VERSION 5.8 ;
BUSBITCHARS "[]" ;
DIVIDERCHAR "/" ;
UNITS
    DATABASE MICRONS 1000 ;
END UNITS

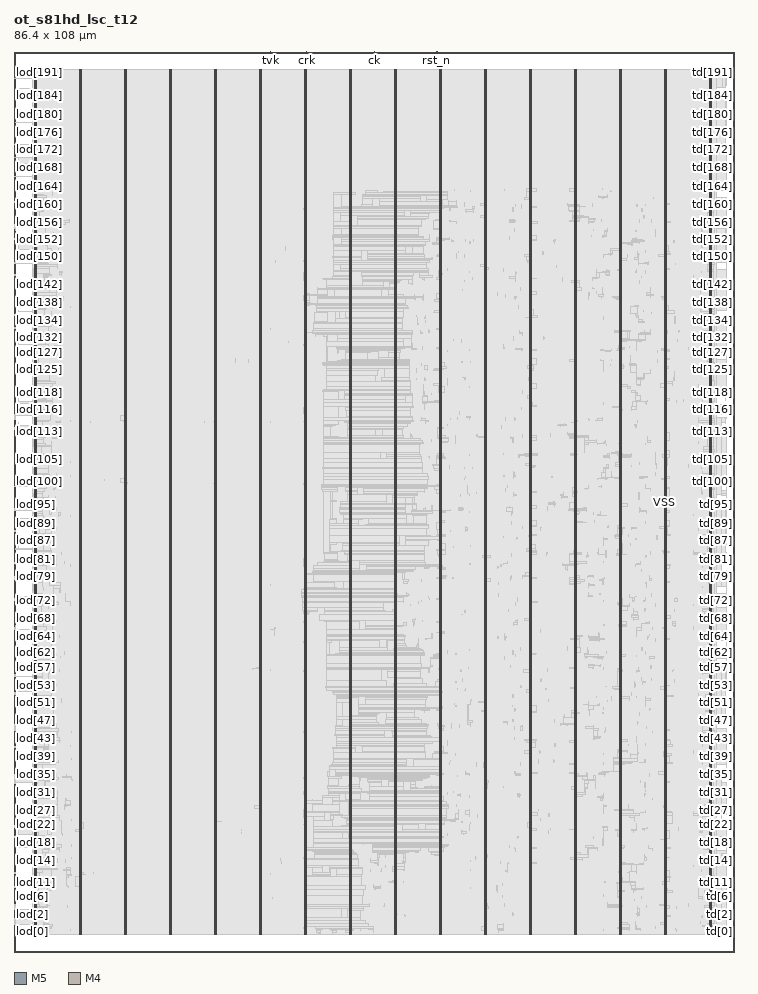
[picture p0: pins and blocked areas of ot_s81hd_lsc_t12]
MACRO ot_s81hd_lsc_t12
  FOREIGN ot_s81hd_lsc_t12 0 0 ;
  CLASS BLOCK ;
  SIZE 86.4 BY 108 ;
  PIN ck
    DIRECTION INPUT ;
    USE SIGNAL ;
    PORT
      LAYER M5 ;
        RECT  43.2 107.916 43.224 108 ;
    END
  END ck
  PIN crk
    DIRECTION INPUT ;
    USE SIGNAL ;
    PORT
      LAYER M5 ;
        RECT  35.088 107.916 35.112 108 ;
    END
  END crk
  PIN lod[0]
    DIRECTION OUTPUT ;
    USE SIGNAL ;
    PORT
      LAYER M4 ;
        RECT  0 2.4 0.084 2.424 ;
    END
  END lod[0]
  PIN lod[100]
    DIRECTION OUTPUT ;
    USE SIGNAL ;
    PORT
      LAYER M4 ;
        RECT  0 56.4 0.084 56.424 ;
    END
  END lod[100]
  PIN lod[101]
    DIRECTION OUTPUT ;
    USE SIGNAL ;
    PORT
      LAYER M4 ;
        RECT  0 56.976 0.084 57 ;
    END
  END lod[101]
  PIN lod[102]
    DIRECTION OUTPUT ;
    USE SIGNAL ;
    PORT
      LAYER M4 ;
        RECT  0 57.504 0.084 57.528 ;
    END
  END lod[102]
  PIN lod[103]
    DIRECTION OUTPUT ;
    USE SIGNAL ;
    PORT
      LAYER M4 ;
        RECT  0 58.032 0.084 58.056 ;
    END
  END lod[103]
  PIN lod[104]
    DIRECTION OUTPUT ;
    USE SIGNAL ;
    PORT
      LAYER M4 ;
        RECT  0 58.56 0.084 58.584 ;
    END
  END lod[104]
  PIN lod[105]
    DIRECTION OUTPUT ;
    USE SIGNAL ;
    PORT
      LAYER M4 ;
        RECT  0 59.136 0.084 59.16 ;
    END
  END lod[105]
  PIN lod[106]
    DIRECTION OUTPUT ;
    USE SIGNAL ;
    PORT
      LAYER M4 ;
        RECT  0 59.664 0.084 59.688 ;
    END
  END lod[106]
  PIN lod[107]
    DIRECTION OUTPUT ;
    USE SIGNAL ;
    PORT
      LAYER M4 ;
        RECT  0 60.192 0.084 60.216 ;
    END
  END lod[107]
  PIN lod[108]
    DIRECTION OUTPUT ;
    USE SIGNAL ;
    PORT
      LAYER M4 ;
        RECT  0 60.72 0.084 60.744 ;
    END
  END lod[108]
  PIN lod[109]
    DIRECTION OUTPUT ;
    USE SIGNAL ;
    PORT
      LAYER M4 ;
        RECT  0 61.296 0.084 61.32 ;
    END
  END lod[109]
  PIN lod[10]
    DIRECTION OUTPUT ;
    USE SIGNAL ;
    PORT
      LAYER M4 ;
        RECT  0 7.824 0.084 7.848 ;
    END
  END lod[10]
  PIN lod[110]
    DIRECTION OUTPUT ;
    USE SIGNAL ;
    PORT
      LAYER M4 ;
        RECT  0 61.824 0.084 61.848 ;
    END
  END lod[110]
  PIN lod[111]
    DIRECTION OUTPUT ;
    USE SIGNAL ;
    PORT
      LAYER M4 ;
        RECT  0 62.352 0.084 62.376 ;
    END
  END lod[111]
  PIN lod[112]
    DIRECTION OUTPUT ;
    USE SIGNAL ;
    PORT
      LAYER M4 ;
        RECT  0 62.88 0.084 62.904 ;
    END
  END lod[112]
  PIN lod[113]
    DIRECTION OUTPUT ;
    USE SIGNAL ;
    PORT
      LAYER M4 ;
        RECT  0 63.456 0.084 63.48 ;
    END
  END lod[113]
  PIN lod[114]
    DIRECTION OUTPUT ;
    USE SIGNAL ;
    PORT
      LAYER M4 ;
        RECT  0 63.984 0.084 64.008 ;
    END
  END lod[114]
  PIN lod[115]
    DIRECTION OUTPUT ;
    USE SIGNAL ;
    PORT
      LAYER M4 ;
        RECT  0 64.512 0.084 64.536 ;
    END
  END lod[115]
  PIN lod[116]
    DIRECTION OUTPUT ;
    USE SIGNAL ;
    PORT
      LAYER M4 ;
        RECT  0 65.04 0.084 65.064 ;
    END
  END lod[116]
  PIN lod[117]
    DIRECTION OUTPUT ;
    USE SIGNAL ;
    PORT
      LAYER M4 ;
        RECT  0 65.616 0.084 65.64 ;
    END
  END lod[117]
  PIN lod[118]
    DIRECTION OUTPUT ;
    USE SIGNAL ;
    PORT
      LAYER M4 ;
        RECT  0 66.144 0.084 66.168 ;
    END
  END lod[118]
  PIN lod[119]
    DIRECTION OUTPUT ;
    USE SIGNAL ;
    PORT
      LAYER M4 ;
        RECT  0 66.672 0.084 66.696 ;
    END
  END lod[119]
  PIN lod[11]
    DIRECTION OUTPUT ;
    USE SIGNAL ;
    PORT
      LAYER M4 ;
        RECT  0 8.352 0.084 8.376 ;
    END
  END lod[11]
  PIN lod[120]
    DIRECTION OUTPUT ;
    USE SIGNAL ;
    PORT
      LAYER M4 ;
        RECT  0 67.2 0.084 67.224 ;
    END
  END lod[120]
  PIN lod[121]
    DIRECTION OUTPUT ;
    USE SIGNAL ;
    PORT
      LAYER M4 ;
        RECT  0 67.776 0.084 67.8 ;
    END
  END lod[121]
  PIN lod[122]
    DIRECTION OUTPUT ;
    USE SIGNAL ;
    PORT
      LAYER M4 ;
        RECT  0 68.304 0.084 68.328 ;
    END
  END lod[122]
  PIN lod[123]
    DIRECTION OUTPUT ;
    USE SIGNAL ;
    PORT
      LAYER M4 ;
        RECT  0 68.832 0.084 68.856 ;
    END
  END lod[123]
  PIN lod[124]
    DIRECTION OUTPUT ;
    USE SIGNAL ;
    PORT
      LAYER M4 ;
        RECT  0 69.36 0.084 69.384 ;
    END
  END lod[124]
  PIN lod[125]
    DIRECTION OUTPUT ;
    USE SIGNAL ;
    PORT
      LAYER M4 ;
        RECT  0 69.936 0.084 69.96 ;
    END
  END lod[125]
  PIN lod[126]
    DIRECTION OUTPUT ;
    USE SIGNAL ;
    PORT
      LAYER M4 ;
        RECT  0 70.464 0.084 70.488 ;
    END
  END lod[126]
  PIN lod[127]
    DIRECTION OUTPUT ;
    USE SIGNAL ;
    PORT
      LAYER M4 ;
        RECT  0 70.992 0.084 71.016 ;
    END
  END lod[127]
  PIN lod[128]
    DIRECTION OUTPUT ;
    USE SIGNAL ;
    PORT
      LAYER M4 ;
        RECT  0 71.52 0.084 71.544 ;
    END
  END lod[128]
  PIN lod[129]
    DIRECTION OUTPUT ;
    USE SIGNAL ;
    PORT
      LAYER M4 ;
        RECT  0 72.096 0.084 72.12 ;
    END
  END lod[129]
  PIN lod[12]
    DIRECTION OUTPUT ;
    USE SIGNAL ;
    PORT
      LAYER M4 ;
        RECT  0 8.88 0.084 8.904 ;
    END
  END lod[12]
  PIN lod[130]
    DIRECTION OUTPUT ;
    USE SIGNAL ;
    PORT
      LAYER M4 ;
        RECT  0 72.624 0.084 72.648 ;
    END
  END lod[130]
  PIN lod[131]
    DIRECTION OUTPUT ;
    USE SIGNAL ;
    PORT
      LAYER M4 ;
        RECT  0 73.152 0.084 73.176 ;
    END
  END lod[131]
  PIN lod[132]
    DIRECTION OUTPUT ;
    USE SIGNAL ;
    PORT
      LAYER M4 ;
        RECT  0 73.68 0.084 73.704 ;
    END
  END lod[132]
  PIN lod[133]
    DIRECTION OUTPUT ;
    USE SIGNAL ;
    PORT
      LAYER M4 ;
        RECT  0 74.256 0.084 74.28 ;
    END
  END lod[133]
  PIN lod[134]
    DIRECTION OUTPUT ;
    USE SIGNAL ;
    PORT
      LAYER M4 ;
        RECT  0 74.784 0.084 74.808 ;
    END
  END lod[134]
  PIN lod[135]
    DIRECTION OUTPUT ;
    USE SIGNAL ;
    PORT
      LAYER M4 ;
        RECT  0 75.312 0.084 75.336 ;
    END
  END lod[135]
  PIN lod[136]
    DIRECTION OUTPUT ;
    USE SIGNAL ;
    PORT
      LAYER M4 ;
        RECT  0 75.84 0.084 75.864 ;
    END
  END lod[136]
  PIN lod[137]
    DIRECTION OUTPUT ;
    USE SIGNAL ;
    PORT
      LAYER M4 ;
        RECT  0 76.416 0.084 76.44 ;
    END
  END lod[137]
  PIN lod[138]
    DIRECTION OUTPUT ;
    USE SIGNAL ;
    PORT
      LAYER M4 ;
        RECT  0 76.944 0.084 76.968 ;
    END
  END lod[138]
  PIN lod[139]
    DIRECTION OUTPUT ;
    USE SIGNAL ;
    PORT
      LAYER M4 ;
        RECT  0 77.472 0.084 77.496 ;
    END
  END lod[139]
  PIN lod[13]
    DIRECTION OUTPUT ;
    USE SIGNAL ;
    PORT
      LAYER M4 ;
        RECT  0 9.456 0.084 9.48 ;
    END
  END lod[13]
  PIN lod[140]
    DIRECTION OUTPUT ;
    USE SIGNAL ;
    PORT
      LAYER M4 ;
        RECT  0 78 0.084 78.024 ;
    END
  END lod[140]
  PIN lod[141]
    DIRECTION OUTPUT ;
    USE SIGNAL ;
    PORT
      LAYER M4 ;
        RECT  0 78.576 0.084 78.6 ;
    END
  END lod[141]
  PIN lod[142]
    DIRECTION OUTPUT ;
    USE SIGNAL ;
    PORT
      LAYER M4 ;
        RECT  0 79.104 0.084 79.128 ;
    END
  END lod[142]
  PIN lod[143]
    DIRECTION OUTPUT ;
    USE SIGNAL ;
    PORT
      LAYER M4 ;
        RECT  0 79.632 0.084 79.656 ;
    END
  END lod[143]
  PIN lod[144]
    DIRECTION OUTPUT ;
    USE SIGNAL ;
    PORT
      LAYER M4 ;
        RECT  0 80.16 0.084 80.184 ;
    END
  END lod[144]
  PIN lod[145]
    DIRECTION OUTPUT ;
    USE SIGNAL ;
    PORT
      LAYER M4 ;
        RECT  0 80.736 0.084 80.76 ;
    END
  END lod[145]
  PIN lod[146]
    DIRECTION OUTPUT ;
    USE SIGNAL ;
    PORT
      LAYER M4 ;
        RECT  0 81.264 0.084 81.288 ;
    END
  END lod[146]
  PIN lod[147]
    DIRECTION OUTPUT ;
    USE SIGNAL ;
    PORT
      LAYER M4 ;
        RECT  0 81.792 0.084 81.816 ;
    END
  END lod[147]
  PIN lod[148]
    DIRECTION OUTPUT ;
    USE SIGNAL ;
    PORT
      LAYER M4 ;
        RECT  0 82.32 0.084 82.344 ;
    END
  END lod[148]
  PIN lod[149]
    DIRECTION OUTPUT ;
    USE SIGNAL ;
    PORT
      LAYER M4 ;
        RECT  0 82.896 0.084 82.92 ;
    END
  END lod[149]
  PIN lod[14]
    DIRECTION OUTPUT ;
    USE SIGNAL ;
    PORT
      LAYER M4 ;
        RECT  0 9.984 0.084 10.008 ;
    END
  END lod[14]
  PIN lod[150]
    DIRECTION OUTPUT ;
    USE SIGNAL ;
    PORT
      LAYER M4 ;
        RECT  0 83.424 0.084 83.448 ;
    END
  END lod[150]
  PIN lod[151]
    DIRECTION OUTPUT ;
    USE SIGNAL ;
    PORT
      LAYER M4 ;
        RECT  0 83.952 0.084 83.976 ;
    END
  END lod[151]
  PIN lod[152]
    DIRECTION OUTPUT ;
    USE SIGNAL ;
    PORT
      LAYER M4 ;
        RECT  0 84.48 0.084 84.504 ;
    END
  END lod[152]
  PIN lod[153]
    DIRECTION OUTPUT ;
    USE SIGNAL ;
    PORT
      LAYER M4 ;
        RECT  0 85.056 0.084 85.08 ;
    END
  END lod[153]
  PIN lod[154]
    DIRECTION OUTPUT ;
    USE SIGNAL ;
    PORT
      LAYER M4 ;
        RECT  0 85.584 0.084 85.608 ;
    END
  END lod[154]
  PIN lod[155]
    DIRECTION OUTPUT ;
    USE SIGNAL ;
    PORT
      LAYER M4 ;
        RECT  0 86.112 0.084 86.136 ;
    END
  END lod[155]
  PIN lod[156]
    DIRECTION OUTPUT ;
    USE SIGNAL ;
    PORT
      LAYER M4 ;
        RECT  0 86.64 0.084 86.664 ;
    END
  END lod[156]
  PIN lod[157]
    DIRECTION OUTPUT ;
    USE SIGNAL ;
    PORT
      LAYER M4 ;
        RECT  0 87.216 0.084 87.24 ;
    END
  END lod[157]
  PIN lod[158]
    DIRECTION OUTPUT ;
    USE SIGNAL ;
    PORT
      LAYER M4 ;
        RECT  0 87.744 0.084 87.768 ;
    END
  END lod[158]
  PIN lod[159]
    DIRECTION OUTPUT ;
    USE SIGNAL ;
    PORT
      LAYER M4 ;
        RECT  0 88.272 0.084 88.296 ;
    END
  END lod[159]
  PIN lod[15]
    DIRECTION OUTPUT ;
    USE SIGNAL ;
    PORT
      LAYER M4 ;
        RECT  0 10.512 0.084 10.536 ;
    END
  END lod[15]
  PIN lod[160]
    DIRECTION OUTPUT ;
    USE SIGNAL ;
    PORT
      LAYER M4 ;
        RECT  0 88.8 0.084 88.824 ;
    END
  END lod[160]
  PIN lod[161]
    DIRECTION OUTPUT ;
    USE SIGNAL ;
    PORT
      LAYER M4 ;
        RECT  0 89.376 0.084 89.4 ;
    END
  END lod[161]
  PIN lod[162]
    DIRECTION OUTPUT ;
    USE SIGNAL ;
    PORT
      LAYER M4 ;
        RECT  0 89.904 0.084 89.928 ;
    END
  END lod[162]
  PIN lod[163]
    DIRECTION OUTPUT ;
    USE SIGNAL ;
    PORT
      LAYER M4 ;
        RECT  0 90.432 0.084 90.456 ;
    END
  END lod[163]
  PIN lod[164]
    DIRECTION OUTPUT ;
    USE SIGNAL ;
    PORT
      LAYER M4 ;
        RECT  0 90.96 0.084 90.984 ;
    END
  END lod[164]
  PIN lod[165]
    DIRECTION OUTPUT ;
    USE SIGNAL ;
    PORT
      LAYER M4 ;
        RECT  0 91.536 0.084 91.56 ;
    END
  END lod[165]
  PIN lod[166]
    DIRECTION OUTPUT ;
    USE SIGNAL ;
    PORT
      LAYER M4 ;
        RECT  0 92.064 0.084 92.088 ;
    END
  END lod[166]
  PIN lod[167]
    DIRECTION OUTPUT ;
    USE SIGNAL ;
    PORT
      LAYER M4 ;
        RECT  0 92.592 0.084 92.616 ;
    END
  END lod[167]
  PIN lod[168]
    DIRECTION OUTPUT ;
    USE SIGNAL ;
    PORT
      LAYER M4 ;
        RECT  0 93.12 0.084 93.144 ;
    END
  END lod[168]
  PIN lod[169]
    DIRECTION OUTPUT ;
    USE SIGNAL ;
    PORT
      LAYER M4 ;
        RECT  0 93.696 0.084 93.72 ;
    END
  END lod[169]
  PIN lod[16]
    DIRECTION OUTPUT ;
    USE SIGNAL ;
    PORT
      LAYER M4 ;
        RECT  0 11.04 0.084 11.064 ;
    END
  END lod[16]
  PIN lod[170]
    DIRECTION OUTPUT ;
    USE SIGNAL ;
    PORT
      LAYER M4 ;
        RECT  0 94.224 0.084 94.248 ;
    END
  END lod[170]
  PIN lod[171]
    DIRECTION OUTPUT ;
    USE SIGNAL ;
    PORT
      LAYER M4 ;
        RECT  0 94.752 0.084 94.776 ;
    END
  END lod[171]
  PIN lod[172]
    DIRECTION OUTPUT ;
    USE SIGNAL ;
    PORT
      LAYER M4 ;
        RECT  0 95.28 0.084 95.304 ;
    END
  END lod[172]
  PIN lod[173]
    DIRECTION OUTPUT ;
    USE SIGNAL ;
    PORT
      LAYER M4 ;
        RECT  0 95.856 0.084 95.88 ;
    END
  END lod[173]
  PIN lod[174]
    DIRECTION OUTPUT ;
    USE SIGNAL ;
    PORT
      LAYER M4 ;
        RECT  0 96.384 0.084 96.408 ;
    END
  END lod[174]
  PIN lod[175]
    DIRECTION OUTPUT ;
    USE SIGNAL ;
    PORT
      LAYER M4 ;
        RECT  0 96.912 0.084 96.936 ;
    END
  END lod[175]
  PIN lod[176]
    DIRECTION OUTPUT ;
    USE SIGNAL ;
    PORT
      LAYER M4 ;
        RECT  0 97.44 0.084 97.464 ;
    END
  END lod[176]
  PIN lod[177]
    DIRECTION OUTPUT ;
    USE SIGNAL ;
    PORT
      LAYER M4 ;
        RECT  0 98.016 0.084 98.04 ;
    END
  END lod[177]
  PIN lod[178]
    DIRECTION OUTPUT ;
    USE SIGNAL ;
    PORT
      LAYER M4 ;
        RECT  0 98.544 0.084 98.568 ;
    END
  END lod[178]
  PIN lod[179]
    DIRECTION OUTPUT ;
    USE SIGNAL ;
    PORT
      LAYER M4 ;
        RECT  0 99.072 0.084 99.096 ;
    END
  END lod[179]
  PIN lod[17]
    DIRECTION OUTPUT ;
    USE SIGNAL ;
    PORT
      LAYER M4 ;
        RECT  0 11.616 0.084 11.64 ;
    END
  END lod[17]
  PIN lod[180]
    DIRECTION OUTPUT ;
    USE SIGNAL ;
    PORT
      LAYER M4 ;
        RECT  0 99.6 0.084 99.624 ;
    END
  END lod[180]
  PIN lod[181]
    DIRECTION OUTPUT ;
    USE SIGNAL ;
    PORT
      LAYER M4 ;
        RECT  0 100.176 0.084 100.2 ;
    END
  END lod[181]
  PIN lod[182]
    DIRECTION OUTPUT ;
    USE SIGNAL ;
    PORT
      LAYER M4 ;
        RECT  0 100.704 0.084 100.728 ;
    END
  END lod[182]
  PIN lod[183]
    DIRECTION OUTPUT ;
    USE SIGNAL ;
    PORT
      LAYER M4 ;
        RECT  0 101.232 0.084 101.256 ;
    END
  END lod[183]
  PIN lod[184]
    DIRECTION OUTPUT ;
    USE SIGNAL ;
    PORT
      LAYER M4 ;
        RECT  0 101.76 0.084 101.784 ;
    END
  END lod[184]
  PIN lod[185]
    DIRECTION OUTPUT ;
    USE SIGNAL ;
    PORT
      LAYER M4 ;
        RECT  0 102.336 0.084 102.36 ;
    END
  END lod[185]
  PIN lod[186]
    DIRECTION OUTPUT ;
    USE SIGNAL ;
    PORT
      LAYER M4 ;
        RECT  0 102.864 0.084 102.888 ;
    END
  END lod[186]
  PIN lod[187]
    DIRECTION OUTPUT ;
    USE SIGNAL ;
    PORT
      LAYER M4 ;
        RECT  0 103.392 0.084 103.416 ;
    END
  END lod[187]
  PIN lod[188]
    DIRECTION OUTPUT ;
    USE SIGNAL ;
    PORT
      LAYER M4 ;
        RECT  0 103.92 0.084 103.944 ;
    END
  END lod[188]
  PIN lod[189]
    DIRECTION OUTPUT ;
    USE SIGNAL ;
    PORT
      LAYER M4 ;
        RECT  0 104.496 0.084 104.52 ;
    END
  END lod[189]
  PIN lod[18]
    DIRECTION OUTPUT ;
    USE SIGNAL ;
    PORT
      LAYER M4 ;
        RECT  0 12.144 0.084 12.168 ;
    END
  END lod[18]
  PIN lod[190]
    DIRECTION OUTPUT ;
    USE SIGNAL ;
    PORT
      LAYER M4 ;
        RECT  0 105.024 0.084 105.048 ;
    END
  END lod[190]
  PIN lod[191]
    DIRECTION OUTPUT ;
    USE SIGNAL ;
    PORT
      LAYER M4 ;
        RECT  0 105.552 0.084 105.576 ;
    END
  END lod[191]
  PIN lod[19]
    DIRECTION OUTPUT ;
    USE SIGNAL ;
    PORT
      LAYER M4 ;
        RECT  0 12.672 0.084 12.696 ;
    END
  END lod[19]
  PIN lod[1]
    DIRECTION OUTPUT ;
    USE SIGNAL ;
    PORT
      LAYER M4 ;
        RECT  0 2.976 0.084 3 ;
    END
  END lod[1]
  PIN lod[20]
    DIRECTION OUTPUT ;
    USE SIGNAL ;
    PORT
      LAYER M4 ;
        RECT  0 13.2 0.084 13.224 ;
    END
  END lod[20]
  PIN lod[21]
    DIRECTION OUTPUT ;
    USE SIGNAL ;
    PORT
      LAYER M4 ;
        RECT  0 13.776 0.084 13.8 ;
    END
  END lod[21]
  PIN lod[22]
    DIRECTION OUTPUT ;
    USE SIGNAL ;
    PORT
      LAYER M4 ;
        RECT  0 14.304 0.084 14.328 ;
    END
  END lod[22]
  PIN lod[23]
    DIRECTION OUTPUT ;
    USE SIGNAL ;
    PORT
      LAYER M4 ;
        RECT  0 14.832 0.084 14.856 ;
    END
  END lod[23]
  PIN lod[24]
    DIRECTION OUTPUT ;
    USE SIGNAL ;
    PORT
      LAYER M4 ;
        RECT  0 15.36 0.084 15.384 ;
    END
  END lod[24]
  PIN lod[25]
    DIRECTION OUTPUT ;
    USE SIGNAL ;
    PORT
      LAYER M4 ;
        RECT  0 15.936 0.084 15.96 ;
    END
  END lod[25]
  PIN lod[26]
    DIRECTION OUTPUT ;
    USE SIGNAL ;
    PORT
      LAYER M4 ;
        RECT  0 16.464 0.084 16.488 ;
    END
  END lod[26]
  PIN lod[27]
    DIRECTION OUTPUT ;
    USE SIGNAL ;
    PORT
      LAYER M4 ;
        RECT  0 16.992 0.084 17.016 ;
    END
  END lod[27]
  PIN lod[28]
    DIRECTION OUTPUT ;
    USE SIGNAL ;
    PORT
      LAYER M4 ;
        RECT  0 17.52 0.084 17.544 ;
    END
  END lod[28]
  PIN lod[29]
    DIRECTION OUTPUT ;
    USE SIGNAL ;
    PORT
      LAYER M4 ;
        RECT  0 18.096 0.084 18.12 ;
    END
  END lod[29]
  PIN lod[2]
    DIRECTION OUTPUT ;
    USE SIGNAL ;
    PORT
      LAYER M4 ;
        RECT  0 3.504 0.084 3.528 ;
    END
  END lod[2]
  PIN lod[30]
    DIRECTION OUTPUT ;
    USE SIGNAL ;
    PORT
      LAYER M4 ;
        RECT  0 18.624 0.084 18.648 ;
    END
  END lod[30]
  PIN lod[31]
    DIRECTION OUTPUT ;
    USE SIGNAL ;
    PORT
      LAYER M4 ;
        RECT  0 19.152 0.084 19.176 ;
    END
  END lod[31]
  PIN lod[32]
    DIRECTION OUTPUT ;
    USE SIGNAL ;
    PORT
      LAYER M4 ;
        RECT  0 19.68 0.084 19.704 ;
    END
  END lod[32]
  PIN lod[33]
    DIRECTION OUTPUT ;
    USE SIGNAL ;
    PORT
      LAYER M4 ;
        RECT  0 20.256 0.084 20.28 ;
    END
  END lod[33]
  PIN lod[34]
    DIRECTION OUTPUT ;
    USE SIGNAL ;
    PORT
      LAYER M4 ;
        RECT  0 20.784 0.084 20.808 ;
    END
  END lod[34]
  PIN lod[35]
    DIRECTION OUTPUT ;
    USE SIGNAL ;
    PORT
      LAYER M4 ;
        RECT  0 21.312 0.084 21.336 ;
    END
  END lod[35]
  PIN lod[36]
    DIRECTION OUTPUT ;
    USE SIGNAL ;
    PORT
      LAYER M4 ;
        RECT  0 21.84 0.084 21.864 ;
    END
  END lod[36]
  PIN lod[37]
    DIRECTION OUTPUT ;
    USE SIGNAL ;
    PORT
      LAYER M4 ;
        RECT  0 22.416 0.084 22.44 ;
    END
  END lod[37]
  PIN lod[38]
    DIRECTION OUTPUT ;
    USE SIGNAL ;
    PORT
      LAYER M4 ;
        RECT  0 22.944 0.084 22.968 ;
    END
  END lod[38]
  PIN lod[39]
    DIRECTION OUTPUT ;
    USE SIGNAL ;
    PORT
      LAYER M4 ;
        RECT  0 23.472 0.084 23.496 ;
    END
  END lod[39]
  PIN lod[3]
    DIRECTION OUTPUT ;
    USE SIGNAL ;
    PORT
      LAYER M4 ;
        RECT  0 4.032 0.084 4.056 ;
    END
  END lod[3]
  PIN lod[40]
    DIRECTION OUTPUT ;
    USE SIGNAL ;
    PORT
      LAYER M4 ;
        RECT  0 24 0.084 24.024 ;
    END
  END lod[40]
  PIN lod[41]
    DIRECTION OUTPUT ;
    USE SIGNAL ;
    PORT
      LAYER M4 ;
        RECT  0 24.576 0.084 24.6 ;
    END
  END lod[41]
  PIN lod[42]
    DIRECTION OUTPUT ;
    USE SIGNAL ;
    PORT
      LAYER M4 ;
        RECT  0 25.104 0.084 25.128 ;
    END
  END lod[42]
  PIN lod[43]
    DIRECTION OUTPUT ;
    USE SIGNAL ;
    PORT
      LAYER M4 ;
        RECT  0 25.632 0.084 25.656 ;
    END
  END lod[43]
  PIN lod[44]
    DIRECTION OUTPUT ;
    USE SIGNAL ;
    PORT
      LAYER M4 ;
        RECT  0 26.16 0.084 26.184 ;
    END
  END lod[44]
  PIN lod[45]
    DIRECTION OUTPUT ;
    USE SIGNAL ;
    PORT
      LAYER M4 ;
        RECT  0 26.736 0.084 26.76 ;
    END
  END lod[45]
  PIN lod[46]
    DIRECTION OUTPUT ;
    USE SIGNAL ;
    PORT
      LAYER M4 ;
        RECT  0 27.264 0.084 27.288 ;
    END
  END lod[46]
  PIN lod[47]
    DIRECTION OUTPUT ;
    USE SIGNAL ;
    PORT
      LAYER M4 ;
        RECT  0 27.792 0.084 27.816 ;
    END
  END lod[47]
  PIN lod[48]
    DIRECTION OUTPUT ;
    USE SIGNAL ;
    PORT
      LAYER M4 ;
        RECT  0 28.32 0.084 28.344 ;
    END
  END lod[48]
  PIN lod[49]
    DIRECTION OUTPUT ;
    USE SIGNAL ;
    PORT
      LAYER M4 ;
        RECT  0 28.896 0.084 28.92 ;
    END
  END lod[49]
  PIN lod[4]
    DIRECTION OUTPUT ;
    USE SIGNAL ;
    PORT
      LAYER M4 ;
        RECT  0 4.56 0.084 4.584 ;
    END
  END lod[4]
  PIN lod[50]
    DIRECTION OUTPUT ;
    USE SIGNAL ;
    PORT
      LAYER M4 ;
        RECT  0 29.424 0.084 29.448 ;
    END
  END lod[50]
  PIN lod[51]
    DIRECTION OUTPUT ;
    USE SIGNAL ;
    PORT
      LAYER M4 ;
        RECT  0 29.952 0.084 29.976 ;
    END
  END lod[51]
  PIN lod[52]
    DIRECTION OUTPUT ;
    USE SIGNAL ;
    PORT
      LAYER M4 ;
        RECT  0 30.48 0.084 30.504 ;
    END
  END lod[52]
  PIN lod[53]
    DIRECTION OUTPUT ;
    USE SIGNAL ;
    PORT
      LAYER M4 ;
        RECT  0 31.056 0.084 31.08 ;
    END
  END lod[53]
  PIN lod[54]
    DIRECTION OUTPUT ;
    USE SIGNAL ;
    PORT
      LAYER M4 ;
        RECT  0 31.584 0.084 31.608 ;
    END
  END lod[54]
  PIN lod[55]
    DIRECTION OUTPUT ;
    USE SIGNAL ;
    PORT
      LAYER M4 ;
        RECT  0 32.112 0.084 32.136 ;
    END
  END lod[55]
  PIN lod[56]
    DIRECTION OUTPUT ;
    USE SIGNAL ;
    PORT
      LAYER M4 ;
        RECT  0 32.64 0.084 32.664 ;
    END
  END lod[56]
  PIN lod[57]
    DIRECTION OUTPUT ;
    USE SIGNAL ;
    PORT
      LAYER M4 ;
        RECT  0 33.216 0.084 33.24 ;
    END
  END lod[57]
  PIN lod[58]
    DIRECTION OUTPUT ;
    USE SIGNAL ;
    PORT
      LAYER M4 ;
        RECT  0 33.744 0.084 33.768 ;
    END
  END lod[58]
  PIN lod[59]
    DIRECTION OUTPUT ;
    USE SIGNAL ;
    PORT
      LAYER M4 ;
        RECT  0 34.272 0.084 34.296 ;
    END
  END lod[59]
  PIN lod[5]
    DIRECTION OUTPUT ;
    USE SIGNAL ;
    PORT
      LAYER M4 ;
        RECT  0 5.136 0.084 5.16 ;
    END
  END lod[5]
  PIN lod[60]
    DIRECTION OUTPUT ;
    USE SIGNAL ;
    PORT
      LAYER M4 ;
        RECT  0 34.8 0.084 34.824 ;
    END
  END lod[60]
  PIN lod[61]
    DIRECTION OUTPUT ;
    USE SIGNAL ;
    PORT
      LAYER M4 ;
        RECT  0 35.376 0.084 35.4 ;
    END
  END lod[61]
  PIN lod[62]
    DIRECTION OUTPUT ;
    USE SIGNAL ;
    PORT
      LAYER M4 ;
        RECT  0 35.904 0.084 35.928 ;
    END
  END lod[62]
  PIN lod[63]
    DIRECTION OUTPUT ;
    USE SIGNAL ;
    PORT
      LAYER M4 ;
        RECT  0 36.432 0.084 36.456 ;
    END
  END lod[63]
  PIN lod[64]
    DIRECTION OUTPUT ;
    USE SIGNAL ;
    PORT
      LAYER M4 ;
        RECT  0 36.96 0.084 36.984 ;
    END
  END lod[64]
  PIN lod[65]
    DIRECTION OUTPUT ;
    USE SIGNAL ;
    PORT
      LAYER M4 ;
        RECT  0 37.536 0.084 37.56 ;
    END
  END lod[65]
  PIN lod[66]
    DIRECTION OUTPUT ;
    USE SIGNAL ;
    PORT
      LAYER M4 ;
        RECT  0 38.064 0.084 38.088 ;
    END
  END lod[66]
  PIN lod[67]
    DIRECTION OUTPUT ;
    USE SIGNAL ;
    PORT
      LAYER M4 ;
        RECT  0 38.592 0.084 38.616 ;
    END
  END lod[67]
  PIN lod[68]
    DIRECTION OUTPUT ;
    USE SIGNAL ;
    PORT
      LAYER M4 ;
        RECT  0 39.12 0.084 39.144 ;
    END
  END lod[68]
  PIN lod[69]
    DIRECTION OUTPUT ;
    USE SIGNAL ;
    PORT
      LAYER M4 ;
        RECT  0 39.696 0.084 39.72 ;
    END
  END lod[69]
  PIN lod[6]
    DIRECTION OUTPUT ;
    USE SIGNAL ;
    PORT
      LAYER M4 ;
        RECT  0 5.664 0.084 5.688 ;
    END
  END lod[6]
  PIN lod[70]
    DIRECTION OUTPUT ;
    USE SIGNAL ;
    PORT
      LAYER M4 ;
        RECT  0 40.224 0.084 40.248 ;
    END
  END lod[70]
  PIN lod[71]
    DIRECTION OUTPUT ;
    USE SIGNAL ;
    PORT
      LAYER M4 ;
        RECT  0 40.752 0.084 40.776 ;
    END
  END lod[71]
  PIN lod[72]
    DIRECTION OUTPUT ;
    USE SIGNAL ;
    PORT
      LAYER M4 ;
        RECT  0 41.28 0.084 41.304 ;
    END
  END lod[72]
  PIN lod[73]
    DIRECTION OUTPUT ;
    USE SIGNAL ;
    PORT
      LAYER M4 ;
        RECT  0 41.856 0.084 41.88 ;
    END
  END lod[73]
  PIN lod[74]
    DIRECTION OUTPUT ;
    USE SIGNAL ;
    PORT
      LAYER M4 ;
        RECT  0 42.384 0.084 42.408 ;
    END
  END lod[74]
  PIN lod[75]
    DIRECTION OUTPUT ;
    USE SIGNAL ;
    PORT
      LAYER M4 ;
        RECT  0 42.912 0.084 42.936 ;
    END
  END lod[75]
  PIN lod[76]
    DIRECTION OUTPUT ;
    USE SIGNAL ;
    PORT
      LAYER M4 ;
        RECT  0 43.44 0.084 43.464 ;
    END
  END lod[76]
  PIN lod[77]
    DIRECTION OUTPUT ;
    USE SIGNAL ;
    PORT
      LAYER M4 ;
        RECT  0 44.016 0.084 44.04 ;
    END
  END lod[77]
  PIN lod[78]
    DIRECTION OUTPUT ;
    USE SIGNAL ;
    PORT
      LAYER M4 ;
        RECT  0 44.544 0.084 44.568 ;
    END
  END lod[78]
  PIN lod[79]
    DIRECTION OUTPUT ;
    USE SIGNAL ;
    PORT
      LAYER M4 ;
        RECT  0 45.072 0.084 45.096 ;
    END
  END lod[79]
  PIN lod[7]
    DIRECTION OUTPUT ;
    USE SIGNAL ;
    PORT
      LAYER M4 ;
        RECT  0 6.192 0.084 6.216 ;
    END
  END lod[7]
  PIN lod[80]
    DIRECTION OUTPUT ;
    USE SIGNAL ;
    PORT
      LAYER M4 ;
        RECT  0 45.6 0.084 45.624 ;
    END
  END lod[80]
  PIN lod[81]
    DIRECTION OUTPUT ;
    USE SIGNAL ;
    PORT
      LAYER M4 ;
        RECT  0 46.176 0.084 46.2 ;
    END
  END lod[81]
  PIN lod[82]
    DIRECTION OUTPUT ;
    USE SIGNAL ;
    PORT
      LAYER M4 ;
        RECT  0 46.704 0.084 46.728 ;
    END
  END lod[82]
  PIN lod[83]
    DIRECTION OUTPUT ;
    USE SIGNAL ;
    PORT
      LAYER M4 ;
        RECT  0 47.232 0.084 47.256 ;
    END
  END lod[83]
  PIN lod[84]
    DIRECTION OUTPUT ;
    USE SIGNAL ;
    PORT
      LAYER M4 ;
        RECT  0 47.76 0.084 47.784 ;
    END
  END lod[84]
  PIN lod[85]
    DIRECTION OUTPUT ;
    USE SIGNAL ;
    PORT
      LAYER M4 ;
        RECT  0 48.336 0.084 48.36 ;
    END
  END lod[85]
  PIN lod[86]
    DIRECTION OUTPUT ;
    USE SIGNAL ;
    PORT
      LAYER M4 ;
        RECT  0 48.864 0.084 48.888 ;
    END
  END lod[86]
  PIN lod[87]
    DIRECTION OUTPUT ;
    USE SIGNAL ;
    PORT
      LAYER M4 ;
        RECT  0 49.392 0.084 49.416 ;
    END
  END lod[87]
  PIN lod[88]
    DIRECTION OUTPUT ;
    USE SIGNAL ;
    PORT
      LAYER M4 ;
        RECT  0 49.92 0.084 49.944 ;
    END
  END lod[88]
  PIN lod[89]
    DIRECTION OUTPUT ;
    USE SIGNAL ;
    PORT
      LAYER M4 ;
        RECT  0 50.496 0.084 50.52 ;
    END
  END lod[89]
  PIN lod[8]
    DIRECTION OUTPUT ;
    USE SIGNAL ;
    PORT
      LAYER M4 ;
        RECT  0 6.72 0.084 6.744 ;
    END
  END lod[8]
  PIN lod[90]
    DIRECTION OUTPUT ;
    USE SIGNAL ;
    PORT
      LAYER M4 ;
        RECT  0 51.024 0.084 51.048 ;
    END
  END lod[90]
  PIN lod[91]
    DIRECTION OUTPUT ;
    USE SIGNAL ;
    PORT
      LAYER M4 ;
        RECT  0 51.552 0.084 51.576 ;
    END
  END lod[91]
  PIN lod[92]
    DIRECTION OUTPUT ;
    USE SIGNAL ;
    PORT
      LAYER M4 ;
        RECT  0 52.08 0.084 52.104 ;
    END
  END lod[92]
  PIN lod[93]
    DIRECTION OUTPUT ;
    USE SIGNAL ;
    PORT
      LAYER M4 ;
        RECT  0 52.656 0.084 52.68 ;
    END
  END lod[93]
  PIN lod[94]
    DIRECTION OUTPUT ;
    USE SIGNAL ;
    PORT
      LAYER M4 ;
        RECT  0 53.184 0.084 53.208 ;
    END
  END lod[94]
  PIN lod[95]
    DIRECTION OUTPUT ;
    USE SIGNAL ;
    PORT
      LAYER M4 ;
        RECT  0 53.712 0.084 53.736 ;
    END
  END lod[95]
  PIN lod[96]
    DIRECTION OUTPUT ;
    USE SIGNAL ;
    PORT
      LAYER M4 ;
        RECT  0 54.24 0.084 54.264 ;
    END
  END lod[96]
  PIN lod[97]
    DIRECTION OUTPUT ;
    USE SIGNAL ;
    PORT
      LAYER M4 ;
        RECT  0 54.816 0.084 54.84 ;
    END
  END lod[97]
  PIN lod[98]
    DIRECTION OUTPUT ;
    USE SIGNAL ;
    PORT
      LAYER M4 ;
        RECT  0 55.344 0.084 55.368 ;
    END
  END lod[98]
  PIN lod[99]
    DIRECTION OUTPUT ;
    USE SIGNAL ;
    PORT
      LAYER M4 ;
        RECT  0 55.872 0.084 55.896 ;
    END
  END lod[99]
  PIN lod[9]
    DIRECTION OUTPUT ;
    USE SIGNAL ;
    PORT
      LAYER M4 ;
        RECT  0 7.296 0.084 7.32 ;
    END
  END lod[9]
  PIN rst_n
    DIRECTION INPUT ;
    USE SIGNAL ;
    PORT
      LAYER M5 ;
        RECT  50.736 107.916 50.76 108 ;
    END
  END rst_n
  PIN td[0]
    DIRECTION INPUT ;
    USE SIGNAL ;
    PORT
      LAYER M4 ;
        RECT  86.316 2.4 86.4 2.424 ;
    END
  END td[0]
  PIN td[100]
    DIRECTION INPUT ;
    USE SIGNAL ;
    PORT
      LAYER M4 ;
        RECT  86.316 56.4 86.4 56.424 ;
    END
  END td[100]
  PIN td[101]
    DIRECTION INPUT ;
    USE SIGNAL ;
    PORT
      LAYER M4 ;
        RECT  86.316 56.976 86.4 57 ;
    END
  END td[101]
  PIN td[102]
    DIRECTION INPUT ;
    USE SIGNAL ;
    PORT
      LAYER M4 ;
        RECT  86.316 57.504 86.4 57.528 ;
    END
  END td[102]
  PIN td[103]
    DIRECTION INPUT ;
    USE SIGNAL ;
    PORT
      LAYER M4 ;
        RECT  86.316 58.032 86.4 58.056 ;
    END
  END td[103]
  PIN td[104]
    DIRECTION INPUT ;
    USE SIGNAL ;
    PORT
      LAYER M4 ;
        RECT  86.316 58.56 86.4 58.584 ;
    END
  END td[104]
  PIN td[105]
    DIRECTION INPUT ;
    USE SIGNAL ;
    PORT
      LAYER M4 ;
        RECT  86.316 59.136 86.4 59.16 ;
    END
  END td[105]
  PIN td[106]
    DIRECTION INPUT ;
    USE SIGNAL ;
    PORT
      LAYER M4 ;
        RECT  86.316 59.664 86.4 59.688 ;
    END
  END td[106]
  PIN td[107]
    DIRECTION INPUT ;
    USE SIGNAL ;
    PORT
      LAYER M4 ;
        RECT  86.316 60.192 86.4 60.216 ;
    END
  END td[107]
  PIN td[108]
    DIRECTION INPUT ;
    USE SIGNAL ;
    PORT
      LAYER M4 ;
        RECT  86.316 60.72 86.4 60.744 ;
    END
  END td[108]
  PIN td[109]
    DIRECTION INPUT ;
    USE SIGNAL ;
    PORT
      LAYER M4 ;
        RECT  86.316 61.296 86.4 61.32 ;
    END
  END td[109]
  PIN td[10]
    DIRECTION INPUT ;
    USE SIGNAL ;
    PORT
      LAYER M4 ;
        RECT  86.316 7.824 86.4 7.848 ;
    END
  END td[10]
  PIN td[110]
    DIRECTION INPUT ;
    USE SIGNAL ;
    PORT
      LAYER M4 ;
        RECT  86.316 61.824 86.4 61.848 ;
    END
  END td[110]
  PIN td[111]
    DIRECTION INPUT ;
    USE SIGNAL ;
    PORT
      LAYER M4 ;
        RECT  86.316 62.352 86.4 62.376 ;
    END
  END td[111]
  PIN td[112]
    DIRECTION INPUT ;
    USE SIGNAL ;
    PORT
      LAYER M4 ;
        RECT  86.316 62.88 86.4 62.904 ;
    END
  END td[112]
  PIN td[113]
    DIRECTION INPUT ;
    USE SIGNAL ;
    PORT
      LAYER M4 ;
        RECT  86.316 63.456 86.4 63.48 ;
    END
  END td[113]
  PIN td[114]
    DIRECTION INPUT ;
    USE SIGNAL ;
    PORT
      LAYER M4 ;
        RECT  86.316 63.984 86.4 64.008 ;
    END
  END td[114]
  PIN td[115]
    DIRECTION INPUT ;
    USE SIGNAL ;
    PORT
      LAYER M4 ;
        RECT  86.316 64.512 86.4 64.536 ;
    END
  END td[115]
  PIN td[116]
    DIRECTION INPUT ;
    USE SIGNAL ;
    PORT
      LAYER M4 ;
        RECT  86.316 65.04 86.4 65.064 ;
    END
  END td[116]
  PIN td[117]
    DIRECTION INPUT ;
    USE SIGNAL ;
    PORT
      LAYER M4 ;
        RECT  86.316 65.616 86.4 65.64 ;
    END
  END td[117]
  PIN td[118]
    DIRECTION INPUT ;
    USE SIGNAL ;
    PORT
      LAYER M4 ;
        RECT  86.316 66.144 86.4 66.168 ;
    END
  END td[118]
  PIN td[119]
    DIRECTION INPUT ;
    USE SIGNAL ;
    PORT
      LAYER M4 ;
        RECT  86.316 66.672 86.4 66.696 ;
    END
  END td[119]
  PIN td[11]
    DIRECTION INPUT ;
    USE SIGNAL ;
    PORT
      LAYER M4 ;
        RECT  86.316 8.352 86.4 8.376 ;
    END
  END td[11]
  PIN td[120]
    DIRECTION INPUT ;
    USE SIGNAL ;
    PORT
      LAYER M4 ;
        RECT  86.316 67.2 86.4 67.224 ;
    END
  END td[120]
  PIN td[121]
    DIRECTION INPUT ;
    USE SIGNAL ;
    PORT
      LAYER M4 ;
        RECT  86.316 67.776 86.4 67.8 ;
    END
  END td[121]
  PIN td[122]
    DIRECTION INPUT ;
    USE SIGNAL ;
    PORT
      LAYER M4 ;
        RECT  86.316 68.304 86.4 68.328 ;
    END
  END td[122]
  PIN td[123]
    DIRECTION INPUT ;
    USE SIGNAL ;
    PORT
      LAYER M4 ;
        RECT  86.316 68.832 86.4 68.856 ;
    END
  END td[123]
  PIN td[124]
    DIRECTION INPUT ;
    USE SIGNAL ;
    PORT
      LAYER M4 ;
        RECT  86.316 69.36 86.4 69.384 ;
    END
  END td[124]
  PIN td[125]
    DIRECTION INPUT ;
    USE SIGNAL ;
    PORT
      LAYER M4 ;
        RECT  86.316 69.936 86.4 69.96 ;
    END
  END td[125]
  PIN td[126]
    DIRECTION INPUT ;
    USE SIGNAL ;
    PORT
      LAYER M4 ;
        RECT  86.316 70.464 86.4 70.488 ;
    END
  END td[126]
  PIN td[127]
    DIRECTION INPUT ;
    USE SIGNAL ;
    PORT
      LAYER M4 ;
        RECT  86.316 70.992 86.4 71.016 ;
    END
  END td[127]
  PIN td[128]
    DIRECTION INPUT ;
    USE SIGNAL ;
    PORT
      LAYER M4 ;
        RECT  86.316 71.52 86.4 71.544 ;
    END
  END td[128]
  PIN td[129]
    DIRECTION INPUT ;
    USE SIGNAL ;
    PORT
      LAYER M4 ;
        RECT  86.316 72.096 86.4 72.12 ;
    END
  END td[129]
  PIN td[12]
    DIRECTION INPUT ;
    USE SIGNAL ;
    PORT
      LAYER M4 ;
        RECT  86.316 8.88 86.4 8.904 ;
    END
  END td[12]
  PIN td[130]
    DIRECTION INPUT ;
    USE SIGNAL ;
    PORT
      LAYER M4 ;
        RECT  86.316 72.624 86.4 72.648 ;
    END
  END td[130]
  PIN td[131]
    DIRECTION INPUT ;
    USE SIGNAL ;
    PORT
      LAYER M4 ;
        RECT  86.316 73.152 86.4 73.176 ;
    END
  END td[131]
  PIN td[132]
    DIRECTION INPUT ;
    USE SIGNAL ;
    PORT
      LAYER M4 ;
        RECT  86.316 73.68 86.4 73.704 ;
    END
  END td[132]
  PIN td[133]
    DIRECTION INPUT ;
    USE SIGNAL ;
    PORT
      LAYER M4 ;
        RECT  86.316 74.256 86.4 74.28 ;
    END
  END td[133]
  PIN td[134]
    DIRECTION INPUT ;
    USE SIGNAL ;
    PORT
      LAYER M4 ;
        RECT  86.316 74.784 86.4 74.808 ;
    END
  END td[134]
  PIN td[135]
    DIRECTION INPUT ;
    USE SIGNAL ;
    PORT
      LAYER M4 ;
        RECT  86.316 75.312 86.4 75.336 ;
    END
  END td[135]
  PIN td[136]
    DIRECTION INPUT ;
    USE SIGNAL ;
    PORT
      LAYER M4 ;
        RECT  86.316 75.84 86.4 75.864 ;
    END
  END td[136]
  PIN td[137]
    DIRECTION INPUT ;
    USE SIGNAL ;
    PORT
      LAYER M4 ;
        RECT  86.316 76.416 86.4 76.44 ;
    END
  END td[137]
  PIN td[138]
    DIRECTION INPUT ;
    USE SIGNAL ;
    PORT
      LAYER M4 ;
        RECT  86.316 76.944 86.4 76.968 ;
    END
  END td[138]
  PIN td[139]
    DIRECTION INPUT ;
    USE SIGNAL ;
    PORT
      LAYER M4 ;
        RECT  86.316 77.472 86.4 77.496 ;
    END
  END td[139]
  PIN td[13]
    DIRECTION INPUT ;
    USE SIGNAL ;
    PORT
      LAYER M4 ;
        RECT  86.316 9.456 86.4 9.48 ;
    END
  END td[13]
  PIN td[140]
    DIRECTION INPUT ;
    USE SIGNAL ;
    PORT
      LAYER M4 ;
        RECT  86.316 78 86.4 78.024 ;
    END
  END td[140]
  PIN td[141]
    DIRECTION INPUT ;
    USE SIGNAL ;
    PORT
      LAYER M4 ;
        RECT  86.316 78.576 86.4 78.6 ;
    END
  END td[141]
  PIN td[142]
    DIRECTION INPUT ;
    USE SIGNAL ;
    PORT
      LAYER M4 ;
        RECT  86.316 79.104 86.4 79.128 ;
    END
  END td[142]
  PIN td[143]
    DIRECTION INPUT ;
    USE SIGNAL ;
    PORT
      LAYER M4 ;
        RECT  86.316 79.632 86.4 79.656 ;
    END
  END td[143]
  PIN td[144]
    DIRECTION INPUT ;
    USE SIGNAL ;
    PORT
      LAYER M4 ;
        RECT  86.316 80.16 86.4 80.184 ;
    END
  END td[144]
  PIN td[145]
    DIRECTION INPUT ;
    USE SIGNAL ;
    PORT
      LAYER M4 ;
        RECT  86.316 80.736 86.4 80.76 ;
    END
  END td[145]
  PIN td[146]
    DIRECTION INPUT ;
    USE SIGNAL ;
    PORT
      LAYER M4 ;
        RECT  86.316 81.264 86.4 81.288 ;
    END
  END td[146]
  PIN td[147]
    DIRECTION INPUT ;
    USE SIGNAL ;
    PORT
      LAYER M4 ;
        RECT  86.316 81.792 86.4 81.816 ;
    END
  END td[147]
  PIN td[148]
    DIRECTION INPUT ;
    USE SIGNAL ;
    PORT
      LAYER M4 ;
        RECT  86.316 82.32 86.4 82.344 ;
    END
  END td[148]
  PIN td[149]
    DIRECTION INPUT ;
    USE SIGNAL ;
    PORT
      LAYER M4 ;
        RECT  86.316 82.896 86.4 82.92 ;
    END
  END td[149]
  PIN td[14]
    DIRECTION INPUT ;
    USE SIGNAL ;
    PORT
      LAYER M4 ;
        RECT  86.316 9.984 86.4 10.008 ;
    END
  END td[14]
  PIN td[150]
    DIRECTION INPUT ;
    USE SIGNAL ;
    PORT
      LAYER M4 ;
        RECT  86.316 83.424 86.4 83.448 ;
    END
  END td[150]
  PIN td[151]
    DIRECTION INPUT ;
    USE SIGNAL ;
    PORT
      LAYER M4 ;
        RECT  86.316 83.952 86.4 83.976 ;
    END
  END td[151]
  PIN td[152]
    DIRECTION INPUT ;
    USE SIGNAL ;
    PORT
      LAYER M4 ;
        RECT  86.316 84.48 86.4 84.504 ;
    END
  END td[152]
  PIN td[153]
    DIRECTION INPUT ;
    USE SIGNAL ;
    PORT
      LAYER M4 ;
        RECT  86.316 85.056 86.4 85.08 ;
    END
  END td[153]
  PIN td[154]
    DIRECTION INPUT ;
    USE SIGNAL ;
    PORT
      LAYER M4 ;
        RECT  86.316 85.584 86.4 85.608 ;
    END
  END td[154]
  PIN td[155]
    DIRECTION INPUT ;
    USE SIGNAL ;
    PORT
      LAYER M4 ;
        RECT  86.316 86.112 86.4 86.136 ;
    END
  END td[155]
  PIN td[156]
    DIRECTION INPUT ;
    USE SIGNAL ;
    PORT
      LAYER M4 ;
        RECT  86.316 86.64 86.4 86.664 ;
    END
  END td[156]
  PIN td[157]
    DIRECTION INPUT ;
    USE SIGNAL ;
    PORT
      LAYER M4 ;
        RECT  86.316 87.216 86.4 87.24 ;
    END
  END td[157]
  PIN td[158]
    DIRECTION INPUT ;
    USE SIGNAL ;
    PORT
      LAYER M4 ;
        RECT  86.316 87.744 86.4 87.768 ;
    END
  END td[158]
  PIN td[159]
    DIRECTION INPUT ;
    USE SIGNAL ;
    PORT
      LAYER M4 ;
        RECT  86.316 88.272 86.4 88.296 ;
    END
  END td[159]
  PIN td[15]
    DIRECTION INPUT ;
    USE SIGNAL ;
    PORT
      LAYER M4 ;
        RECT  86.316 10.512 86.4 10.536 ;
    END
  END td[15]
  PIN td[160]
    DIRECTION INPUT ;
    USE SIGNAL ;
    PORT
      LAYER M4 ;
        RECT  86.316 88.8 86.4 88.824 ;
    END
  END td[160]
  PIN td[161]
    DIRECTION INPUT ;
    USE SIGNAL ;
    PORT
      LAYER M4 ;
        RECT  86.316 89.376 86.4 89.4 ;
    END
  END td[161]
  PIN td[162]
    DIRECTION INPUT ;
    USE SIGNAL ;
    PORT
      LAYER M4 ;
        RECT  86.316 89.904 86.4 89.928 ;
    END
  END td[162]
  PIN td[163]
    DIRECTION INPUT ;
    USE SIGNAL ;
    PORT
      LAYER M4 ;
        RECT  86.316 90.432 86.4 90.456 ;
    END
  END td[163]
  PIN td[164]
    DIRECTION INPUT ;
    USE SIGNAL ;
    PORT
      LAYER M4 ;
        RECT  86.316 90.96 86.4 90.984 ;
    END
  END td[164]
  PIN td[165]
    DIRECTION INPUT ;
    USE SIGNAL ;
    PORT
      LAYER M4 ;
        RECT  86.316 91.536 86.4 91.56 ;
    END
  END td[165]
  PIN td[166]
    DIRECTION INPUT ;
    USE SIGNAL ;
    PORT
      LAYER M4 ;
        RECT  86.316 92.064 86.4 92.088 ;
    END
  END td[166]
  PIN td[167]
    DIRECTION INPUT ;
    USE SIGNAL ;
    PORT
      LAYER M4 ;
        RECT  86.316 92.592 86.4 92.616 ;
    END
  END td[167]
  PIN td[168]
    DIRECTION INPUT ;
    USE SIGNAL ;
    PORT
      LAYER M4 ;
        RECT  86.316 93.12 86.4 93.144 ;
    END
  END td[168]
  PIN td[169]
    DIRECTION INPUT ;
    USE SIGNAL ;
    PORT
      LAYER M4 ;
        RECT  86.316 93.696 86.4 93.72 ;
    END
  END td[169]
  PIN td[16]
    DIRECTION INPUT ;
    USE SIGNAL ;
    PORT
      LAYER M4 ;
        RECT  86.316 11.04 86.4 11.064 ;
    END
  END td[16]
  PIN td[170]
    DIRECTION INPUT ;
    USE SIGNAL ;
    PORT
      LAYER M4 ;
        RECT  86.316 94.224 86.4 94.248 ;
    END
  END td[170]
  PIN td[171]
    DIRECTION INPUT ;
    USE SIGNAL ;
    PORT
      LAYER M4 ;
        RECT  86.316 94.752 86.4 94.776 ;
    END
  END td[171]
  PIN td[172]
    DIRECTION INPUT ;
    USE SIGNAL ;
    PORT
      LAYER M4 ;
        RECT  86.316 95.28 86.4 95.304 ;
    END
  END td[172]
  PIN td[173]
    DIRECTION INPUT ;
    USE SIGNAL ;
    PORT
      LAYER M4 ;
        RECT  86.316 95.856 86.4 95.88 ;
    END
  END td[173]
  PIN td[174]
    DIRECTION INPUT ;
    USE SIGNAL ;
    PORT
      LAYER M4 ;
        RECT  86.316 96.384 86.4 96.408 ;
    END
  END td[174]
  PIN td[175]
    DIRECTION INPUT ;
    USE SIGNAL ;
    PORT
      LAYER M4 ;
        RECT  86.316 96.912 86.4 96.936 ;
    END
  END td[175]
  PIN td[176]
    DIRECTION INPUT ;
    USE SIGNAL ;
    PORT
      LAYER M4 ;
        RECT  86.316 97.44 86.4 97.464 ;
    END
  END td[176]
  PIN td[177]
    DIRECTION INPUT ;
    USE SIGNAL ;
    PORT
      LAYER M4 ;
        RECT  86.316 98.016 86.4 98.04 ;
    END
  END td[177]
  PIN td[178]
    DIRECTION INPUT ;
    USE SIGNAL ;
    PORT
      LAYER M4 ;
        RECT  86.316 98.544 86.4 98.568 ;
    END
  END td[178]
  PIN td[179]
    DIRECTION INPUT ;
    USE SIGNAL ;
    PORT
      LAYER M4 ;
        RECT  86.316 99.072 86.4 99.096 ;
    END
  END td[179]
  PIN td[17]
    DIRECTION INPUT ;
    USE SIGNAL ;
    PORT
      LAYER M4 ;
        RECT  86.316 11.616 86.4 11.64 ;
    END
  END td[17]
  PIN td[180]
    DIRECTION INPUT ;
    USE SIGNAL ;
    PORT
      LAYER M4 ;
        RECT  86.316 99.6 86.4 99.624 ;
    END
  END td[180]
  PIN td[181]
    DIRECTION INPUT ;
    USE SIGNAL ;
    PORT
      LAYER M4 ;
        RECT  86.316 100.176 86.4 100.2 ;
    END
  END td[181]
  PIN td[182]
    DIRECTION INPUT ;
    USE SIGNAL ;
    PORT
      LAYER M4 ;
        RECT  86.316 100.704 86.4 100.728 ;
    END
  END td[182]
  PIN td[183]
    DIRECTION INPUT ;
    USE SIGNAL ;
    PORT
      LAYER M4 ;
        RECT  86.316 101.232 86.4 101.256 ;
    END
  END td[183]
  PIN td[184]
    DIRECTION INPUT ;
    USE SIGNAL ;
    PORT
      LAYER M4 ;
        RECT  86.316 101.76 86.4 101.784 ;
    END
  END td[184]
  PIN td[185]
    DIRECTION INPUT ;
    USE SIGNAL ;
    PORT
      LAYER M4 ;
        RECT  86.316 102.336 86.4 102.36 ;
    END
  END td[185]
  PIN td[186]
    DIRECTION INPUT ;
    USE SIGNAL ;
    PORT
      LAYER M4 ;
        RECT  86.316 102.864 86.4 102.888 ;
    END
  END td[186]
  PIN td[187]
    DIRECTION INPUT ;
    USE SIGNAL ;
    PORT
      LAYER M4 ;
        RECT  86.316 103.392 86.4 103.416 ;
    END
  END td[187]
  PIN td[188]
    DIRECTION INPUT ;
    USE SIGNAL ;
    PORT
      LAYER M4 ;
        RECT  86.316 103.92 86.4 103.944 ;
    END
  END td[188]
  PIN td[189]
    DIRECTION INPUT ;
    USE SIGNAL ;
    PORT
      LAYER M4 ;
        RECT  86.316 104.496 86.4 104.52 ;
    END
  END td[189]
  PIN td[18]
    DIRECTION INPUT ;
    USE SIGNAL ;
    PORT
      LAYER M4 ;
        RECT  86.316 12.144 86.4 12.168 ;
    END
  END td[18]
  PIN td[190]
    DIRECTION INPUT ;
    USE SIGNAL ;
    PORT
      LAYER M4 ;
        RECT  86.316 105.024 86.4 105.048 ;
    END
  END td[190]
  PIN td[191]
    DIRECTION INPUT ;
    USE SIGNAL ;
    PORT
      LAYER M4 ;
        RECT  86.316 105.552 86.4 105.576 ;
    END
  END td[191]
  PIN td[19]
    DIRECTION INPUT ;
    USE SIGNAL ;
    PORT
      LAYER M4 ;
        RECT  86.316 12.672 86.4 12.696 ;
    END
  END td[19]
  PIN td[1]
    DIRECTION INPUT ;
    USE SIGNAL ;
    PORT
      LAYER M4 ;
        RECT  86.316 2.976 86.4 3 ;
    END
  END td[1]
  PIN td[20]
    DIRECTION INPUT ;
    USE SIGNAL ;
    PORT
      LAYER M4 ;
        RECT  86.316 13.2 86.4 13.224 ;
    END
  END td[20]
  PIN td[21]
    DIRECTION INPUT ;
    USE SIGNAL ;
    PORT
      LAYER M4 ;
        RECT  86.316 13.776 86.4 13.8 ;
    END
  END td[21]
  PIN td[22]
    DIRECTION INPUT ;
    USE SIGNAL ;
    PORT
      LAYER M4 ;
        RECT  86.316 14.304 86.4 14.328 ;
    END
  END td[22]
  PIN td[23]
    DIRECTION INPUT ;
    USE SIGNAL ;
    PORT
      LAYER M4 ;
        RECT  86.316 14.832 86.4 14.856 ;
    END
  END td[23]
  PIN td[24]
    DIRECTION INPUT ;
    USE SIGNAL ;
    PORT
      LAYER M4 ;
        RECT  86.316 15.36 86.4 15.384 ;
    END
  END td[24]
  PIN td[25]
    DIRECTION INPUT ;
    USE SIGNAL ;
    PORT
      LAYER M4 ;
        RECT  86.316 15.936 86.4 15.96 ;
    END
  END td[25]
  PIN td[26]
    DIRECTION INPUT ;
    USE SIGNAL ;
    PORT
      LAYER M4 ;
        RECT  86.316 16.464 86.4 16.488 ;
    END
  END td[26]
  PIN td[27]
    DIRECTION INPUT ;
    USE SIGNAL ;
    PORT
      LAYER M4 ;
        RECT  86.316 16.992 86.4 17.016 ;
    END
  END td[27]
  PIN td[28]
    DIRECTION INPUT ;
    USE SIGNAL ;
    PORT
      LAYER M4 ;
        RECT  86.316 17.52 86.4 17.544 ;
    END
  END td[28]
  PIN td[29]
    DIRECTION INPUT ;
    USE SIGNAL ;
    PORT
      LAYER M4 ;
        RECT  86.316 18.096 86.4 18.12 ;
    END
  END td[29]
  PIN td[2]
    DIRECTION INPUT ;
    USE SIGNAL ;
    PORT
      LAYER M4 ;
        RECT  86.316 3.504 86.4 3.528 ;
    END
  END td[2]
  PIN td[30]
    DIRECTION INPUT ;
    USE SIGNAL ;
    PORT
      LAYER M4 ;
        RECT  86.316 18.624 86.4 18.648 ;
    END
  END td[30]
  PIN td[31]
    DIRECTION INPUT ;
    USE SIGNAL ;
    PORT
      LAYER M4 ;
        RECT  86.316 19.152 86.4 19.176 ;
    END
  END td[31]
  PIN td[32]
    DIRECTION INPUT ;
    USE SIGNAL ;
    PORT
      LAYER M4 ;
        RECT  86.316 19.68 86.4 19.704 ;
    END
  END td[32]
  PIN td[33]
    DIRECTION INPUT ;
    USE SIGNAL ;
    PORT
      LAYER M4 ;
        RECT  86.316 20.256 86.4 20.28 ;
    END
  END td[33]
  PIN td[34]
    DIRECTION INPUT ;
    USE SIGNAL ;
    PORT
      LAYER M4 ;
        RECT  86.316 20.784 86.4 20.808 ;
    END
  END td[34]
  PIN td[35]
    DIRECTION INPUT ;
    USE SIGNAL ;
    PORT
      LAYER M4 ;
        RECT  86.316 21.312 86.4 21.336 ;
    END
  END td[35]
  PIN td[36]
    DIRECTION INPUT ;
    USE SIGNAL ;
    PORT
      LAYER M4 ;
        RECT  86.316 21.84 86.4 21.864 ;
    END
  END td[36]
  PIN td[37]
    DIRECTION INPUT ;
    USE SIGNAL ;
    PORT
      LAYER M4 ;
        RECT  86.316 22.416 86.4 22.44 ;
    END
  END td[37]
  PIN td[38]
    DIRECTION INPUT ;
    USE SIGNAL ;
    PORT
      LAYER M4 ;
        RECT  86.316 22.944 86.4 22.968 ;
    END
  END td[38]
  PIN td[39]
    DIRECTION INPUT ;
    USE SIGNAL ;
    PORT
      LAYER M4 ;
        RECT  86.316 23.472 86.4 23.496 ;
    END
  END td[39]
  PIN td[3]
    DIRECTION INPUT ;
    USE SIGNAL ;
    PORT
      LAYER M4 ;
        RECT  86.316 4.032 86.4 4.056 ;
    END
  END td[3]
  PIN td[40]
    DIRECTION INPUT ;
    USE SIGNAL ;
    PORT
      LAYER M4 ;
        RECT  86.316 24 86.4 24.024 ;
    END
  END td[40]
  PIN td[41]
    DIRECTION INPUT ;
    USE SIGNAL ;
    PORT
      LAYER M4 ;
        RECT  86.316 24.576 86.4 24.6 ;
    END
  END td[41]
  PIN td[42]
    DIRECTION INPUT ;
    USE SIGNAL ;
    PORT
      LAYER M4 ;
        RECT  86.316 25.104 86.4 25.128 ;
    END
  END td[42]
  PIN td[43]
    DIRECTION INPUT ;
    USE SIGNAL ;
    PORT
      LAYER M4 ;
        RECT  86.316 25.632 86.4 25.656 ;
    END
  END td[43]
  PIN td[44]
    DIRECTION INPUT ;
    USE SIGNAL ;
    PORT
      LAYER M4 ;
        RECT  86.316 26.16 86.4 26.184 ;
    END
  END td[44]
  PIN td[45]
    DIRECTION INPUT ;
    USE SIGNAL ;
    PORT
      LAYER M4 ;
        RECT  86.316 26.736 86.4 26.76 ;
    END
  END td[45]
  PIN td[46]
    DIRECTION INPUT ;
    USE SIGNAL ;
    PORT
      LAYER M4 ;
        RECT  86.316 27.264 86.4 27.288 ;
    END
  END td[46]
  PIN td[47]
    DIRECTION INPUT ;
    USE SIGNAL ;
    PORT
      LAYER M4 ;
        RECT  86.316 27.792 86.4 27.816 ;
    END
  END td[47]
  PIN td[48]
    DIRECTION INPUT ;
    USE SIGNAL ;
    PORT
      LAYER M4 ;
        RECT  86.316 28.32 86.4 28.344 ;
    END
  END td[48]
  PIN td[49]
    DIRECTION INPUT ;
    USE SIGNAL ;
    PORT
      LAYER M4 ;
        RECT  86.316 28.896 86.4 28.92 ;
    END
  END td[49]
  PIN td[4]
    DIRECTION INPUT ;
    USE SIGNAL ;
    PORT
      LAYER M4 ;
        RECT  86.316 4.56 86.4 4.584 ;
    END
  END td[4]
  PIN td[50]
    DIRECTION INPUT ;
    USE SIGNAL ;
    PORT
      LAYER M4 ;
        RECT  86.316 29.424 86.4 29.448 ;
    END
  END td[50]
  PIN td[51]
    DIRECTION INPUT ;
    USE SIGNAL ;
    PORT
      LAYER M4 ;
        RECT  86.316 29.952 86.4 29.976 ;
    END
  END td[51]
  PIN td[52]
    DIRECTION INPUT ;
    USE SIGNAL ;
    PORT
      LAYER M4 ;
        RECT  86.316 30.48 86.4 30.504 ;
    END
  END td[52]
  PIN td[53]
    DIRECTION INPUT ;
    USE SIGNAL ;
    PORT
      LAYER M4 ;
        RECT  86.316 31.056 86.4 31.08 ;
    END
  END td[53]
  PIN td[54]
    DIRECTION INPUT ;
    USE SIGNAL ;
    PORT
      LAYER M4 ;
        RECT  86.316 31.584 86.4 31.608 ;
    END
  END td[54]
  PIN td[55]
    DIRECTION INPUT ;
    USE SIGNAL ;
    PORT
      LAYER M4 ;
        RECT  86.316 32.112 86.4 32.136 ;
    END
  END td[55]
  PIN td[56]
    DIRECTION INPUT ;
    USE SIGNAL ;
    PORT
      LAYER M4 ;
        RECT  86.316 32.64 86.4 32.664 ;
    END
  END td[56]
  PIN td[57]
    DIRECTION INPUT ;
    USE SIGNAL ;
    PORT
      LAYER M4 ;
        RECT  86.316 33.216 86.4 33.24 ;
    END
  END td[57]
  PIN td[58]
    DIRECTION INPUT ;
    USE SIGNAL ;
    PORT
      LAYER M4 ;
        RECT  86.316 33.744 86.4 33.768 ;
    END
  END td[58]
  PIN td[59]
    DIRECTION INPUT ;
    USE SIGNAL ;
    PORT
      LAYER M4 ;
        RECT  86.316 34.272 86.4 34.296 ;
    END
  END td[59]
  PIN td[5]
    DIRECTION INPUT ;
    USE SIGNAL ;
    PORT
      LAYER M4 ;
        RECT  86.316 5.136 86.4 5.16 ;
    END
  END td[5]
  PIN td[60]
    DIRECTION INPUT ;
    USE SIGNAL ;
    PORT
      LAYER M4 ;
        RECT  86.316 34.8 86.4 34.824 ;
    END
  END td[60]
  PIN td[61]
    DIRECTION INPUT ;
    USE SIGNAL ;
    PORT
      LAYER M4 ;
        RECT  86.316 35.376 86.4 35.4 ;
    END
  END td[61]
  PIN td[62]
    DIRECTION INPUT ;
    USE SIGNAL ;
    PORT
      LAYER M4 ;
        RECT  86.316 35.904 86.4 35.928 ;
    END
  END td[62]
  PIN td[63]
    DIRECTION INPUT ;
    USE SIGNAL ;
    PORT
      LAYER M4 ;
        RECT  86.316 36.432 86.4 36.456 ;
    END
  END td[63]
  PIN td[64]
    DIRECTION INPUT ;
    USE SIGNAL ;
    PORT
      LAYER M4 ;
        RECT  86.316 36.96 86.4 36.984 ;
    END
  END td[64]
  PIN td[65]
    DIRECTION INPUT ;
    USE SIGNAL ;
    PORT
      LAYER M4 ;
        RECT  86.316 37.536 86.4 37.56 ;
    END
  END td[65]
  PIN td[66]
    DIRECTION INPUT ;
    USE SIGNAL ;
    PORT
      LAYER M4 ;
        RECT  86.316 38.064 86.4 38.088 ;
    END
  END td[66]
  PIN td[67]
    DIRECTION INPUT ;
    USE SIGNAL ;
    PORT
      LAYER M4 ;
        RECT  86.316 38.592 86.4 38.616 ;
    END
  END td[67]
  PIN td[68]
    DIRECTION INPUT ;
    USE SIGNAL ;
    PORT
      LAYER M4 ;
        RECT  86.316 39.12 86.4 39.144 ;
    END
  END td[68]
  PIN td[69]
    DIRECTION INPUT ;
    USE SIGNAL ;
    PORT
      LAYER M4 ;
        RECT  86.316 39.696 86.4 39.72 ;
    END
  END td[69]
  PIN td[6]
    DIRECTION INPUT ;
    USE SIGNAL ;
    PORT
      LAYER M4 ;
        RECT  86.316 5.664 86.4 5.688 ;
    END
  END td[6]
  PIN td[70]
    DIRECTION INPUT ;
    USE SIGNAL ;
    PORT
      LAYER M4 ;
        RECT  86.316 40.224 86.4 40.248 ;
    END
  END td[70]
  PIN td[71]
    DIRECTION INPUT ;
    USE SIGNAL ;
    PORT
      LAYER M4 ;
        RECT  86.316 40.752 86.4 40.776 ;
    END
  END td[71]
  PIN td[72]
    DIRECTION INPUT ;
    USE SIGNAL ;
    PORT
      LAYER M4 ;
        RECT  86.316 41.28 86.4 41.304 ;
    END
  END td[72]
  PIN td[73]
    DIRECTION INPUT ;
    USE SIGNAL ;
    PORT
      LAYER M4 ;
        RECT  86.316 41.856 86.4 41.88 ;
    END
  END td[73]
  PIN td[74]
    DIRECTION INPUT ;
    USE SIGNAL ;
    PORT
      LAYER M4 ;
        RECT  86.316 42.384 86.4 42.408 ;
    END
  END td[74]
  PIN td[75]
    DIRECTION INPUT ;
    USE SIGNAL ;
    PORT
      LAYER M4 ;
        RECT  86.316 42.912 86.4 42.936 ;
    END
  END td[75]
  PIN td[76]
    DIRECTION INPUT ;
    USE SIGNAL ;
    PORT
      LAYER M4 ;
        RECT  86.316 43.44 86.4 43.464 ;
    END
  END td[76]
  PIN td[77]
    DIRECTION INPUT ;
    USE SIGNAL ;
    PORT
      LAYER M4 ;
        RECT  86.316 44.016 86.4 44.04 ;
    END
  END td[77]
  PIN td[78]
    DIRECTION INPUT ;
    USE SIGNAL ;
    PORT
      LAYER M4 ;
        RECT  86.316 44.544 86.4 44.568 ;
    END
  END td[78]
  PIN td[79]
    DIRECTION INPUT ;
    USE SIGNAL ;
    PORT
      LAYER M4 ;
        RECT  86.316 45.072 86.4 45.096 ;
    END
  END td[79]
  PIN td[7]
    DIRECTION INPUT ;
    USE SIGNAL ;
    PORT
      LAYER M4 ;
        RECT  86.316 6.192 86.4 6.216 ;
    END
  END td[7]
  PIN td[80]
    DIRECTION INPUT ;
    USE SIGNAL ;
    PORT
      LAYER M4 ;
        RECT  86.316 45.6 86.4 45.624 ;
    END
  END td[80]
  PIN td[81]
    DIRECTION INPUT ;
    USE SIGNAL ;
    PORT
      LAYER M4 ;
        RECT  86.316 46.176 86.4 46.2 ;
    END
  END td[81]
  PIN td[82]
    DIRECTION INPUT ;
    USE SIGNAL ;
    PORT
      LAYER M4 ;
        RECT  86.316 46.704 86.4 46.728 ;
    END
  END td[82]
  PIN td[83]
    DIRECTION INPUT ;
    USE SIGNAL ;
    PORT
      LAYER M4 ;
        RECT  86.316 47.232 86.4 47.256 ;
    END
  END td[83]
  PIN td[84]
    DIRECTION INPUT ;
    USE SIGNAL ;
    PORT
      LAYER M4 ;
        RECT  86.316 47.76 86.4 47.784 ;
    END
  END td[84]
  PIN td[85]
    DIRECTION INPUT ;
    USE SIGNAL ;
    PORT
      LAYER M4 ;
        RECT  86.316 48.336 86.4 48.36 ;
    END
  END td[85]
  PIN td[86]
    DIRECTION INPUT ;
    USE SIGNAL ;
    PORT
      LAYER M4 ;
        RECT  86.316 48.864 86.4 48.888 ;
    END
  END td[86]
  PIN td[87]
    DIRECTION INPUT ;
    USE SIGNAL ;
    PORT
      LAYER M4 ;
        RECT  86.316 49.392 86.4 49.416 ;
    END
  END td[87]
  PIN td[88]
    DIRECTION INPUT ;
    USE SIGNAL ;
    PORT
      LAYER M4 ;
        RECT  86.316 49.92 86.4 49.944 ;
    END
  END td[88]
  PIN td[89]
    DIRECTION INPUT ;
    USE SIGNAL ;
    PORT
      LAYER M4 ;
        RECT  86.316 50.496 86.4 50.52 ;
    END
  END td[89]
  PIN td[8]
    DIRECTION INPUT ;
    USE SIGNAL ;
    PORT
      LAYER M4 ;
        RECT  86.316 6.72 86.4 6.744 ;
    END
  END td[8]
  PIN td[90]
    DIRECTION INPUT ;
    USE SIGNAL ;
    PORT
      LAYER M4 ;
        RECT  86.316 51.024 86.4 51.048 ;
    END
  END td[90]
  PIN td[91]
    DIRECTION INPUT ;
    USE SIGNAL ;
    PORT
      LAYER M4 ;
        RECT  86.316 51.552 86.4 51.576 ;
    END
  END td[91]
  PIN td[92]
    DIRECTION INPUT ;
    USE SIGNAL ;
    PORT
      LAYER M4 ;
        RECT  86.316 52.08 86.4 52.104 ;
    END
  END td[92]
  PIN td[93]
    DIRECTION INPUT ;
    USE SIGNAL ;
    PORT
      LAYER M4 ;
        RECT  86.316 52.656 86.4 52.68 ;
    END
  END td[93]
  PIN td[94]
    DIRECTION INPUT ;
    USE SIGNAL ;
    PORT
      LAYER M4 ;
        RECT  86.316 53.184 86.4 53.208 ;
    END
  END td[94]
  PIN td[95]
    DIRECTION INPUT ;
    USE SIGNAL ;
    PORT
      LAYER M4 ;
        RECT  86.316 53.712 86.4 53.736 ;
    END
  END td[95]
  PIN td[96]
    DIRECTION INPUT ;
    USE SIGNAL ;
    PORT
      LAYER M4 ;
        RECT  86.316 54.24 86.4 54.264 ;
    END
  END td[96]
  PIN td[97]
    DIRECTION INPUT ;
    USE SIGNAL ;
    PORT
      LAYER M4 ;
        RECT  86.316 54.816 86.4 54.84 ;
    END
  END td[97]
  PIN td[98]
    DIRECTION INPUT ;
    USE SIGNAL ;
    PORT
      LAYER M4 ;
        RECT  86.316 55.344 86.4 55.368 ;
    END
  END td[98]
  PIN td[99]
    DIRECTION INPUT ;
    USE SIGNAL ;
    PORT
      LAYER M4 ;
        RECT  86.316 55.872 86.4 55.896 ;
    END
  END td[99]
  PIN td[9]
    DIRECTION INPUT ;
    USE SIGNAL ;
    PORT
      LAYER M4 ;
        RECT  86.316 7.296 86.4 7.32 ;
    END
  END td[9]
  PIN tvk
    DIRECTION INPUT ;
    USE SIGNAL ;
    PORT
      LAYER M5 ;
        RECT  30.768 107.916 30.792 108 ;
    END
  END tvk
  PIN VDD
    DIRECTION INOUT ;
    USE POWER ;
    PORT
      LAYER M5 ;
        RECT  83.592 2.151 83.712 105.849 ;
        RECT  78.192 2.151 78.312 105.849 ;
        RECT  72.792 2.151 72.912 105.849 ;
        RECT  67.392 2.151 67.512 105.849 ;
        RECT  61.992 2.151 62.112 105.849 ;
        RECT  56.592 2.151 56.712 105.849 ;
        RECT  51.192 2.151 51.312 105.849 ;
        RECT  45.792 2.151 45.912 105.849 ;
        RECT  40.392 2.151 40.512 105.849 ;
        RECT  34.992 2.151 35.112 105.849 ;
        RECT  29.592 2.151 29.712 105.849 ;
        RECT  24.192 2.151 24.312 105.849 ;
        RECT  18.792 2.151 18.912 105.849 ;
        RECT  13.392 2.151 13.512 105.849 ;
        RECT  7.992 2.151 8.112 105.849 ;
        RECT  2.592 2.151 2.712 105.849 ;
    END
  END VDD
  PIN VSS
    DIRECTION INOUT ;
    USE GROUND ;
    PORT
      LAYER M5 ;
        RECT  83.4 2.137 83.52 105.863 ;
        RECT  78 2.137 78.12 105.863 ;
        RECT  72.6 2.137 72.72 105.863 ;
        RECT  67.2 2.137 67.32 105.863 ;
        RECT  61.8 2.137 61.92 105.863 ;
        RECT  56.4 2.137 56.52 105.863 ;
        RECT  51 2.137 51.12 105.863 ;
        RECT  45.6 2.137 45.72 105.863 ;
        RECT  40.2 2.137 40.32 105.863 ;
        RECT  34.8 2.137 34.92 105.863 ;
        RECT  29.4 2.137 29.52 105.863 ;
        RECT  24 2.137 24.12 105.863 ;
        RECT  18.6 2.137 18.72 105.863 ;
        RECT  13.2 2.137 13.32 105.863 ;
        RECT  7.8 2.137 7.92 105.863 ;
        RECT  2.4 2.137 2.52 105.863 ;
    END
  END VSS
  OBS
    LAYER RVTN ;
     RECT  2.16 2.16 84.24 2.295 ;
     RECT  2.16 2.565 84.24 2.835 ;
     RECT  2.16 3.105 84.24 3.375 ;
     RECT  2.16 3.645 84.24 3.915 ;
     RECT  2.16 4.185 84.24 4.455 ;
     RECT  2.16 4.725 84.24 4.995 ;
     RECT  2.16 5.265 84.24 5.535 ;
     RECT  2.16 5.805 84.24 6.075 ;
     RECT  2.16 6.345 84.24 6.615 ;
     RECT  2.16 6.885 84.24 7.155 ;
     RECT  2.16 7.425 84.24 7.695 ;
     RECT  2.16 7.965 84.24 8.235 ;
     RECT  2.16 8.505 84.24 8.775 ;
     RECT  2.16 9.045 84.24 9.315 ;
     RECT  2.16 9.585 84.24 9.855 ;
     RECT  2.16 10.125 84.24 10.395 ;
     RECT  2.16 10.665 84.24 10.935 ;
     RECT  2.16 11.205 84.24 11.475 ;
     RECT  2.16 11.745 84.24 12.015 ;
     RECT  2.16 12.285 84.24 12.555 ;
     RECT  2.16 12.825 84.24 13.095 ;
     RECT  2.16 13.365 84.24 13.635 ;
     RECT  2.16 13.905 84.24 14.175 ;
     RECT  2.16 14.445 84.24 14.715 ;
     RECT  2.16 14.985 84.24 15.255 ;
     RECT  2.16 15.525 84.24 15.795 ;
     RECT  2.16 16.065 84.24 16.335 ;
     RECT  2.16 16.605 84.24 16.875 ;
     RECT  2.16 17.145 84.24 17.415 ;
     RECT  2.16 17.685 84.24 17.955 ;
     RECT  2.16 18.225 84.24 18.495 ;
     RECT  2.16 18.765 84.24 19.035 ;
     RECT  2.16 19.305 84.24 19.575 ;
     RECT  2.16 19.845 84.24 20.115 ;
     RECT  2.16 20.385 84.24 20.655 ;
     RECT  2.16 20.925 84.24 21.195 ;
     RECT  2.16 21.465 84.24 21.735 ;
     RECT  2.16 22.005 84.24 22.275 ;
     RECT  2.16 22.545 84.24 22.815 ;
     RECT  2.16 23.085 84.24 23.355 ;
     RECT  2.16 23.625 84.24 23.895 ;
     RECT  2.16 24.165 84.24 24.435 ;
     RECT  2.16 24.705 84.24 24.975 ;
     RECT  2.16 25.245 84.24 25.515 ;
     RECT  2.16 25.785 84.24 26.055 ;
     RECT  2.16 26.325 84.24 26.595 ;
     RECT  2.16 26.865 84.24 27.135 ;
     RECT  2.16 27.405 84.24 27.675 ;
     RECT  2.16 27.945 84.24 28.215 ;
     RECT  2.16 28.485 84.24 28.755 ;
     RECT  2.16 29.025 84.24 29.295 ;
     RECT  2.16 29.565 84.24 29.835 ;
     RECT  2.16 30.105 84.24 30.375 ;
     RECT  2.16 30.645 84.24 30.915 ;
     RECT  2.16 31.185 84.24 31.455 ;
     RECT  2.16 31.725 84.24 31.995 ;
     RECT  2.16 32.265 84.24 32.535 ;
     RECT  2.16 32.805 84.24 33.075 ;
     RECT  2.16 33.345 84.24 33.615 ;
     RECT  2.16 33.885 84.24 34.155 ;
     RECT  2.16 34.425 84.24 34.695 ;
     RECT  2.16 34.965 84.24 35.235 ;
     RECT  2.16 35.505 84.24 35.775 ;
     RECT  2.16 36.045 84.24 36.315 ;
     RECT  2.16 36.585 84.24 36.855 ;
     RECT  2.16 37.125 84.24 37.395 ;
     RECT  2.16 37.665 84.24 37.935 ;
     RECT  2.16 38.205 84.24 38.475 ;
     RECT  2.16 38.745 84.24 39.015 ;
     RECT  2.16 39.285 84.24 39.555 ;
     RECT  2.16 39.825 84.24 40.095 ;
     RECT  2.16 40.365 84.24 40.635 ;
     RECT  2.16 40.905 84.24 41.175 ;
     RECT  2.16 41.445 84.24 41.715 ;
     RECT  2.16 41.985 84.24 42.255 ;
     RECT  2.16 42.525 84.24 42.795 ;
     RECT  2.16 43.065 84.24 43.335 ;
     RECT  2.16 43.605 84.24 43.875 ;
     RECT  2.16 44.145 84.24 44.415 ;
     RECT  2.16 44.685 84.24 44.955 ;
     RECT  2.16 45.225 84.24 45.495 ;
     RECT  2.16 45.765 84.24 46.035 ;
     RECT  2.16 46.305 84.24 46.575 ;
     RECT  2.16 46.845 84.24 47.115 ;
     RECT  2.16 47.385 84.24 47.655 ;
     RECT  2.16 47.925 84.24 48.195 ;
     RECT  2.16 48.465 84.24 48.735 ;
     RECT  2.16 49.005 84.24 49.275 ;
     RECT  2.16 49.545 84.24 49.815 ;
     RECT  2.16 50.085 84.24 50.355 ;
     RECT  2.16 50.625 84.24 50.895 ;
     RECT  2.16 51.165 84.24 51.435 ;
     RECT  2.16 51.705 84.24 51.975 ;
     RECT  2.16 52.245 84.24 52.515 ;
     RECT  2.16 52.785 84.24 53.055 ;
     RECT  2.16 53.325 84.24 53.595 ;
     RECT  2.16 53.865 84.24 54.135 ;
     RECT  2.16 54.405 84.24 54.675 ;
     RECT  2.16 54.945 84.24 55.215 ;
     RECT  2.16 55.485 84.24 55.755 ;
     RECT  2.16 56.025 84.24 56.295 ;
     RECT  2.16 56.565 84.24 56.835 ;
     RECT  2.16 57.105 84.24 57.375 ;
     RECT  2.16 57.645 84.24 57.915 ;
     RECT  2.16 58.185 84.24 58.455 ;
     RECT  2.16 58.725 84.24 58.995 ;
     RECT  2.16 59.265 84.24 59.535 ;
     RECT  2.16 59.805 84.24 60.075 ;
     RECT  2.16 60.345 84.24 60.615 ;
     RECT  2.16 60.885 84.24 61.155 ;
     RECT  2.16 61.425 84.24 61.695 ;
     RECT  2.16 61.965 84.24 62.235 ;
     RECT  2.16 62.505 84.24 62.775 ;
     RECT  2.16 63.045 84.24 63.315 ;
     RECT  2.16 63.585 84.24 63.855 ;
     RECT  2.16 64.125 84.24 64.395 ;
     RECT  2.16 64.665 84.24 64.935 ;
     RECT  2.16 65.205 84.24 65.475 ;
     RECT  2.16 65.745 84.24 66.015 ;
     RECT  2.16 66.285 84.24 66.555 ;
     RECT  2.16 66.825 84.24 67.095 ;
     RECT  2.16 67.365 84.24 67.635 ;
     RECT  2.16 67.905 84.24 68.175 ;
     RECT  2.16 68.445 84.24 68.715 ;
     RECT  2.16 68.985 84.24 69.255 ;
     RECT  2.16 69.525 84.24 69.795 ;
     RECT  2.16 70.065 84.24 70.335 ;
     RECT  2.16 70.605 84.24 70.875 ;
     RECT  2.16 71.145 84.24 71.415 ;
     RECT  2.16 71.685 84.24 71.955 ;
     RECT  2.16 72.225 84.24 72.495 ;
     RECT  2.16 72.765 84.24 73.035 ;
     RECT  2.16 73.305 84.24 73.575 ;
     RECT  2.16 73.845 84.24 74.115 ;
     RECT  2.16 74.385 84.24 74.655 ;
     RECT  2.16 74.925 84.24 75.195 ;
     RECT  2.16 75.465 84.24 75.735 ;
     RECT  2.16 76.005 84.24 76.275 ;
     RECT  2.16 76.545 84.24 76.815 ;
     RECT  2.16 77.085 84.24 77.355 ;
     RECT  2.16 77.625 84.24 77.895 ;
     RECT  2.16 78.165 84.24 78.435 ;
     RECT  2.16 78.705 84.24 78.975 ;
     RECT  2.16 79.245 84.24 79.515 ;
     RECT  2.16 79.785 84.24 80.055 ;
     RECT  2.16 80.325 84.24 80.595 ;
     RECT  2.16 80.865 84.24 81.135 ;
     RECT  2.16 81.405 84.24 81.675 ;
     RECT  2.16 81.945 84.24 82.215 ;
     RECT  2.16 82.485 84.24 82.755 ;
     RECT  2.16 83.025 84.24 83.295 ;
     RECT  2.16 83.565 84.24 83.835 ;
     RECT  2.16 84.105 84.24 84.375 ;
     RECT  2.16 84.645 84.24 84.915 ;
     RECT  2.16 85.185 84.24 85.455 ;
     RECT  2.16 85.725 84.24 85.995 ;
     RECT  2.16 86.265 84.24 86.535 ;
     RECT  2.16 86.805 84.24 87.075 ;
     RECT  2.16 87.345 84.24 87.615 ;
     RECT  2.16 87.885 84.24 88.155 ;
     RECT  2.16 88.425 84.24 88.695 ;
     RECT  2.16 88.965 84.24 89.235 ;
     RECT  2.16 89.505 84.24 89.775 ;
     RECT  2.16 90.045 84.24 90.315 ;
     RECT  2.16 90.585 84.24 90.855 ;
     RECT  2.16 91.125 84.24 91.395 ;
     RECT  2.16 91.665 84.24 91.935 ;
     RECT  2.16 92.205 84.24 92.475 ;
     RECT  2.16 92.745 84.24 93.015 ;
     RECT  2.16 93.285 84.24 93.555 ;
     RECT  2.16 93.825 84.24 94.095 ;
     RECT  2.16 94.365 84.24 94.635 ;
     RECT  2.16 94.905 84.24 95.175 ;
     RECT  2.16 95.445 84.24 95.715 ;
     RECT  2.16 95.985 84.24 96.255 ;
     RECT  2.16 96.525 84.24 96.795 ;
     RECT  2.16 97.065 84.24 97.335 ;
     RECT  2.16 97.605 84.24 97.875 ;
     RECT  2.16 98.145 84.24 98.415 ;
     RECT  2.16 98.685 84.24 98.955 ;
     RECT  2.16 99.225 84.24 99.495 ;
     RECT  2.16 99.765 84.24 100.035 ;
     RECT  2.16 100.305 84.24 100.575 ;
     RECT  2.16 100.845 84.24 101.115 ;
     RECT  2.16 101.385 84.24 101.655 ;
     RECT  2.16 101.925 84.24 102.195 ;
     RECT  2.16 102.465 84.24 102.735 ;
     RECT  2.16 103.005 84.24 103.275 ;
     RECT  2.16 103.545 84.24 103.815 ;
     RECT  2.16 104.085 84.24 104.355 ;
     RECT  2.16 104.625 84.24 104.895 ;
     RECT  2.16 105.165 84.24 105.435 ;
     RECT  2.16 105.705 84.24 105.84 ;
    LAYER RVTP ;
     RECT  2.16 2.295 84.24 2.565 ;
     RECT  2.16 2.835 84.24 3.105 ;
     RECT  2.16 3.375 84.24 3.645 ;
     RECT  2.16 3.915 84.24 4.185 ;
     RECT  2.16 4.455 84.24 4.725 ;
     RECT  2.16 4.995 84.24 5.265 ;
     RECT  2.16 5.535 84.24 5.805 ;
     RECT  2.16 6.075 84.24 6.345 ;
     RECT  2.16 6.615 84.24 6.885 ;
     RECT  2.16 7.155 84.24 7.425 ;
     RECT  2.16 7.695 84.24 7.965 ;
     RECT  2.16 8.235 84.24 8.505 ;
     RECT  2.16 8.775 84.24 9.045 ;
     RECT  2.16 9.315 84.24 9.585 ;
     RECT  2.16 9.855 84.24 10.125 ;
     RECT  2.16 10.395 84.24 10.665 ;
     RECT  2.16 10.935 84.24 11.205 ;
     RECT  2.16 11.475 84.24 11.745 ;
     RECT  2.16 12.015 84.24 12.285 ;
     RECT  2.16 12.555 84.24 12.825 ;
     RECT  2.16 13.095 84.24 13.365 ;
     RECT  2.16 13.635 84.24 13.905 ;
     RECT  2.16 14.175 84.24 14.445 ;
     RECT  2.16 14.715 84.24 14.985 ;
     RECT  2.16 15.255 84.24 15.525 ;
     RECT  2.16 15.795 84.24 16.065 ;
     RECT  2.16 16.335 84.24 16.605 ;
     RECT  2.16 16.875 84.24 17.145 ;
     RECT  2.16 17.415 84.24 17.685 ;
     RECT  2.16 17.955 84.24 18.225 ;
     RECT  2.16 18.495 84.24 18.765 ;
     RECT  2.16 19.035 84.24 19.305 ;
     RECT  2.16 19.575 84.24 19.845 ;
     RECT  2.16 20.115 84.24 20.385 ;
     RECT  2.16 20.655 84.24 20.925 ;
     RECT  2.16 21.195 84.24 21.465 ;
     RECT  2.16 21.735 84.24 22.005 ;
     RECT  2.16 22.275 84.24 22.545 ;
     RECT  2.16 22.815 84.24 23.085 ;
     RECT  2.16 23.355 84.24 23.625 ;
     RECT  2.16 23.895 84.24 24.165 ;
     RECT  2.16 24.435 84.24 24.705 ;
     RECT  2.16 24.975 84.24 25.245 ;
     RECT  2.16 25.515 84.24 25.785 ;
     RECT  2.16 26.055 84.24 26.325 ;
     RECT  2.16 26.595 84.24 26.865 ;
     RECT  2.16 27.135 84.24 27.405 ;
     RECT  2.16 27.675 84.24 27.945 ;
     RECT  2.16 28.215 84.24 28.485 ;
     RECT  2.16 28.755 84.24 29.025 ;
     RECT  2.16 29.295 84.24 29.565 ;
     RECT  2.16 29.835 84.24 30.105 ;
     RECT  2.16 30.375 84.24 30.645 ;
     RECT  2.16 30.915 84.24 31.185 ;
     RECT  2.16 31.455 84.24 31.725 ;
     RECT  2.16 31.995 84.24 32.265 ;
     RECT  2.16 32.535 84.24 32.805 ;
     RECT  2.16 33.075 84.24 33.345 ;
     RECT  2.16 33.615 84.24 33.885 ;
     RECT  2.16 34.155 84.24 34.425 ;
     RECT  2.16 34.695 84.24 34.965 ;
     RECT  2.16 35.235 84.24 35.505 ;
     RECT  2.16 35.775 84.24 36.045 ;
     RECT  2.16 36.315 84.24 36.585 ;
     RECT  2.16 36.855 84.24 37.125 ;
     RECT  2.16 37.395 84.24 37.665 ;
     RECT  2.16 37.935 84.24 38.205 ;
     RECT  2.16 38.475 84.24 38.745 ;
     RECT  2.16 39.015 84.24 39.285 ;
     RECT  2.16 39.555 84.24 39.825 ;
     RECT  2.16 40.095 84.24 40.365 ;
     RECT  2.16 40.635 84.24 40.905 ;
     RECT  2.16 41.175 84.24 41.445 ;
     RECT  2.16 41.715 84.24 41.985 ;
     RECT  2.16 42.255 84.24 42.525 ;
     RECT  2.16 42.795 84.24 43.065 ;
     RECT  2.16 43.335 84.24 43.605 ;
     RECT  2.16 43.875 84.24 44.145 ;
     RECT  2.16 44.415 84.24 44.685 ;
     RECT  2.16 44.955 84.24 45.225 ;
     RECT  2.16 45.495 84.24 45.765 ;
     RECT  2.16 46.035 84.24 46.305 ;
     RECT  2.16 46.575 84.24 46.845 ;
     RECT  2.16 47.115 84.24 47.385 ;
     RECT  2.16 47.655 84.24 47.925 ;
     RECT  2.16 48.195 84.24 48.465 ;
     RECT  2.16 48.735 84.24 49.005 ;
     RECT  2.16 49.275 84.24 49.545 ;
     RECT  2.16 49.815 84.24 50.085 ;
     RECT  2.16 50.355 84.24 50.625 ;
     RECT  2.16 50.895 84.24 51.165 ;
     RECT  2.16 51.435 84.24 51.705 ;
     RECT  2.16 51.975 84.24 52.245 ;
     RECT  2.16 52.515 84.24 52.785 ;
     RECT  2.16 53.055 84.24 53.325 ;
     RECT  2.16 53.595 84.24 53.865 ;
     RECT  2.16 54.135 84.24 54.405 ;
     RECT  2.16 54.675 84.24 54.945 ;
     RECT  2.16 55.215 84.24 55.485 ;
     RECT  2.16 55.755 84.24 56.025 ;
     RECT  2.16 56.295 84.24 56.565 ;
     RECT  2.16 56.835 84.24 57.105 ;
     RECT  2.16 57.375 84.24 57.645 ;
     RECT  2.16 57.915 84.24 58.185 ;
     RECT  2.16 58.455 84.24 58.725 ;
     RECT  2.16 58.995 84.24 59.265 ;
     RECT  2.16 59.535 84.24 59.805 ;
     RECT  2.16 60.075 84.24 60.345 ;
     RECT  2.16 60.615 84.24 60.885 ;
     RECT  2.16 61.155 84.24 61.425 ;
     RECT  2.16 61.695 84.24 61.965 ;
     RECT  2.16 62.235 84.24 62.505 ;
     RECT  2.16 62.775 84.24 63.045 ;
     RECT  2.16 63.315 84.24 63.585 ;
     RECT  2.16 63.855 84.24 64.125 ;
     RECT  2.16 64.395 84.24 64.665 ;
     RECT  2.16 64.935 84.24 65.205 ;
     RECT  2.16 65.475 84.24 65.745 ;
     RECT  2.16 66.015 84.24 66.285 ;
     RECT  2.16 66.555 84.24 66.825 ;
     RECT  2.16 67.095 84.24 67.365 ;
     RECT  2.16 67.635 84.24 67.905 ;
     RECT  2.16 68.175 84.24 68.445 ;
     RECT  2.16 68.715 84.24 68.985 ;
     RECT  2.16 69.255 84.24 69.525 ;
     RECT  2.16 69.795 84.24 70.065 ;
     RECT  2.16 70.335 84.24 70.605 ;
     RECT  2.16 70.875 84.24 71.145 ;
     RECT  2.16 71.415 84.24 71.685 ;
     RECT  2.16 71.955 84.24 72.225 ;
     RECT  2.16 72.495 84.24 72.765 ;
     RECT  2.16 73.035 84.24 73.305 ;
     RECT  2.16 73.575 84.24 73.845 ;
     RECT  2.16 74.115 84.24 74.385 ;
     RECT  2.16 74.655 84.24 74.925 ;
     RECT  2.16 75.195 84.24 75.465 ;
     RECT  2.16 75.735 84.24 76.005 ;
     RECT  2.16 76.275 84.24 76.545 ;
     RECT  2.16 76.815 84.24 77.085 ;
     RECT  2.16 77.355 84.24 77.625 ;
     RECT  2.16 77.895 84.24 78.165 ;
     RECT  2.16 78.435 84.24 78.705 ;
     RECT  2.16 78.975 84.24 79.245 ;
     RECT  2.16 79.515 84.24 79.785 ;
     RECT  2.16 80.055 84.24 80.325 ;
     RECT  2.16 80.595 84.24 80.865 ;
     RECT  2.16 81.135 84.24 81.405 ;
     RECT  2.16 81.675 84.24 81.945 ;
     RECT  2.16 82.215 84.24 82.485 ;
     RECT  2.16 82.755 84.24 83.025 ;
     RECT  2.16 83.295 84.24 83.565 ;
     RECT  2.16 83.835 84.24 84.105 ;
     RECT  2.16 84.375 84.24 84.645 ;
     RECT  2.16 84.915 84.24 85.185 ;
     RECT  2.16 85.455 84.24 85.725 ;
     RECT  2.16 85.995 84.24 86.265 ;
     RECT  2.16 86.535 84.24 86.805 ;
     RECT  2.16 87.075 84.24 87.345 ;
     RECT  2.16 87.615 84.24 87.885 ;
     RECT  2.16 88.155 84.24 88.425 ;
     RECT  2.16 88.695 84.24 88.965 ;
     RECT  2.16 89.235 84.24 89.505 ;
     RECT  2.16 89.775 84.24 90.045 ;
     RECT  2.16 90.315 84.24 90.585 ;
     RECT  2.16 90.855 84.24 91.125 ;
     RECT  2.16 91.395 84.24 91.665 ;
     RECT  2.16 91.935 84.24 92.205 ;
     RECT  2.16 92.475 84.24 92.745 ;
     RECT  2.16 93.015 84.24 93.285 ;
     RECT  2.16 93.555 84.24 93.825 ;
     RECT  2.16 94.095 84.24 94.365 ;
     RECT  2.16 94.635 84.24 94.905 ;
     RECT  2.16 95.175 84.24 95.445 ;
     RECT  2.16 95.715 84.24 95.985 ;
     RECT  2.16 96.255 84.24 96.525 ;
     RECT  2.16 96.795 84.24 97.065 ;
     RECT  2.16 97.335 84.24 97.605 ;
     RECT  2.16 97.875 84.24 98.145 ;
     RECT  2.16 98.415 84.24 98.685 ;
     RECT  2.16 98.955 84.24 99.225 ;
     RECT  2.16 99.495 84.24 99.765 ;
     RECT  2.16 100.035 84.24 100.305 ;
     RECT  2.16 100.575 84.24 100.845 ;
     RECT  2.16 101.115 84.24 101.385 ;
     RECT  2.16 101.655 84.24 101.925 ;
     RECT  2.16 102.195 84.24 102.465 ;
     RECT  2.16 102.735 84.24 103.005 ;
     RECT  2.16 103.275 84.24 103.545 ;
     RECT  2.16 103.815 84.24 104.085 ;
     RECT  2.16 104.355 84.24 104.625 ;
     RECT  2.16 104.895 84.24 105.165 ;
     RECT  2.16 105.435 84.24 105.705 ;
    LAYER M1 ;
     RECT  2.16 2.151 84.24 105.849 ;
    LAYER M2 ;
     RECT  0.499 14.148 0.535 14.166 ;
     RECT  0.103 14.958 0.535 14.976 ;
     RECT  0.499 31.896 0.535 31.914 ;
     RECT  0.103 42.156 0.535 42.174 ;
     RECT  0.139 48.366 0.535 48.384 ;
     RECT  0.103 52.956 0.535 52.974 ;
     RECT  0.103 62.676 0.535 62.694 ;
     RECT  0.103 64.368 0.535 64.386 ;
     RECT  0.499 66.096 0.535 66.114 ;
     RECT  0.103 85.464 0.535 85.482 ;
     RECT  0.103 95.346 0.535 95.364 ;
     RECT  0.103 3.348 2.16 3.906 ;
     RECT  0.103 5.076 2.16 5.094 ;
     RECT  0.535 8.478 2.16 8.496 ;
     RECT  0.535 12.528 2.16 12.546 ;
     RECT  0.535 14.148 2.16 14.976 ;
     RECT  0.103 20.286 2.16 21.024 ;
     RECT  0.535 31.266 2.16 31.914 ;
     RECT  0.103 33.048 2.16 33.066 ;
     RECT  0.103 38.718 2.16 38.736 ;
     RECT  0.535 42.156 2.16 42.714 ;
     RECT  0.103 44.694 2.16 44.712 ;
     RECT  0.535 48.276 2.16 48.384 ;
     RECT  0.535 49.554 2.16 49.572 ;
     RECT  0.103 52.056 2.16 52.074 ;
     RECT  0.535 52.956 2.16 53.586 ;
     RECT  0.103 55.836 2.16 55.854 ;
     RECT  0.535 62.676 2.16 63.144 ;
     RECT  0.535 64.368 2.16 64.764 ;
     RECT  0.535 65.826 2.16 66.114 ;
     RECT  0.535 72.846 2.16 72.864 ;
     RECT  0.535 74.088 2.16 74.106 ;
     RECT  0.535 75.546 2.16 75.564 ;
     RECT  0.535 76.896 2.16 76.914 ;
     RECT  0.103 82.566 2.16 82.584 ;
     RECT  0.535 84.348 2.16 85.482 ;
     RECT  0.103 87.156 2.16 87.174 ;
     RECT  0.103 93.096 2.16 93.114 ;
     RECT  0.535 94.608 2.16 95.364 ;
     RECT  0.103 96.876 2.16 96.894 ;
     RECT  0.103 99.576 2.16 99.594 ;
     RECT  0.535 103.626 2.16 103.644 ;
     RECT  0.103 104.796 2.16 104.814 ;
     RECT  2.16 2.151 84.24 105.849 ;
     RECT  84.24 4.968 84.911 8.226 ;
     RECT  84.24 16.578 84.911 21.42 ;
     RECT  84.24 27.918 84.911 34.38 ;
     RECT  84.24 43.848 84.911 53.928 ;
     RECT  84.24 54.882 84.911 55.98 ;
     RECT  84.24 57.042 84.911 64.116 ;
     RECT  84.24 65.52 84.911 65.736 ;
     RECT  84.24 103.788 85.019 105.192 ;
     RECT  84.911 28.458 85.379 34.38 ;
     RECT  84.911 46.818 85.379 53.928 ;
     RECT  84.911 63.558 85.379 64.116 ;
     RECT  84.24 82.692 85.379 86.76 ;
     RECT  84.24 97.038 85.379 102.96 ;
     RECT  85.019 103.788 85.379 105.12 ;
     RECT  84.24 2.502 85.487 4.14 ;
     RECT  84.911 4.968 85.487 7.956 ;
     RECT  84.24 8.982 85.487 12.24 ;
     RECT  84.24 13.842 85.487 15.48 ;
     RECT  84.911 16.578 85.487 20.34 ;
     RECT  84.911 21.402 85.487 21.42 ;
     RECT  84.24 22.482 85.487 26.82 ;
     RECT  85.379 28.458 85.487 28.476 ;
     RECT  85.379 29.538 85.487 30.636 ;
     RECT  85.379 31.662 85.487 34.38 ;
     RECT  84.24 35.208 85.487 36.54 ;
     RECT  84.24 37.368 85.487 41.4 ;
     RECT  84.24 42.228 85.487 43.02 ;
     RECT  84.911 43.848 85.487 45.72 ;
     RECT  85.379 46.818 85.487 47.88 ;
     RECT  85.379 48.942 85.487 53.928 ;
     RECT  84.911 54.882 85.487 55.44 ;
     RECT  84.911 57.042 85.487 62.46 ;
     RECT  85.379 64.098 85.487 64.116 ;
     RECT  84.24 66.798 85.487 71.1 ;
     RECT  84.24 71.928 85.487 75.42 ;
     RECT  84.24 77.022 85.487 77.58 ;
     RECT  84.24 78.408 85.487 81.9 ;
     RECT  85.379 82.692 85.487 82.71 ;
     RECT  85.379 83.502 85.487 86.76 ;
     RECT  84.24 87.588 85.487 90.54 ;
     RECT  84.24 91.368 85.487 95.94 ;
     RECT  85.379 97.812 85.487 102.96 ;
     RECT  85.379 104.022 85.487 105.12 ;
     RECT  85.487 7.938 85.523 7.956 ;
     RECT  84.24 13.068 85.523 13.086 ;
    LAYER M3 ;
     RECT  40.215 2.143 40.305 2.191 ;
     RECT  36.72 2.227 36.738 2.263 ;
     RECT  36.576 2.263 36.738 2.335 ;
     RECT  38.232 2.227 38.25 2.335 ;
     RECT  2.415 2.143 2.505 2.371 ;
     RECT  36.576 2.335 36.774 2.371 ;
     RECT  38.232 2.335 38.754 2.371 ;
     RECT  40.215 2.191 40.554 2.371 ;
     RECT  2.412 2.371 2.505 2.413 ;
     RECT  7.815 2.143 7.905 2.413 ;
     RECT  13.215 2.143 13.305 2.413 ;
     RECT  18.615 2.143 18.705 2.413 ;
     RECT  24.015 2.143 24.105 2.413 ;
     RECT  29.415 2.143 29.505 2.413 ;
     RECT  34.815 2.143 34.905 2.413 ;
     RECT  45.615 2.143 45.705 2.413 ;
     RECT  51.015 2.143 51.105 2.413 ;
     RECT  56.415 2.143 56.505 2.413 ;
     RECT  61.815 2.143 61.905 2.413 ;
     RECT  67.215 2.143 67.305 2.413 ;
     RECT  72.615 2.143 72.705 2.413 ;
     RECT  78.015 2.143 78.105 2.413 ;
     RECT  83.415 2.143 83.505 2.413 ;
     RECT  2.412 2.413 2.697 2.461 ;
     RECT  4.284 2.371 4.302 2.461 ;
     RECT  43.092 2.371 43.182 2.489 ;
     RECT  39.816 2.371 40.554 2.569 ;
     RECT  56.415 2.413 56.697 2.569 ;
     RECT  58.14 2.371 58.158 2.569 ;
     RECT  36.324 2.371 36.774 2.605 ;
     RECT  38.196 2.371 38.754 2.605 ;
     RECT  83.415 2.413 83.697 2.605 ;
     RECT  38.088 2.605 38.754 2.641 ;
     RECT  39.816 2.569 40.734 2.641 ;
     RECT  43.092 2.489 43.11 2.641 ;
     RECT  58.14 2.569 58.734 2.641 ;
     RECT  75.204 2.605 75.222 2.641 ;
     RECT  79.488 2.461 79.506 2.641 ;
     RECT  83.196 2.605 83.697 2.641 ;
     RECT  6.804 2.569 6.822 2.669 ;
     RECT  70.704 2.569 70.722 2.669 ;
     RECT  36.324 2.605 36.81 2.731 ;
     RECT  72.615 2.413 72.897 2.731 ;
     RECT  73.8 2.635 73.818 2.731 ;
     RECT  74.916 2.641 75.222 2.731 ;
     RECT  79.344 2.641 79.506 2.759 ;
     RECT  72.615 2.731 73.818 2.767 ;
     RECT  79.344 2.759 79.362 2.795 ;
     RECT  34.815 2.413 35.097 2.839 ;
     RECT  36.324 2.731 37.062 2.839 ;
     RECT  37.872 2.641 40.734 2.839 ;
     RECT  41.616 2.605 41.634 2.839 ;
     RECT  74.628 2.731 75.222 2.861 ;
     RECT  2.412 2.461 4.302 2.875 ;
     RECT  36.324 2.839 41.634 2.875 ;
     RECT  42.552 2.641 43.11 2.875 ;
     RECT  58.032 2.641 58.734 2.875 ;
     RECT  83.196 2.641 84.042 2.911 ;
     RECT  34.776 2.839 35.097 2.939 ;
     RECT  72.396 2.767 73.818 2.939 ;
     RECT  2.412 2.875 4.446 2.971 ;
     RECT  2.304 2.971 4.446 3.001 ;
     RECT  34.815 2.939 35.097 3.001 ;
     RECT  36.144 2.875 43.11 3.001 ;
     RECT  2.304 3.001 4.662 3.029 ;
     RECT  34.815 3.001 43.11 3.029 ;
     RECT  76.968 2.803 76.986 3.029 ;
     RECT  83.16 2.911 84.042 3.037 ;
     RECT  56.088 2.569 56.697 3.065 ;
     RECT  74.628 2.861 74.646 3.173 ;
     RECT  82.62 3.037 84.042 3.173 ;
     RECT  2.304 3.029 2.697 3.209 ;
     RECT  2.34 3.209 2.697 3.299 ;
     RECT  57.996 2.875 58.734 3.299 ;
     RECT  3.492 3.029 4.662 3.335 ;
     RECT  72.615 2.939 73.818 3.335 ;
     RECT  78.015 2.413 78.297 3.343 ;
     RECT  34.815 3.029 42.57 3.371 ;
     RECT  58.716 3.299 58.734 3.407 ;
     RECT  83.232 3.173 84.042 3.407 ;
     RECT  3.492 3.335 4.158 3.479 ;
     RECT  72.615 3.335 73.566 3.569 ;
     RECT  77.544 3.343 78.297 3.569 ;
     RECT  74.556 3.271 74.574 3.641 ;
     RECT  82.404 3.451 82.422 3.713 ;
     RECT  34.815 3.371 42.138 3.839 ;
     RECT  2.415 3.299 2.697 3.991 ;
     RECT  3.492 3.479 3.69 3.991 ;
     RECT  0.108 3.343 0.126 4.061 ;
     RECT  34.815 3.839 41.634 4.145 ;
     RECT  82.44 4.081 82.674 4.253 ;
     RECT  78.015 3.569 78.297 4.261 ;
     RECT  46.944 4.261 46.962 4.351 ;
     RECT  46.8 4.351 46.962 4.379 ;
     RECT  82.656 4.253 82.674 4.379 ;
     RECT  74.844 4.315 74.862 4.387 ;
     RECT  2.415 3.991 3.69 4.415 ;
     RECT  78.015 4.261 78.822 4.415 ;
     RECT  59.76 4.387 59.778 4.423 ;
     RECT  46.8 4.379 46.818 4.451 ;
     RECT  45.615 2.413 45.897 4.495 ;
     RECT  74.844 4.387 75.078 4.531 ;
     RECT  45.615 4.495 45.99 4.541 ;
     RECT  2.415 4.415 3.042 4.555 ;
     RECT  59.76 4.423 59.886 4.649 ;
     RECT  74.664 4.531 75.078 4.649 ;
     RECT  59.76 4.649 59.778 4.685 ;
     RECT  74.772 4.649 75.078 4.721 ;
     RECT  2.304 4.555 3.042 4.733 ;
     RECT  2.376 4.733 3.042 4.919 ;
     RECT  39.996 4.145 41.634 5.035 ;
     RECT  56.415 3.065 56.697 5.161 ;
     RECT  74.772 4.721 75.006 5.225 ;
     RECT  78.015 4.415 78.297 5.233 ;
     RECT  34.815 4.145 39.258 5.269 ;
     RECT  39.996 5.035 41.994 5.269 ;
     RECT  3.852 4.729 3.942 5.305 ;
     RECT  2.415 4.919 3.042 5.341 ;
     RECT  3.852 5.305 4.014 5.341 ;
     RECT  72.615 3.569 72.897 5.341 ;
     RECT  83.415 3.407 84.042 5.341 ;
     RECT  5.472 5.305 5.49 5.357 ;
     RECT  34.815 5.269 41.994 5.431 ;
     RECT  44.28 5.419 44.298 5.431 ;
     RECT  2.415 5.341 4.014 5.459 ;
     RECT  44.28 5.431 44.442 5.459 ;
     RECT  56.415 5.161 56.934 5.459 ;
     RECT  74.772 5.225 74.79 5.459 ;
     RECT  79.488 5.161 79.506 5.459 ;
     RECT  71.244 5.341 72.954 5.467 ;
     RECT  58.86 5.467 58.878 5.503 ;
     RECT  6.444 5.305 6.462 5.531 ;
     RECT  82.8 5.341 84.042 5.531 ;
     RECT  3.852 5.459 4.014 5.563 ;
     RECT  75.924 5.341 75.942 5.567 ;
     RECT  78.015 5.233 78.678 5.567 ;
     RECT  58.824 5.503 58.878 5.603 ;
     RECT  78.015 5.567 78.297 5.611 ;
     RECT  3.852 5.563 4.23 5.639 ;
     RECT  71.244 5.467 72.99 5.639 ;
     RECT  2.415 5.459 3.006 5.645 ;
     RECT  71.244 5.639 72.954 5.645 ;
     RECT  0.108 5.071 0.126 5.693 ;
     RECT  3.852 5.639 4.014 5.729 ;
     RECT  34.815 5.431 42.678 5.729 ;
     RECT  71.244 5.645 71.838 5.729 ;
     RECT  77.436 5.611 78.297 5.729 ;
     RECT  3.852 5.729 3.87 5.765 ;
     RECT  56.415 5.459 56.862 5.765 ;
     RECT  58.824 5.603 58.842 5.765 ;
     RECT  44.424 5.459 44.442 5.801 ;
     RECT  80.964 5.431 80.982 5.837 ;
     RECT  42.66 5.729 42.678 5.873 ;
     RECT  54.72 5.773 54.738 5.873 ;
     RECT  71.244 5.729 71.262 5.999 ;
     RECT  83.415 5.531 84.042 5.999 ;
     RECT  74.448 6.151 74.466 6.269 ;
     RECT  2.415 5.645 2.934 6.385 ;
     RECT  2.415 6.385 3.582 6.421 ;
     RECT  82.656 6.313 82.674 6.421 ;
     RECT  74.088 6.385 74.106 6.461 ;
     RECT  72.615 5.645 72.954 6.503 ;
     RECT  30.96 6.421 30.978 6.539 ;
     RECT  2.304 6.421 3.582 6.611 ;
     RECT  82.08 6.421 82.674 6.647 ;
     RECT  75.24 6.421 75.258 6.683 ;
     RECT  72.432 6.503 72.954 6.691 ;
     RECT  5.58 6.763 5.598 6.809 ;
     RECT  58.572 6.511 58.59 6.809 ;
     RECT  34.815 5.729 41.85 6.817 ;
     RECT  70.704 6.619 70.722 6.845 ;
     RECT  83.415 5.999 83.898 6.961 ;
     RECT  78.015 5.729 78.297 7.195 ;
     RECT  72.396 6.691 72.954 7.231 ;
     RECT  2.304 6.611 2.97 7.291 ;
     RECT  4.032 6.781 4.05 7.321 ;
     RECT  72.396 7.231 73.278 7.349 ;
     RECT  78.015 7.195 78.966 7.349 ;
     RECT  58.032 7.195 58.05 7.357 ;
     RECT  74.304 7.195 74.322 7.357 ;
     RECT  82.872 6.961 83.898 7.385 ;
     RECT  4.032 7.321 4.338 7.393 ;
     RECT  2.16 7.291 2.97 7.421 ;
     RECT  72.396 7.349 73.098 7.421 ;
     RECT  34.815 6.817 41.958 7.465 ;
     RECT  74.304 7.357 74.574 7.501 ;
     RECT  43.236 7.465 43.398 7.591 ;
     RECT  74.052 7.501 75.51 7.619 ;
     RECT  78.015 7.349 78.462 7.619 ;
     RECT  82.08 6.647 82.098 7.655 ;
     RECT  43.236 7.591 43.974 7.691 ;
     RECT  75.492 7.619 75.51 7.763 ;
     RECT  2.415 7.421 2.97 7.771 ;
     RECT  4.032 7.393 4.482 7.771 ;
     RECT  43.236 7.691 43.938 7.771 ;
     RECT  54.72 7.663 54.738 7.799 ;
     RECT  85.464 2.395 85.482 7.819 ;
     RECT  0.108 7.723 0.126 7.853 ;
     RECT  7.815 2.413 8.097 7.861 ;
     RECT  83.415 7.385 83.898 7.861 ;
     RECT  6.552 7.735 6.57 7.867 ;
     RECT  6.408 7.867 6.57 7.889 ;
     RECT  43.128 7.771 43.938 7.889 ;
     RECT  6.408 7.889 6.426 7.925 ;
     RECT  34.815 7.465 42.174 7.925 ;
     RECT  43.92 7.889 43.938 7.925 ;
     RECT  57.924 7.357 58.05 7.925 ;
     RECT  84.888 7.819 85.482 7.933 ;
     RECT  74.052 7.619 74.574 8.005 ;
     RECT  78.015 7.619 78.297 8.041 ;
     RECT  83.415 7.861 83.97 8.131 ;
     RECT  43.128 7.889 43.146 8.159 ;
     RECT  58.608 8.005 58.626 8.195 ;
     RECT  84.888 7.933 85.518 8.231 ;
     RECT  72.396 7.421 72.897 8.275 ;
     RECT  2.415 7.771 4.482 8.303 ;
     RECT  45.615 4.541 45.897 8.311 ;
     RECT  72.288 8.275 72.897 8.311 ;
     RECT  73.98 8.005 74.574 8.311 ;
     RECT  72.288 8.311 74.574 8.333 ;
     RECT  82.656 8.131 83.97 8.339 ;
     RECT  85.464 8.231 85.518 8.381 ;
     RECT  2.415 8.303 3.222 8.429 ;
     RECT  46.764 8.311 46.782 8.429 ;
     RECT  70.884 8.311 70.974 8.429 ;
     RECT  77.76 8.041 78.297 8.429 ;
     RECT  45.108 8.311 45.897 8.437 ;
     RECT  78.015 8.429 78.297 8.437 ;
     RECT  70.956 8.429 70.974 8.465 ;
     RECT  72.615 8.333 74.574 8.465 ;
     RECT  82.764 8.339 83.97 8.465 ;
     RECT  44.964 8.437 45.897 8.477 ;
     RECT  72.615 8.465 73.854 8.501 ;
     RECT  45.468 8.477 45.897 8.537 ;
     RECT  83.415 8.465 83.97 8.545 ;
     RECT  0.54 8.473 0.558 8.909 ;
     RECT  6.264 7.933 6.282 8.941 ;
     RECT  78.015 8.437 78.678 8.941 ;
     RECT  72.615 8.501 73.062 8.969 ;
     RECT  34.815 7.925 41.742 9.077 ;
     RECT  7.344 7.861 8.097 9.113 ;
     RECT  78.015 8.941 78.75 9.113 ;
     RECT  6.264 8.941 6.534 9.211 ;
     RECT  34.815 9.077 37.962 9.239 ;
     RECT  83.415 8.545 84.042 9.239 ;
     RECT  7.815 9.113 8.097 9.247 ;
     RECT  38.7 9.077 41.742 9.247 ;
     RECT  35.82 9.239 37.962 9.275 ;
     RECT  7.815 9.247 8.334 9.283 ;
     RECT  6.264 9.211 6.858 9.341 ;
     RECT  7.815 9.283 8.622 9.341 ;
     RECT  30.78 9.247 30.798 9.419 ;
     RECT  72.615 8.969 72.897 9.481 ;
     RECT  73.836 8.501 73.854 9.481 ;
     RECT  7.815 9.341 8.334 9.509 ;
     RECT  35.82 9.275 37.926 9.509 ;
     RECT  2.415 8.429 3.114 9.547 ;
     RECT  59.22 9.517 59.238 9.553 ;
     RECT  0.108 9.451 0.126 9.581 ;
     RECT  9.576 9.391 9.594 9.581 ;
     RECT  73.656 9.481 73.854 9.581 ;
     RECT  72.576 9.481 72.897 9.617 ;
     RECT  59.22 9.553 59.274 9.625 ;
     RECT  73.836 9.581 73.854 9.643 ;
     RECT  74.664 9.391 74.682 9.643 ;
     RECT  58.932 9.625 59.274 9.653 ;
     RECT  73.836 9.643 74.682 9.653 ;
     RECT  43.956 9.643 43.974 9.661 ;
     RECT  74.124 9.653 74.682 9.661 ;
     RECT  43.956 9.661 44.118 9.689 ;
     RECT  45.615 8.537 45.897 9.691 ;
     RECT  6.264 9.341 6.822 9.739 ;
     RECT  6.048 9.739 6.822 9.751 ;
     RECT  78.015 9.113 78.642 9.779 ;
     RECT  58.932 9.653 59.238 9.815 ;
     RECT  46.764 9.751 46.782 9.823 ;
     RECT  5.976 9.751 6.822 9.851 ;
     RECT  42.732 9.625 42.75 9.851 ;
     RECT  4.464 8.303 4.482 9.859 ;
     RECT  82.44 9.661 82.458 9.887 ;
     RECT  4.464 9.859 4.59 9.895 ;
     RECT  54.72 9.823 54.738 9.923 ;
     RECT  2.415 9.547 3.366 9.931 ;
     RECT  4.464 9.895 5.274 9.931 ;
     RECT  45.468 9.691 45.897 9.931 ;
     RECT  46.764 9.823 46.818 9.931 ;
     RECT  37.908 9.509 37.926 10.021 ;
     RECT  38.7 9.247 41.814 10.021 ;
     RECT  2.415 9.931 5.274 10.049 ;
     RECT  44.1 9.689 44.118 10.049 ;
     RECT  6.264 9.851 6.822 10.157 ;
     RECT  34.815 9.239 35.097 10.165 ;
     RECT  35.82 9.509 37.062 10.165 ;
     RECT  83.415 9.239 83.898 10.165 ;
     RECT  37.908 10.021 41.814 10.193 ;
     RECT  45.468 9.931 46.818 10.205 ;
     RECT  44.532 10.165 44.622 10.319 ;
     RECT  83.415 10.165 84.042 10.319 ;
     RECT  44.532 10.319 44.55 10.391 ;
     RECT  81.504 10.201 81.522 10.427 ;
     RECT  34.815 10.165 37.062 10.435 ;
     RECT  37.908 10.193 41.31 10.435 ;
     RECT  2.415 10.049 4.59 10.471 ;
     RECT  43.668 10.435 43.686 10.471 ;
     RECT  72.615 9.617 72.897 10.471 ;
     RECT  74.124 9.661 74.754 10.471 ;
     RECT  72.615 10.471 75.51 10.541 ;
     RECT  43.56 10.471 43.686 10.561 ;
     RECT  2.304 10.471 4.59 10.589 ;
     RECT  45.615 10.205 46.818 10.589 ;
     RECT  59.22 9.815 59.238 10.589 ;
     RECT  75.06 10.541 75.51 10.589 ;
     RECT  72.615 10.541 74.322 10.625 ;
     RECT  61.815 2.413 62.097 10.633 ;
     RECT  74.304 10.625 74.322 10.661 ;
     RECT  59.292 10.597 59.31 10.697 ;
     RECT  72.615 10.625 73.35 10.697 ;
     RECT  82.62 10.597 82.638 10.697 ;
     RECT  43.236 10.561 43.686 10.699 ;
     RECT  61.815 10.633 62.694 10.733 ;
     RECT  75.492 10.589 75.51 10.733 ;
     RECT  42.804 10.699 43.686 10.741 ;
     RECT  46.62 10.589 46.818 10.741 ;
     RECT  2.304 10.589 4.446 10.769 ;
     RECT  32.04 10.669 32.058 10.859 ;
     RECT  46.62 10.741 46.962 10.877 ;
     RECT  58.356 10.669 58.374 10.895 ;
     RECT  2.304 10.769 4.41 10.931 ;
     RECT  42.732 10.741 43.686 10.931 ;
     RECT  54.72 10.903 54.738 11.039 ;
     RECT  34.815 10.435 41.31 11.101 ;
     RECT  67.215 2.413 67.497 11.101 ;
     RECT  68.22 11.011 68.238 11.101 ;
     RECT  6.156 10.705 6.174 11.129 ;
     RECT  67.215 11.101 68.238 11.137 ;
     RECT  5.22 10.795 5.238 11.165 ;
     RECT  34.815 11.101 41.346 11.165 ;
     RECT  42.732 10.931 42.822 11.165 ;
     RECT  36 11.165 41.346 11.201 ;
     RECT  34.815 11.165 35.097 11.209 ;
     RECT  83.415 10.319 83.898 11.245 ;
     RECT  31.932 11.011 31.95 11.273 ;
     RECT  36 11.201 41.274 11.273 ;
     RECT  42.732 11.165 42.75 11.273 ;
     RECT  43.668 10.931 43.686 11.281 ;
     RECT  55.332 11.137 55.35 11.281 ;
     RECT  66.744 11.137 68.238 11.281 ;
     RECT  78.015 9.779 78.297 11.281 ;
     RECT  6.84 11.209 6.858 11.309 ;
     RECT  34.776 11.209 35.097 11.309 ;
     RECT  66.744 11.281 68.958 11.309 ;
     RECT  46.728 10.877 46.962 11.371 ;
     RECT  56.415 5.765 56.697 11.371 ;
     RECT  2.304 10.931 3.726 11.399 ;
     RECT  55.332 11.281 55.458 11.399 ;
     RECT  75.636 11.011 75.942 11.399 ;
     RECT  78.015 11.281 78.642 11.399 ;
     RECT  55.332 11.399 55.35 11.435 ;
     RECT  75.636 11.399 75.798 11.435 ;
     RECT  51.015 2.413 51.297 11.551 ;
     RECT  85.464 8.381 85.482 11.611 ;
     RECT  43.668 11.281 43.83 11.641 ;
     RECT  44.604 11.371 44.622 11.641 ;
     RECT  56.415 11.371 56.79 11.705 ;
     RECT  75.636 11.435 75.654 11.705 ;
     RECT  50.472 11.551 51.297 11.713 ;
     RECT  36 11.273 41.202 11.741 ;
     RECT  67.215 11.309 68.958 11.741 ;
     RECT  43.668 11.641 44.622 11.749 ;
     RECT  45.615 10.589 45.897 11.749 ;
     RECT  84.888 11.611 85.482 11.777 ;
     RECT  43.668 11.749 45.897 11.821 ;
     RECT  46.728 11.371 47.034 11.821 ;
     RECT  36 11.741 41.058 11.837 ;
     RECT  43.668 11.821 47.034 11.911 ;
     RECT  36 11.837 40.986 11.939 ;
     RECT  50.076 11.713 51.297 11.941 ;
     RECT  3.42 11.399 3.726 11.947 ;
     RECT  43.668 11.911 47.394 11.947 ;
     RECT  67.215 11.741 67.986 11.975 ;
     RECT  48.564 11.947 48.582 11.983 ;
     RECT  49.932 11.941 51.297 12.019 ;
     RECT  36 11.939 40.734 12.043 ;
     RECT  42.984 11.947 47.394 12.043 ;
     RECT  48.168 11.983 48.582 12.043 ;
     RECT  49.788 12.019 51.297 12.091 ;
     RECT  42.984 12.043 48.582 12.181 ;
     RECT  35.82 12.043 40.734 12.209 ;
     RECT  34.815 11.309 35.097 12.217 ;
     RECT  35.82 12.209 40.59 12.217 ;
     RECT  34.815 12.217 40.59 12.245 ;
     RECT  5.436 12.091 5.454 12.253 ;
     RECT  83.415 11.245 84.042 12.253 ;
     RECT  3.42 11.947 4.122 12.281 ;
     RECT  3.636 12.281 4.122 12.325 ;
     RECT  5.22 12.253 5.454 12.325 ;
     RECT  70.056 12.217 70.074 12.325 ;
     RECT  82.692 12.253 84.042 12.353 ;
     RECT  60.192 12.091 60.21 12.361 ;
     RECT  70.02 12.325 70.074 12.361 ;
     RECT  76.572 12.181 76.59 12.361 ;
     RECT  78.015 11.399 78.297 12.361 ;
     RECT  2.304 11.399 2.697 12.389 ;
     RECT  61.815 10.733 62.097 12.451 ;
     RECT  68.832 11.741 68.958 12.451 ;
     RECT  69.912 12.361 70.074 12.451 ;
     RECT  72.615 10.697 72.897 12.475 ;
     RECT  3.636 12.325 5.454 12.479 ;
     RECT  60.084 12.361 60.21 12.479 ;
     RECT  76.104 12.361 76.59 12.479 ;
     RECT  83.232 12.353 84.042 12.479 ;
     RECT  2.415 12.389 2.697 12.487 ;
     RECT  5.04 12.479 5.454 12.487 ;
     RECT  60.084 12.479 60.102 12.515 ;
     RECT  68.832 12.451 70.074 12.515 ;
     RECT  78.015 12.361 78.75 12.515 ;
     RECT  72.615 12.475 73.134 12.517 ;
     RECT  42.984 12.181 48.762 12.523 ;
     RECT  49.788 12.091 51.498 12.523 ;
     RECT  68.832 12.515 69.534 12.523 ;
     RECT  61.815 12.451 62.73 12.551 ;
     RECT  34.815 12.245 40.497 12.557 ;
     RECT  42.984 12.523 51.606 12.631 ;
     RECT  0.54 12.523 0.558 12.701 ;
     RECT  85.464 11.777 85.482 12.701 ;
     RECT  42.984 12.631 51.966 12.721 ;
     RECT  72.615 12.517 73.206 12.721 ;
     RECT  2.415 12.487 2.898 12.749 ;
     RECT  68.58 12.523 69.534 12.749 ;
     RECT  59.436 12.523 59.454 12.785 ;
     RECT  76.104 12.479 76.122 12.785 ;
     RECT  69.516 12.749 69.534 12.821 ;
     RECT  72.615 12.721 73.278 12.821 ;
     RECT  42.984 12.721 52.11 12.857 ;
     RECT  5.04 12.487 5.706 12.893 ;
     RECT  6.84 12.631 6.858 12.929 ;
     RECT  42.984 12.857 51.534 12.929 ;
     RECT  83.232 12.479 83.898 12.929 ;
     RECT  4.104 12.479 4.122 12.941 ;
     RECT  41.94 12.865 41.958 12.991 ;
     RECT  35.928 12.557 40.497 13.051 ;
     RECT  41.616 12.991 42.174 13.051 ;
     RECT  42.984 12.929 51.354 13.051 ;
     RECT  35.928 13.051 51.354 13.085 ;
     RECT  5.04 12.893 5.058 13.091 ;
     RECT  2.415 12.749 2.862 13.195 ;
     RECT  85.5 13.063 85.518 13.229 ;
     RECT  2.412 13.195 2.862 13.289 ;
     RECT  83.415 12.929 83.898 13.405 ;
     RECT  78.015 12.515 78.297 13.441 ;
     RECT  70.56 12.721 70.722 13.531 ;
     RECT  77.544 13.441 78.297 13.559 ;
     RECT  78.015 13.559 78.297 13.567 ;
     RECT  35.964 13.085 51.354 13.595 ;
     RECT  70.56 13.531 70.794 13.595 ;
     RECT  82.656 13.441 82.674 13.595 ;
     RECT  78.015 13.567 78.678 13.667 ;
     RECT  40.104 13.595 51.354 13.711 ;
     RECT  60.408 13.567 60.426 13.711 ;
     RECT  4.536 13.639 4.554 13.829 ;
     RECT  40.104 13.711 51.498 13.829 ;
     RECT  60.408 13.711 60.534 13.829 ;
     RECT  69.552 13.639 69.57 13.829 ;
     RECT  60.408 13.829 60.426 13.865 ;
     RECT  2.415 13.289 2.862 13.867 ;
     RECT  0.108 13.771 0.126 13.901 ;
     RECT  72.615 12.821 72.897 13.915 ;
     RECT  2.415 13.867 2.934 13.945 ;
     RECT  2.415 13.945 3.618 13.997 ;
     RECT  72.468 13.915 72.897 14.107 ;
     RECT  52.02 13.981 52.038 14.207 ;
     RECT  0.504 14.143 0.522 14.215 ;
     RECT  5.796 13.981 5.814 14.215 ;
     RECT  53.928 14.071 53.946 14.215 ;
     RECT  5.724 14.215 5.814 14.243 ;
     RECT  53.712 14.215 53.946 14.251 ;
     RECT  0.504 14.215 0.558 14.333 ;
     RECT  2.415 13.997 2.934 14.369 ;
     RECT  27.252 14.251 27.27 14.369 ;
     RECT  35.964 13.595 39.366 14.395 ;
     RECT  40.104 13.829 51.297 14.395 ;
     RECT  82.26 14.341 82.674 14.441 ;
     RECT  70.776 13.595 70.794 14.449 ;
     RECT  53.712 14.251 54.306 14.477 ;
     RECT  7.815 9.509 8.097 14.491 ;
     RECT  35.964 14.395 51.297 14.513 ;
     RECT  74.376 14.347 74.394 14.521 ;
     RECT  53.712 14.477 53.874 14.525 ;
     RECT  61.815 12.551 62.097 14.611 ;
     RECT  70.74 14.449 70.794 14.611 ;
     RECT  72.468 14.107 72.954 14.611 ;
     RECT  53.856 14.525 53.874 14.639 ;
     RECT  64.152 14.251 64.17 14.639 ;
     RECT  78.015 13.667 78.642 14.639 ;
     RECT  35.964 14.513 45.897 14.647 ;
     RECT  67.215 11.975 67.497 14.647 ;
     RECT  3.996 14.107 4.518 14.675 ;
     RECT  7.38 14.491 8.097 14.675 ;
     RECT  27.324 14.521 27.342 14.675 ;
     RECT  46.62 14.513 51.297 14.675 ;
     RECT  74.052 14.521 74.718 14.675 ;
     RECT  66.708 14.647 67.497 14.747 ;
     RECT  72.144 14.611 72.954 14.747 ;
     RECT  74.052 14.675 74.682 14.747 ;
     RECT  82.404 14.441 82.674 14.747 ;
     RECT  75.636 14.521 75.654 14.755 ;
     RECT  64.404 14.683 64.422 14.783 ;
     RECT  72.615 14.747 72.954 14.783 ;
     RECT  3.996 14.675 4.122 14.791 ;
     RECT  7.815 14.675 8.097 14.791 ;
     RECT  75.456 14.755 75.654 14.791 ;
     RECT  75.456 14.791 75.978 14.813 ;
     RECT  61.815 14.611 62.73 14.819 ;
     RECT  0.504 14.333 0.522 14.861 ;
     RECT  70.74 14.611 71.19 14.881 ;
     RECT  79.74 14.521 79.758 14.909 ;
     RECT  61.815 14.819 62.097 14.917 ;
     RECT  3.924 14.791 4.122 14.981 ;
     RECT  75.96 14.813 75.978 14.981 ;
     RECT  70.632 14.881 71.19 15.017 ;
     RECT  3.924 14.981 3.942 15.025 ;
     RECT  35.892 14.647 45.897 15.089 ;
     RECT  71.172 15.017 71.19 15.089 ;
     RECT  39.312 15.089 45.897 15.179 ;
     RECT  54.648 14.521 54.666 15.251 ;
     RECT  34.815 12.557 35.097 15.259 ;
     RECT  39.924 15.179 45.897 15.295 ;
     RECT  46.62 14.675 48.51 15.295 ;
     RECT  49.392 14.675 51.297 15.295 ;
     RECT  2.415 14.369 2.862 15.307 ;
     RECT  3.6 15.025 3.942 15.307 ;
     RECT  34.776 15.259 35.097 15.359 ;
     RECT  0.108 14.953 0.126 15.389 ;
     RECT  74.664 14.747 74.682 15.403 ;
     RECT  78.015 14.639 78.297 15.421 ;
     RECT  82.548 14.747 82.674 15.421 ;
     RECT  83.415 13.405 84.042 15.421 ;
     RECT  74.664 15.403 74.754 15.449 ;
     RECT  39.924 15.295 48.51 15.451 ;
     RECT  49.392 15.295 51.606 15.451 ;
     RECT  61.632 14.917 62.097 15.485 ;
     RECT  85.464 13.771 85.482 15.485 ;
     RECT  7.815 14.791 8.334 15.593 ;
     RECT  54.72 15.421 54.738 15.593 ;
     RECT  82.548 15.421 84.042 15.593 ;
     RECT  2.415 15.307 3.942 15.601 ;
     RECT  24.015 2.413 24.297 15.601 ;
     RECT  6.84 15.601 6.858 15.719 ;
     RECT  24.015 15.601 24.93 15.719 ;
     RECT  53.748 15.565 53.766 15.719 ;
     RECT  35.892 15.089 38.214 15.755 ;
     RECT  39.924 15.451 51.606 15.763 ;
     RECT  52.38 15.601 53.01 15.763 ;
     RECT  5.724 14.243 5.742 15.791 ;
     RECT  22.824 15.727 22.842 15.827 ;
     RECT  2.376 15.601 3.942 15.835 ;
     RECT  38.016 15.755 38.214 15.835 ;
     RECT  38.016 15.835 38.25 15.871 ;
     RECT  6.912 15.727 6.93 15.899 ;
     RECT  39.924 15.763 53.01 15.899 ;
     RECT  52.812 15.899 53.01 15.931 ;
     RECT  52.812 15.931 53.334 15.965 ;
     RECT  52.956 15.965 53.334 15.989 ;
     RECT  39.924 15.899 51.93 15.997 ;
     RECT  63.216 15.727 63.234 16.025 ;
     RECT  2.376 15.835 4.41 16.105 ;
     RECT  2.376 16.105 4.446 16.141 ;
     RECT  5.4 15.835 5.418 16.141 ;
     RECT  34.815 15.359 35.097 16.141 ;
     RECT  39.672 15.997 51.93 16.141 ;
     RECT  74.484 15.601 74.502 16.141 ;
     RECT  34.776 16.141 35.097 16.231 ;
     RECT  35.892 15.755 37.206 16.231 ;
     RECT  82.62 15.593 84.042 16.295 ;
     RECT  64.296 16.231 64.314 16.303 ;
     RECT  2.376 16.141 5.418 16.331 ;
     RECT  82.62 16.295 82.674 16.331 ;
     RECT  39.348 16.141 51.93 16.375 ;
     RECT  73.908 16.141 74.502 16.375 ;
     RECT  39.276 16.375 51.93 16.397 ;
     RECT  2.376 16.331 5.202 16.411 ;
     RECT  38.016 15.871 38.286 16.411 ;
     RECT  39.276 16.397 39.366 16.411 ;
     RECT  55.656 16.141 55.674 16.411 ;
     RECT  61.815 15.485 62.097 16.411 ;
     RECT  72.615 14.783 72.897 16.411 ;
     RECT  73.728 16.375 74.502 16.411 ;
     RECT  78.015 15.421 78.966 16.411 ;
     RECT  82.08 16.339 82.098 16.411 ;
     RECT  55.584 16.411 55.674 16.439 ;
     RECT  84.888 15.931 84.906 16.459 ;
     RECT  54.612 16.261 54.63 16.501 ;
     RECT  38.016 16.411 39.366 16.529 ;
     RECT  55.584 16.439 55.602 16.529 ;
     RECT  64.188 16.303 64.314 16.529 ;
     RECT  64.188 16.529 64.206 16.565 ;
     RECT  72.615 16.411 75.006 16.601 ;
     RECT  81.504 16.411 82.098 16.601 ;
     RECT  52.992 15.989 53.334 16.673 ;
     RECT  34.776 16.231 37.206 16.681 ;
     RECT  38.016 16.529 39.006 16.681 ;
     RECT  61.815 16.411 62.766 16.799 ;
     RECT  75.168 16.681 75.798 16.799 ;
     RECT  78.015 16.411 79.002 16.799 ;
     RECT  78.015 16.799 78.894 16.835 ;
     RECT  34.776 16.681 39.006 16.871 ;
     RECT  81.504 16.601 81.522 16.907 ;
     RECT  54.144 16.501 54.63 16.943 ;
     RECT  75.78 16.799 75.798 16.943 ;
     RECT  72.615 16.601 74.286 16.951 ;
     RECT  34.776 16.871 35.097 17.069 ;
     RECT  54.684 16.951 54.702 17.069 ;
     RECT  62.964 16.951 62.982 17.069 ;
     RECT  72.108 16.951 74.286 17.069 ;
     RECT  83.415 16.295 84.042 17.069 ;
     RECT  72.108 17.069 73.782 17.105 ;
     RECT  53.316 16.673 53.334 17.117 ;
     RECT  72.615 17.105 73.782 17.117 ;
     RECT  29.415 2.413 29.697 17.221 ;
     RECT  40.14 16.397 51.93 17.221 ;
     RECT  78.015 16.835 78.297 17.311 ;
     RECT  84.888 16.459 85.482 17.375 ;
     RECT  83.415 17.069 83.898 17.419 ;
     RECT  6.084 17.083 6.102 17.491 ;
     RECT  40.14 17.221 52.11 17.491 ;
     RECT  70.704 16.645 70.722 17.491 ;
     RECT  83.232 17.419 83.898 17.491 ;
     RECT  40.14 17.491 52.182 17.549 ;
     RECT  6.084 17.491 6.246 17.581 ;
     RECT  28.908 17.221 29.697 17.609 ;
     RECT  70.704 17.491 71.154 17.609 ;
     RECT  77.94 17.311 78.297 17.609 ;
     RECT  6.084 17.581 6.75 17.645 ;
     RECT  70.704 17.609 70.722 17.645 ;
     RECT  82.836 17.491 83.898 17.645 ;
     RECT  2.304 16.411 5.202 17.653 ;
     RECT  35.82 16.871 39.006 17.681 ;
     RECT  40.14 17.549 52.11 17.681 ;
     RECT  53.1 17.491 53.118 17.681 ;
     RECT  73.764 17.117 73.782 17.681 ;
     RECT  34.815 17.069 35.097 17.851 ;
     RECT  35.82 17.681 37.026 17.851 ;
     RECT  83.232 17.645 83.898 17.987 ;
     RECT  40.14 17.681 51.858 18.023 ;
     RECT  38.232 17.681 39.006 18.031 ;
     RECT  40.14 18.023 51.498 18.031 ;
     RECT  34.815 17.851 37.026 18.149 ;
     RECT  38.232 18.031 51.498 18.149 ;
     RECT  42.48 18.149 51.498 18.185 ;
     RECT  6.228 17.645 6.75 18.221 ;
     RECT  34.815 18.149 35.838 18.221 ;
     RECT  38.232 18.149 41.598 18.221 ;
     RECT  35.82 18.221 35.838 18.269 ;
     RECT  39.816 18.221 41.598 18.293 ;
     RECT  6.228 18.221 6.246 18.419 ;
     RECT  76.608 18.301 76.626 18.419 ;
     RECT  70.416 18.235 70.578 18.427 ;
     RECT  2.304 17.653 5.274 18.461 ;
     RECT  4.248 18.461 5.274 18.491 ;
     RECT  36.972 18.149 37.026 18.499 ;
     RECT  38.232 18.221 39.006 18.499 ;
     RECT  5.184 18.491 5.274 18.563 ;
     RECT  82.404 18.301 82.422 18.563 ;
     RECT  70.416 18.427 70.686 18.571 ;
     RECT  67.215 14.747 67.497 18.661 ;
     RECT  70.056 18.571 70.686 18.661 ;
     RECT  42.696 18.185 51.498 18.689 ;
     RECT  70.056 18.661 70.794 18.689 ;
     RECT  60.66 18.571 60.678 18.697 ;
     RECT  70.668 18.689 70.794 18.725 ;
     RECT  36.972 18.499 39.006 18.761 ;
     RECT  53.568 18.661 53.586 18.763 ;
     RECT  60.408 18.697 60.678 18.769 ;
     RECT  36.972 18.761 36.99 18.797 ;
     RECT  54.684 18.571 54.702 18.797 ;
     RECT  70.704 18.725 70.794 18.797 ;
     RECT  34.815 18.221 35.097 18.841 ;
     RECT  67.215 18.661 68.202 18.841 ;
     RECT  75.636 18.661 75.654 18.841 ;
     RECT  83.415 17.987 83.898 18.841 ;
     RECT  4.248 18.491 4.41 18.959 ;
     RECT  53.208 18.763 53.586 18.959 ;
     RECT  60.408 18.769 60.822 18.959 ;
     RECT  60.408 18.959 60.678 18.995 ;
     RECT  75.636 18.841 75.762 18.995 ;
     RECT  83.415 18.841 84.042 18.995 ;
     RECT  2.304 18.461 3.474 19.031 ;
     RECT  53.568 18.959 53.586 19.031 ;
     RECT  42.696 18.689 51.297 19.039 ;
     RECT  70.704 18.797 70.722 19.067 ;
     RECT  37.764 18.761 39.006 19.075 ;
     RECT  39.816 18.293 41.526 19.075 ;
     RECT  52.02 18.841 52.038 19.103 ;
     RECT  37.764 19.075 41.526 19.111 ;
     RECT  42.408 19.039 51.297 19.111 ;
     RECT  4.248 18.959 4.266 19.133 ;
     RECT  67.215 18.841 68.526 19.139 ;
     RECT  2.304 19.031 3.294 19.229 ;
     RECT  34.776 18.841 35.097 19.229 ;
     RECT  37.764 19.111 51.297 19.265 ;
     RECT  52.704 19.111 52.722 19.265 ;
     RECT  5.184 18.563 5.202 19.373 ;
     RECT  42.696 19.265 51.297 19.373 ;
     RECT  67.215 19.139 67.497 19.471 ;
     RECT  75.78 19.201 75.798 19.535 ;
     RECT  37.764 19.265 41.706 19.579 ;
     RECT  68.4 19.139 68.526 19.615 ;
     RECT  47.556 19.373 51.297 19.643 ;
     RECT  56.415 11.705 56.697 19.651 ;
     RECT  37.62 19.579 41.706 19.679 ;
     RECT  47.556 19.643 48.366 19.769 ;
     RECT  49.212 19.643 51.297 19.769 ;
     RECT  68.4 19.615 68.85 19.769 ;
     RECT  49.284 19.769 51.297 19.805 ;
     RECT  66.852 19.471 67.497 19.805 ;
     RECT  37.62 19.679 41.454 19.877 ;
     RECT  42.696 19.373 46.782 19.877 ;
     RECT  49.572 19.805 51.297 19.877 ;
     RECT  58.716 19.777 58.734 19.877 ;
     RECT  50.112 19.877 51.297 19.913 ;
     RECT  2.304 19.229 2.697 19.949 ;
     RECT  37.62 19.877 38.97 19.949 ;
     RECT  50.112 19.913 50.13 19.949 ;
     RECT  3.78 19.921 3.798 20.011 ;
     RECT  47.556 19.769 48.222 20.119 ;
     RECT  40.104 19.877 41.454 20.141 ;
     RECT  40.215 20.141 41.454 20.147 ;
     RECT  2.415 19.949 2.697 20.191 ;
     RECT  3.672 20.011 3.798 20.191 ;
     RECT  68.472 19.769 68.85 20.191 ;
     RECT  78.015 17.609 78.297 20.281 ;
     RECT  75.636 19.741 75.762 20.309 ;
     RECT  56.415 19.651 56.826 20.317 ;
     RECT  75.636 20.309 75.654 20.345 ;
     RECT  85.464 17.375 85.482 20.345 ;
     RECT  42.696 19.877 44.046 20.389 ;
     RECT  56.415 20.317 56.862 20.389 ;
     RECT  78.015 20.281 78.642 20.417 ;
     RECT  3.636 20.191 3.798 20.461 ;
     RECT  42.588 20.389 44.046 20.461 ;
     RECT  44.928 19.877 46.782 20.461 ;
     RECT  47.52 20.119 48.222 20.461 ;
     RECT  2.415 20.191 2.826 20.539 ;
     RECT  3.636 20.461 4.23 20.539 ;
     RECT  2.415 20.539 4.23 20.551 ;
     RECT  41.436 20.147 41.454 20.551 ;
     RECT  44.928 20.461 48.222 20.551 ;
     RECT  68.472 20.191 68.994 20.551 ;
     RECT  69.768 19.651 69.786 20.551 ;
     RECT  56.415 20.389 56.97 20.579 ;
     RECT  2.415 20.551 4.806 20.587 ;
     RECT  56.415 20.579 56.862 20.615 ;
     RECT  75.204 20.389 75.222 20.615 ;
     RECT  42.372 20.461 44.046 20.695 ;
     RECT  44.928 20.551 49.014 20.695 ;
     RECT  2.415 20.587 5.058 20.731 ;
     RECT  6.984 20.587 7.002 20.731 ;
     RECT  42.372 20.695 49.014 20.731 ;
     RECT  68.472 20.551 69.786 20.731 ;
     RECT  6.912 20.731 7.002 20.759 ;
     RECT  68.22 20.731 69.786 20.759 ;
     RECT  42.372 20.731 49.05 20.779 ;
     RECT  34.815 19.229 35.097 20.821 ;
     RECT  37.728 19.949 38.97 20.821 ;
     RECT  2.415 20.731 5.382 20.885 ;
     RECT  41.436 20.551 41.634 20.893 ;
     RECT  42.372 20.779 49.554 20.893 ;
     RECT  6.912 20.759 6.93 20.929 ;
     RECT  34.776 20.821 35.097 20.957 ;
     RECT  5.868 20.929 5.886 20.965 ;
     RECT  6.84 20.929 6.93 20.965 ;
     RECT  41.436 20.893 49.554 20.965 ;
     RECT  40.215 20.147 40.497 21.001 ;
     RECT  41.328 20.965 49.842 21.001 ;
     RECT  5.868 20.965 6.93 21.029 ;
     RECT  37.728 20.821 39.294 21.091 ;
     RECT  67.215 19.805 67.497 21.091 ;
     RECT  68.22 20.759 68.814 21.091 ;
     RECT  5.868 21.029 6.354 21.119 ;
     RECT  37.656 21.091 39.33 21.119 ;
     RECT  51.015 19.913 51.297 21.127 ;
     RECT  53.244 21.091 53.262 21.149 ;
     RECT  67.215 21.091 68.814 21.155 ;
     RECT  69.588 20.759 69.786 21.155 ;
     RECT  38.628 21.119 39.33 21.163 ;
     RECT  40.215 21.001 49.842 21.163 ;
     RECT  60.732 21.127 60.75 21.163 ;
     RECT  6.336 21.119 6.354 21.263 ;
     RECT  2.415 20.885 5.13 21.271 ;
     RECT  38.628 21.163 49.842 21.271 ;
     RECT  50.724 21.127 51.297 21.271 ;
     RECT  54.648 21.163 54.666 21.271 ;
     RECT  60.192 21.163 60.75 21.271 ;
     RECT  70.848 21.115 70.866 21.271 ;
     RECT  78.015 20.417 78.297 21.271 ;
     RECT  82.656 21.001 82.674 21.271 ;
     RECT  0.108 20.251 0.126 21.341 ;
     RECT  84.888 20.779 84.906 21.341 ;
     RECT  67.215 21.155 67.734 21.361 ;
     RECT  2.34 21.271 5.13 21.389 ;
     RECT  38.628 21.271 51.498 21.389 ;
     RECT  54.18 21.271 54.666 21.389 ;
     RECT  60.156 21.271 60.75 21.389 ;
     RECT  76.284 21.091 76.302 21.389 ;
     RECT  61.815 16.799 62.097 21.397 ;
     RECT  2.34 21.389 4.23 21.425 ;
     RECT  68.724 21.155 68.814 21.425 ;
     RECT  70.128 21.271 71.01 21.425 ;
     RECT  82.512 21.271 82.674 21.425 ;
     RECT  5.112 21.389 5.13 21.461 ;
     RECT  66.708 21.361 67.734 21.461 ;
     RECT  60.156 21.389 60.174 21.469 ;
     RECT  38.628 21.389 51.354 21.497 ;
     RECT  54.18 21.389 54.27 21.497 ;
     RECT  66.708 21.461 67.497 21.497 ;
     RECT  68.724 21.425 68.742 21.497 ;
     RECT  83.415 18.995 83.898 21.505 ;
     RECT  61.815 21.397 62.766 21.533 ;
     RECT  70.236 21.425 71.01 21.533 ;
     RECT  70.56 21.533 71.01 21.541 ;
     RECT  70.56 21.541 71.298 21.643 ;
     RECT  72.615 17.117 72.897 21.643 ;
     RECT  37.656 21.119 37.818 21.659 ;
     RECT  54.18 21.497 54.198 21.659 ;
     RECT  70.56 21.643 72.897 21.659 ;
     RECT  77.364 21.271 78.297 21.659 ;
     RECT  70.848 21.659 72.897 21.677 ;
     RECT  60.084 21.469 60.174 21.695 ;
     RECT  71.28 21.677 72.897 21.695 ;
     RECT  82.656 21.425 82.674 21.695 ;
     RECT  4.212 21.425 4.23 21.731 ;
     RECT  2.34 21.425 3.366 21.835 ;
     RECT  37.8 21.659 37.818 21.901 ;
     RECT  38.628 21.497 51.297 21.901 ;
     RECT  56.415 20.615 56.697 22.081 ;
     RECT  37.8 21.901 51.297 22.271 ;
     RECT  37.8 22.271 47.07 22.343 ;
     RECT  2.304 21.835 3.366 22.441 ;
     RECT  38.088 22.343 47.07 22.505 ;
     RECT  2.304 22.441 3.798 22.549 ;
     RECT  5.004 22.441 5.022 22.549 ;
     RECT  67.215 21.497 67.497 22.549 ;
     RECT  71.964 21.695 72.897 22.549 ;
     RECT  82.656 22.441 82.674 22.585 ;
     RECT  71.964 22.549 73.242 22.621 ;
     RECT  78.015 21.659 78.297 22.621 ;
     RECT  66.708 22.549 67.497 22.649 ;
     RECT  52.272 22.507 52.29 22.739 ;
     RECT  56.376 22.081 56.697 22.739 ;
     RECT  60.732 22.351 60.75 22.739 ;
     RECT  78.015 22.621 78.966 22.739 ;
     RECT  2.304 22.549 5.022 22.747 ;
     RECT  75.024 22.699 75.042 22.747 ;
     RECT  2.304 22.747 5.31 22.775 ;
     RECT  55.44 22.219 55.458 22.775 ;
     RECT  70.74 22.441 70.758 22.775 ;
     RECT  75.024 22.747 75.726 22.775 ;
     RECT  38.16 22.505 47.07 22.781 ;
     RECT  71.964 22.621 74.142 22.783 ;
     RECT  82.62 22.585 82.674 22.811 ;
     RECT  83.415 21.505 84.042 22.819 ;
     RECT  64.728 22.783 64.746 22.891 ;
     RECT  71.964 22.783 74.214 22.891 ;
     RECT  2.304 22.775 4.374 23.009 ;
     RECT  5.292 22.775 5.31 23.009 ;
     RECT  52.416 22.891 52.434 23.009 ;
     RECT  64.728 22.891 64.854 23.009 ;
     RECT  3.564 23.009 4.374 23.045 ;
     RECT  62.892 22.621 62.91 23.045 ;
     RECT  64.728 23.009 64.746 23.045 ;
     RECT  38.34 22.781 47.07 23.081 ;
     RECT  75.708 22.775 75.726 23.081 ;
     RECT  47.988 22.271 51.297 23.125 ;
     RECT  38.376 23.081 47.07 23.161 ;
     RECT  47.88 23.125 51.297 23.161 ;
     RECT  83.088 22.819 84.042 23.161 ;
     RECT  6.84 23.089 6.858 23.189 ;
     RECT  71.964 22.891 74.862 23.189 ;
     RECT  83.088 23.161 84.114 23.189 ;
     RECT  38.376 23.161 51.297 23.279 ;
     RECT  71.964 23.189 72.897 23.351 ;
     RECT  83.415 23.189 84.114 23.351 ;
     RECT  78.015 22.739 78.678 23.431 ;
     RECT  77.904 23.431 78.678 23.521 ;
     RECT  73.944 23.189 74.862 23.693 ;
     RECT  61.815 21.533 62.097 23.791 ;
     RECT  74.772 23.693 74.862 23.791 ;
     RECT  52.92 23.629 52.938 23.819 ;
     RECT  77.904 23.521 78.858 23.819 ;
     RECT  50.256 23.279 51.297 23.827 ;
     RECT  50.256 23.827 52.002 23.855 ;
     RECT  70.74 23.701 70.758 23.855 ;
     RECT  73.944 23.693 73.962 23.855 ;
     RECT  74.772 23.791 74.898 23.855 ;
     RECT  77.904 23.819 78.714 23.855 ;
     RECT  74.844 23.855 74.898 23.927 ;
     RECT  82.656 23.593 82.674 23.927 ;
     RECT  38.376 23.279 49.41 23.933 ;
     RECT  50.4 23.855 52.002 23.933 ;
     RECT  72.396 23.351 72.897 23.933 ;
     RECT  63.036 23.827 63.054 23.971 ;
     RECT  72.432 23.933 72.897 24.061 ;
     RECT  73.62 23.971 73.638 24.061 ;
     RECT  41.832 23.933 49.41 24.089 ;
     RECT  50.4 23.933 51.498 24.089 ;
     RECT  63.036 23.971 63.198 24.089 ;
     RECT  77.904 23.855 78.297 24.089 ;
     RECT  61.308 23.791 62.097 24.125 ;
     RECT  63.036 24.089 63.054 24.125 ;
     RECT  72.432 24.061 73.638 24.233 ;
     RECT  81.504 23.791 81.522 24.233 ;
     RECT  3.564 23.045 4.086 24.241 ;
     RECT  72.432 24.233 72.897 24.269 ;
     RECT  3.564 24.241 4.194 24.395 ;
     RECT  38.376 23.933 40.95 24.427 ;
     RECT  38.268 24.427 40.95 24.503 ;
     RECT  61.815 24.125 62.097 24.511 ;
     RECT  2.304 23.009 2.697 24.571 ;
     RECT  3.564 24.395 4.122 24.571 ;
     RECT  78.015 24.089 78.297 24.601 ;
     RECT  64.836 24.601 64.854 24.619 ;
     RECT  2.304 24.571 4.122 24.629 ;
     RECT  51.015 24.089 51.498 24.629 ;
     RECT  74.844 23.927 74.862 24.665 ;
     RECT  41.832 24.089 49.266 24.673 ;
     RECT  0.108 24.571 0.126 24.701 ;
     RECT  3.672 24.629 4.122 24.701 ;
     RECT  38.736 24.503 40.95 24.745 ;
     RECT  41.724 24.673 49.266 24.745 ;
     RECT  6.804 24.709 6.822 24.809 ;
     RECT  64.836 24.619 64.962 24.809 ;
     RECT  74.772 24.781 74.79 24.899 ;
     RECT  78.015 24.601 79.002 24.899 ;
     RECT  73.728 24.745 73.746 24.935 ;
     RECT  78.015 24.899 78.894 24.935 ;
     RECT  64.836 24.809 64.926 24.941 ;
     RECT  82.656 24.673 82.674 25.007 ;
     RECT  64.908 24.941 64.926 25.043 ;
     RECT  75.816 24.781 75.834 25.043 ;
     RECT  38.736 24.745 49.266 25.051 ;
     RECT  50.184 24.979 50.202 25.051 ;
     RECT  61.815 24.511 62.586 25.141 ;
     RECT  67.215 22.649 67.497 25.141 ;
     RECT  3.708 24.701 4.122 25.169 ;
     RECT  3.78 25.169 4.122 25.249 ;
     RECT  38.736 25.051 50.202 25.285 ;
     RECT  51.015 24.629 51.297 25.285 ;
     RECT  72.615 24.269 72.897 25.285 ;
     RECT  5.4 25.141 5.418 25.321 ;
     RECT  61.452 25.141 62.586 25.321 ;
     RECT  66.708 25.141 67.497 25.349 ;
     RECT  61.308 25.321 62.586 25.411 ;
     RECT  3.78 25.249 4.554 25.435 ;
     RECT  5.4 25.321 5.562 25.435 ;
     RECT  3.78 25.435 5.562 25.439 ;
     RECT  52.02 24.781 52.038 25.439 ;
     RECT  78.015 24.935 78.75 25.439 ;
     RECT  61.308 25.411 62.73 25.475 ;
     RECT  72.615 25.285 73.638 25.475 ;
     RECT  78.015 25.439 78.678 25.475 ;
     RECT  72.615 25.475 73.314 25.517 ;
     RECT  61.815 25.475 62.73 25.547 ;
     RECT  83.415 23.351 84.042 25.555 ;
     RECT  69.588 25.483 69.606 25.591 ;
     RECT  2.304 24.629 2.697 25.681 ;
     RECT  3.78 25.439 5.418 25.709 ;
     RECT  38.736 25.285 51.297 25.709 ;
     RECT  69.516 25.591 70.254 25.709 ;
     RECT  3.78 25.709 5.274 25.745 ;
     RECT  60.084 25.519 60.102 25.745 ;
     RECT  82.08 25.411 82.098 25.745 ;
     RECT  69.588 25.709 70.254 25.753 ;
     RECT  45.396 25.709 51.297 25.781 ;
     RECT  45.396 25.781 50.13 25.853 ;
     RECT  69.588 25.753 70.326 25.889 ;
     RECT  74.664 25.141 74.682 25.889 ;
     RECT  3.78 25.745 5.238 25.963 ;
     RECT  45.396 25.853 49.986 25.979 ;
     RECT  38.736 25.709 44.442 26.011 ;
     RECT  38.412 26.011 44.442 26.051 ;
     RECT  2.304 25.681 2.862 26.059 ;
     RECT  2.016 26.059 2.862 26.131 ;
     RECT  3.708 25.963 5.238 26.131 ;
     RECT  2.016 26.131 5.238 26.189 ;
     RECT  83.232 25.555 84.042 26.293 ;
     RECT  34.815 20.957 35.097 26.329 ;
     RECT  70.812 26.329 70.83 26.401 ;
     RECT  6.84 26.329 6.858 26.429 ;
     RECT  34.776 26.329 35.097 26.429 ;
     RECT  70.812 26.401 70.974 26.429 ;
     RECT  2.415 26.189 5.238 26.491 ;
     RECT  45.396 25.979 49.446 26.491 ;
     RECT  76.608 26.329 76.626 26.519 ;
     RECT  38.52 26.051 44.442 26.527 ;
     RECT  78.015 25.475 78.297 26.527 ;
     RECT  82.656 26.293 84.042 26.555 ;
     RECT  38.52 26.527 44.55 26.563 ;
     RECT  45.324 26.491 49.446 26.563 ;
     RECT  51.015 25.781 51.297 26.599 ;
     RECT  60.804 26.599 60.822 26.635 ;
     RECT  69.588 25.889 70.038 26.635 ;
     RECT  78.015 26.527 78.678 26.663 ;
     RECT  38.52 26.563 49.446 26.761 ;
     RECT  69.588 26.635 70.182 26.761 ;
     RECT  68.616 26.761 68.634 26.779 ;
     RECT  69.516 26.761 70.182 26.779 ;
     RECT  2.415 26.491 5.346 26.789 ;
     RECT  2.415 26.789 5.238 26.825 ;
     RECT  68.616 26.779 70.182 26.825 ;
     RECT  85.464 21.397 85.482 26.825 ;
     RECT  38.52 26.761 49.554 26.833 ;
     RECT  51.015 26.599 51.498 26.833 ;
     RECT  70.956 26.429 70.974 26.933 ;
     RECT  2.415 26.825 5.13 26.941 ;
     RECT  38.52 26.833 49.662 27.059 ;
     RECT  60.804 26.635 60.966 27.059 ;
     RECT  68.616 26.825 69.534 27.059 ;
     RECT  50.904 26.833 51.498 27.067 ;
     RECT  60.012 26.671 60.03 27.095 ;
     RECT  75.888 26.761 75.906 27.095 ;
     RECT  38.52 27.059 39.474 27.131 ;
     RECT  60.948 27.059 60.966 27.131 ;
     RECT  82.656 26.555 82.674 27.167 ;
     RECT  50.904 27.067 51.642 27.203 ;
     RECT  69.516 27.059 69.534 27.203 ;
     RECT  40.215 27.059 49.662 27.211 ;
     RECT  50.904 27.203 51.297 27.211 ;
     RECT  0.108 26.635 0.126 27.293 ;
     RECT  66.348 27.211 66.366 27.301 ;
     RECT  67.215 25.349 67.497 27.301 ;
     RECT  40.215 27.211 49.698 27.329 ;
     RECT  53.424 26.941 53.442 27.329 ;
     RECT  65.592 27.211 65.61 27.337 ;
     RECT  66.348 27.301 67.497 27.337 ;
     RECT  54.72 27.031 54.738 27.355 ;
     RECT  2.376 26.941 5.13 27.365 ;
     RECT  44.532 27.329 49.554 27.365 ;
     RECT  50.796 27.211 51.297 27.365 ;
     RECT  65.592 27.337 67.497 27.365 ;
     RECT  52.452 26.827 52.47 27.389 ;
     RECT  54.468 27.355 54.738 27.481 ;
     RECT  74.808 27.301 74.826 27.481 ;
     RECT  59.22 27.301 59.238 27.571 ;
     RECT  40.215 27.329 43.794 27.599 ;
     RECT  74.808 27.481 74.97 27.599 ;
     RECT  58.716 27.571 59.238 27.635 ;
     RECT  74.808 27.599 74.826 27.635 ;
     RECT  58.716 27.635 58.734 27.707 ;
     RECT  2.376 27.365 4.842 27.751 ;
     RECT  83.412 26.555 83.898 27.751 ;
     RECT  54.468 27.481 54.99 27.779 ;
     RECT  84.888 27.259 84.906 27.787 ;
     RECT  2.304 27.751 4.842 27.821 ;
     RECT  59.868 27.679 59.886 27.869 ;
     RECT  44.532 27.365 48.906 27.905 ;
     RECT  64.8 27.571 64.818 27.905 ;
     RECT  82.872 27.751 83.898 27.905 ;
     RECT  38.664 27.131 39.474 27.931 ;
     RECT  40.215 27.599 43.542 27.931 ;
     RECT  2.415 27.821 4.842 27.941 ;
     RECT  44.748 27.905 48.51 28.139 ;
     RECT  65.916 27.365 67.497 28.139 ;
     RECT  44.748 28.139 48.366 28.175 ;
     RECT  84.852 27.787 84.906 28.211 ;
     RECT  83.415 27.905 83.898 28.255 ;
     RECT  38.664 27.931 43.542 28.283 ;
     RECT  65.916 28.139 66.114 28.319 ;
     RECT  40.215 28.283 43.542 28.409 ;
     RECT  66.096 28.319 66.114 28.445 ;
     RECT  82.656 28.291 82.674 28.481 ;
     RECT  85.356 28.315 85.482 28.481 ;
     RECT  41.364 28.409 43.542 28.525 ;
     RECT  41.364 28.525 43.614 28.561 ;
     RECT  66.852 28.139 67.497 28.561 ;
     RECT  41.364 28.561 43.902 28.687 ;
     RECT  44.748 28.175 48.042 28.687 ;
     RECT  66.852 28.561 67.842 28.715 ;
     RECT  75.024 28.381 75.042 28.715 ;
     RECT  61.815 25.547 62.097 28.759 ;
     RECT  70.668 28.651 70.686 28.787 ;
     RECT  56.415 22.739 56.697 28.831 ;
     RECT  83.415 28.255 84.042 28.831 ;
     RECT  61.815 28.759 62.73 28.859 ;
     RECT  51.015 27.365 51.297 28.939 ;
     RECT  56.052 28.831 56.697 28.949 ;
     RECT  49.284 28.687 49.302 28.957 ;
     RECT  52.02 28.921 52.038 28.973 ;
     RECT  66.852 28.715 67.497 28.985 ;
     RECT  83.016 28.831 84.042 28.985 ;
     RECT  85.356 28.481 85.374 29.021 ;
     RECT  49.284 28.957 49.734 29.029 ;
     RECT  60.084 28.831 60.102 29.029 ;
     RECT  69.084 28.411 69.102 29.029 ;
     RECT  41.364 28.687 48.042 29.065 ;
     RECT  48.924 29.029 49.878 29.065 ;
     RECT  50.688 28.939 51.297 29.101 ;
     RECT  68.976 29.029 69.102 29.101 ;
     RECT  76.212 28.921 76.23 29.101 ;
     RECT  60.084 29.029 60.21 29.219 ;
     RECT  76.212 29.101 76.374 29.219 ;
     RECT  41.364 29.065 49.878 29.227 ;
     RECT  50.652 29.101 51.297 29.227 ;
     RECT  60.084 29.219 60.102 29.255 ;
     RECT  76.212 29.219 76.23 29.255 ;
     RECT  70.704 29.101 70.722 29.327 ;
     RECT  41.364 29.227 51.426 29.363 ;
     RECT  2.415 27.941 4.77 29.371 ;
     RECT  41.364 29.363 50.058 29.399 ;
     RECT  2.304 29.371 4.842 29.497 ;
     RECT  51.015 29.363 51.426 29.501 ;
     RECT  68.976 29.101 69.57 29.563 ;
     RECT  53.028 29.467 53.046 29.597 ;
     RECT  59.76 29.461 59.778 29.597 ;
     RECT  68.976 29.563 69.966 29.597 ;
     RECT  69.948 29.597 69.966 29.603 ;
     RECT  82.656 29.371 82.674 29.605 ;
     RECT  61.815 28.859 62.694 29.633 ;
     RECT  41.364 29.399 49.374 29.641 ;
     RECT  54.468 27.779 54.486 29.659 ;
     RECT  41.292 29.641 49.374 29.669 ;
     RECT  2.304 29.497 4.914 29.693 ;
     RECT  54.468 29.659 54.738 29.693 ;
     RECT  4.248 29.693 4.914 29.759 ;
     RECT  68.328 29.707 68.958 29.759 ;
     RECT  70.056 29.605 70.218 29.759 ;
     RECT  51.015 29.501 51.354 29.789 ;
     RECT  52.812 29.731 52.83 29.789 ;
     RECT  4.248 29.759 4.734 29.795 ;
     RECT  70.2 29.759 70.218 29.795 ;
     RECT  82.08 29.605 82.674 29.795 ;
     RECT  38.664 28.283 39.474 29.911 ;
     RECT  40.215 28.409 40.497 29.911 ;
     RECT  56.415 28.949 56.697 29.911 ;
     RECT  82.656 29.795 82.674 29.911 ;
     RECT  83.415 28.985 84.042 29.911 ;
     RECT  55.692 29.911 56.697 30.029 ;
     RECT  68.94 29.759 68.958 30.029 ;
     RECT  71.208 30.001 71.226 30.137 ;
     RECT  75.816 29.461 75.834 30.145 ;
     RECT  54.72 29.693 54.738 30.179 ;
     RECT  70.74 30.181 70.758 30.221 ;
     RECT  42.12 29.669 49.374 30.271 ;
     RECT  54.9 30.181 54.918 30.299 ;
     RECT  64.116 30.109 64.134 30.335 ;
     RECT  82.656 29.911 84.042 30.335 ;
     RECT  38.664 29.911 40.497 30.379 ;
     RECT  75.816 30.145 76.41 30.407 ;
     RECT  5.688 29.911 5.706 30.443 ;
     RECT  72.615 25.517 72.897 30.451 ;
     RECT  73.872 30.181 73.89 30.451 ;
     RECT  4.248 29.795 4.626 30.569 ;
     RECT  38.664 30.379 40.554 30.577 ;
     RECT  41.292 29.669 41.31 30.577 ;
     RECT  42.12 30.271 49.554 30.577 ;
     RECT  72.615 30.451 73.89 30.605 ;
     RECT  74.7 30.568 74.718 30.605 ;
     RECT  71.676 30.181 71.694 30.641 ;
     RECT  85.464 29.419 85.482 30.641 ;
     RECT  78.015 26.663 78.297 30.649 ;
     RECT  69.876 30.541 69.894 30.677 ;
     RECT  38.664 30.577 41.31 30.685 ;
     RECT  42.12 30.577 49.59 30.685 ;
     RECT  75.744 30.451 75.762 30.713 ;
     RECT  2.304 29.693 3.51 30.721 ;
     RECT  4.248 30.569 4.446 30.721 ;
     RECT  38.664 30.685 49.59 30.721 ;
     RECT  51.015 29.789 51.297 30.721 ;
     RECT  2.304 30.721 4.446 30.749 ;
     RECT  78.015 30.649 79.182 30.839 ;
     RECT  59.868 30.577 59.886 30.875 ;
     RECT  83.016 30.335 84.042 30.911 ;
     RECT  38.664 30.721 51.297 30.919 ;
     RECT  83.232 30.911 84.042 30.947 ;
     RECT  82.08 30.721 82.098 30.983 ;
     RECT  0.108 30.955 0.126 31.085 ;
     RECT  61.815 29.633 62.097 31.117 ;
     RECT  74.088 30.721 74.106 31.181 ;
     RECT  85.356 31.051 85.374 31.181 ;
     RECT  38.304 30.919 51.297 31.189 ;
     RECT  38.196 31.189 51.297 31.195 ;
     RECT  38.196 31.195 51.39 31.253 ;
     RECT  38.196 31.253 51.354 31.351 ;
     RECT  54.108 31.351 54.126 31.42 ;
     RECT  37.512 31.351 51.354 31.421 ;
     RECT  54.108 31.42 54.162 31.421 ;
     RECT  61.488 31.117 62.097 31.451 ;
     RECT  72.615 30.605 72.897 31.531 ;
     RECT  78.015 30.839 78.297 31.531 ;
     RECT  53.172 31.495 53.19 31.565 ;
     RECT  2.415 30.749 4.446 31.579 ;
     RECT  67.215 28.985 67.497 31.621 ;
     RECT  72 31.531 72.897 31.627 ;
     RECT  54.144 31.421 54.162 31.649 ;
     RECT  63.828 31.531 63.846 31.649 ;
     RECT  66.744 31.621 67.497 31.721 ;
     RECT  37.512 31.421 51.297 31.729 ;
     RECT  2.304 31.579 4.446 31.793 ;
     RECT  82.656 31.693 82.674 31.793 ;
     RECT  74.448 31.771 74.466 31.801 ;
     RECT  83.415 30.947 84.042 31.801 ;
     RECT  37.332 31.729 51.297 31.805 ;
     RECT  2.304 31.793 4.194 31.829 ;
     RECT  37.512 31.805 51.297 31.829 ;
     RECT  71.856 31.627 72.897 31.829 ;
     RECT  0.54 31.261 0.558 31.891 ;
     RECT  45.576 31.829 51.297 31.919 ;
     RECT  60.768 31.693 60.93 31.919 ;
     RECT  71.028 31.801 71.046 31.919 ;
     RECT  77.544 31.531 78.297 31.919 ;
     RECT  78.015 31.919 78.297 31.927 ;
     RECT  60.768 31.919 60.786 31.955 ;
     RECT  82.764 31.801 84.042 31.955 ;
     RECT  78.015 31.927 78.642 32.027 ;
     RECT  0.504 31.891 0.558 32.141 ;
     RECT  2.415 31.829 4.194 32.189 ;
     RECT  45.576 31.919 49.518 32.189 ;
     RECT  74.448 31.801 74.61 32.189 ;
     RECT  83.196 31.955 84.042 32.225 ;
     RECT  3.42 32.189 4.194 32.261 ;
     RECT  5.076 31.891 5.094 32.261 ;
     RECT  75.384 32.071 75.402 32.341 ;
     RECT  53.028 32.341 53.046 32.459 ;
     RECT  75.384 32.341 75.762 32.459 ;
     RECT  63.18 32.431 63.198 32.467 ;
     RECT  74.448 32.189 74.466 32.477 ;
     RECT  50.58 31.919 51.297 32.495 ;
     RECT  75.384 32.459 75.582 32.495 ;
     RECT  37.512 31.829 44.658 32.639 ;
     RECT  0.504 32.141 0.522 32.669 ;
     RECT  50.796 32.495 51.297 32.729 ;
     RECT  63.18 32.467 63.27 32.729 ;
     RECT  79.2 32.341 79.218 32.729 ;
     RECT  63.252 32.729 63.27 32.801 ;
     RECT  76.536 32.611 76.554 32.801 ;
     RECT  53.784 32.491 53.802 32.861 ;
     RECT  45.615 32.189 49.014 32.873 ;
     RECT  82.404 32.611 82.422 32.873 ;
     RECT  75.24 32.611 75.258 32.909 ;
     RECT  2.415 32.189 2.697 32.971 ;
     RECT  3.42 32.261 3.438 32.971 ;
     RECT  45.615 32.873 48.834 32.971 ;
     RECT  2.415 32.971 3.438 33.007 ;
     RECT  0.108 33.043 0.126 33.245 ;
     RECT  82.656 33.313 82.674 33.412 ;
     RECT  83.415 32.225 84.042 33.412 ;
     RECT  4.176 32.261 4.194 33.421 ;
     RECT  61.815 31.451 62.097 33.511 ;
     RECT  4.176 33.421 4.698 33.539 ;
     RECT  44.856 32.971 48.834 33.619 ;
     RECT  34.815 26.429 35.097 33.643 ;
     RECT  53.532 33.643 53.55 33.655 ;
     RECT  74.736 33.595 74.754 33.655 ;
     RECT  2.34 33.007 3.438 33.691 ;
     RECT  4.176 33.539 4.59 33.691 ;
     RECT  72.396 31.829 72.897 33.691 ;
     RECT  82.656 33.412 84.042 33.691 ;
     RECT  2.34 33.691 4.59 33.739 ;
     RECT  53.532 33.655 53.73 33.809 ;
     RECT  74.736 33.655 75.114 33.809 ;
     RECT  79.056 33.655 79.074 33.809 ;
     RECT  34.776 33.643 35.097 33.821 ;
     RECT  53.532 33.809 53.55 33.845 ;
     RECT  61.092 33.511 62.097 33.845 ;
     RECT  72.396 33.691 73.062 33.845 ;
     RECT  5.472 33.691 5.49 33.881 ;
     RECT  82.584 33.691 84.042 33.881 ;
     RECT  30.78 33.787 30.798 33.917 ;
     RECT  37.512 32.639 44.046 33.925 ;
     RECT  44.784 33.619 48.834 33.925 ;
     RECT  51.015 32.729 51.297 33.925 ;
     RECT  79.128 33.817 79.146 33.953 ;
     RECT  28.656 33.883 28.674 33.961 ;
     RECT  29.415 17.609 29.697 33.961 ;
     RECT  67.215 31.721 67.497 33.961 ;
     RECT  28.656 33.961 29.697 33.989 ;
     RECT  72.396 33.845 72.918 33.989 ;
     RECT  69.516 33.961 69.534 34.027 ;
     RECT  37.512 33.925 48.834 34.051 ;
     RECT  49.788 33.499 49.806 34.051 ;
     RECT  66.744 33.961 67.497 34.051 ;
     RECT  50.94 33.925 51.297 34.079 ;
     RECT  64.044 33.655 64.062 34.079 ;
     RECT  73.944 33.961 73.962 34.079 ;
     RECT  37.512 34.051 49.806 34.087 ;
     RECT  29.088 33.989 29.697 34.115 ;
     RECT  37.512 34.087 50.022 34.115 ;
     RECT  70.704 33.889 70.722 34.115 ;
     RECT  74.916 33.809 74.934 34.115 ;
     RECT  66.708 34.051 67.497 34.151 ;
     RECT  37.512 34.115 49.086 34.157 ;
     RECT  54.504 33.961 54.522 34.157 ;
     RECT  69.444 34.027 69.534 34.159 ;
     RECT  66.744 34.151 67.497 34.187 ;
     RECT  83.232 33.881 84.042 34.187 ;
     RECT  50.004 34.115 50.022 34.231 ;
     RECT  68.976 34.159 69.534 34.321 ;
     RECT  70.308 34.231 70.398 34.321 ;
     RECT  50.004 34.231 50.166 34.349 ;
     RECT  68.976 34.321 70.398 34.349 ;
     RECT  59.544 34.123 59.562 34.385 ;
     RECT  76.428 34.051 76.446 34.385 ;
     RECT  68.976 34.349 69.606 34.493 ;
     RECT  70.38 34.349 70.398 34.493 ;
     RECT  2.304 33.739 4.59 34.501 ;
     RECT  68.976 34.493 68.994 34.529 ;
     RECT  37.512 34.157 48.906 34.655 ;
     RECT  83.268 34.187 84.042 34.727 ;
     RECT  2.304 34.501 4.662 35.041 ;
     RECT  83.34 34.727 84.042 35.195 ;
     RECT  50.004 34.349 50.022 35.203 ;
     RECT  51.015 34.079 51.297 35.203 ;
     RECT  76.284 35.131 76.302 35.239 ;
     RECT  70.596 35.131 70.614 35.269 ;
     RECT  50.004 35.203 51.297 35.275 ;
     RECT  68.616 35.269 68.634 35.311 ;
     RECT  70.056 35.269 70.614 35.311 ;
     RECT  49.932 35.275 51.297 35.357 ;
     RECT  50.328 35.357 51.297 35.401 ;
     RECT  68.616 35.311 68.778 35.401 ;
     RECT  69.552 35.311 70.758 35.401 ;
     RECT  72.615 33.989 72.897 35.401 ;
     RECT  58.896 35.131 58.914 35.429 ;
     RECT  76.284 35.239 76.878 35.465 ;
     RECT  5.616 35.311 5.634 35.501 ;
     RECT  68.436 35.401 70.758 35.501 ;
     RECT  60.12 35.437 60.138 35.509 ;
     RECT  74.736 35.473 74.754 35.509 ;
     RECT  50.328 35.401 51.354 35.537 ;
     RECT  37.512 34.655 48.726 35.545 ;
     RECT  2.304 35.041 4.842 35.581 ;
     RECT  74.664 35.509 74.754 35.609 ;
     RECT  60.12 35.509 60.174 35.699 ;
     RECT  72.615 35.401 73.386 35.699 ;
     RECT  61.815 33.845 62.097 35.707 ;
     RECT  37.512 35.545 49.266 35.735 ;
     RECT  50.328 35.537 51.297 35.735 ;
     RECT  68.436 35.501 70.182 35.735 ;
     RECT  53.028 35.671 53.046 35.771 ;
     RECT  61.815 35.707 62.622 35.779 ;
     RECT  68.436 35.735 68.994 35.807 ;
     RECT  2.304 35.581 5.13 35.843 ;
     RECT  50.688 35.735 51.297 35.843 ;
     RECT  38.628 35.735 49.266 35.879 ;
     RECT  61.815 35.779 62.694 35.879 ;
     RECT  67.215 34.187 67.497 35.899 ;
     RECT  2.304 35.843 4.986 35.969 ;
     RECT  39.06 35.879 49.266 35.969 ;
     RECT  59.868 35.743 59.994 36.005 ;
     RECT  82.44 35.851 82.458 36.005 ;
     RECT  6.048 35.671 6.066 36.041 ;
     RECT  71.136 35.851 71.154 36.041 ;
     RECT  75.816 35.707 75.834 36.077 ;
     RECT  52.02 35.851 52.038 36.149 ;
     RECT  59.868 36.005 59.886 36.149 ;
     RECT  68.796 35.807 68.994 36.149 ;
     RECT  39.06 35.969 49.086 36.239 ;
     RECT  45.54 36.239 48.978 36.275 ;
     RECT  54.612 36.235 54.63 36.275 ;
     RECT  2.304 35.969 4.842 36.311 ;
     RECT  45.54 36.275 48.762 36.383 ;
     RECT  45.615 36.383 48.762 36.461 ;
     RECT  39.06 36.239 44.802 36.509 ;
     RECT  60.804 36.211 60.822 36.509 ;
     RECT  67.215 35.899 68.022 36.509 ;
     RECT  75.348 36.211 75.366 36.545 ;
     RECT  45.615 36.461 48.51 36.557 ;
     RECT  68.796 36.149 68.814 36.581 ;
     RECT  66.42 36.211 66.438 36.617 ;
     RECT  2.304 36.311 4.662 36.653 ;
     RECT  45.615 36.557 47.142 36.779 ;
     RECT  48.348 36.557 48.51 36.815 ;
     RECT  45.615 36.779 47.034 37.049 ;
     RECT  48.42 36.815 48.51 37.049 ;
     RECT  34.815 33.821 35.097 37.129 ;
     RECT  37.512 35.735 37.854 37.129 ;
     RECT  34.776 37.129 35.097 37.229 ;
     RECT  44.64 36.509 44.802 37.327 ;
     RECT  45.615 37.049 46.818 37.327 ;
     RECT  70.272 37.291 70.29 37.327 ;
     RECT  69.048 37.327 69.066 37.399 ;
     RECT  37.512 37.129 38.106 37.435 ;
     RECT  39.06 36.509 43.902 37.435 ;
     RECT  58.932 37.399 58.95 37.435 ;
     RECT  69.048 37.399 69.138 37.435 ;
     RECT  70.236 37.327 70.29 37.435 ;
     RECT  2.304 36.653 4.482 37.471 ;
     RECT  37.512 37.435 43.902 37.471 ;
     RECT  44.64 37.327 46.818 37.471 ;
     RECT  58.932 37.435 58.986 37.471 ;
     RECT  67.215 36.509 67.878 37.471 ;
     RECT  69.048 37.435 70.29 37.471 ;
     RECT  78.015 32.027 78.297 37.471 ;
     RECT  83.415 35.195 84.042 37.471 ;
     RECT  49.428 37.471 49.446 37.561 ;
     RECT  2.304 37.471 4.698 37.589 ;
     RECT  49.428 37.561 50.166 37.589 ;
     RECT  66.744 37.471 67.878 37.589 ;
     RECT  77.004 37.291 77.022 37.589 ;
     RECT  78.015 37.471 78.678 37.589 ;
     RECT  48.492 37.049 48.51 37.613 ;
     RECT  49.932 37.589 50.166 37.625 ;
     RECT  69.048 37.471 70.866 37.625 ;
     RECT  83.196 37.471 84.042 37.625 ;
     RECT  69.048 37.625 70.254 37.705 ;
     RECT  58.824 37.471 58.986 37.741 ;
     RECT  75.96 37.471 75.978 37.741 ;
     RECT  37.512 37.471 46.818 37.831 ;
     RECT  67.215 37.589 67.878 37.831 ;
     RECT  58.824 37.741 59.094 37.859 ;
     RECT  58.068 37.561 58.086 37.895 ;
     RECT  58.824 37.859 58.95 37.895 ;
     RECT  68.976 37.705 70.254 37.895 ;
     RECT  75.96 37.741 76.086 37.895 ;
     RECT  37.512 37.831 46.998 37.967 ;
     RECT  5.472 37.741 5.49 38.003 ;
     RECT  67.215 37.831 68.202 38.003 ;
     RECT  68.976 37.895 68.994 38.003 ;
     RECT  67.215 38.003 67.842 38.039 ;
     RECT  37.512 37.967 46.782 38.129 ;
     RECT  50.076 37.625 50.166 38.129 ;
     RECT  70.128 37.895 70.254 38.129 ;
     RECT  76.248 37.939 76.266 38.129 ;
     RECT  50.148 38.129 50.166 38.165 ;
     RECT  58.824 37.895 58.842 38.165 ;
     RECT  70.164 38.129 70.254 38.165 ;
     RECT  82.548 38.011 82.566 38.165 ;
     RECT  51.015 35.843 51.297 38.245 ;
     RECT  70.164 38.165 70.182 38.309 ;
     RECT  51.015 38.245 51.606 38.347 ;
     RECT  50.652 38.347 51.606 38.399 ;
     RECT  83.415 37.625 84.042 38.399 ;
     RECT  51.015 38.399 51.606 38.435 ;
     RECT  74.664 37.831 74.682 38.551 ;
     RECT  2.304 37.589 4.662 38.579 ;
     RECT  2.304 38.579 3.87 38.621 ;
     RECT  31.284 38.011 31.302 38.641 ;
     RECT  37.512 38.129 45.954 38.669 ;
     RECT  63.216 38.371 63.234 38.669 ;
     RECT  30.78 38.641 31.302 38.741 ;
     RECT  42.156 38.669 45.954 38.765 ;
     RECT  31.284 38.741 31.302 38.821 ;
     RECT  78.015 37.589 78.297 38.821 ;
     RECT  31.284 38.821 31.41 38.939 ;
     RECT  74.664 38.551 75.258 38.939 ;
     RECT  76.572 38.713 76.59 38.939 ;
     RECT  77.76 38.821 78.297 38.939 ;
     RECT  42.192 38.765 45.954 39.019 ;
     RECT  81.504 38.641 81.522 39.047 ;
     RECT  72.615 35.699 72.897 39.055 ;
     RECT  42.192 39.019 46.134 39.091 ;
     RECT  72.504 39.055 72.897 39.091 ;
     RECT  2.376 38.621 3.87 39.101 ;
     RECT  0.108 38.713 0.126 39.149 ;
     RECT  42.192 39.091 46.674 39.181 ;
     RECT  79.308 39.091 79.326 39.181 ;
     RECT  42.192 39.181 47.142 39.209 ;
     RECT  70.74 39.181 70.758 39.217 ;
     RECT  72.504 39.091 73.458 39.217 ;
     RECT  72.504 39.217 73.53 39.245 ;
     RECT  59.976 39.217 59.994 39.253 ;
     RECT  70.74 39.217 70.83 39.281 ;
     RECT  70.812 39.281 70.83 39.317 ;
     RECT  72.615 39.245 73.53 39.317 ;
     RECT  47.952 39.019 47.97 39.355 ;
     RECT  75.24 38.939 75.258 39.451 ;
     RECT  76.212 39.361 76.23 39.451 ;
     RECT  79.056 39.181 79.326 39.451 ;
     RECT  75.24 39.451 76.23 39.479 ;
     RECT  46.764 39.209 47.142 39.515 ;
     RECT  59.976 39.253 60.426 39.515 ;
     RECT  34.815 37.229 35.097 39.523 ;
     RECT  75.744 39.479 76.23 39.551 ;
     RECT  4.608 38.579 4.662 39.559 ;
     RECT  51.015 38.435 51.297 39.559 ;
     RECT  47.124 39.515 47.142 39.587 ;
     RECT  82.368 39.361 82.386 39.587 ;
     RECT  83.415 38.399 83.898 39.595 ;
     RECT  72.615 39.317 73.458 39.623 ;
     RECT  76.212 39.551 76.23 39.623 ;
     RECT  79.056 39.451 79.398 39.623 ;
     RECT  2.376 39.101 3.546 39.631 ;
     RECT  4.608 39.559 5.094 39.631 ;
     RECT  37.512 38.669 41.418 39.631 ;
     RECT  47.952 39.355 48.078 39.631 ;
     RECT  2.304 39.631 3.546 39.659 ;
     RECT  34.776 39.523 35.097 39.659 ;
     RECT  50.688 39.559 51.297 39.659 ;
     RECT  2.304 39.659 2.697 39.725 ;
     RECT  4.284 39.631 5.094 39.749 ;
     RECT  48.996 39.631 49.014 39.749 ;
     RECT  60.192 39.515 60.426 39.749 ;
     RECT  61.815 35.879 62.097 39.757 ;
     RECT  37.296 39.631 41.418 39.793 ;
     RECT  42.192 39.209 45.897 39.793 ;
     RECT  37.296 39.793 45.897 39.829 ;
     RECT  3.528 39.659 3.546 39.865 ;
     RECT  4.284 39.749 4.878 39.865 ;
     RECT  74.304 39.757 74.322 39.865 ;
     RECT  60.408 39.749 60.426 39.893 ;
     RECT  47.844 39.631 48.078 39.901 ;
     RECT  47.844 39.901 48.222 39.929 ;
     RECT  78.015 38.939 78.297 39.991 ;
     RECT  48.204 39.929 48.222 40.019 ;
     RECT  83.415 39.595 84.042 40.019 ;
     RECT  61.308 39.757 62.097 40.055 ;
     RECT  74.304 39.865 74.898 40.135 ;
     RECT  83.415 40.019 83.898 40.135 ;
     RECT  83.232 40.135 83.898 40.171 ;
     RECT  74.124 40.135 74.898 40.325 ;
     RECT  3.528 39.865 4.878 40.361 ;
     RECT  78.015 39.991 78.822 40.397 ;
     RECT  4.86 40.361 4.878 40.433 ;
     RECT  2.415 39.725 2.697 40.441 ;
     RECT  3.528 40.361 4.086 40.441 ;
     RECT  74.124 40.325 74.79 40.445 ;
     RECT  34.815 39.659 35.097 40.459 ;
     RECT  36.684 39.829 45.897 40.493 ;
     RECT  2.415 40.441 4.086 40.559 ;
     RECT  53.748 40.459 53.766 40.559 ;
     RECT  34.815 40.459 35.37 40.567 ;
     RECT  4.068 40.559 4.086 40.595 ;
     RECT  34.776 40.567 35.37 40.711 ;
     RECT  2.415 40.559 3.258 40.747 ;
     RECT  82.836 40.171 83.898 40.801 ;
     RECT  34.776 40.711 35.514 40.837 ;
     RECT  37.296 40.493 45.897 40.865 ;
     RECT  74.376 40.445 74.79 40.865 ;
     RECT  34.776 40.837 36.45 40.939 ;
     RECT  37.296 40.865 44.586 40.973 ;
     RECT  72.615 39.623 72.897 40.981 ;
     RECT  75.636 40.909 75.654 40.981 ;
     RECT  75.636 40.981 75.726 41.009 ;
     RECT  54.108 40.711 54.126 41.021 ;
     RECT  45.432 40.865 45.897 41.099 ;
     RECT  79.2 40.909 79.218 41.099 ;
     RECT  82.656 40.801 83.898 41.107 ;
     RECT  59.364 40.837 59.382 41.135 ;
     RECT  74.376 40.865 74.394 41.171 ;
     RECT  82.62 41.107 83.898 41.207 ;
     RECT  75.708 41.009 75.726 41.243 ;
     RECT  34.56 40.939 36.45 41.341 ;
     RECT  37.296 40.973 44.334 41.341 ;
     RECT  2.304 40.747 3.258 41.449 ;
     RECT  72.615 40.981 73.566 41.449 ;
     RECT  72.615 41.449 73.854 41.521 ;
     RECT  72.504 41.521 73.854 41.549 ;
     RECT  2.304 41.449 3.294 41.611 ;
     RECT  4.14 41.251 4.158 41.611 ;
     RECT  47.556 41.611 47.574 41.675 ;
     RECT  81.504 41.521 81.522 41.675 ;
     RECT  6.768 41.611 6.786 41.719 ;
     RECT  2.304 41.611 4.158 41.755 ;
     RECT  5.328 41.719 5.346 41.755 ;
     RECT  72.504 41.549 73.062 41.755 ;
     RECT  72.432 41.755 73.062 41.783 ;
     RECT  73.836 41.549 73.854 41.783 ;
     RECT  45.615 41.099 45.897 41.791 ;
     RECT  6.768 41.719 6.822 41.819 ;
     RECT  76.968 41.449 76.986 41.819 ;
     RECT  34.56 41.341 44.334 41.881 ;
     RECT  45.615 41.791 45.954 41.881 ;
     RECT  2.304 41.755 5.346 41.909 ;
     RECT  60.192 41.611 60.21 41.909 ;
     RECT  61.815 40.055 62.097 41.917 ;
     RECT  72.432 41.783 72.99 41.945 ;
     RECT  48.492 41.791 48.51 42.017 ;
     RECT  83.415 41.207 83.898 42.025 ;
     RECT  61.815 41.917 62.766 42.053 ;
     RECT  6.768 41.819 6.786 42.061 ;
     RECT  34.56 41.881 45.954 42.061 ;
     RECT  46.764 41.881 46.782 42.061 ;
     RECT  79.632 42.025 79.65 42.061 ;
     RECT  83.415 42.025 84.042 42.061 ;
     RECT  2.304 41.909 5.166 42.077 ;
     RECT  2.304 42.077 4.95 42.089 ;
     RECT  6.12 42.061 6.786 42.089 ;
     RECT  75.636 42.025 75.654 42.091 ;
     RECT  74.232 42.061 74.394 42.151 ;
     RECT  75.492 42.091 75.654 42.151 ;
     RECT  83.232 42.061 84.042 42.151 ;
     RECT  2.376 42.089 4.95 42.179 ;
     RECT  47.952 42.139 47.97 42.179 ;
     RECT  48.888 42.061 48.906 42.179 ;
     RECT  70.704 42.061 70.722 42.179 ;
     RECT  75.492 42.151 75.798 42.179 ;
     RECT  51.015 39.659 51.297 42.331 ;
     RECT  0.108 42.151 0.126 42.413 ;
     RECT  2.376 42.179 3.438 42.449 ;
     RECT  49.86 42.295 49.878 42.449 ;
     RECT  50.724 42.331 51.297 42.449 ;
     RECT  72.615 41.945 72.99 42.449 ;
     RECT  79.236 42.061 79.65 42.449 ;
     RECT  83.196 42.151 84.042 42.457 ;
     RECT  60.444 42.061 60.462 42.485 ;
     RECT  79.524 42.449 79.542 42.485 ;
     RECT  82.62 42.457 84.042 42.485 ;
     RECT  4.572 42.179 4.95 42.521 ;
     RECT  75.78 42.179 75.798 42.521 ;
     RECT  34.56 42.061 46.782 42.529 ;
     RECT  82.62 42.485 82.638 42.557 ;
     RECT  74.232 42.151 74.466 42.565 ;
     RECT  73.836 42.565 74.466 42.593 ;
     RECT  49.716 42.565 49.734 42.605 ;
     RECT  34.524 42.529 46.782 42.667 ;
     RECT  68.868 42.601 68.886 42.715 ;
     RECT  61.815 42.053 62.154 42.719 ;
     RECT  68.868 42.715 69.39 42.719 ;
     RECT  74.628 42.601 74.646 42.719 ;
     RECT  34.524 42.667 47.214 42.727 ;
     RECT  34.524 42.727 47.43 42.749 ;
     RECT  68.976 42.719 69.39 42.755 ;
     RECT  4.572 42.521 4.734 42.791 ;
     RECT  47.124 42.749 47.43 42.791 ;
     RECT  73.836 42.593 73.854 42.899 ;
     RECT  0.54 42.691 0.558 42.941 ;
     RECT  2.415 42.449 3.438 42.989 ;
     RECT  34.524 42.749 46.062 42.989 ;
     RECT  47.124 42.791 47.358 42.989 ;
     RECT  70.236 42.871 70.326 42.989 ;
     RECT  58.14 42.601 58.158 43.025 ;
     RECT  76.536 42.691 76.554 43.025 ;
     RECT  6.12 42.089 6.138 43.061 ;
     RECT  70.308 42.989 70.326 43.061 ;
     RECT  68.976 42.755 68.994 43.097 ;
     RECT  47.124 42.989 47.142 43.133 ;
     RECT  34.524 42.989 45.897 43.141 ;
     RECT  2.415 42.989 2.697 43.435 ;
     RECT  34.488 43.141 45.897 43.529 ;
     RECT  34.776 43.529 45.897 43.565 ;
     RECT  34.776 43.565 38.754 43.601 ;
     RECT  4.716 42.791 4.734 43.609 ;
     RECT  5.508 43.141 5.526 43.609 ;
     RECT  34.815 43.601 38.754 43.709 ;
     RECT  3.492 43.411 3.51 43.799 ;
     RECT  82.656 43.681 82.674 43.871 ;
     RECT  4.716 43.609 5.526 43.951 ;
     RECT  68.904 43.723 68.922 43.951 ;
     RECT  67.215 38.039 67.497 44.041 ;
     RECT  30.78 43.951 30.798 44.069 ;
     RECT  68.904 43.951 69.642 44.105 ;
     RECT  68.904 44.105 69.066 44.177 ;
     RECT  46.692 44.185 46.71 44.221 ;
     RECT  66.708 44.041 67.497 44.221 ;
     RECT  75.888 43.771 75.906 44.221 ;
     RECT  83.415 42.485 84.042 44.221 ;
     RECT  4.284 43.951 5.526 44.339 ;
     RECT  58.14 44.041 58.158 44.339 ;
     RECT  75.816 44.221 75.906 44.339 ;
     RECT  2.304 43.435 2.697 44.347 ;
     RECT  3.42 43.843 3.438 44.347 ;
     RECT  78.015 40.397 78.297 44.347 ;
     RECT  5.508 44.339 5.526 44.375 ;
     RECT  34.815 43.709 38.466 44.375 ;
     RECT  83.304 44.221 84.042 44.375 ;
     RECT  46.692 44.221 47.178 44.419 ;
     RECT  78.015 44.347 78.642 44.447 ;
     RECT  35.892 44.375 38.466 44.455 ;
     RECT  39.528 43.565 45.897 44.455 ;
     RECT  56.415 30.029 56.697 44.491 ;
     RECT  66.708 44.221 67.986 44.491 ;
     RECT  70.668 44.041 70.686 44.587 ;
     RECT  4.248 44.491 4.266 44.645 ;
     RECT  48.852 44.443 48.87 44.645 ;
     RECT  66.708 44.491 68.49 44.645 ;
     RECT  70.236 44.587 70.686 44.717 ;
     RECT  46.692 44.419 47.286 44.725 ;
     RECT  46.656 44.725 47.286 44.753 ;
     RECT  2.304 44.347 3.438 44.761 ;
     RECT  51.015 42.449 51.297 44.761 ;
     RECT  59.616 44.581 59.634 44.761 ;
     RECT  61.815 42.719 62.097 44.761 ;
     RECT  70.56 44.717 70.686 44.761 ;
     RECT  2.304 44.761 4.05 44.789 ;
     RECT  50.724 44.761 51.297 44.851 ;
     RECT  82.332 44.761 82.35 44.851 ;
     RECT  2.415 44.789 4.05 44.879 ;
     RECT  56.415 44.491 57.186 44.879 ;
     RECT  70.56 44.761 70.83 44.879 ;
     RECT  76.212 44.581 76.518 44.879 ;
     RECT  50.724 44.851 51.75 44.915 ;
     RECT  52.668 44.761 52.686 44.915 ;
     RECT  66.708 44.645 67.842 44.915 ;
     RECT  70.812 44.879 70.83 44.915 ;
     RECT  82.332 44.851 82.422 44.915 ;
     RECT  59.616 44.761 59.706 44.923 ;
     RECT  61.815 44.761 62.694 44.987 ;
     RECT  66.78 44.915 67.842 44.987 ;
     RECT  82.404 44.915 82.422 44.987 ;
     RECT  2.415 44.879 3.978 45.023 ;
     RECT  59.544 44.923 59.706 45.023 ;
     RECT  68.76 44.971 68.778 45.023 ;
     RECT  51.015 44.915 51.75 45.031 ;
     RECT  61.056 44.851 61.074 45.031 ;
     RECT  61.815 44.987 62.097 45.031 ;
     RECT  69.516 44.887 69.534 45.031 ;
     RECT  0.108 44.689 0.126 45.101 ;
     RECT  2.415 45.023 2.862 45.149 ;
     RECT  51.015 45.031 51.894 45.149 ;
     RECT  67.215 44.987 67.842 45.149 ;
     RECT  68.94 45.031 69.534 45.149 ;
     RECT  59.688 45.023 59.706 45.185 ;
     RECT  76.212 44.879 76.23 45.185 ;
     RECT  61.056 45.031 62.097 45.197 ;
     RECT  3.744 45.023 3.978 45.221 ;
     RECT  69.516 45.149 69.534 45.221 ;
     RECT  34.815 44.375 35.097 45.301 ;
     RECT  35.892 44.455 45.897 45.301 ;
     RECT  34.815 45.301 45.897 45.419 ;
     RECT  35.82 45.419 45.897 45.535 ;
     RECT  46.656 44.753 46.89 45.535 ;
     RECT  3.744 45.221 3.942 45.581 ;
     RECT  61.344 45.197 62.097 45.581 ;
     RECT  35.82 45.535 47.034 45.661 ;
     RECT  35.82 45.661 47.898 45.689 ;
     RECT  35.892 45.689 47.898 45.725 ;
     RECT  85.464 31.579 85.482 45.725 ;
     RECT  4.716 45.571 4.734 45.833 ;
     RECT  42.264 45.725 47.898 45.841 ;
     RECT  66.456 45.805 66.474 45.841 ;
     RECT  51.015 45.149 51.297 45.931 ;
     RECT  75.276 45.661 75.294 45.959 ;
     RECT  78.015 44.447 78.297 45.967 ;
     RECT  35.892 45.725 41.454 45.995 ;
     RECT  51.015 45.931 51.822 46.003 ;
     RECT  50.904 46.003 51.822 46.075 ;
     RECT  58.032 45.967 58.05 46.111 ;
     RECT  50.796 46.075 51.822 46.139 ;
     RECT  2.415 45.149 2.697 46.171 ;
     RECT  49.248 46.075 49.734 46.171 ;
     RECT  42.264 45.841 48.186 46.201 ;
     RECT  58.032 46.111 58.158 46.265 ;
     RECT  34.815 45.419 35.097 46.273 ;
     RECT  82.656 46.111 82.674 46.301 ;
     RECT  84.888 46.171 84.906 46.301 ;
     RECT  49.248 46.171 49.842 46.309 ;
     RECT  50.796 46.139 51.426 46.309 ;
     RECT  42.264 46.201 48.33 46.315 ;
     RECT  49.248 46.309 51.426 46.315 ;
     RECT  2.304 46.171 2.697 46.381 ;
     RECT  3.924 45.581 3.942 46.381 ;
     RECT  66.132 45.841 66.474 46.381 ;
     RECT  67.215 45.149 67.497 46.381 ;
     RECT  78.015 45.967 78.642 46.381 ;
     RECT  2.304 46.381 3.942 46.409 ;
     RECT  35.892 45.995 40.497 46.409 ;
     RECT  42.264 46.315 51.426 46.409 ;
     RECT  41.436 45.995 41.454 46.471 ;
     RECT  42.264 46.409 51.297 46.471 ;
     RECT  74.52 46.201 74.538 46.471 ;
     RECT  6.804 46.201 6.822 46.499 ;
     RECT  58.428 46.309 58.446 46.499 ;
     RECT  74.52 46.471 75.15 46.499 ;
     RECT  65.808 46.381 67.497 46.501 ;
     RECT  2.415 46.409 3.942 46.535 ;
     RECT  41.436 46.471 51.297 46.535 ;
     RECT  78.015 46.381 78.75 46.535 ;
     RECT  65.808 46.501 67.698 46.541 ;
     RECT  58.716 46.507 58.734 46.579 ;
     RECT  5.04 46.411 5.058 46.603 ;
     RECT  58.716 46.579 59.274 46.607 ;
     RECT  74.664 46.499 75.15 46.607 ;
     RECT  54.684 46.543 54.738 46.643 ;
     RECT  66.672 46.541 67.698 46.651 ;
     RECT  2.415 46.535 3.33 46.679 ;
     RECT  54.684 46.643 54.702 46.679 ;
     RECT  65.808 46.541 65.826 46.679 ;
     RECT  66.672 46.651 68.67 46.679 ;
     RECT  0.108 46.603 0.126 46.733 ;
     RECT  36.432 46.409 40.497 46.733 ;
     RECT  4.32 46.603 5.058 46.769 ;
     RECT  41.436 46.535 49.374 46.769 ;
     RECT  59.184 46.607 59.274 46.769 ;
     RECT  37.08 46.733 40.497 46.805 ;
     RECT  75.132 46.607 75.15 46.805 ;
     RECT  37.224 46.805 40.497 46.841 ;
     RECT  59.256 46.769 59.274 46.841 ;
     RECT  66.708 46.679 68.67 46.841 ;
     RECT  70.704 46.741 70.722 46.841 ;
     RECT  6.012 46.651 6.03 46.913 ;
     RECT  66.708 46.841 67.878 46.913 ;
     RECT  68.652 46.841 68.67 46.913 ;
     RECT  40.032 46.841 40.497 46.921 ;
     RECT  41.436 46.769 49.266 46.921 ;
     RECT  37.224 46.841 38.898 47.039 ;
     RECT  37.224 47.039 38.79 47.111 ;
     RECT  34.776 46.273 35.097 47.183 ;
     RECT  2.415 46.679 2.754 47.191 ;
     RECT  2.304 47.191 2.754 47.261 ;
     RECT  56.415 44.879 56.697 47.323 ;
     RECT  56.268 47.323 56.697 47.389 ;
     RECT  4.14 47.317 4.158 47.425 ;
     RECT  51.015 46.535 51.297 47.461 ;
     RECT  68.724 47.323 68.742 47.461 ;
     RECT  75.744 47.281 75.762 47.461 ;
     RECT  3.852 47.425 4.158 47.563 ;
     RECT  5.04 46.769 5.058 47.563 ;
     RECT  4.896 47.563 5.058 47.579 ;
     RECT  56.268 47.389 57.222 47.579 ;
     RECT  68.724 47.461 68.886 47.579 ;
     RECT  3.708 47.563 4.158 47.587 ;
     RECT  4.896 47.579 4.914 47.615 ;
     RECT  68.724 47.579 68.85 47.615 ;
     RECT  75.744 47.461 75.87 47.615 ;
     RECT  72.615 42.449 72.897 47.623 ;
     RECT  40.032 46.921 49.266 47.659 ;
     RECT  71.028 47.389 71.046 47.659 ;
     RECT  72.252 47.623 72.897 47.659 ;
     RECT  82.656 47.191 82.674 47.659 ;
     RECT  83.415 44.375 84.042 47.659 ;
     RECT  39.816 47.659 49.266 47.695 ;
     RECT  50.94 47.461 51.297 47.695 ;
     RECT  50.796 47.695 51.297 47.731 ;
     RECT  61.815 45.581 62.097 47.731 ;
     RECT  63.864 47.587 63.882 47.731 ;
     RECT  66.708 46.913 67.497 47.731 ;
     RECT  70.704 47.659 71.046 47.731 ;
     RECT  81.504 47.659 81.522 47.731 ;
     RECT  82.656 47.659 84.042 47.731 ;
     RECT  70.164 47.731 71.046 47.759 ;
     RECT  72.252 47.659 73.494 47.759 ;
     RECT  3.6 47.587 4.158 47.821 ;
     RECT  39.708 47.695 49.266 47.821 ;
     RECT  63.864 47.731 63.954 47.821 ;
     RECT  78.015 46.535 78.297 47.821 ;
     RECT  70.164 47.759 70.182 47.848 ;
     RECT  2.412 47.261 2.754 47.849 ;
     RECT  59.652 47.461 59.67 47.849 ;
     RECT  63.864 47.821 63.99 47.849 ;
     RECT  66.708 47.731 68.058 47.849 ;
     RECT  70.02 47.848 70.182 47.849 ;
     RECT  72.252 47.759 72.99 47.849 ;
     RECT  81.504 47.731 84.042 47.849 ;
     RECT  70.956 47.759 71.046 47.851 ;
     RECT  2.415 47.849 2.754 47.857 ;
     RECT  3.6 47.821 4.554 47.857 ;
     RECT  37.296 47.111 38.79 47.857 ;
     RECT  5.652 47.731 5.67 47.885 ;
     RECT  37.08 47.857 38.79 47.885 ;
     RECT  61.815 47.731 62.73 47.885 ;
     RECT  63.936 47.849 63.99 47.885 ;
     RECT  67.104 47.849 68.058 47.885 ;
     RECT  68.832 47.615 68.85 47.885 ;
     RECT  70.02 47.849 70.11 47.885 ;
     RECT  81.504 47.849 82.242 47.885 ;
     RECT  85.464 46.699 85.482 47.885 ;
     RECT  77.904 47.821 78.297 47.929 ;
     RECT  63.972 47.885 63.99 47.993 ;
     RECT  37.908 47.885 38.79 48.001 ;
     RECT  39.636 47.821 49.266 48.001 ;
     RECT  77.904 47.929 78.678 48.001 ;
     RECT  37.908 48.001 49.266 48.029 ;
     RECT  77.796 48.001 78.678 48.029 ;
     RECT  61.815 47.885 62.694 48.091 ;
     RECT  2.415 47.857 4.554 48.119 ;
     RECT  76.356 47.731 76.374 48.119 ;
     RECT  61.488 48.091 62.694 48.125 ;
     RECT  50.796 47.731 51.75 48.127 ;
     RECT  67.104 47.885 67.497 48.128 ;
     RECT  70.956 47.851 71.154 48.128 ;
     RECT  39.276 48.029 49.266 48.155 ;
     RECT  77.796 48.029 78.354 48.155 ;
     RECT  2.415 48.119 4.518 48.191 ;
     RECT  70.956 48.128 70.974 48.191 ;
     RECT  81.504 47.885 81.522 48.227 ;
     RECT  50.724 48.127 51.75 48.263 ;
     RECT  51.015 48.263 51.75 48.271 ;
     RECT  72.468 47.849 72.99 48.299 ;
     RECT  0.54 48.271 0.558 48.331 ;
     RECT  0.144 48.331 0.558 48.389 ;
     RECT  61.488 48.125 62.55 48.389 ;
     RECT  83.232 47.849 84.042 48.389 ;
     RECT  70.092 47.885 70.11 48.425 ;
     RECT  85.356 48.331 85.374 48.461 ;
     RECT  52.704 48.541 52.722 48.659 ;
     RECT  39.456 48.155 49.266 48.739 ;
     RECT  39.456 48.739 49.698 48.767 ;
     RECT  83.232 48.389 83.898 48.811 ;
     RECT  54.72 48.631 54.738 48.839 ;
     RECT  37.908 48.029 37.962 48.859 ;
     RECT  61.815 48.389 62.55 48.929 ;
     RECT  78.015 48.155 78.354 48.929 ;
     RECT  39.456 48.767 46.206 48.973 ;
     RECT  51.015 48.271 51.786 48.989 ;
     RECT  73.944 48.811 73.962 49.001 ;
     RECT  72.615 48.299 72.99 49.037 ;
     RECT  37.908 48.859 38.682 49.081 ;
     RECT  39.42 48.973 46.206 49.081 ;
     RECT  3.564 48.191 4.374 49.243 ;
     RECT  2.415 48.191 2.697 49.279 ;
     RECT  3.456 49.243 4.374 49.279 ;
     RECT  2.415 49.279 4.374 49.351 ;
     RECT  2.304 49.351 4.374 49.421 ;
     RECT  46.944 48.767 49.698 49.435 ;
     RECT  51.015 48.989 51.297 49.435 ;
     RECT  46.944 49.435 49.806 49.441 ;
     RECT  50.796 49.435 51.297 49.441 ;
     RECT  70.704 48.739 70.722 49.531 ;
     RECT  70.704 49.531 71.262 49.577 ;
     RECT  74.628 49.441 74.646 49.577 ;
     RECT  60.3 49.477 60.318 49.621 ;
     RECT  72.615 49.037 72.897 49.621 ;
     RECT  83.196 48.811 83.898 49.621 ;
     RECT  78.015 48.929 78.297 49.711 ;
     RECT  60.3 49.621 60.426 49.739 ;
     RECT  70.704 49.577 70.722 49.739 ;
     RECT  60.3 49.739 60.318 49.775 ;
     RECT  46.944 49.441 51.297 49.811 ;
     RECT  61.815 48.929 62.097 49.819 ;
     RECT  58.716 49.711 58.734 49.847 ;
     RECT  2.415 49.421 4.374 49.891 ;
     RECT  50.724 49.811 51.297 49.891 ;
     RECT  72.216 49.621 72.897 49.891 ;
     RECT  82.728 49.621 83.898 49.891 ;
     RECT  0.54 48.389 0.558 49.949 ;
     RECT  37.908 49.081 46.206 49.981 ;
     RECT  46.944 49.811 49.95 49.981 ;
     RECT  78.015 49.711 78.354 49.981 ;
     RECT  37.908 49.981 49.95 50.009 ;
     RECT  50.724 49.891 51.75 50.009 ;
     RECT  61.704 49.819 62.097 50.009 ;
     RECT  72.072 49.891 72.897 50.009 ;
     RECT  77.148 49.549 77.166 50.009 ;
     RECT  61.815 50.009 62.097 50.017 ;
     RECT  78.015 49.981 78.678 50.017 ;
     RECT  72.144 50.009 72.897 50.045 ;
     RECT  82.656 49.891 83.898 50.045 ;
     RECT  72.396 50.045 72.897 50.053 ;
     RECT  50.796 50.009 51.75 50.081 ;
     RECT  2.415 49.891 4.41 50.089 ;
     RECT  61.815 50.017 62.73 50.153 ;
     RECT  73.764 49.891 73.782 50.153 ;
     RECT  78.015 50.017 78.75 50.153 ;
     RECT  2.415 50.089 4.554 50.279 ;
     RECT  54.18 50.443 54.198 50.521 ;
     RECT  52.38 50.431 52.398 50.573 ;
     RECT  0.108 50.491 0.126 50.621 ;
     RECT  3.816 50.279 4.554 50.701 ;
     RECT  54.18 50.521 54.378 50.701 ;
     RECT  50.796 50.081 51.297 50.731 ;
     RECT  37.08 47.885 37.098 50.791 ;
     RECT  72.396 50.053 72.99 50.791 ;
     RECT  37.08 50.791 37.17 50.819 ;
     RECT  72.396 50.791 73.242 50.855 ;
     RECT  82.08 50.521 82.098 50.855 ;
     RECT  71.532 50.821 71.55 50.861 ;
     RECT  37.908 50.009 49.554 50.863 ;
     RECT  74.088 50.701 74.106 50.863 ;
     RECT  78.015 50.153 78.462 50.863 ;
     RECT  3.816 50.701 5.13 50.891 ;
     RECT  74.088 50.863 74.646 50.891 ;
     RECT  63.216 50.557 63.234 50.899 ;
     RECT  54.144 50.701 54.378 50.927 ;
     RECT  72.468 50.855 73.242 50.963 ;
     RECT  74.628 50.891 74.646 50.963 ;
     RECT  83.232 50.045 83.898 50.971 ;
     RECT  63.216 50.899 63.342 50.999 ;
     RECT  2.415 50.279 3.006 51.019 ;
     RECT  54.144 50.927 54.162 51.089 ;
     RECT  61.056 50.791 61.074 51.089 ;
     RECT  71.208 50.971 71.298 51.089 ;
     RECT  77.436 50.863 78.462 51.089 ;
     RECT  61.815 50.153 62.097 51.097 ;
     RECT  78.015 51.089 78.462 51.097 ;
     RECT  37.908 50.863 49.698 51.125 ;
     RECT  71.28 51.089 71.298 51.125 ;
     RECT  82.872 50.971 83.898 51.125 ;
     RECT  3.816 50.891 4.554 51.161 ;
     RECT  78.015 51.097 78.678 51.197 ;
     RECT  61.815 51.097 62.73 51.233 ;
     RECT  72.468 50.963 72.897 51.233 ;
     RECT  42.156 51.125 49.698 51.245 ;
     RECT  2.304 51.019 3.006 51.355 ;
     RECT  42.552 51.245 49.698 51.359 ;
     RECT  37.908 51.125 41.346 51.395 ;
     RECT  42.552 51.359 49.554 51.395 ;
     RECT  83.232 51.125 83.898 51.467 ;
     RECT  83.415 51.467 83.898 51.475 ;
     RECT  50.688 50.731 51.297 51.511 ;
     RECT  67.215 48.128 67.497 51.511 ;
     RECT  50.688 51.511 51.642 51.533 ;
     RECT  67.215 51.511 68.706 51.581 ;
     RECT  3.816 51.161 4.482 51.629 ;
     RECT  59.652 51.331 59.67 51.629 ;
     RECT  75.816 51.367 75.834 51.629 ;
     RECT  3.816 51.629 4.014 51.665 ;
     RECT  67.215 51.581 68.166 51.665 ;
     RECT  82.44 51.511 82.458 51.665 ;
     RECT  2.304 51.355 3.078 51.709 ;
     RECT  3.816 51.665 3.942 51.709 ;
     RECT  78.015 51.197 78.642 51.737 ;
     RECT  51.015 51.533 51.642 51.773 ;
     RECT  61.815 51.233 62.694 51.773 ;
     RECT  69.624 51.511 69.642 51.773 ;
     RECT  2.304 51.709 3.942 51.809 ;
     RECT  39.492 51.395 41.346 51.871 ;
     RECT  37.908 51.395 38.754 51.899 ;
     RECT  39.492 51.871 41.814 52.015 ;
     RECT  42.552 51.395 47.07 52.015 ;
     RECT  37.944 51.899 38.754 52.061 ;
     RECT  0.108 52.051 0.126 52.109 ;
     RECT  2.415 51.809 3.942 52.169 ;
     RECT  4.86 52.051 4.878 52.169 ;
     RECT  82.656 52.213 82.674 52.313 ;
     RECT  5.328 52.285 5.346 52.321 ;
     RECT  47.916 51.395 49.554 52.321 ;
     RECT  6.804 52.213 6.822 52.349 ;
     RECT  70.02 52.321 70.182 52.411 ;
     RECT  71.028 52.321 71.046 52.411 ;
     RECT  2.415 52.169 3.546 52.439 ;
     RECT  5.328 52.321 5.598 52.439 ;
     RECT  69.192 52.321 69.21 52.439 ;
     RECT  70.02 52.411 71.046 52.439 ;
     RECT  39.492 52.015 47.07 52.447 ;
     RECT  47.808 52.321 49.554 52.447 ;
     RECT  67.215 51.665 67.497 52.459 ;
     RECT  81.504 52.321 81.522 52.475 ;
     RECT  70.02 52.439 70.362 52.493 ;
     RECT  39.492 52.447 49.554 52.555 ;
     RECT  39.168 52.555 49.59 52.583 ;
     RECT  47.736 52.583 49.59 52.591 ;
     RECT  59.688 52.321 59.706 52.591 ;
     RECT  67.215 52.459 67.734 52.591 ;
     RECT  2.415 52.439 3.438 52.651 ;
     RECT  5.328 52.439 5.562 52.709 ;
     RECT  69.552 52.555 69.57 52.709 ;
     RECT  5.328 52.709 5.454 52.745 ;
     RECT  39.168 52.583 46.962 52.789 ;
     RECT  51.015 51.773 51.297 52.789 ;
     RECT  78.015 51.737 78.297 52.789 ;
     RECT  47.736 52.591 50.166 52.825 ;
     RECT  59.688 52.591 59.85 52.825 ;
     RECT  67.215 52.591 67.878 52.825 ;
     RECT  70.344 52.493 70.362 52.853 ;
     RECT  51.015 52.789 51.75 52.861 ;
     RECT  75.024 52.789 75.042 52.861 ;
     RECT  75.852 52.591 75.87 52.861 ;
     RECT  2.304 52.651 3.438 52.889 ;
     RECT  54.684 52.789 54.702 52.889 ;
     RECT  4.284 52.447 4.482 52.979 ;
     RECT  47.736 52.825 50.202 52.979 ;
     RECT  75.024 52.861 75.87 52.979 ;
     RECT  78.015 52.789 78.642 52.979 ;
     RECT  49.176 52.979 50.202 52.981 ;
     RECT  51.015 52.861 51.822 52.981 ;
     RECT  49.176 52.981 51.822 52.987 ;
     RECT  67.14 52.825 67.878 52.987 ;
     RECT  68.652 52.861 68.67 52.987 ;
     RECT  75.024 52.979 75.762 53.015 ;
     RECT  49.176 52.987 52.362 53.021 ;
     RECT  51.015 53.021 52.362 53.024 ;
     RECT  53.352 52.951 53.37 53.035 ;
     RECT  47.808 52.979 48.294 53.051 ;
     RECT  52.344 53.024 52.362 53.069 ;
     RECT  39.096 52.789 46.962 53.125 ;
     RECT  53.352 53.035 53.766 53.131 ;
     RECT  66.528 52.987 68.67 53.159 ;
     RECT  39.06 53.125 46.962 53.165 ;
     RECT  0.108 52.951 0.126 53.213 ;
     RECT  61.815 51.773 62.097 53.221 ;
     RECT  49.176 53.021 49.41 53.249 ;
     RECT  53.316 53.131 53.946 53.249 ;
     RECT  66.708 53.159 68.67 53.249 ;
     RECT  75.024 53.015 75.186 53.249 ;
     RECT  2.415 52.889 3.438 53.285 ;
     RECT  49.32 53.249 49.338 53.285 ;
     RECT  53.316 53.249 53.766 53.285 ;
     RECT  59.112 52.825 59.85 53.285 ;
     RECT  75.024 53.249 75.042 53.285 ;
     RECT  39.096 53.165 46.962 53.321 ;
     RECT  68.328 53.249 68.67 53.321 ;
     RECT  39.168 53.321 46.962 53.329 ;
     RECT  53.316 53.285 53.334 53.357 ;
     RECT  4.644 52.987 5.13 53.393 ;
     RECT  59.436 53.285 59.85 53.393 ;
     RECT  68.652 53.321 68.67 53.393 ;
     RECT  72.615 51.233 72.897 53.491 ;
     RECT  3.492 53.401 3.87 53.519 ;
     RECT  59.436 53.393 59.454 53.519 ;
     RECT  64.044 53.035 64.062 53.519 ;
     RECT  3.492 53.519 3.726 53.555 ;
     RECT  61.815 53.221 62.73 53.555 ;
     RECT  83.415 51.475 84.042 53.563 ;
     RECT  50.148 53.021 50.166 53.591 ;
     RECT  64.836 53.401 64.854 53.671 ;
     RECT  85.464 48.859 85.482 53.707 ;
     RECT  0.54 53.563 0.558 53.741 ;
     RECT  39.168 53.329 46.998 53.755 ;
     RECT  47.808 53.051 48.258 53.755 ;
     RECT  39.168 53.755 48.258 53.789 ;
     RECT  45.468 53.789 48.006 53.825 ;
     RECT  64.188 53.671 64.998 53.825 ;
     RECT  72.615 53.491 73.602 53.825 ;
     RECT  4.644 53.393 4.662 53.861 ;
     RECT  64.188 53.825 64.854 53.897 ;
     RECT  66.708 53.249 67.497 53.897 ;
     RECT  84.888 53.707 85.482 53.897 ;
     RECT  83.232 53.563 84.042 53.969 ;
     RECT  39.168 53.789 44.658 54.059 ;
     RECT  64.728 53.897 64.854 54.059 ;
     RECT  37.944 52.061 38.178 54.091 ;
     RECT  64.728 54.059 64.746 54.095 ;
     RECT  37.944 54.091 38.754 54.131 ;
     RECT  2.415 53.285 2.697 54.235 ;
     RECT  2.304 54.235 2.697 54.481 ;
     RECT  3.492 53.555 3.51 54.481 ;
     RECT  65.7 54.445 65.718 54.481 ;
     RECT  2.304 54.481 4.158 54.557 ;
     RECT  45.468 53.825 47.034 54.571 ;
     RECT  47.844 53.825 48.006 54.571 ;
     RECT  78.015 52.979 78.297 54.571 ;
     RECT  83.415 53.969 84.042 54.599 ;
     RECT  4.932 54.481 4.95 54.671 ;
     RECT  65.7 54.481 66.402 54.671 ;
     RECT  67.215 53.897 67.497 54.715 ;
     RECT  45.468 54.571 48.006 54.751 ;
     RECT  59.94 54.715 59.958 54.751 ;
     RECT  65.7 54.671 65.898 54.751 ;
     RECT  4.14 54.557 4.158 54.779 ;
     RECT  85.464 53.897 85.482 54.811 ;
     RECT  39.996 54.059 44.658 54.859 ;
     RECT  45.468 54.751 48.366 54.859 ;
     RECT  39.996 54.859 48.366 54.869 ;
     RECT  53.604 54.715 53.622 54.869 ;
     RECT  54.648 54.751 54.666 54.869 ;
     RECT  59.94 54.751 60.318 54.869 ;
     RECT  65.556 54.751 65.898 54.905 ;
     RECT  84.888 54.811 85.482 54.977 ;
     RECT  41.94 54.869 48.366 54.985 ;
     RECT  51.015 53.024 51.297 54.985 ;
     RECT  54.504 54.985 54.522 55.021 ;
     RECT  66.96 54.715 67.497 55.021 ;
     RECT  82.656 54.913 82.674 55.021 ;
     RECT  54.396 55.021 54.522 55.037 ;
     RECT  2.304 54.557 3.402 55.049 ;
     RECT  53.46 55.003 53.478 55.049 ;
     RECT  66.96 55.021 67.554 55.111 ;
     RECT  55.476 55.021 55.494 55.139 ;
     RECT  59.94 54.869 59.958 55.139 ;
     RECT  74.988 54.301 75.006 55.139 ;
     RECT  61.815 53.555 62.097 55.147 ;
     RECT  65.88 54.905 65.898 55.175 ;
     RECT  41.94 54.985 48.474 55.219 ;
     RECT  49.248 55.147 49.266 55.219 ;
     RECT  39.996 54.869 41.202 55.243 ;
     RECT  61.815 55.147 62.694 55.247 ;
     RECT  66.96 55.111 67.662 55.247 ;
     RECT  37.152 50.819 37.17 55.255 ;
     RECT  37.944 54.131 38.178 55.255 ;
     RECT  2.412 55.049 3.402 55.283 ;
     RECT  82.44 55.021 82.674 55.283 ;
     RECT  37.152 55.255 38.178 55.285 ;
     RECT  2.415 55.283 3.402 55.291 ;
     RECT  36.972 55.285 38.178 55.291 ;
     RECT  39.816 55.243 41.202 55.381 ;
     RECT  36.972 55.291 38.79 55.489 ;
     RECT  83.415 54.599 83.898 55.489 ;
     RECT  50.688 54.985 51.297 55.525 ;
     RECT  36.9 55.489 38.79 55.552 ;
     RECT  2.415 55.291 3.618 55.561 ;
     RECT  4.788 55.525 4.806 55.561 ;
     RECT  68.724 55.525 68.742 55.561 ;
     RECT  78.015 54.571 78.642 55.561 ;
     RECT  4.788 55.561 4.95 55.613 ;
     RECT  41.94 55.219 49.266 55.627 ;
     RECT  2.415 55.561 3.834 55.651 ;
     RECT  76.356 55.381 76.374 55.651 ;
     RECT  59.004 55.291 59.022 55.679 ;
     RECT  68.4 55.561 68.994 55.679 ;
     RECT  75.816 55.651 76.374 55.679 ;
     RECT  83.415 55.489 84.042 55.679 ;
     RECT  66.96 55.247 67.497 55.715 ;
     RECT  5.724 55.561 5.742 55.751 ;
     RECT  36.9 55.552 38.826 55.759 ;
     RECT  39.78 55.381 41.202 55.771 ;
     RECT  41.94 55.627 49.59 55.771 ;
     RECT  78.015 55.561 78.678 55.787 ;
     RECT  70.524 55.687 70.542 55.819 ;
     RECT  36.9 55.759 38.862 55.831 ;
     RECT  39.78 55.771 49.59 55.831 ;
     RECT  50.508 55.525 51.297 55.831 ;
     RECT  4.932 55.613 4.95 55.859 ;
     RECT  70.092 55.819 70.542 55.859 ;
     RECT  0.108 55.831 0.126 55.901 ;
     RECT  85.464 54.977 85.482 55.901 ;
     RECT  36.9 55.831 51.297 55.949 ;
     RECT  68.976 55.679 68.994 55.949 ;
     RECT  54.396 55.037 54.414 55.985 ;
     RECT  59.256 55.723 59.274 55.985 ;
     RECT  82.44 55.283 82.458 55.985 ;
     RECT  70.524 55.859 70.542 56.021 ;
     RECT  34.815 47.183 35.097 56.059 ;
     RECT  36.9 55.949 49.626 56.093 ;
     RECT  50.652 55.949 51.297 56.093 ;
     RECT  75.816 55.679 75.834 56.129 ;
     RECT  24.015 15.719 24.297 56.191 ;
     RECT  34.776 56.059 35.097 56.191 ;
     RECT  13.215 2.413 13.497 56.203 ;
     RECT  23.904 56.191 24.297 56.237 ;
     RECT  34.704 56.191 35.097 56.237 ;
     RECT  13.215 56.203 13.662 56.371 ;
     RECT  12.816 56.371 13.662 56.399 ;
     RECT  84.888 55.957 84.906 56.429 ;
     RECT  2.415 55.651 3.906 56.443 ;
     RECT  83.415 55.679 83.898 56.569 ;
     RECT  2.415 56.443 4.014 56.641 ;
     RECT  78.015 55.787 78.297 56.641 ;
     RECT  10.836 56.569 10.854 56.669 ;
     RECT  37.08 56.093 49.626 56.731 ;
     RECT  77.724 56.641 78.297 56.731 ;
     RECT  54.972 56.641 54.99 56.759 ;
     RECT  2.415 56.641 4.698 56.765 ;
     RECT  12.816 56.399 13.497 56.765 ;
     RECT  67.215 55.715 67.497 56.767 ;
     RECT  70.992 56.641 71.154 56.767 ;
     RECT  72.615 53.825 72.897 56.767 ;
     RECT  54.036 56.731 54.054 56.795 ;
     RECT  69.984 56.731 70.002 56.803 ;
     RECT  70.776 56.767 71.226 56.803 ;
     RECT  77.652 56.731 78.297 56.803 ;
     RECT  83.415 56.569 84.042 56.803 ;
     RECT  77.652 56.803 78.678 56.831 ;
     RECT  67.212 56.767 67.497 56.867 ;
     RECT  69.984 56.803 71.226 56.867 ;
     RECT  75.492 56.803 75.51 56.875 ;
     RECT  70.452 56.867 71.226 56.911 ;
     RECT  72 56.767 72.897 56.911 ;
     RECT  75.024 56.875 75.51 56.911 ;
     RECT  70.452 56.911 72.897 56.939 ;
     RECT  2.415 56.765 4.23 56.971 ;
     RECT  59.904 56.767 59.922 57.001 ;
     RECT  75.024 56.911 76.014 57.005 ;
     RECT  54.18 56.911 54.198 57.029 ;
     RECT  75.492 57.005 76.014 57.029 ;
     RECT  78.015 56.831 78.678 57.029 ;
     RECT  83.232 56.803 84.042 57.037 ;
     RECT  64.548 56.911 64.566 57.065 ;
     RECT  37.08 56.731 49.734 57.101 ;
     RECT  71.712 56.939 71.802 57.101 ;
     RECT  75.996 57.029 76.014 57.101 ;
     RECT  58.788 57.001 58.806 57.137 ;
     RECT  59.904 57.001 60.21 57.137 ;
     RECT  6.804 57.109 6.822 57.209 ;
     RECT  2.376 56.971 4.23 57.335 ;
     RECT  37.08 57.101 49.59 57.371 ;
     RECT  82.62 57.037 84.042 57.407 ;
     RECT  5.112 56.911 5.13 57.443 ;
     RECT  2.376 57.335 4.194 57.451 ;
     RECT  59.904 57.137 60.066 57.569 ;
     RECT  70.452 56.939 70.938 57.569 ;
     RECT  76.932 57.181 76.95 57.569 ;
     RECT  59.904 57.569 59.922 57.605 ;
     RECT  82.62 57.407 82.638 57.605 ;
     RECT  71.712 57.101 71.73 57.713 ;
     RECT  51.015 56.093 51.297 57.721 ;
     RECT  50.4 57.721 51.297 57.991 ;
     RECT  70.704 57.569 70.938 57.991 ;
     RECT  2.304 57.451 4.194 58.061 ;
     RECT  37.08 57.371 49.05 58.072 ;
     RECT  37.044 58.072 49.05 58.109 ;
     RECT  54.972 57.991 54.99 58.109 ;
     RECT  70.704 57.991 71.37 58.109 ;
     RECT  61.815 55.247 62.097 58.117 ;
     RECT  54.036 58.075 54.054 58.145 ;
     RECT  70.704 58.109 71.334 58.145 ;
     RECT  82.44 57.991 82.458 58.145 ;
     RECT  61.815 58.117 62.406 58.261 ;
     RECT  72.615 56.939 72.897 58.261 ;
     RECT  50.328 57.991 51.297 58.351 ;
     RECT  78.015 57.029 78.297 58.351 ;
     RECT  52.272 58.075 52.29 58.379 ;
     RECT  61.815 58.261 62.55 58.379 ;
     RECT  74.088 58.315 74.106 58.379 ;
     RECT  61.815 58.379 62.406 58.415 ;
     RECT  61.815 58.415 62.097 58.423 ;
     RECT  50.256 58.351 51.297 58.451 ;
     RECT  71.064 58.145 71.334 58.523 ;
     RECT  72.144 58.261 72.897 58.523 ;
     RECT  77.112 57.991 77.13 58.531 ;
     RECT  71.064 58.523 71.082 58.559 ;
     RECT  80.964 58.081 80.982 58.559 ;
     RECT  5.256 58.531 5.274 58.621 ;
     RECT  5.256 58.621 5.706 58.648 ;
     RECT  61.344 58.423 62.097 58.649 ;
     RECT  76.968 58.531 77.13 58.649 ;
     RECT  5.112 58.648 5.706 58.685 ;
     RECT  72.216 58.523 72.897 58.685 ;
     RECT  75.024 58.531 75.042 58.721 ;
     RECT  82.404 58.531 82.422 58.721 ;
     RECT  37.08 58.109 49.05 58.733 ;
     RECT  6.804 58.729 6.822 58.829 ;
     RECT  2.415 58.061 4.194 58.891 ;
     RECT  83.415 57.407 84.042 58.955 ;
     RECT  2.415 58.891 4.266 59.131 ;
     RECT  2.304 59.131 4.266 59.161 ;
     RECT  37.08 58.733 48.906 59.189 ;
     RECT  83.415 58.955 83.898 59.197 ;
     RECT  37.08 59.189 48.87 59.225 ;
     RECT  2.304 59.161 4.446 59.261 ;
     RECT  5.688 58.685 5.706 59.261 ;
     RECT  49.896 59.233 49.914 59.269 ;
     RECT  50.724 58.451 51.297 59.269 ;
     RECT  2.304 59.261 3.726 59.297 ;
     RECT  71.424 59.269 71.442 59.305 ;
     RECT  72.504 58.685 72.897 59.305 ;
     RECT  78.015 58.351 78.462 59.305 ;
     RECT  78.015 59.305 78.678 59.341 ;
     RECT  50.724 59.269 51.786 59.369 ;
     RECT  49.824 59.269 49.914 59.419 ;
     RECT  70.74 59.305 71.442 59.431 ;
     RECT  49.68 59.419 49.914 59.459 ;
     RECT  50.724 59.369 51.714 59.459 ;
     RECT  61.815 58.649 62.097 59.467 ;
     RECT  72.504 59.305 74.034 59.467 ;
     RECT  44.676 59.225 48.87 59.495 ;
     RECT  82.08 59.341 82.098 59.495 ;
     RECT  60.588 59.341 60.606 59.539 ;
     RECT  61.38 59.467 62.097 59.539 ;
     RECT  72.504 59.467 74.142 59.563 ;
     RECT  67.215 56.867 67.497 59.575 ;
     RECT  83.232 59.197 83.898 59.575 ;
     RECT  70.704 59.431 71.442 59.603 ;
     RECT  50.724 59.459 51.534 59.639 ;
     RECT  70.74 59.603 71.442 59.639 ;
     RECT  66.744 59.575 67.497 59.701 ;
     RECT  2.415 59.297 3.726 59.729 ;
     RECT  44.676 59.495 48.762 59.729 ;
     RECT  54.684 59.611 54.702 59.729 ;
     RECT  60.588 59.539 62.766 59.729 ;
     RECT  72.36 59.563 74.142 59.729 ;
     RECT  77.868 59.341 78.678 59.729 ;
     RECT  66.744 59.701 67.59 59.741 ;
     RECT  61.272 59.729 62.766 59.765 ;
     RECT  71.244 59.639 71.442 59.765 ;
     RECT  72.36 59.729 73.026 59.765 ;
     RECT  74.124 59.729 74.142 59.765 ;
     RECT  50.76 59.639 51.534 59.789 ;
     RECT  72.36 59.765 72.897 59.809 ;
     RECT  51.015 59.789 51.534 59.837 ;
     RECT  58.716 59.701 58.734 59.837 ;
     RECT  61.815 59.765 62.766 59.837 ;
     RECT  66.744 59.741 67.497 59.837 ;
     RECT  2.415 59.729 3.546 59.843 ;
     RECT  37.08 59.225 43.938 59.971 ;
     RECT  44.676 59.729 48.69 59.971 ;
     RECT  71.712 59.809 72.897 59.999 ;
     RECT  76.968 58.649 76.986 59.999 ;
     RECT  72.216 59.999 72.897 60.071 ;
     RECT  82.764 59.575 83.898 60.115 ;
     RECT  78.015 59.729 78.678 60.143 ;
     RECT  82.764 60.115 84.042 60.269 ;
     RECT  2.415 59.843 3.258 60.619 ;
     RECT  4.536 59.809 4.554 60.619 ;
     RECT  82.764 60.269 83.898 60.647 ;
     RECT  2.415 60.619 4.554 60.691 ;
     RECT  2.304 60.691 4.554 60.809 ;
     RECT  71.064 60.781 71.082 60.917 ;
     RECT  37.08 59.971 48.69 60.925 ;
     RECT  68.436 59.881 68.454 60.955 ;
     RECT  70.056 60.925 70.074 60.961 ;
     RECT  2.304 60.809 3.726 60.989 ;
     RECT  70.056 60.961 70.974 60.989 ;
     RECT  72.615 60.071 72.897 61.003 ;
     RECT  37.08 60.925 48.834 61.051 ;
     RECT  72.504 61.003 72.954 61.079 ;
     RECT  74.124 61.003 74.142 61.079 ;
     RECT  75.816 60.889 75.834 61.079 ;
     RECT  51.015 59.837 51.297 61.087 ;
     RECT  70.776 60.989 70.974 61.115 ;
     RECT  59.904 61.087 59.922 61.123 ;
     RECT  68.436 60.955 68.958 61.123 ;
     RECT  37.08 61.051 49.158 61.133 ;
     RECT  52.956 61.051 52.974 61.151 ;
     RECT  4.536 60.809 4.554 61.223 ;
     RECT  82.08 60.961 82.098 61.223 ;
     RECT  51.015 61.087 52.002 61.231 ;
     RECT  70.884 61.115 70.974 61.259 ;
     RECT  61.815 59.837 62.097 61.321 ;
     RECT  37.08 61.133 49.014 61.349 ;
     RECT  68.436 61.123 69.894 61.349 ;
     RECT  70.956 61.259 70.974 61.349 ;
     RECT  75.96 61.123 76.374 61.349 ;
     RECT  78.015 60.143 78.297 61.357 ;
     RECT  72.615 61.079 72.954 61.469 ;
     RECT  50.076 61.231 50.094 61.493 ;
     RECT  69.876 61.349 69.894 61.493 ;
     RECT  2.304 60.989 3.546 61.529 ;
     RECT  51.015 61.231 52.146 61.579 ;
     RECT  59.832 61.123 59.922 61.591 ;
     RECT  67.215 59.837 67.497 61.591 ;
     RECT  37.08 61.349 48.726 61.619 ;
     RECT  5.4 61.591 5.418 61.627 ;
     RECT  37.08 61.619 48.438 61.655 ;
     RECT  50.868 61.579 52.146 61.691 ;
     RECT  59.616 61.591 59.994 61.691 ;
     RECT  4.572 61.627 5.418 61.763 ;
     RECT  2.376 61.529 3.546 61.771 ;
     RECT  56.415 47.579 56.697 61.771 ;
     RECT  61.815 61.321 62.694 61.771 ;
     RECT  66.708 61.591 67.497 61.771 ;
     RECT  68.436 61.349 68.994 61.771 ;
     RECT  83.232 60.647 83.898 61.771 ;
     RECT  37.08 61.655 46.746 61.772 ;
     RECT  37.08 61.772 46.71 61.799 ;
     RECT  66.708 61.771 68.994 61.861 ;
     RECT  37.08 61.799 38.934 61.889 ;
     RECT  47.556 61.655 47.826 61.889 ;
     RECT  55.692 61.771 56.697 61.889 ;
     RECT  59.616 61.691 59.634 61.889 ;
     RECT  75.96 61.349 75.978 61.889 ;
     RECT  39.996 61.799 46.71 61.925 ;
     RECT  52.92 61.231 52.938 61.925 ;
     RECT  66.672 61.861 68.994 61.925 ;
     RECT  66.672 61.925 68.454 61.963 ;
     RECT  44.136 61.925 46.71 61.997 ;
     RECT  50.868 61.691 51.822 61.997 ;
     RECT  61.815 61.771 62.73 61.997 ;
     RECT  66.492 61.963 68.454 61.997 ;
     RECT  44.208 61.997 46.638 62.033 ;
     RECT  66.492 61.997 67.497 62.041 ;
     RECT  2.376 61.771 3.726 62.045 ;
     RECT  55.548 61.897 55.566 62.141 ;
     RECT  4.572 61.763 5.13 62.159 ;
     RECT  47.556 61.889 47.682 62.159 ;
     RECT  61.02 61.771 61.038 62.159 ;
     RECT  82.98 61.771 83.898 62.167 ;
     RECT  47.556 62.159 47.574 62.195 ;
     RECT  66.456 62.041 67.497 62.195 ;
     RECT  4.644 62.159 5.13 62.231 ;
     RECT  64.404 61.861 64.422 62.267 ;
     RECT  82.656 62.167 83.898 62.267 ;
     RECT  4.644 62.231 4.662 62.303 ;
     RECT  2.376 62.045 3.474 62.311 ;
     RECT  83.415 62.267 83.898 62.311 ;
     RECT  66.456 62.195 66.474 62.339 ;
     RECT  78.015 61.357 78.678 62.339 ;
     RECT  2.304 62.311 3.474 62.381 ;
     RECT  85.464 56.971 85.482 62.465 ;
     RECT  39.996 61.925 43.398 62.731 ;
     RECT  44.208 62.033 46.566 62.731 ;
     RECT  39.996 62.731 46.566 62.815 ;
     RECT  39.996 62.815 46.638 62.851 ;
     RECT  50.868 61.997 51.297 62.851 ;
     RECT  2.376 62.381 3.474 62.879 ;
     RECT  0.108 62.671 0.126 62.909 ;
     RECT  2.376 62.879 3.438 62.969 ;
     RECT  50.868 62.851 51.498 62.969 ;
     RECT  84.888 62.875 84.906 63.041 ;
     RECT  37.08 61.889 37.926 63.049 ;
     RECT  39.996 62.851 46.782 63.049 ;
     RECT  82.656 62.267 82.674 63.049 ;
     RECT  83.415 62.311 84.042 63.049 ;
     RECT  37.08 63.049 38.178 63.121 ;
     RECT  65.592 63.085 65.61 63.121 ;
     RECT  74.628 62.941 74.646 63.121 ;
     RECT  58.464 62.851 58.482 63.239 ;
     RECT  65.268 63.121 66.258 63.239 ;
     RECT  52.02 63.121 52.038 63.275 ;
     RECT  65.34 63.239 66.258 63.275 ;
     RECT  74.484 63.121 74.646 63.275 ;
     RECT  37.08 63.121 38.61 63.355 ;
     RECT  39.996 63.049 47.25 63.391 ;
     RECT  66.024 63.275 66.042 63.419 ;
     RECT  0.54 63.121 0.558 63.485 ;
     RECT  67.215 62.195 67.497 63.499 ;
     RECT  66.888 63.499 67.497 63.545 ;
     RECT  85.356 63.451 85.374 63.581 ;
     RECT  39.996 63.391 47.61 63.589 ;
     RECT  82.656 63.049 84.042 63.589 ;
     RECT  5.148 63.481 5.634 63.625 ;
     RECT  2.415 62.969 3.438 63.643 ;
     RECT  13.215 56.765 13.497 63.643 ;
     RECT  24.015 56.237 24.297 63.643 ;
     RECT  34.815 56.237 35.097 63.643 ;
     RECT  2.415 63.643 3.978 63.661 ;
     RECT  39.672 63.589 47.61 63.661 ;
     RECT  49.392 63.391 49.41 63.661 ;
     RECT  67.215 63.545 67.497 63.661 ;
     RECT  5.004 63.625 5.634 63.677 ;
     RECT  9.144 63.589 9.162 63.689 ;
     RECT  22.824 63.589 22.842 63.689 ;
     RECT  23.904 63.643 24.297 63.689 ;
     RECT  30.78 63.589 30.798 63.689 ;
     RECT  34.704 63.643 35.097 63.689 ;
     RECT  2.415 63.661 4.086 63.751 ;
     RECT  49.392 63.661 49.698 63.779 ;
     RECT  52.272 63.739 52.29 63.779 ;
     RECT  74.844 63.481 74.862 63.779 ;
     RECT  82.08 63.589 84.042 63.779 ;
     RECT  49.392 63.779 49.41 63.781 ;
     RECT  5.616 63.677 5.634 63.815 ;
     RECT  39.672 63.661 47.934 63.815 ;
     RECT  67.215 63.661 67.662 63.815 ;
     RECT  82.08 63.779 82.314 63.815 ;
     RECT  6.804 63.643 6.822 63.821 ;
     RECT  48.744 63.781 49.41 63.821 ;
     RECT  37.08 63.355 38.934 63.823 ;
     RECT  39.672 63.815 47.826 63.823 ;
     RECT  69.804 63.787 69.822 63.823 ;
     RECT  70.632 63.751 70.65 63.823 ;
     RECT  69.804 63.823 70.65 63.824 ;
     RECT  13.104 63.643 13.497 63.835 ;
     RECT  69.012 63.751 69.03 63.851 ;
     RECT  60.012 63.787 60.03 63.931 ;
     RECT  48.888 63.821 49.41 64.049 ;
     RECT  52.416 63.931 52.434 64.049 ;
     RECT  60.012 63.931 60.174 64.049 ;
     RECT  68.976 63.931 68.994 64.049 ;
     RECT  70.056 63.824 70.65 64.049 ;
     RECT  83.415 63.779 84.042 64.049 ;
     RECT  37.08 63.823 47.826 64.085 ;
     RECT  59.004 63.823 59.022 64.085 ;
     RECT  60.012 64.049 60.03 64.085 ;
     RECT  82.08 63.815 82.098 64.085 ;
     RECT  54.684 63.931 54.702 64.093 ;
     RECT  48.888 64.049 48.906 64.121 ;
     RECT  70.632 64.049 70.65 64.121 ;
     RECT  85.464 63.979 85.482 64.121 ;
     RECT  54.684 64.093 54.738 64.129 ;
     RECT  53.208 63.931 53.226 64.193 ;
     RECT  54.288 64.129 54.738 64.229 ;
     RECT  39.852 64.085 47.826 64.319 ;
     RECT  53.352 64.267 53.37 64.319 ;
     RECT  54.288 64.229 54.306 64.319 ;
     RECT  12.816 63.835 13.497 64.397 ;
     RECT  2.415 63.751 4.338 64.471 ;
     RECT  0.108 63.883 0.126 64.541 ;
     RECT  2.415 64.471 4.806 64.561 ;
     RECT  34.815 63.689 35.097 64.669 ;
     RECT  2.415 64.561 4.914 64.697 ;
     RECT  83.415 64.049 83.934 64.831 ;
     RECT  53.496 64.471 53.514 64.859 ;
     RECT  39.852 64.319 47.538 64.975 ;
     RECT  72.615 61.469 72.897 65.011 ;
     RECT  78.015 62.339 78.297 65.011 ;
     RECT  2.415 64.697 4.842 65.035 ;
     RECT  83.232 64.831 83.934 65.069 ;
     RECT  74.124 64.939 74.142 65.101 ;
     RECT  2.304 65.035 4.842 65.129 ;
     RECT  72.615 65.011 72.99 65.129 ;
     RECT  78.015 65.011 78.354 65.129 ;
     RECT  83.232 65.069 83.898 65.165 ;
     RECT  82.08 64.939 82.098 65.209 ;
     RECT  83.232 65.165 83.862 65.209 ;
     RECT  82.08 65.209 83.862 65.273 ;
     RECT  39.78 64.975 47.538 65.281 ;
     RECT  72.615 65.129 72.897 65.281 ;
     RECT  2.304 65.129 3.87 65.309 ;
     RECT  34.776 64.669 35.097 65.309 ;
     RECT  60.84 65.101 60.858 65.399 ;
     RECT  61.815 61.997 62.097 65.407 ;
     RECT  39.78 65.281 47.934 65.435 ;
     RECT  71.784 65.281 72.897 65.435 ;
     RECT  37.08 64.085 38.934 65.443 ;
     RECT  71.784 65.435 71.802 65.507 ;
     RECT  74.124 65.101 74.682 65.507 ;
     RECT  37.08 65.443 39.042 65.515 ;
     RECT  39.78 65.435 47.826 65.515 ;
     RECT  61.815 65.407 62.73 65.543 ;
     RECT  4.644 65.129 4.842 65.669 ;
     RECT  4.644 65.669 4.698 65.705 ;
     RECT  82.62 65.273 83.862 65.705 ;
     RECT  84.888 64.507 84.906 65.741 ;
     RECT  49.284 65.131 49.302 65.821 ;
     RECT  75.888 65.749 75.906 65.821 ;
     RECT  49.068 65.821 49.554 65.899 ;
     RECT  37.08 65.515 47.826 65.939 ;
     RECT  61.815 65.543 62.262 65.939 ;
     RECT  49.068 65.899 50.274 65.947 ;
     RECT  51.015 62.969 51.297 65.947 ;
     RECT  70.704 65.641 70.722 65.975 ;
     RECT  74.268 65.507 74.682 66.011 ;
     RECT  75.816 65.821 75.906 66.019 ;
     RECT  75.672 66.019 75.906 66.055 ;
     RECT  83.415 65.705 83.862 66.055 ;
     RECT  0.54 64.741 0.558 66.091 ;
     RECT  2.415 65.309 3.87 66.091 ;
     RECT  4.644 65.705 4.662 66.091 ;
     RECT  74.628 66.011 74.682 66.091 ;
     RECT  75.672 66.055 76.014 66.091 ;
     RECT  49.068 65.947 51.297 66.119 ;
     RECT  74.628 66.091 76.014 66.119 ;
     RECT  75.996 66.119 76.014 66.125 ;
     RECT  0.504 66.091 0.558 66.173 ;
     RECT  78.015 65.129 78.297 66.181 ;
     RECT  2.415 66.091 4.662 66.209 ;
     RECT  50.4 66.119 51.297 66.209 ;
     RECT  74.628 66.119 75.186 66.209 ;
     RECT  79.488 65.911 79.506 66.209 ;
     RECT  37.08 65.939 47.034 66.281 ;
     RECT  80.352 66.091 80.37 66.281 ;
     RECT  2.415 66.209 3.87 66.317 ;
     RECT  78.015 66.181 78.642 66.389 ;
     RECT  61.815 65.939 62.097 66.451 ;
     RECT  3.42 66.317 3.87 66.479 ;
     RECT  79.812 66.361 79.83 66.479 ;
     RECT  82.62 65.705 82.674 66.479 ;
     RECT  82.62 66.479 82.638 66.551 ;
     RECT  49.068 66.119 49.59 66.653 ;
     RECT  85.356 66.139 85.374 66.667 ;
     RECT  0.504 66.173 0.522 66.701 ;
     RECT  39.672 66.281 47.034 66.721 ;
     RECT  47.808 65.939 47.826 66.721 ;
     RECT  4.608 66.209 4.662 66.749 ;
     RECT  61.632 66.451 62.097 66.785 ;
     RECT  49.14 66.653 49.59 66.821 ;
     RECT  74.628 66.209 75.15 66.821 ;
     RECT  39.672 66.721 47.826 66.865 ;
     RECT  74.628 66.821 74.862 66.991 ;
     RECT  39.672 66.865 47.862 67.019 ;
     RECT  50.076 66.901 50.094 67.019 ;
     RECT  85.356 66.667 85.482 67.091 ;
     RECT  74.556 66.991 74.862 67.135 ;
     RECT  51.015 66.209 51.297 67.147 ;
     RECT  51.015 67.147 51.642 67.171 ;
     RECT  74.34 67.135 74.862 67.171 ;
     RECT  74.124 67.171 74.862 67.199 ;
     RECT  37.08 66.281 38.934 67.243 ;
     RECT  2.415 66.317 2.697 67.261 ;
     RECT  49.14 66.821 49.302 67.289 ;
     RECT  36.972 67.243 38.934 67.325 ;
     RECT  61.056 66.991 61.074 67.325 ;
     RECT  74.124 67.199 74.574 67.361 ;
     RECT  37.08 67.325 38.934 67.369 ;
     RECT  39.672 67.019 47.574 67.369 ;
     RECT  3.708 66.479 3.87 67.441 ;
     RECT  4.608 66.749 4.626 67.441 ;
     RECT  37.08 67.369 47.574 67.469 ;
     RECT  2.415 67.261 2.898 67.603 ;
     RECT  3.708 67.441 4.626 67.603 ;
     RECT  61.815 66.785 62.097 67.675 ;
     RECT  78.015 66.389 78.297 67.711 ;
     RECT  2.415 67.603 4.626 67.801 ;
     RECT  72.615 65.435 72.897 67.801 ;
     RECT  73.62 67.675 74.034 67.801 ;
     RECT  50.904 67.171 51.642 67.805 ;
     RECT  37.476 67.469 47.574 67.829 ;
     RECT  54.684 67.711 54.702 67.829 ;
     RECT  72.615 67.801 74.034 67.829 ;
     RECT  50.904 67.805 51.297 67.945 ;
     RECT  72.615 67.829 73.566 68.099 ;
     RECT  74.808 67.981 75.15 68.107 ;
     RECT  49.14 67.289 49.158 68.135 ;
     RECT  82.08 67.171 82.098 68.135 ;
     RECT  61.815 67.675 62.694 68.171 ;
     RECT  77.544 67.711 78.297 68.207 ;
     RECT  2.415 67.801 4.662 68.251 ;
     RECT  78.015 68.207 78.297 68.251 ;
     RECT  79.056 67.981 79.074 68.251 ;
     RECT  50.328 67.945 51.297 68.279 ;
     RECT  2.415 68.251 4.986 68.405 ;
     RECT  37.476 67.829 47.538 68.405 ;
     RECT  78.015 68.251 79.074 68.405 ;
     RECT  61.815 68.171 62.097 68.611 ;
     RECT  2.415 68.405 4.338 68.639 ;
     RECT  44.136 68.405 47.538 68.639 ;
     RECT  83.415 66.055 84.042 68.639 ;
     RECT  74.664 68.107 75.15 68.755 ;
     RECT  74.664 68.755 75.51 68.791 ;
     RECT  48.312 68.755 48.33 68.813 ;
     RECT  49.248 68.521 49.338 68.819 ;
     RECT  52.02 67.981 52.038 68.819 ;
     RECT  54.108 68.731 54.126 68.881 ;
     RECT  44.136 68.639 47.502 68.909 ;
     RECT  61.776 68.611 62.097 68.909 ;
     RECT  44.136 68.909 47.43 68.915 ;
     RECT  74.664 68.791 75.654 68.945 ;
     RECT  79.128 68.611 79.29 68.945 ;
     RECT  53.82 68.881 54.126 68.957 ;
     RECT  49.248 68.819 49.266 68.981 ;
     RECT  37.476 68.405 43.398 69.151 ;
     RECT  75.492 68.945 75.654 69.421 ;
     RECT  75.492 69.421 76.374 69.449 ;
     RECT  74.664 68.945 74.682 69.547 ;
     RECT  2.415 68.639 4.266 69.601 ;
     RECT  79.272 68.945 79.29 69.719 ;
     RECT  51.015 68.279 51.297 69.727 ;
     RECT  61.815 68.909 62.097 69.727 ;
     RECT  37.476 69.151 43.614 69.799 ;
     RECT  76.356 69.449 76.374 69.863 ;
     RECT  2.415 69.601 4.518 69.871 ;
     RECT  49.572 69.727 49.59 69.871 ;
     RECT  50.364 69.727 51.297 69.871 ;
     RECT  50.364 69.871 51.57 69.899 ;
     RECT  61.815 69.727 62.37 69.961 ;
     RECT  2.304 69.871 4.518 69.965 ;
     RECT  5.292 69.835 5.31 69.989 ;
     RECT  48.276 69.529 48.294 69.989 ;
     RECT  37.476 69.799 43.686 70.024 ;
     RECT  44.424 68.915 47.43 70.024 ;
     RECT  50.436 69.899 51.57 70.061 ;
     RECT  51.015 70.061 51.57 70.069 ;
     RECT  72.615 68.099 72.897 70.069 ;
     RECT  78.015 68.405 78.297 70.069 ;
     RECT  2.415 69.965 4.518 70.105 ;
     RECT  2.415 70.105 4.554 70.141 ;
     RECT  2.415 70.141 4.698 70.259 ;
     RECT  51.015 70.069 51.894 70.259 ;
     RECT  78.015 70.069 78.57 70.259 ;
     RECT  72.615 70.069 73.098 70.261 ;
     RECT  82.548 69.601 82.566 70.267 ;
     RECT  78.015 70.259 78.462 70.295 ;
     RECT  72.615 70.261 73.278 70.301 ;
     RECT  49.248 69.871 49.59 70.331 ;
     RECT  37.476 70.024 47.43 70.411 ;
     RECT  74.016 69.547 74.682 70.411 ;
     RECT  82.548 70.267 82.674 70.411 ;
     RECT  83.415 68.639 83.898 70.411 ;
     RECT  61.56 69.961 62.37 70.439 ;
     RECT  2.415 70.259 4.554 70.445 ;
     RECT  2.415 70.445 4.23 70.529 ;
     RECT  61.812 70.439 62.37 70.529 ;
     RECT  71.568 70.411 71.586 70.529 ;
     RECT  72.615 70.301 73.098 70.529 ;
     RECT  73.836 70.411 74.682 70.529 ;
     RECT  37.116 70.411 47.502 70.537 ;
     RECT  61.815 70.529 62.37 70.537 ;
     RECT  2.415 70.529 3.222 70.565 ;
     RECT  36.972 70.537 47.502 70.565 ;
     RECT  4.212 70.529 4.23 70.601 ;
     RECT  73.836 70.529 74.538 70.601 ;
     RECT  2.415 70.565 3.006 70.673 ;
     RECT  5.472 70.411 5.49 70.673 ;
     RECT  48.924 70.411 48.942 70.673 ;
     RECT  73.944 70.601 74.538 70.673 ;
     RECT  82.512 70.411 82.674 70.673 ;
     RECT  36.972 70.565 47.43 70.685 ;
     RECT  51.015 70.259 51.606 70.733 ;
     RECT  83.415 70.411 84.042 70.799 ;
     RECT  83.415 70.799 83.898 70.807 ;
     RECT  37.476 70.685 47.43 70.835 ;
     RECT  53.748 70.699 53.766 70.835 ;
     RECT  54.756 70.681 54.774 70.871 ;
     RECT  67.215 63.815 67.497 70.879 ;
     RECT  70.704 69.691 70.722 70.951 ;
     RECT  38.772 70.835 47.43 70.979 ;
     RECT  70.38 70.951 70.758 71.021 ;
     RECT  39.312 70.979 47.43 71.069 ;
     RECT  70.38 71.021 70.398 71.069 ;
     RECT  77.22 70.771 77.238 71.069 ;
     RECT  78.015 70.295 78.297 71.077 ;
     RECT  39.312 71.069 47.286 71.105 ;
     RECT  66.708 70.879 67.497 71.105 ;
     RECT  83.196 70.807 83.898 71.105 ;
     RECT  28.152 70.795 28.17 71.117 ;
     RECT  39.312 71.105 42.426 71.141 ;
     RECT  71.676 70.951 71.694 71.141 ;
     RECT  78.015 71.077 78.678 71.177 ;
     RECT  61.815 70.537 62.73 71.213 ;
     RECT  26.604 70.771 26.622 71.249 ;
     RECT  43.74 71.105 46.314 71.339 ;
     RECT  2.415 70.673 2.934 71.419 ;
     RECT  83.232 71.105 83.898 71.447 ;
     RECT  73.944 70.673 73.962 71.549 ;
     RECT  83.415 71.447 83.898 71.725 ;
     RECT  2.415 71.419 3.474 71.851 ;
     RECT  39.744 71.141 42.426 71.887 ;
     RECT  44.892 71.339 46.314 71.887 ;
     RECT  38.808 71.851 38.826 71.923 ;
     RECT  39.744 71.887 42.75 72.031 ;
     RECT  43.74 71.339 43.758 72.031 ;
     RECT  78.015 71.177 78.297 72.031 ;
     RECT  39.744 72.031 43.758 72.121 ;
     RECT  44.892 71.887 46.386 72.121 ;
     RECT  70.956 72.031 71.55 72.121 ;
     RECT  72.615 70.529 72.897 72.139 ;
     RECT  52.02 72.031 52.038 72.149 ;
     RECT  77.256 71.887 77.274 72.149 ;
     RECT  70.704 72.121 71.55 72.173 ;
     RECT  71.532 72.173 71.55 72.185 ;
     RECT  72.288 72.139 72.897 72.185 ;
     RECT  61.815 71.213 62.097 72.193 ;
     RECT  70.704 72.173 70.722 72.193 ;
     RECT  78.015 72.031 78.678 72.193 ;
     RECT  60.876 72.157 60.894 72.229 ;
     RECT  38.808 71.923 38.97 72.265 ;
     RECT  39.744 72.121 46.386 72.265 ;
     RECT  70.38 72.193 70.722 72.293 ;
     RECT  77.652 72.193 78.678 72.293 ;
     RECT  47.7 72.265 47.718 72.301 ;
     RECT  51.015 70.733 51.297 72.301 ;
     RECT  60.876 72.229 61.038 72.301 ;
     RECT  72.396 72.185 72.897 72.301 ;
     RECT  54.684 72.229 54.702 72.329 ;
     RECT  61.815 72.193 62.73 72.329 ;
     RECT  71.64 72.229 71.658 72.329 ;
     RECT  2.415 71.851 4.086 72.331 ;
     RECT  38.808 72.265 46.386 72.379 ;
     RECT  50.904 72.301 51.297 72.391 ;
     RECT  60.192 72.301 61.038 72.419 ;
     RECT  72.396 72.301 73.242 72.419 ;
     RECT  77.652 72.293 78.297 72.419 ;
     RECT  2.415 72.331 4.734 72.427 ;
     RECT  5.616 72.391 5.634 72.427 ;
     RECT  58.716 72.391 58.734 72.427 ;
     RECT  2.376 72.427 5.634 72.455 ;
     RECT  47.7 72.301 48.258 72.455 ;
     RECT  60.192 72.419 60.894 72.455 ;
     RECT  38.664 72.379 46.386 72.463 ;
     RECT  72.576 72.419 73.242 72.491 ;
     RECT  80.964 72.301 80.982 72.527 ;
     RECT  82.656 72.427 82.674 72.527 ;
     RECT  38.664 72.463 46.89 72.571 ;
     RECT  47.7 72.455 47.862 72.571 ;
     RECT  74.664 72.121 74.682 72.571 ;
     RECT  50.688 72.391 51.297 72.599 ;
     RECT  58.716 72.427 58.806 72.599 ;
     RECT  73.8 72.535 73.818 72.605 ;
     RECT  37.476 70.835 37.674 72.661 ;
     RECT  38.664 72.571 47.862 72.661 ;
     RECT  37.476 72.661 47.862 72.689 ;
     RECT  49.032 72.301 49.05 72.689 ;
     RECT  4.896 72.455 5.634 72.725 ;
     RECT  34.815 65.309 35.097 72.769 ;
     RECT  5.22 72.725 5.634 72.797 ;
     RECT  72.576 72.491 72.897 72.797 ;
     RECT  82.296 72.571 82.314 72.797 ;
     RECT  2.376 72.455 4.086 72.869 ;
     RECT  34.776 72.769 35.097 72.869 ;
     RECT  58.716 72.599 58.734 72.869 ;
     RECT  47.7 72.689 47.862 73.031 ;
     RECT  0.54 72.841 0.558 73.181 ;
     RECT  32.904 73.111 32.922 73.229 ;
     RECT  37.476 72.689 46.746 73.301 ;
     RECT  72.615 72.797 72.897 73.309 ;
     RECT  74.664 72.571 74.754 73.309 ;
     RECT  72.615 73.309 73.494 73.345 ;
     RECT  74.664 73.309 75.258 73.345 ;
     RECT  72.615 73.345 73.566 73.381 ;
     RECT  74.664 73.345 75.834 73.381 ;
     RECT  83.415 71.725 84.042 73.381 ;
     RECT  52.704 73.339 52.722 73.499 ;
     RECT  53.64 73.111 53.658 73.499 ;
     RECT  72.615 73.381 75.834 73.499 ;
     RECT  79.596 73.201 79.614 73.499 ;
     RECT  74.916 73.499 75.834 73.535 ;
     RECT  2.376 72.869 3.726 73.615 ;
     RECT  38.772 73.301 46.746 73.651 ;
     RECT  47.7 73.031 47.718 73.651 ;
     RECT  63.54 73.507 63.558 73.651 ;
     RECT  2.376 73.615 3.906 73.675 ;
     RECT  72.615 73.499 73.818 73.679 ;
     RECT  63.54 73.651 63.666 73.769 ;
     RECT  59.976 73.345 59.994 73.805 ;
     RECT  63.54 73.769 63.558 73.805 ;
     RECT  37.476 73.301 37.674 73.849 ;
     RECT  2.304 73.675 3.906 73.885 ;
     RECT  83.304 73.381 84.042 73.921 ;
     RECT  2.304 73.885 4.374 74.039 ;
     RECT  48.6 73.921 48.618 74.039 ;
     RECT  36.18 73.849 36.198 74.047 ;
     RECT  37.188 73.849 37.674 74.047 ;
     RECT  74.952 73.535 75.834 74.047 ;
     RECT  2.304 74.039 4.194 74.075 ;
     RECT  38.772 73.651 47.718 74.083 ;
     RECT  36.18 74.047 37.674 74.119 ;
     RECT  38.772 74.083 47.826 74.119 ;
     RECT  74.952 74.047 76.374 74.183 ;
     RECT  36.18 74.119 47.826 74.191 ;
     RECT  60.984 74.011 61.002 74.191 ;
     RECT  78.015 72.419 78.297 74.191 ;
     RECT  34.815 72.869 35.097 74.281 ;
     RECT  35.82 74.191 47.826 74.281 ;
     RECT  72.615 73.679 72.897 74.281 ;
     RECT  0.54 74.083 0.558 74.285 ;
     RECT  48.816 74.191 48.978 74.309 ;
     RECT  75.168 74.183 76.374 74.309 ;
     RECT  34.815 74.281 47.826 74.333 ;
     RECT  60.696 74.191 61.002 74.345 ;
     RECT  5.148 74.191 5.166 74.453 ;
     RECT  49.788 74.389 49.806 74.461 ;
     RECT  72.036 74.281 72.897 74.461 ;
     RECT  73.656 73.679 73.818 74.461 ;
     RECT  79.704 74.281 79.722 74.461 ;
     RECT  82.872 73.921 84.042 74.461 ;
     RECT  48.816 74.309 48.834 74.525 ;
     RECT  82.728 74.461 84.042 74.551 ;
     RECT  35.82 74.333 47.826 74.579 ;
     RECT  49.752 74.461 49.806 74.579 ;
     RECT  60.696 74.345 60.714 74.579 ;
     RECT  72.036 74.461 73.962 74.579 ;
     RECT  75.6 74.309 75.618 74.579 ;
     RECT  78.015 74.191 78.426 74.579 ;
     RECT  79.704 74.461 79.866 74.579 ;
     RECT  35.82 74.579 46.674 74.615 ;
     RECT  72.036 74.579 72.897 74.615 ;
     RECT  73.944 74.579 73.962 74.615 ;
     RECT  79.848 74.579 79.866 74.615 ;
     RECT  82.62 74.551 84.042 74.615 ;
     RECT  49.752 74.579 49.77 74.651 ;
     RECT  76.356 74.309 76.374 74.651 ;
     RECT  82.62 74.615 82.638 74.651 ;
     RECT  51.015 72.599 51.297 74.683 ;
     RECT  30.78 74.683 30.798 74.861 ;
     RECT  35.964 74.615 46.674 74.861 ;
     RECT  50.724 74.683 51.297 74.861 ;
     RECT  0.108 74.779 0.126 74.909 ;
     RECT  2.304 74.075 4.086 75.001 ;
     RECT  2.304 75.001 4.554 75.119 ;
     RECT  2.304 75.119 3.942 75.227 ;
     RECT  48.42 75.259 48.438 75.271 ;
     RECT  2.376 75.227 3.942 75.389 ;
     RECT  48.42 75.271 48.582 75.389 ;
     RECT  48.42 75.389 48.474 75.425 ;
     RECT  85.464 67.091 85.482 75.425 ;
     RECT  35.964 74.861 46.602 75.469 ;
     RECT  75.42 75.505 75.438 75.541 ;
     RECT  83.415 74.615 84.042 75.541 ;
     RECT  35.928 75.469 46.602 75.569 ;
     RECT  36.072 75.569 37.674 75.659 ;
     RECT  82.764 75.541 84.042 75.667 ;
     RECT  74.88 75.541 75.654 75.695 ;
     RECT  82.62 75.667 84.042 75.803 ;
     RECT  49.356 75.541 49.374 75.839 ;
     RECT  0.54 75.541 0.558 75.869 ;
     RECT  74.88 75.695 75.438 75.869 ;
     RECT  79.308 75.361 79.326 75.901 ;
     RECT  38.52 75.569 46.602 76.001 ;
     RECT  70.704 75.901 70.722 76.009 ;
     RECT  39.816 76.001 46.602 76.045 ;
     RECT  39.816 76.045 46.638 76.081 ;
     RECT  61.815 72.329 62.097 76.081 ;
     RECT  74.88 75.869 74.898 76.081 ;
     RECT  2.415 75.389 3.942 76.171 ;
     RECT  61.38 76.081 62.097 76.171 ;
     RECT  2.415 76.171 4.554 76.199 ;
     RECT  48.456 75.425 48.474 76.199 ;
     RECT  49.248 76.009 49.338 76.199 ;
     RECT  61.38 76.171 62.766 76.199 ;
     RECT  70.704 76.009 70.758 76.199 ;
     RECT  73.836 76.081 73.854 76.199 ;
     RECT  79.308 75.901 79.434 76.199 ;
     RECT  70.704 76.199 70.722 76.235 ;
     RECT  79.308 76.199 79.326 76.235 ;
     RECT  61.815 76.199 62.766 76.343 ;
     RECT  74.664 76.081 74.898 76.363 ;
     RECT  49.32 76.199 49.338 76.379 ;
     RECT  48.312 76.315 48.33 76.397 ;
     RECT  74.628 76.363 74.898 76.397 ;
     RECT  0.108 76.411 0.126 76.541 ;
     RECT  83.34 75.803 84.042 76.549 ;
     RECT  74.628 76.397 74.79 76.621 ;
     RECT  78.015 74.579 78.297 76.621 ;
     RECT  82.656 76.549 84.042 76.621 ;
     RECT  51.015 74.861 51.297 76.699 ;
     RECT  36.108 75.659 37.674 76.739 ;
     RECT  50.328 76.699 51.297 76.739 ;
     RECT  76.536 76.585 76.554 76.739 ;
     RECT  4.536 76.199 4.554 76.811 ;
     RECT  38.52 76.001 39.078 76.855 ;
     RECT  39.816 76.081 46.71 76.855 ;
     RECT  36.324 76.739 37.674 76.891 ;
     RECT  38.52 76.855 46.71 76.891 ;
     RECT  82.512 76.621 84.042 76.891 ;
     RECT  75.564 76.855 75.582 76.925 ;
     RECT  0.54 76.891 0.558 76.973 ;
     RECT  50.472 76.739 51.297 77.009 ;
     RECT  78.015 76.621 79.218 77.009 ;
     RECT  61.815 76.343 62.298 77.045 ;
     RECT  2.415 76.199 3.69 77.125 ;
     RECT  82.332 76.891 84.042 77.153 ;
     RECT  2.415 77.125 3.762 77.161 ;
     RECT  36.324 76.891 46.71 77.161 ;
     RECT  36.324 77.161 47.106 77.251 ;
     RECT  82.62 77.153 84.042 77.279 ;
     RECT  36.324 77.251 47.322 77.351 ;
     RECT  73.944 76.621 74.79 77.431 ;
     RECT  73.944 77.431 74.934 77.453 ;
     RECT  6.804 77.323 6.822 77.459 ;
     RECT  36.324 77.351 47.25 77.549 ;
     RECT  74.412 77.453 74.934 77.549 ;
     RECT  78.015 77.009 78.534 77.549 ;
     RECT  34.815 74.333 35.097 77.557 ;
     RECT  36.324 77.549 46.962 77.557 ;
     RECT  60.516 77.251 60.534 77.585 ;
     RECT  74.916 77.549 74.934 77.621 ;
     RECT  82.62 77.279 82.638 77.657 ;
     RECT  4.644 77.251 4.662 77.693 ;
     RECT  34.815 77.557 35.478 77.701 ;
     RECT  36.216 77.557 46.962 77.701 ;
     RECT  34.815 77.701 46.962 77.855 ;
     RECT  2.304 77.161 3.87 77.899 ;
     RECT  34.815 77.855 35.622 77.963 ;
     RECT  2.16 77.899 4.302 78.029 ;
     RECT  51.015 77.009 51.297 78.043 ;
     RECT  34.815 77.963 35.478 78.169 ;
     RECT  72.615 74.615 72.897 78.241 ;
     RECT  78.015 77.549 78.297 78.241 ;
     RECT  49.104 78.133 49.122 78.283 ;
     RECT  48.204 78.241 48.222 78.331 ;
     RECT  50.4 78.043 51.297 78.359 ;
     RECT  36.396 77.855 46.962 78.367 ;
     RECT  50.688 78.359 51.297 78.368 ;
     RECT  5.976 78.169 5.994 78.469 ;
     RECT  36.396 78.367 47.034 78.475 ;
     RECT  48.024 78.331 48.222 78.475 ;
     RECT  60.192 78.241 60.21 78.475 ;
     RECT  72.288 78.241 72.897 78.475 ;
     RECT  5.796 78.469 5.994 78.509 ;
     RECT  36.396 78.475 48.222 78.511 ;
     RECT  48.96 78.283 49.122 78.511 ;
     RECT  60.084 78.475 60.21 78.511 ;
     RECT  72.108 78.475 72.897 78.511 ;
     RECT  77.796 78.241 78.297 78.511 ;
     RECT  70.488 78.403 70.506 78.601 ;
     RECT  70.488 78.601 70.686 78.619 ;
     RECT  5.148 78.511 5.166 78.629 ;
     RECT  36.396 78.511 49.122 78.629 ;
     RECT  60.084 78.511 60.282 78.629 ;
     RECT  71.784 78.511 72.897 78.629 ;
     RECT  70.344 78.619 70.686 78.637 ;
     RECT  72.108 78.629 72.897 78.653 ;
     RECT  5.976 78.509 5.994 78.665 ;
     RECT  36.396 78.629 46.782 78.665 ;
     RECT  48.06 78.629 49.122 78.665 ;
     RECT  60.084 78.629 60.102 78.665 ;
     RECT  72.432 78.653 72.897 78.665 ;
     RECT  77.688 78.511 78.297 78.665 ;
     RECT  36.396 78.665 44.154 78.701 ;
     RECT  2.304 78.029 4.302 78.745 ;
     RECT  49.104 78.665 49.122 78.745 ;
     RECT  34.776 78.169 35.478 78.781 ;
     RECT  36.396 78.701 37.674 78.781 ;
     RECT  68.976 78.331 68.994 78.781 ;
     RECT  76.32 78.511 76.338 78.781 ;
     RECT  34.776 78.781 37.674 78.809 ;
     RECT  61.815 77.045 62.097 78.871 ;
     RECT  34.815 78.809 37.674 78.899 ;
     RECT  48.06 78.665 48.078 78.899 ;
     RECT  49.104 78.745 49.194 78.899 ;
     RECT  70.128 78.637 70.686 78.899 ;
     RECT  44.892 78.665 46.782 78.935 ;
     RECT  59.004 78.511 59.022 78.935 ;
     RECT  75.852 78.781 76.734 78.935 ;
     RECT  70.596 78.899 70.686 78.971 ;
     RECT  34.815 78.899 35.478 79.043 ;
     RECT  67.215 71.105 67.497 79.051 ;
     RECT  68.976 78.781 69.066 79.051 ;
     RECT  50.724 78.368 51.297 79.079 ;
     RECT  68.904 79.051 69.066 79.133 ;
     RECT  2.304 78.745 5.13 79.169 ;
     RECT  57.996 78.781 58.014 79.169 ;
     RECT  67.212 79.051 67.497 79.169 ;
     RECT  75.852 78.935 76.41 79.169 ;
     RECT  61.815 78.871 62.73 79.205 ;
     RECT  82.332 79.051 82.35 79.205 ;
     RECT  69.84 79.051 69.858 79.241 ;
     RECT  67.215 79.169 67.497 79.411 ;
     RECT  83.415 77.279 84.042 79.439 ;
     RECT  53.856 79.321 53.874 79.475 ;
     RECT  52.884 79.477 52.902 79.517 ;
     RECT  36.396 78.899 37.674 79.519 ;
     RECT  38.448 78.701 44.154 79.519 ;
     RECT  44.892 78.935 45.897 79.519 ;
     RECT  2.304 79.169 4.302 79.583 ;
     RECT  5.112 79.169 5.13 79.583 ;
     RECT  83.415 79.439 83.898 79.591 ;
     RECT  36.396 79.519 45.897 79.619 ;
     RECT  69.372 79.591 69.678 79.661 ;
     RECT  2.304 79.583 4.05 79.709 ;
     RECT  36.396 79.619 36.414 79.709 ;
     RECT  37.512 79.619 45.897 79.709 ;
     RECT  60.732 79.411 60.75 79.709 ;
     RECT  69.372 79.661 69.462 79.709 ;
     RECT  76.392 79.169 76.41 79.709 ;
     RECT  67.215 79.411 68.058 79.745 ;
     RECT  82.728 79.591 83.898 79.745 ;
     RECT  69.444 79.709 69.462 79.781 ;
     RECT  70.596 78.971 70.614 79.781 ;
     RECT  2.304 79.709 3.726 79.979 ;
     RECT  37.512 79.709 44.37 79.979 ;
     RECT  37.512 79.979 41.13 80.015 ;
     RECT  47.772 80.095 47.79 80.131 ;
     RECT  3.636 79.979 3.726 80.159 ;
     RECT  45.108 79.709 45.897 80.221 ;
     RECT  47.664 80.131 47.79 80.221 ;
     RECT  2.304 79.979 2.754 80.249 ;
     RECT  47.664 80.221 47.862 80.257 ;
     RECT  67.215 79.745 67.914 80.329 ;
     RECT  45.108 80.221 45.99 80.347 ;
     RECT  41.868 79.979 44.37 80.443 ;
     RECT  45.108 80.347 46.278 80.443 ;
     RECT  41.868 80.443 46.278 80.527 ;
     RECT  54.072 80.491 54.09 80.555 ;
     RECT  75.096 80.221 75.114 80.555 ;
     RECT  66.924 80.329 67.914 80.573 ;
     RECT  67.215 80.573 67.914 80.591 ;
     RECT  34.815 79.043 35.097 80.599 ;
     RECT  83.232 79.745 83.898 80.627 ;
     RECT  37.512 80.015 40.497 80.671 ;
     RECT  41.868 80.527 46.53 80.671 ;
     RECT  47.34 80.257 47.862 80.671 ;
     RECT  49.284 80.563 49.302 80.671 ;
     RECT  51.015 79.079 51.297 80.671 ;
     RECT  61.815 79.205 62.097 80.761 ;
     RECT  72.615 78.665 72.897 80.761 ;
     RECT  37.116 80.671 40.497 80.779 ;
     RECT  36.972 80.779 40.497 80.825 ;
     RECT  60.192 80.491 60.21 80.833 ;
     RECT  37.512 80.825 37.53 80.861 ;
     RECT  61.815 80.761 62.694 80.861 ;
     RECT  69.408 80.539 69.426 80.875 ;
     RECT  50.724 80.671 51.297 80.897 ;
     RECT  55.044 80.671 55.062 80.897 ;
     RECT  3.636 80.159 3.654 80.905 ;
     RECT  49.068 80.671 49.302 80.905 ;
     RECT  69.408 80.875 70.038 80.905 ;
     RECT  69.408 80.905 70.218 80.909 ;
     RECT  65.772 80.491 65.79 80.933 ;
     RECT  72.615 80.761 72.954 80.933 ;
     RECT  3.492 80.905 3.654 80.941 ;
     RECT  41.868 80.671 47.862 81.031 ;
     RECT  75.24 80.905 75.258 81.059 ;
     RECT  38.268 80.825 40.497 81.095 ;
     RECT  59.472 80.833 60.21 81.095 ;
     RECT  3.492 80.941 4.014 81.103 ;
     RECT  2.304 80.249 2.697 81.139 ;
     RECT  3.492 81.103 4.086 81.163 ;
     RECT  38.376 81.095 40.497 81.163 ;
     RECT  41.724 81.031 47.862 81.175 ;
     RECT  48.708 80.905 50.166 81.203 ;
     RECT  81.504 80.941 81.522 81.203 ;
     RECT  71.136 81.205 71.154 81.211 ;
     RECT  5.652 81.211 5.67 81.259 ;
     RECT  0.108 81.163 0.126 81.293 ;
     RECT  50.976 80.897 51.297 81.301 ;
     RECT  71.136 81.211 71.478 81.301 ;
     RECT  3.492 81.163 4.554 81.329 ;
     RECT  70.992 81.301 71.478 81.329 ;
     RECT  60.12 81.095 60.21 81.445 ;
     RECT  2.304 81.139 2.754 81.451 ;
     RECT  3.492 81.329 4.302 81.451 ;
     RECT  50.976 81.301 51.39 81.473 ;
     RECT  5.508 81.259 5.67 81.481 ;
     RECT  69.876 80.909 70.218 81.481 ;
     RECT  70.992 81.329 71.442 81.481 ;
     RECT  34.776 80.599 35.097 81.509 ;
     RECT  41.724 81.175 47.898 81.571 ;
     RECT  48.708 81.203 49.77 81.571 ;
     RECT  60.12 81.445 60.282 81.599 ;
     RECT  69.876 81.481 71.442 81.599 ;
     RECT  5.508 81.481 5.85 81.635 ;
     RECT  60.12 81.599 60.138 81.635 ;
     RECT  82.512 81.481 82.53 81.635 ;
     RECT  54.684 81.571 54.702 81.671 ;
     RECT  70.668 81.599 71.442 81.671 ;
     RECT  74.628 81.571 74.682 81.671 ;
     RECT  83.415 80.627 83.898 81.679 ;
     RECT  38.376 81.163 40.554 81.715 ;
     RECT  41.724 81.571 49.77 81.715 ;
     RECT  72.615 80.933 72.897 81.751 ;
     RECT  38.376 81.715 49.77 81.773 ;
     RECT  50.976 81.473 51.297 81.773 ;
     RECT  71.1 81.671 71.442 81.773 ;
     RECT  75.816 81.409 75.834 81.779 ;
     RECT  71.1 81.773 71.118 81.869 ;
     RECT  74.664 81.671 74.682 81.869 ;
     RECT  78.015 78.665 78.297 81.877 ;
     RECT  69.84 81.715 69.858 81.905 ;
     RECT  83.16 81.679 83.898 81.905 ;
     RECT  72.36 81.751 72.897 81.941 ;
     RECT  56.415 61.889 56.697 81.949 ;
     RECT  78.015 81.877 78.678 81.977 ;
     RECT  52.02 81.751 52.038 82.013 ;
     RECT  2.304 81.451 4.302 82.049 ;
     RECT  39.132 81.773 49.77 82.049 ;
     RECT  58.716 81.643 58.734 82.049 ;
     RECT  56.415 81.949 56.934 82.139 ;
     RECT  56.415 82.139 56.697 82.255 ;
     RECT  2.415 82.049 4.302 82.291 ;
     RECT  5.184 82.021 5.202 82.291 ;
     RECT  65.052 82.147 65.07 82.409 ;
     RECT  38.376 81.773 38.394 82.525 ;
     RECT  39.132 82.049 49.482 82.525 ;
     RECT  83.232 81.905 83.898 82.525 ;
     RECT  55.98 82.255 56.697 82.541 ;
     RECT  2.415 82.291 5.202 82.553 ;
     RECT  76.068 82.489 76.086 82.561 ;
     RECT  74.88 82.453 74.97 82.651 ;
     RECT  76.068 82.561 76.158 82.651 ;
     RECT  2.415 82.553 4.158 82.679 ;
     RECT  74.88 82.651 76.158 82.679 ;
     RECT  79.416 82.489 79.434 82.679 ;
     RECT  83.232 82.525 84.042 82.723 ;
     RECT  5.184 82.553 5.202 82.751 ;
     RECT  75.636 82.679 76.158 82.751 ;
     RECT  82.656 82.723 84.042 82.787 ;
     RECT  2.415 82.679 4.05 82.795 ;
     RECT  38.376 82.525 49.482 82.795 ;
     RECT  61.815 80.861 62.097 82.795 ;
     RECT  76.14 82.751 76.158 82.823 ;
     RECT  34.815 81.509 35.097 82.831 ;
     RECT  82.656 82.787 82.674 82.831 ;
     RECT  85.464 76.939 85.482 82.891 ;
     RECT  0.108 82.561 0.126 82.925 ;
     RECT  72.615 81.941 72.897 82.939 ;
     RECT  2.376 82.795 4.05 82.949 ;
     RECT  31.392 82.795 31.41 82.949 ;
     RECT  38.376 82.795 49.878 82.949 ;
     RECT  61.668 82.795 62.097 82.957 ;
     RECT  34.74 82.831 35.097 83.021 ;
     RECT  85.356 82.891 85.482 83.021 ;
     RECT  42.444 82.949 49.878 83.101 ;
     RECT  74.88 82.679 74.898 83.101 ;
     RECT  42.444 83.101 50.166 83.219 ;
     RECT  72.615 82.939 73.494 83.219 ;
     RECT  50.148 83.219 50.166 83.291 ;
     RECT  74.412 83.101 74.898 83.291 ;
     RECT  38.376 82.949 41.67 83.335 ;
     RECT  38.16 83.335 41.67 83.405 ;
     RECT  2.376 82.949 4.014 83.419 ;
     RECT  61.524 82.957 62.097 83.461 ;
     RECT  78.015 81.977 78.297 83.461 ;
     RECT  42.444 83.219 49.302 83.489 ;
     RECT  51.015 81.773 51.297 83.497 ;
     RECT  50.724 83.497 51.297 83.549 ;
     RECT  82.404 82.831 82.674 83.569 ;
     RECT  70.704 83.371 70.722 83.641 ;
     RECT  71.532 83.563 71.55 83.641 ;
     RECT  74.772 83.291 74.898 83.641 ;
     RECT  77.364 83.461 78.297 83.641 ;
     RECT  70.704 83.641 71.874 83.669 ;
     RECT  50.796 83.549 51.297 83.693 ;
     RECT  42.444 83.489 49.266 83.759 ;
     RECT  54.072 83.371 54.09 83.759 ;
     RECT  61.272 83.461 62.097 83.759 ;
     RECT  71.208 83.669 71.874 83.759 ;
     RECT  73.62 83.371 73.638 83.759 ;
     RECT  74.772 83.641 75.042 83.759 ;
     RECT  77.364 83.641 78.75 83.759 ;
     RECT  82.152 83.569 82.674 83.759 ;
     RECT  42.444 83.759 49.122 83.789 ;
     RECT  2.304 83.419 4.014 83.795 ;
     RECT  53.1 83.227 53.118 83.795 ;
     RECT  71.28 83.759 71.874 83.795 ;
     RECT  74.772 83.759 74.898 83.795 ;
     RECT  78.015 83.759 78.75 83.795 ;
     RECT  82.152 83.759 82.314 83.795 ;
     RECT  3.996 83.795 4.014 83.911 ;
     RECT  2.304 83.795 3.15 84.029 ;
     RECT  53.28 83.911 53.298 84.029 ;
     RECT  74.772 83.795 74.79 84.029 ;
     RECT  78.015 83.795 78.678 84.029 ;
     RECT  63.468 83.641 63.486 84.065 ;
     RECT  82.296 83.795 82.314 84.101 ;
     RECT  38.376 83.405 41.67 84.145 ;
     RECT  42.444 83.789 46.926 84.145 ;
     RECT  3.996 83.911 4.59 84.173 ;
     RECT  75.78 83.911 75.798 84.173 ;
     RECT  71.532 83.795 71.874 84.181 ;
     RECT  72.615 83.219 72.897 84.181 ;
     RECT  2.304 84.029 2.826 84.209 ;
     RECT  32.616 84.145 32.634 84.299 ;
     RECT  71.532 84.181 72.897 84.365 ;
     RECT  3.996 84.173 4.554 84.371 ;
     RECT  5.364 83.911 5.382 84.371 ;
     RECT  71.676 84.365 72.897 84.371 ;
     RECT  38.376 84.145 46.926 84.649 ;
     RECT  47.808 83.789 49.122 84.649 ;
     RECT  32.544 84.451 32.562 84.713 ;
     RECT  3.996 84.371 4.014 84.721 ;
     RECT  38.376 84.649 49.122 84.811 ;
     RECT  74.232 84.721 74.25 84.811 ;
     RECT  78.015 84.029 78.57 84.839 ;
     RECT  2.415 84.209 2.826 84.847 ;
     RECT  3.816 84.721 4.014 84.847 ;
     RECT  74.052 84.811 74.25 84.847 ;
     RECT  82.548 84.577 82.674 84.875 ;
     RECT  50.256 84.847 50.274 84.883 ;
     RECT  51.015 83.693 51.297 84.883 ;
     RECT  38.376 84.811 49.338 84.911 ;
     RECT  50.256 84.883 51.297 84.991 ;
     RECT  72.615 84.371 72.897 84.991 ;
     RECT  73.62 84.847 74.25 84.991 ;
     RECT  0.54 84.343 0.558 85.085 ;
     RECT  50.256 84.991 51.354 85.109 ;
     RECT  72.615 84.991 74.25 85.109 ;
     RECT  74.124 85.109 74.25 85.153 ;
     RECT  75.024 84.991 75.114 85.153 ;
     RECT  54.648 84.991 54.738 85.217 ;
     RECT  39.24 84.911 49.338 85.225 ;
     RECT  74.124 85.153 75.114 85.225 ;
     RECT  2.415 84.847 4.014 85.261 ;
     RECT  52.668 85.225 52.686 85.261 ;
     RECT  64.836 84.991 64.854 85.261 ;
     RECT  74.124 85.225 75.546 85.261 ;
     RECT  61.815 83.759 62.097 85.351 ;
     RECT  64.728 85.261 64.854 85.351 ;
     RECT  2.415 85.261 4.41 85.379 ;
     RECT  52.524 85.261 52.686 85.379 ;
     RECT  79.128 85.081 79.29 85.379 ;
     RECT  50.724 85.109 51.354 85.387 ;
     RECT  2.415 85.379 3.978 85.415 ;
     RECT  64.728 85.351 64.926 85.415 ;
     RECT  74.124 85.261 75.69 85.415 ;
     RECT  79.128 85.379 79.146 85.415 ;
     RECT  82.656 84.875 82.674 85.423 ;
     RECT  83.415 82.787 84.042 85.423 ;
     RECT  52.524 85.379 52.542 85.451 ;
     RECT  55.08 85.261 55.098 85.451 ;
     RECT  74.196 85.415 75.438 85.451 ;
     RECT  38.376 84.911 38.394 85.483 ;
     RECT  39.24 85.225 49.914 85.487 ;
     RECT  61.815 85.351 62.73 85.487 ;
     RECT  64.908 85.415 64.926 85.487 ;
     RECT  75.42 85.451 75.438 85.487 ;
     RECT  54.144 85.225 54.162 85.517 ;
     RECT  50.724 85.387 51.714 85.531 ;
     RECT  0.108 85.459 0.126 85.613 ;
     RECT  2.415 85.415 2.934 85.649 ;
     RECT  4.716 85.495 4.734 85.649 ;
     RECT  50.724 85.531 52.218 85.649 ;
     RECT  74.196 85.451 74.682 85.649 ;
     RECT  82.656 85.423 84.042 85.657 ;
     RECT  2.415 85.649 2.862 85.685 ;
     RECT  50.724 85.649 51.297 85.721 ;
     RECT  52.2 85.649 52.218 85.721 ;
     RECT  74.664 85.649 74.682 85.721 ;
     RECT  38.196 85.483 38.394 85.765 ;
     RECT  39.24 85.487 49.158 85.765 ;
     RECT  70.668 85.729 70.686 85.801 ;
     RECT  3.744 85.415 3.978 85.919 ;
     RECT  38.196 85.765 49.158 85.919 ;
     RECT  59.4 85.531 59.418 85.919 ;
     RECT  69.336 85.801 69.354 85.955 ;
     RECT  70.56 85.801 71.046 85.955 ;
     RECT  38.196 85.919 48.582 85.991 ;
     RECT  61.815 85.487 62.694 86.027 ;
     RECT  82.62 85.657 84.042 86.027 ;
     RECT  38.376 85.991 48.582 86.063 ;
     RECT  49.896 85.487 49.914 86.063 ;
     RECT  2.415 85.685 2.697 86.107 ;
     RECT  4.752 86.071 4.77 86.333 ;
     RECT  2.304 86.107 2.697 86.369 ;
     RECT  70.884 85.955 71.046 86.467 ;
     RECT  70.884 86.467 71.226 86.621 ;
     RECT  74.628 86.467 74.646 86.639 ;
     RECT  51.015 85.721 51.297 86.701 ;
     RECT  69.552 86.611 69.57 86.729 ;
     RECT  76.932 85.891 76.95 86.729 ;
     RECT  51.015 86.701 51.354 86.731 ;
     RECT  60.012 86.467 60.03 86.765 ;
     RECT  82.548 86.071 82.566 86.765 ;
     RECT  38.376 86.063 38.394 86.809 ;
     RECT  39.24 86.063 48.582 86.809 ;
     RECT  50.364 86.731 51.354 86.837 ;
     RECT  71.208 86.621 71.226 86.873 ;
     RECT  5.184 86.701 5.202 86.881 ;
     RECT  3.744 85.919 3.762 86.971 ;
     RECT  38.376 86.809 48.582 87.115 ;
     RECT  38.376 87.115 48.906 87.143 ;
     RECT  3.492 86.971 3.762 87.151 ;
     RECT  5.184 86.881 5.526 87.241 ;
     RECT  0.108 86.635 0.126 87.245 ;
     RECT  4.86 87.241 5.526 87.269 ;
     RECT  83.415 86.027 84.042 87.313 ;
     RECT  3.456 87.151 3.762 87.385 ;
     RECT  61.815 86.027 62.097 87.421 ;
     RECT  3.456 87.385 3.942 87.449 ;
     RECT  68.904 87.421 68.922 87.499 ;
     RECT  5.652 87.313 6.174 87.511 ;
     RECT  53.136 87.385 53.154 87.539 ;
     RECT  78.015 84.839 78.297 87.547 ;
     RECT  83.196 87.313 84.042 87.575 ;
     RECT  59.472 87.547 59.49 87.583 ;
     RECT  61.815 87.421 62.766 87.611 ;
     RECT  67.215 80.591 67.497 87.643 ;
     RECT  4.86 87.269 4.878 87.683 ;
     RECT  38.376 87.143 40.497 87.683 ;
     RECT  2.415 86.369 2.697 87.691 ;
     RECT  52.2 87.655 52.218 87.691 ;
     RECT  53.064 87.547 53.082 87.691 ;
     RECT  59.472 87.583 60.03 87.691 ;
     RECT  66.996 87.643 67.497 87.691 ;
     RECT  68.904 87.499 69.57 87.691 ;
     RECT  52.2 87.691 53.082 87.719 ;
     RECT  78.015 87.547 78.75 87.719 ;
     RECT  5.652 87.511 6.606 87.725 ;
     RECT  52.2 87.719 52.362 87.725 ;
     RECT  50.364 86.837 51.297 87.773 ;
     RECT  6.156 87.725 6.606 87.809 ;
     RECT  52.344 87.725 52.362 87.809 ;
     RECT  59.472 87.691 60.174 87.809 ;
     RECT  66.708 87.691 67.806 87.809 ;
     RECT  3.924 87.449 3.942 87.821 ;
     RECT  59.472 87.809 60.03 87.845 ;
     RECT  75.024 87.511 75.042 87.845 ;
     RECT  76.536 87.547 76.554 87.845 ;
     RECT  6.588 87.809 6.606 87.881 ;
     RECT  50.616 87.773 51.297 87.881 ;
     RECT  70.488 87.691 70.506 87.881 ;
     RECT  41.22 87.143 48.906 87.889 ;
     RECT  68.904 87.691 69.714 87.916 ;
     RECT  41.22 87.889 49.374 87.961 ;
     RECT  66.996 87.809 67.806 88.027 ;
     RECT  68.904 87.916 69.75 88.079 ;
     RECT  56.415 82.541 56.697 88.087 ;
     RECT  66.996 88.027 67.95 88.087 ;
     RECT  68.904 88.079 68.994 88.087 ;
     RECT  75.528 88.051 75.546 88.087 ;
     RECT  2.304 87.691 3.186 88.115 ;
     RECT  83.232 87.575 84.042 88.115 ;
     RECT  41.22 87.961 49.698 88.223 ;
     RECT  66.996 88.087 68.994 88.259 ;
     RECT  75.528 88.087 75.654 88.349 ;
     RECT  55.98 88.087 56.697 88.385 ;
     RECT  75.528 88.349 75.546 88.385 ;
     RECT  39.132 87.683 40.497 88.393 ;
     RECT  41.22 88.223 46.818 88.393 ;
     RECT  66.996 88.259 68.382 88.421 ;
     RECT  47.556 88.223 49.698 88.603 ;
     RECT  83.232 88.115 83.898 88.727 ;
     RECT  38.376 87.683 38.394 88.771 ;
     RECT  39.132 88.393 46.818 88.771 ;
     RECT  47.556 88.603 49.842 88.771 ;
     RECT  51.015 87.881 51.297 88.771 ;
     RECT  2.304 88.115 3.042 88.861 ;
     RECT  54.288 88.771 54.306 88.861 ;
     RECT  55.152 88.771 55.17 88.861 ;
     RECT  66.996 88.421 67.806 88.861 ;
     RECT  2.304 88.861 3.51 88.889 ;
     RECT  54.288 88.861 55.17 88.891 ;
     RECT  38.376 88.771 46.818 88.969 ;
     RECT  47.556 88.771 51.297 88.969 ;
     RECT  66.636 88.861 67.806 89.005 ;
     RECT  34.815 83.021 35.097 89.041 ;
     RECT  54.144 88.891 55.17 89.069 ;
     RECT  75.348 88.861 75.366 89.195 ;
     RECT  34.776 89.041 35.097 89.231 ;
     RECT  3.42 88.889 3.51 89.269 ;
     RECT  4.356 89.041 4.374 89.269 ;
     RECT  38.376 88.969 51.297 89.275 ;
     RECT  55.044 89.069 55.17 89.275 ;
     RECT  38.376 89.275 51.534 89.303 ;
     RECT  5.184 89.275 5.202 89.311 ;
     RECT  39.276 89.303 51.534 89.311 ;
     RECT  52.308 88.939 52.326 89.311 ;
     RECT  61.815 87.611 62.097 89.311 ;
     RECT  59.868 88.861 59.886 89.339 ;
     RECT  66.528 89.005 67.806 89.419 ;
     RECT  39.276 89.311 53.262 89.429 ;
     RECT  55.044 89.275 55.242 89.429 ;
     RECT  61.815 89.311 62.73 89.429 ;
     RECT  41.22 89.429 43.074 89.465 ;
     RECT  66.528 89.419 68.526 89.465 ;
     RECT  2.304 88.889 2.697 89.501 ;
     RECT  41.364 89.465 43.074 89.501 ;
     RECT  43.812 89.429 53.262 89.501 ;
     RECT  55.044 89.429 55.062 89.501 ;
     RECT  66.528 89.465 67.842 89.545 ;
     RECT  83.415 88.727 83.898 89.545 ;
     RECT  43.812 89.501 53.118 89.573 ;
     RECT  56.415 88.385 56.697 89.581 ;
     RECT  78.015 87.719 78.297 89.671 ;
     RECT  3.42 89.269 4.374 89.699 ;
     RECT  41.724 89.501 43.074 89.699 ;
     RECT  60.912 89.275 60.93 89.699 ;
     RECT  66.384 89.545 67.842 89.699 ;
     RECT  74.664 89.401 74.79 89.699 ;
     RECT  75.744 89.581 75.762 89.699 ;
     RECT  5.112 89.311 5.202 89.707 ;
     RECT  60.12 89.401 60.138 89.735 ;
     RECT  74.664 89.699 74.682 89.735 ;
     RECT  69.444 89.401 69.462 89.771 ;
     RECT  56.016 89.581 56.697 89.807 ;
     RECT  66.384 89.699 66.402 89.807 ;
     RECT  3.492 89.699 4.374 89.815 ;
     RECT  5.112 89.707 5.238 89.815 ;
     RECT  78.015 89.671 78.642 89.843 ;
     RECT  54 89.467 54.018 89.969 ;
     RECT  2.415 89.501 2.697 89.977 ;
     RECT  3.492 89.815 5.238 89.981 ;
     RECT  4.86 89.981 5.238 90.005 ;
     RECT  43.812 89.573 51.39 90.005 ;
     RECT  0.108 89.899 0.126 90.077 ;
     RECT  52.164 89.573 53.118 90.077 ;
     RECT  4.86 90.005 4.878 90.149 ;
     RECT  52.164 90.077 52.182 90.239 ;
     RECT  53.1 90.077 53.118 90.239 ;
     RECT  61.815 89.429 62.097 90.247 ;
     RECT  49.5 90.005 51.39 90.319 ;
     RECT  41.796 89.699 43.074 90.391 ;
     RECT  43.812 90.005 48.762 90.391 ;
     RECT  82.656 90.247 82.674 90.391 ;
     RECT  82.44 90.391 82.674 90.419 ;
     RECT  70.668 90.391 70.686 90.481 ;
     RECT  61.272 90.247 62.097 90.509 ;
     RECT  76.716 90.391 76.734 90.509 ;
     RECT  2.415 89.977 2.754 90.517 ;
     RECT  3.492 89.981 3.87 90.517 ;
     RECT  82.44 90.419 82.458 90.545 ;
     RECT  70.668 90.481 71.226 90.571 ;
     RECT  70.488 90.571 71.226 90.589 ;
     RECT  70.128 90.589 71.226 90.617 ;
     RECT  41.796 90.391 48.762 90.653 ;
     RECT  2.415 90.517 3.87 90.779 ;
     RECT  70.128 90.617 70.146 90.779 ;
     RECT  41.868 90.653 48.762 90.787 ;
     RECT  49.5 90.319 51.966 90.787 ;
     RECT  2.415 90.779 3.726 90.815 ;
     RECT  41.868 90.787 51.966 90.851 ;
     RECT  39.276 89.429 40.497 90.859 ;
     RECT  71.208 90.617 71.226 90.923 ;
     RECT  38.376 89.303 38.394 90.931 ;
     RECT  39.276 90.859 40.734 90.931 ;
     RECT  41.94 90.851 51.966 90.941 ;
     RECT  2.415 90.815 3.582 90.955 ;
     RECT  4.644 90.751 4.662 91.121 ;
     RECT  38.376 90.931 40.95 91.121 ;
     RECT  42.156 90.941 51.966 91.121 ;
     RECT  44.388 91.121 51.966 91.201 ;
     RECT  78.015 89.843 78.297 91.201 ;
     RECT  61.488 90.509 62.097 91.291 ;
     RECT  67.215 89.699 67.497 91.291 ;
     RECT  71.532 91.201 71.694 91.319 ;
     RECT  42.156 91.121 43.614 91.355 ;
     RECT  71.532 91.319 71.55 91.355 ;
     RECT  54.72 91.291 54.738 91.391 ;
     RECT  58.896 91.429 58.914 91.469 ;
     RECT  52.848 91.363 52.866 91.471 ;
     RECT  72.615 85.109 72.897 91.471 ;
     RECT  83.415 89.545 84.042 91.471 ;
     RECT  57.924 91.561 57.942 91.579 ;
     RECT  61.488 91.291 62.694 91.589 ;
     RECT  66.672 91.291 67.497 91.589 ;
     RECT  70.56 91.471 70.578 91.589 ;
     RECT  75.276 91.471 75.654 91.589 ;
     RECT  77.868 91.201 78.297 91.589 ;
     RECT  82.728 91.471 84.042 91.625 ;
     RECT  57.924 91.579 58.122 91.627 ;
     RECT  74.052 91.435 74.07 91.661 ;
     RECT  61.815 91.589 62.694 91.669 ;
     RECT  79.38 91.561 79.398 91.697 ;
     RECT  44.388 91.201 52.038 91.705 ;
     RECT  52.812 91.471 52.866 91.705 ;
     RECT  61.815 91.669 62.73 91.733 ;
     RECT  72.468 91.471 72.897 91.733 ;
     RECT  44.388 91.705 52.866 91.771 ;
     RECT  57.852 91.627 58.122 91.859 ;
     RECT  83.415 91.625 84.042 91.859 ;
     RECT  42.192 91.355 43.614 91.861 ;
     RECT  44.388 91.771 53.406 91.861 ;
     RECT  4.392 91.741 4.41 92.003 ;
     RECT  42.192 91.861 53.406 92.003 ;
     RECT  38.376 91.121 40.734 92.011 ;
     RECT  75.492 91.589 75.654 92.045 ;
     RECT  2.304 90.955 3.582 92.093 ;
     RECT  54.504 92.011 54.522 92.129 ;
     RECT  64.26 91.867 64.278 92.129 ;
     RECT  75.636 92.045 75.654 92.129 ;
     RECT  38.376 92.011 41.022 92.137 ;
     RECT  42.192 92.003 52.434 92.137 ;
     RECT  38.376 92.137 52.434 92.165 ;
     RECT  79.092 92.011 79.11 92.165 ;
     RECT  38.376 92.165 43.254 92.201 ;
     RECT  76.428 91.471 76.446 92.201 ;
     RECT  66.708 91.589 67.497 92.237 ;
     RECT  2.415 92.093 3.582 92.281 ;
     RECT  5.328 92.245 5.346 92.281 ;
     RECT  34.815 89.231 35.097 92.371 ;
     RECT  34.776 92.371 35.097 92.471 ;
     RECT  43.992 92.165 52.434 92.543 ;
     RECT  2.415 92.281 4.122 92.621 ;
     RECT  5.328 92.281 6.246 92.641 ;
     RECT  53.388 92.003 53.406 92.641 ;
     RECT  74.34 92.011 74.43 92.641 ;
     RECT  78.015 91.589 78.297 92.641 ;
     RECT  3.924 92.621 4.122 92.669 ;
     RECT  37.188 92.551 37.278 92.669 ;
     RECT  43.992 92.543 51.75 92.669 ;
     RECT  5.328 92.641 6.858 92.705 ;
     RECT  74.34 92.641 74.754 92.776 ;
     RECT  74.232 92.776 74.754 92.777 ;
     RECT  4.104 92.669 4.122 92.813 ;
     RECT  5.688 92.705 6.858 92.813 ;
     RECT  37.188 92.669 37.206 92.813 ;
     RECT  74.232 92.777 74.25 92.813 ;
     RECT  72.615 91.733 72.897 92.821 ;
     RECT  72.615 92.821 73.566 92.939 ;
     RECT  78.015 92.641 78.642 92.939 ;
     RECT  53.388 92.641 54.126 92.947 ;
     RECT  63.576 92.677 63.594 92.975 ;
     RECT  82.512 92.821 82.53 92.983 ;
     RECT  75.168 92.821 75.186 93.011 ;
     RECT  38.376 92.201 42.894 93.019 ;
     RECT  58.716 92.947 58.734 93.047 ;
     RECT  82.512 92.983 82.674 93.047 ;
     RECT  53.388 92.947 54.198 93.055 ;
     RECT  83.415 91.859 83.898 93.055 ;
     RECT  82.656 93.047 82.674 93.083 ;
     RECT  38.376 93.019 43.074 93.091 ;
     RECT  76.536 92.947 76.554 93.091 ;
     RECT  75.528 93.055 75.546 93.101 ;
     RECT  4.176 92.821 4.41 93.119 ;
     RECT  0.108 92.587 0.126 93.149 ;
     RECT  28.44 92.923 28.458 93.181 ;
     RECT  29.415 34.115 29.697 93.181 ;
     RECT  43.992 92.669 51.297 93.181 ;
     RECT  28.44 93.181 29.697 93.209 ;
     RECT  53.136 93.055 54.198 93.209 ;
     RECT  64.08 93.091 64.098 93.209 ;
     RECT  67.215 92.237 67.497 93.217 ;
     RECT  28.728 93.209 29.697 93.245 ;
     RECT  79.02 93.091 79.038 93.245 ;
     RECT  38.376 93.091 43.146 93.325 ;
     RECT  43.956 93.181 51.297 93.325 ;
     RECT  66.708 93.217 67.497 93.353 ;
     RECT  76.464 93.091 76.554 93.353 ;
     RECT  76.536 93.353 76.554 93.389 ;
     RECT  34.815 92.471 35.097 93.451 ;
     RECT  2.415 92.621 2.862 93.691 ;
     RECT  2.304 93.691 2.862 93.829 ;
     RECT  83.415 93.055 84.042 93.865 ;
     RECT  5.688 92.813 6.246 93.893 ;
     RECT  38.376 93.325 51.297 93.901 ;
     RECT  2.304 93.829 3.438 93.929 ;
     RECT  37.152 93.901 37.17 93.991 ;
     RECT  72.615 92.939 72.897 93.991 ;
     RECT  78.015 92.939 78.297 93.991 ;
     RECT  72.576 93.991 73.566 94.027 ;
     RECT  38.376 93.901 52.002 94.055 ;
     RECT  54.684 93.901 54.702 94.055 ;
     RECT  72.576 94.027 74.106 94.061 ;
     RECT  38.376 94.055 51.354 94.099 ;
     RECT  37.152 93.991 37.206 94.135 ;
     RECT  37.98 94.099 51.354 94.135 ;
     RECT  82.98 93.865 84.042 94.135 ;
     RECT  2.415 93.929 3.438 94.171 ;
     RECT  4.176 93.119 4.194 94.171 ;
     RECT  53.136 93.209 53.154 94.171 ;
     RECT  63.324 94.027 63.342 94.171 ;
     RECT  2.415 94.171 4.194 94.261 ;
     RECT  53.136 94.171 53.802 94.289 ;
     RECT  63.324 94.171 63.45 94.289 ;
     RECT  63.324 94.289 63.342 94.325 ;
     RECT  79.56 94.171 79.578 94.325 ;
     RECT  74.088 94.061 74.106 94.433 ;
     RECT  82.584 94.135 84.042 94.433 ;
     RECT  54.72 94.369 54.738 94.441 ;
     RECT  61.815 91.733 62.097 94.441 ;
     RECT  64.908 94.369 64.926 94.441 ;
     RECT  70.74 94.333 70.758 94.441 ;
     RECT  76.176 94.369 76.194 94.441 ;
     RECT  6.768 94.369 6.786 94.469 ;
     RECT  54.72 94.441 54.846 94.469 ;
     RECT  77.544 93.991 78.297 94.469 ;
     RECT  75.816 94.441 76.194 94.493 ;
     RECT  37.152 94.135 51.354 94.507 ;
     RECT  53.136 94.289 53.694 94.531 ;
     RECT  72.576 94.061 72.99 94.555 ;
     RECT  61.815 94.441 62.73 94.559 ;
     RECT  64.908 94.441 64.998 94.559 ;
     RECT  76.068 94.493 76.194 94.559 ;
     RECT  2.415 94.261 4.77 94.595 ;
     RECT  72 94.555 72.99 94.595 ;
     RECT  76.068 94.559 76.086 94.595 ;
     RECT  53.064 94.531 53.694 94.631 ;
     RECT  70.704 94.441 70.794 94.631 ;
     RECT  37.116 94.507 51.354 94.639 ;
     RECT  34.815 93.451 35.442 94.675 ;
     RECT  5.688 93.893 5.778 94.711 ;
     RECT  34.776 94.675 35.442 94.711 ;
     RECT  0.54 94.603 0.558 94.781 ;
     RECT  34.704 94.711 35.442 94.801 ;
     RECT  36.576 94.639 51.354 94.801 ;
     RECT  53.064 94.631 53.298 94.829 ;
     RECT  70.704 94.631 70.722 94.829 ;
     RECT  74.664 94.531 74.682 94.829 ;
     RECT  77.796 94.469 78.297 94.829 ;
     RECT  81.504 94.531 81.522 94.865 ;
     RECT  34.56 94.801 35.442 94.873 ;
     RECT  53.064 94.829 53.082 94.873 ;
     RECT  34.56 94.873 35.514 94.877 ;
     RECT  36.576 94.801 51.57 94.877 ;
     RECT  36.576 94.877 51.534 94.891 ;
     RECT  54.828 94.469 54.846 94.901 ;
     RECT  72.252 94.595 72.99 94.939 ;
     RECT  52.884 94.873 53.082 94.973 ;
     RECT  34.704 94.877 35.514 94.981 ;
     RECT  36.324 94.891 51.534 94.981 ;
     RECT  30.78 94.981 30.798 95.099 ;
     RECT  34.704 94.981 51.534 95.099 ;
     RECT  72.252 94.939 73.386 95.117 ;
     RECT  42.696 95.099 51.534 95.207 ;
     RECT  34.704 95.099 41.958 95.261 ;
     RECT  2.415 94.595 4.338 95.341 ;
     RECT  5.076 94.711 5.778 95.341 ;
     RECT  0.108 95.275 0.126 95.369 ;
     RECT  34.704 95.261 41.598 95.369 ;
     RECT  83.232 94.433 84.042 95.485 ;
     RECT  71.424 95.521 71.442 95.563 ;
     RECT  2.415 95.341 5.778 95.611 ;
     RECT  42.768 95.207 51.534 95.611 ;
     RECT  53.064 94.973 53.082 95.611 ;
     RECT  2.415 95.611 6.246 95.639 ;
     RECT  34.704 95.369 35.982 95.639 ;
     RECT  71.28 95.563 71.442 95.639 ;
     RECT  77.256 95.521 77.274 95.639 ;
     RECT  72.252 95.117 72.897 95.647 ;
     RECT  42.768 95.611 51.57 95.747 ;
     RECT  82.656 95.485 84.042 95.747 ;
     RECT  4.608 95.639 6.246 95.791 ;
     RECT  53.064 95.611 53.298 95.791 ;
     RECT  61.815 94.559 62.097 95.791 ;
     RECT  70.704 95.719 70.722 95.791 ;
     RECT  2.415 95.639 3.33 95.851 ;
     RECT  70.236 95.791 70.722 95.851 ;
     RECT  4.608 95.791 6.858 95.909 ;
     RECT  53.064 95.791 53.658 95.953 ;
     RECT  72.216 95.647 72.897 95.981 ;
     RECT  5.616 95.909 6.858 96.017 ;
     RECT  52.668 95.953 53.658 96.017 ;
     RECT  52.668 96.017 53.586 96.025 ;
     RECT  70.092 95.851 70.722 96.025 ;
     RECT  5.616 96.017 6.246 96.053 ;
     RECT  52.632 96.025 53.586 96.053 ;
     RECT  42.768 95.747 42.786 96.061 ;
     RECT  69.732 96.025 70.722 96.061 ;
     RECT  42.444 96.061 42.786 96.089 ;
     RECT  52.632 96.053 52.686 96.089 ;
     RECT  4.608 95.909 4.806 96.179 ;
     RECT  76.896 95.791 76.914 96.179 ;
     RECT  61.704 95.791 62.097 96.187 ;
     RECT  78.015 94.829 78.297 96.187 ;
     RECT  69.66 96.061 70.722 96.215 ;
     RECT  83.268 95.747 84.042 96.215 ;
     RECT  4.608 96.179 4.626 96.323 ;
     RECT  61.704 96.187 62.73 96.323 ;
     RECT  43.776 95.747 51.57 96.331 ;
     RECT  61.704 96.323 62.097 96.421 ;
     RECT  67.215 93.353 67.497 96.421 ;
     RECT  5.616 96.053 5.634 96.521 ;
     RECT  34.704 95.639 35.91 96.565 ;
     RECT  42.444 96.089 42.534 96.565 ;
     RECT  54.72 96.421 54.738 96.571 ;
     RECT  54.72 96.571 55.134 96.593 ;
     RECT  83.304 96.215 84.042 96.593 ;
     RECT  2.304 95.851 3.33 96.601 ;
     RECT  37.044 95.369 41.598 96.601 ;
     RECT  42.408 96.565 42.534 96.601 ;
     RECT  56.415 89.807 56.697 96.601 ;
     RECT  57.708 96.331 57.726 96.601 ;
     RECT  69.66 96.215 69.858 96.601 ;
     RECT  72.615 95.981 72.897 96.601 ;
     RECT  43.776 96.331 51.822 96.605 ;
     RECT  52.632 96.089 52.65 96.605 ;
     RECT  2.304 96.601 3.546 96.629 ;
     RECT  70.668 96.215 70.722 96.629 ;
     RECT  61.164 96.421 62.097 96.691 ;
     RECT  78.015 96.187 78.678 96.691 ;
     RECT  2.415 96.629 3.546 96.719 ;
     RECT  56.052 96.601 56.697 96.719 ;
     RECT  57.6 96.601 57.726 96.719 ;
     RECT  60.444 96.691 62.097 96.719 ;
     RECT  70.668 96.629 70.686 96.719 ;
     RECT  76.788 96.331 76.806 96.719 ;
     RECT  55.116 96.593 55.134 96.755 ;
     RECT  57.6 96.719 57.618 96.755 ;
     RECT  69.336 96.601 69.858 96.755 ;
     RECT  66.708 96.421 67.497 96.791 ;
     RECT  37.044 96.601 42.534 96.799 ;
     RECT  53.568 96.053 53.586 96.827 ;
     RECT  69.336 96.755 69.354 96.827 ;
     RECT  34.704 96.565 36.018 96.835 ;
     RECT  68.364 96.859 68.382 96.871 ;
     RECT  58.68 96.691 58.698 96.899 ;
     RECT  68.364 96.871 68.958 96.899 ;
     RECT  78.015 96.691 78.714 96.899 ;
     RECT  85.464 83.021 85.482 96.907 ;
     RECT  0.108 96.871 0.126 96.941 ;
     RECT  36.936 96.799 42.534 96.961 ;
     RECT  43.776 96.605 49.266 96.989 ;
     RECT  66.924 96.791 67.497 97.025 ;
     RECT  76.176 96.871 76.302 97.025 ;
     RECT  68.508 96.899 68.958 97.061 ;
     RECT  60.444 96.719 60.462 97.097 ;
     RECT  68.508 97.061 68.526 97.097 ;
     RECT  34.704 96.835 36.162 97.105 ;
     RECT  36.936 96.961 43.038 97.105 ;
     RECT  43.776 96.989 49.014 97.105 ;
     RECT  50.04 96.605 51.822 97.105 ;
     RECT  72.615 96.601 72.99 97.141 ;
     RECT  73.836 97.105 73.854 97.141 ;
     RECT  76.284 97.025 76.302 97.169 ;
     RECT  72.615 97.141 73.854 97.181 ;
     RECT  34.704 97.105 49.014 97.259 ;
     RECT  50.04 97.105 52.146 97.259 ;
     RECT  74.664 97.105 74.682 97.259 ;
     RECT  34.704 97.259 47.07 97.295 ;
     RECT  72.615 97.181 73.638 97.295 ;
     RECT  4.32 96.871 4.338 97.339 ;
     RECT  72.615 97.295 72.99 97.367 ;
     RECT  82.62 97.267 82.638 97.367 ;
     RECT  34.704 97.295 46.782 97.375 ;
     RECT  47.88 97.259 48.078 97.469 ;
     RECT  50.04 97.259 51.297 97.483 ;
     RECT  2.415 96.719 3.438 97.501 ;
     RECT  4.32 97.339 4.77 97.501 ;
     RECT  49.896 97.483 51.297 97.529 ;
     RECT  85.356 96.907 85.482 97.601 ;
     RECT  2.415 97.501 4.77 97.645 ;
     RECT  2.415 97.645 5.022 97.681 ;
     RECT  34.056 97.375 46.782 97.771 ;
     RECT  34.02 97.771 46.782 97.799 ;
     RECT  83.415 96.593 84.042 97.807 ;
     RECT  2.415 97.681 5.166 97.835 ;
     RECT  5.94 97.681 5.958 97.835 ;
     RECT  34.02 97.799 45.897 97.843 ;
     RECT  3.42 97.835 5.166 97.907 ;
     RECT  46.764 97.799 46.782 97.943 ;
     RECT  75.24 97.951 76.374 97.997 ;
     RECT  2.415 97.835 2.697 98.011 ;
     RECT  6.948 98.041 6.966 98.059 ;
     RECT  79.524 97.771 79.542 98.069 ;
     RECT  3.42 97.907 5.022 98.093 ;
     RECT  6.408 98.059 6.966 98.105 ;
     RECT  59.796 97.807 59.814 98.105 ;
     RECT  82.764 97.807 84.042 98.105 ;
     RECT  33.948 97.843 45.897 98.141 ;
     RECT  76.356 97.997 76.374 98.141 ;
     RECT  6.948 98.105 6.966 98.149 ;
     RECT  7.815 15.593 8.097 98.149 ;
     RECT  33.948 98.141 43.794 98.185 ;
     RECT  58.716 98.113 58.734 98.213 ;
     RECT  6.948 98.149 8.097 98.249 ;
     RECT  30.78 98.149 30.798 98.249 ;
     RECT  49.896 97.529 49.914 98.347 ;
     RECT  50.796 97.529 51.297 98.347 ;
     RECT  61.815 96.719 62.097 98.347 ;
     RECT  33.876 98.185 43.794 98.375 ;
     RECT  83.232 98.105 84.042 98.447 ;
     RECT  49.896 98.347 51.297 98.483 ;
     RECT  49.896 98.483 50.202 98.519 ;
     RECT  2.376 98.011 2.697 98.539 ;
     RECT  2.304 98.539 2.697 98.609 ;
     RECT  61.815 98.347 62.262 98.609 ;
     RECT  74.268 98.491 74.286 98.617 ;
     RECT  75.24 97.997 75.402 98.617 ;
     RECT  78.015 96.899 78.297 98.617 ;
     RECT  49.896 98.519 49.914 98.621 ;
     RECT  6.948 98.249 7.074 98.645 ;
     RECT  61.815 98.609 62.154 98.645 ;
     RECT  2.415 98.609 2.697 98.689 ;
     RECT  3.42 98.093 4.302 98.689 ;
     RECT  78.015 98.617 78.354 98.761 ;
     RECT  34.02 98.375 43.794 98.789 ;
     RECT  74.268 98.617 75.402 98.851 ;
     RECT  7.056 98.645 7.074 98.879 ;
     RECT  44.712 98.141 44.73 98.879 ;
     RECT  83.415 98.447 84.042 98.879 ;
     RECT  74.268 98.851 75.438 98.887 ;
     RECT  48.744 98.761 48.762 98.915 ;
     RECT  42.408 98.789 43.794 98.923 ;
     RECT  47.484 98.059 47.502 98.923 ;
     RECT  60.84 98.851 60.858 98.923 ;
     RECT  2.415 98.689 4.302 98.959 ;
     RECT  74.232 98.887 75.438 98.995 ;
     RECT  60.156 98.923 60.858 99.031 ;
     RECT  73.692 98.995 75.438 99.031 ;
     RECT  78.015 98.761 78.858 99.031 ;
     RECT  2.415 98.959 4.734 99.059 ;
     RECT  46.764 98.923 47.502 99.059 ;
     RECT  34.02 98.789 41.562 99.121 ;
     RECT  2.415 99.059 3.33 99.149 ;
     RECT  49.716 98.923 49.734 99.149 ;
     RECT  60.012 99.031 60.858 99.149 ;
     RECT  73.62 99.031 75.438 99.149 ;
     RECT  45.615 98.141 45.897 99.157 ;
     RECT  72.615 97.367 72.897 99.157 ;
     RECT  73.62 99.149 75.222 99.157 ;
     RECT  72.252 99.157 75.222 99.185 ;
     RECT  78.015 99.031 79.002 99.185 ;
     RECT  33.948 99.121 41.562 99.197 ;
     RECT  47.484 99.059 47.502 99.197 ;
     RECT  33.948 99.197 35.586 99.211 ;
     RECT  45.615 99.157 45.954 99.265 ;
     RECT  33.84 99.211 35.586 99.301 ;
     RECT  45.468 99.265 45.954 99.301 ;
     RECT  72.252 99.185 74.574 99.329 ;
     RECT  36.504 99.197 41.562 99.419 ;
     RECT  42.408 98.923 43.902 99.419 ;
     RECT  60.012 99.149 60.174 99.419 ;
     RECT  72.615 99.329 74.574 99.419 ;
     RECT  83.415 98.879 83.898 99.427 ;
     RECT  33.804 99.301 35.586 99.455 ;
     RECT  36.684 99.419 41.562 99.455 ;
     RECT  45.468 99.301 46.206 99.455 ;
     RECT  60.012 99.419 60.03 99.455 ;
     RECT  33.84 99.455 35.586 99.491 ;
     RECT  45.468 99.455 45.897 99.499 ;
     RECT  33.948 99.491 35.586 99.527 ;
     RECT  73.728 99.419 74.574 99.563 ;
     RECT  4.5 99.059 4.554 99.599 ;
     RECT  45.324 99.499 45.897 99.599 ;
     RECT  0.108 98.971 0.126 99.629 ;
     RECT  37.26 99.455 41.562 99.661 ;
     RECT  5.868 99.157 5.886 99.689 ;
     RECT  34.056 99.527 35.586 99.689 ;
     RECT  37.26 99.661 41.634 99.733 ;
     RECT  42.408 99.419 43.794 99.733 ;
     RECT  6.804 99.733 6.822 99.841 ;
     RECT  78.015 99.185 78.354 99.931 ;
     RECT  4.5 99.599 4.518 99.959 ;
     RECT  6.012 99.841 6.822 99.959 ;
     RECT  34.38 99.689 35.586 100.003 ;
     RECT  71.1 99.739 71.118 100.003 ;
     RECT  37.26 99.733 43.794 100.067 ;
     RECT  83.376 99.427 83.898 100.067 ;
     RECT  34.38 100.003 35.946 100.103 ;
     RECT  37.296 100.067 43.794 100.103 ;
     RECT  73.728 99.563 74.07 100.109 ;
     RECT  34.704 100.103 35.946 100.229 ;
     RECT  44.676 100.111 44.694 100.229 ;
     RECT  59.004 99.931 59.022 100.229 ;
     RECT  73.728 100.109 73.746 100.229 ;
     RECT  78.015 99.931 78.534 100.229 ;
     RECT  34.704 100.229 35.622 100.265 ;
     RECT  70.704 100.003 71.118 100.265 ;
     RECT  6.012 99.959 6.03 100.301 ;
     RECT  75.024 100.111 75.042 100.301 ;
     RECT  78.015 100.229 78.297 100.471 ;
     RECT  71.172 100.459 71.838 100.499 ;
     RECT  82.44 100.111 82.458 100.507 ;
     RECT  37.404 100.103 43.794 100.543 ;
     RECT  34.704 100.265 35.586 100.607 ;
     RECT  2.415 99.149 2.697 100.651 ;
     RECT  82.44 100.507 82.674 100.651 ;
     RECT  83.415 100.067 83.898 100.651 ;
     RECT  82.404 100.651 82.674 100.679 ;
     RECT  2.304 100.651 2.754 100.733 ;
     RECT  36.504 100.651 36.522 100.769 ;
     RECT  37.404 100.543 44.226 100.769 ;
     RECT  48.564 100.651 48.582 100.769 ;
     RECT  77.328 100.471 78.297 100.769 ;
     RECT  37.404 100.769 44.118 100.805 ;
     RECT  37.404 100.805 43.938 100.843 ;
     RECT  2.415 100.733 2.754 100.849 ;
     RECT  4.104 100.741 4.122 100.849 ;
     RECT  82.404 100.679 82.422 100.877 ;
     RECT  72.615 99.419 72.897 100.891 ;
     RECT  3.924 100.849 4.122 100.921 ;
     RECT  47.592 100.84 47.61 100.921 ;
     RECT  71.172 100.499 71.19 100.949 ;
     RECT  3.924 100.921 4.194 101.035 ;
     RECT  47.592 100.921 47.79 101.039 ;
     RECT  83.415 100.651 84.042 101.039 ;
     RECT  59.544 100.777 59.562 101.075 ;
     RECT  51.015 98.483 51.297 101.119 ;
     RECT  3.924 101.035 4.482 101.191 ;
     RECT  45.615 99.599 45.897 101.191 ;
     RECT  47.592 101.039 47.646 101.191 ;
     RECT  45.615 101.191 46.278 101.275 ;
     RECT  47.016 101.191 47.646 101.275 ;
     RECT  72.615 100.891 73.494 101.281 ;
     RECT  50.544 101.119 51.297 101.309 ;
     RECT  36.72 100.843 43.938 101.315 ;
     RECT  83.415 101.039 83.898 101.317 ;
     RECT  49.608 101.275 49.626 101.345 ;
     RECT  2.415 100.849 2.826 101.461 ;
     RECT  3.924 101.191 4.986 101.461 ;
     RECT  72.615 101.281 74.106 101.461 ;
     RECT  2.415 101.461 4.986 101.551 ;
     RECT  49.752 101.425 49.77 101.579 ;
     RECT  77.544 100.769 78.297 101.579 ;
     RECT  60.876 101.317 60.894 101.615 ;
     RECT  37.044 101.315 43.938 101.651 ;
     RECT  72.615 101.461 74.754 101.651 ;
     RECT  83.376 101.317 83.898 101.687 ;
     RECT  81.504 101.461 81.522 101.723 ;
     RECT  2.415 101.551 5.418 101.755 ;
     RECT  6.84 101.623 6.858 101.759 ;
     RECT  37.332 101.651 43.938 101.759 ;
     RECT  45.615 101.275 47.646 101.821 ;
     RECT  37.404 101.759 43.938 101.849 ;
     RECT  74.592 101.651 74.754 101.849 ;
     RECT  45.504 101.821 47.646 101.851 ;
     RECT  78.015 101.579 78.297 101.857 ;
     RECT  74.592 101.849 74.682 101.885 ;
     RECT  82.332 101.731 82.35 101.885 ;
     RECT  78.015 101.857 78.606 101.929 ;
     RECT  37.404 101.849 43.902 101.957 ;
     RECT  45.324 101.851 47.646 101.965 ;
     RECT  45.324 101.965 47.682 102.001 ;
     RECT  78.015 101.929 78.786 102.119 ;
     RECT  59.58 101.857 59.598 102.155 ;
     RECT  72.615 101.651 73.566 102.155 ;
     RECT  74.664 101.885 74.682 102.191 ;
     RECT  54.72 102.127 54.738 102.227 ;
     RECT  45 102.001 47.79 102.263 ;
     RECT  82.62 102.091 82.638 102.263 ;
     RECT  58.788 102.163 58.806 102.299 ;
     RECT  70.704 102.199 70.722 102.299 ;
     RECT  2.412 101.755 5.418 102.331 ;
     RECT  34.704 100.607 35.478 102.389 ;
     RECT  45.504 102.263 47.79 102.605 ;
     RECT  31.932 102.505 31.95 102.659 ;
     RECT  46.728 102.605 47.79 102.659 ;
     RECT  47.556 102.659 47.79 102.695 ;
     RECT  2.304 102.331 5.418 102.731 ;
     RECT  83.415 101.687 83.898 102.739 ;
     RECT  47.592 102.695 47.79 102.811 ;
     RECT  2.304 102.731 4.986 102.839 ;
     RECT  6.804 102.703 6.822 102.839 ;
     RECT  79.092 102.631 79.218 102.965 ;
     RECT  85.464 97.601 85.482 102.965 ;
     RECT  76.464 102.811 76.482 103.001 ;
     RECT  60.3 102.937 60.318 103.009 ;
     RECT  75.528 102.775 75.546 103.009 ;
     RECT  83.376 102.739 83.898 103.009 ;
     RECT  47.592 102.811 47.862 103.045 ;
     RECT  37.404 101.957 43.686 103.081 ;
     RECT  75.456 103.009 75.546 103.081 ;
     RECT  75.456 103.081 76.194 103.109 ;
     RECT  47.592 103.045 48.294 103.171 ;
     RECT  51.015 101.309 51.297 103.171 ;
     RECT  78.015 102.119 78.297 103.171 ;
     RECT  74.52 102.901 74.538 103.195 ;
     RECT  34.815 102.389 35.478 103.199 ;
     RECT  60.3 103.009 60.426 103.199 ;
     RECT  75.528 103.109 76.194 103.229 ;
     RECT  60.3 103.199 60.318 103.235 ;
     RECT  47.592 103.171 48.654 103.28 ;
     RECT  48.132 103.28 48.654 103.315 ;
     RECT  2.415 102.839 4.986 103.343 ;
     RECT  34.815 103.199 35.442 103.343 ;
     RECT  34.815 103.343 35.406 103.351 ;
     RECT  45.504 102.605 45.897 103.351 ;
     RECT  46.728 102.659 46.782 103.351 ;
     RECT  50.796 103.171 51.297 103.351 ;
     RECT  61.815 98.645 62.097 103.351 ;
     RECT  74.52 103.195 74.61 103.351 ;
     RECT  48.132 103.315 49.77 103.373 ;
     RECT  74.052 103.351 74.61 103.373 ;
     RECT  34.776 103.351 35.406 103.469 ;
     RECT  48.132 103.373 49.194 103.469 ;
     RECT  74.052 103.373 74.07 103.469 ;
     RECT  78.015 103.171 78.786 103.469 ;
     RECT  61.815 103.351 62.226 103.477 ;
     RECT  45.18 103.351 46.782 103.505 ;
     RECT  48.132 103.469 48.15 103.505 ;
     RECT  70.704 103.279 70.722 103.505 ;
     RECT  46.764 103.505 46.782 103.541 ;
     RECT  50.724 103.351 51.297 103.541 ;
     RECT  61.815 103.477 62.73 103.577 ;
     RECT  2.415 103.343 4.914 103.585 ;
     RECT  49.068 103.469 49.194 103.613 ;
     RECT  82.62 103.513 82.638 103.613 ;
     RECT  45.18 103.505 45.897 103.649 ;
     RECT  78.015 103.469 78.678 103.649 ;
     RECT  2.34 103.585 4.914 103.739 ;
     RECT  75.564 103.229 76.194 103.739 ;
     RECT  83.376 103.009 84.042 103.747 ;
     RECT  2.415 103.739 4.914 103.775 ;
     RECT  85.356 103.387 85.374 103.811 ;
     RECT  0.54 103.621 0.558 103.949 ;
     RECT  79.524 103.513 79.542 104.009 ;
     RECT  76.932 103.891 76.95 104.153 ;
     RECT  3.96 103.775 4.914 104.161 ;
     RECT  37.404 103.081 43.794 104.161 ;
     RECT  60.624 103.981 60.642 104.279 ;
     RECT  36.432 104.251 36.45 104.287 ;
     RECT  37.224 104.161 43.974 104.287 ;
     RECT  49.068 103.613 49.086 104.299 ;
     RECT  36.432 104.287 43.974 104.315 ;
     RECT  75.348 104.125 75.366 104.315 ;
     RECT  45.504 103.649 45.897 104.333 ;
     RECT  61.815 103.577 62.097 104.431 ;
     RECT  2.415 103.775 3.006 104.521 ;
     RECT  3.96 104.161 5.022 104.521 ;
     RECT  78.015 103.649 78.297 104.521 ;
     RECT  34.815 103.469 35.406 104.557 ;
     RECT  48.528 104.299 49.086 104.585 ;
     RECT  2.415 104.521 5.13 104.621 ;
     RECT  49.032 104.585 49.086 104.657 ;
     RECT  61.38 104.431 62.097 104.701 ;
     RECT  73.944 104.665 73.962 104.701 ;
     RECT  78.015 104.521 78.426 104.701 ;
     RECT  82.692 103.747 84.042 104.701 ;
     RECT  2.415 104.621 3.906 104.729 ;
     RECT  36.972 104.315 43.974 104.729 ;
     RECT  49.068 104.657 49.086 104.729 ;
     RECT  72.615 102.155 72.897 104.791 ;
     RECT  73.62 104.701 74.286 104.791 ;
     RECT  4.68 104.621 5.13 104.819 ;
     RECT  34.776 104.557 35.406 104.819 ;
     RECT  82.656 104.701 84.042 104.819 ;
     RECT  72.615 104.791 74.286 104.821 ;
     RECT  70.704 104.629 70.722 104.827 ;
     RECT  2.415 104.729 3.618 104.855 ;
     RECT  61.272 104.701 62.097 104.855 ;
     RECT  72.396 104.821 74.286 104.855 ;
     RECT  78.015 104.701 78.678 104.855 ;
     RECT  72.396 104.855 73.962 104.861 ;
     RECT  72.615 104.861 73.566 104.891 ;
     RECT  82.656 104.819 82.674 104.891 ;
     RECT  37.008 104.729 43.974 104.971 ;
     RECT  47.052 104.299 47.07 104.971 ;
     RECT  50.04 104.557 50.058 104.971 ;
     RECT  51.015 103.541 51.297 104.971 ;
     RECT  59.58 104.863 59.598 104.971 ;
     RECT  0.108 104.791 0.126 105.053 ;
     RECT  47.052 104.971 47.25 105.061 ;
     RECT  46.728 105.061 47.25 105.089 ;
     RECT  59.58 104.971 59.742 105.089 ;
     RECT  71.82 104.863 71.838 105.089 ;
     RECT  76.392 104.863 76.41 105.089 ;
     RECT  2.415 104.855 3.546 105.097 ;
     RECT  59.58 105.089 59.598 105.125 ;
     RECT  85.464 103.915 85.482 105.125 ;
     RECT  72.615 104.891 73.35 105.161 ;
     RECT  70.704 104.827 70.758 105.169 ;
     RECT  37.008 104.971 44.262 105.205 ;
     RECT  81.504 104.971 81.522 105.233 ;
     RECT  37.008 105.205 44.622 105.241 ;
     RECT  45.615 104.333 45.897 105.241 ;
     RECT  70.452 105.169 70.758 105.241 ;
     RECT  48.024 104.971 48.042 105.269 ;
     RECT  31.464 102.775 31.482 105.359 ;
     RECT  34.815 104.819 35.406 105.359 ;
     RECT  37.008 105.241 45.897 105.359 ;
     RECT  46.728 105.089 46.746 105.359 ;
     RECT  70.344 105.241 70.758 105.359 ;
     RECT  44.424 105.359 44.442 105.395 ;
     RECT  69.12 105.241 69.138 105.395 ;
     RECT  70.344 105.359 70.362 105.395 ;
     RECT  71.676 105.241 71.694 105.395 ;
     RECT  83.415 104.819 84.042 105.395 ;
     RECT  2.34 105.097 3.546 105.431 ;
     RECT  37.008 105.359 41.166 105.431 ;
     RECT  31.14 105.367 31.158 105.485 ;
     RECT  84.996 105.169 85.014 105.581 ;
     RECT  7.815 98.249 8.097 105.587 ;
     RECT  13.215 64.397 13.497 105.587 ;
     RECT  18.615 2.413 18.897 105.587 ;
     RECT  24.015 63.689 24.297 105.587 ;
     RECT  29.415 93.245 29.697 105.587 ;
     RECT  45.615 105.359 45.897 105.587 ;
     RECT  50.04 104.971 51.297 105.587 ;
     RECT  56.415 96.719 56.697 105.587 ;
     RECT  61.815 104.855 62.097 105.587 ;
     RECT  67.215 97.025 67.497 105.587 ;
     RECT  72.615 105.161 72.897 105.587 ;
     RECT  78.015 104.855 78.297 105.587 ;
     RECT  2.376 105.431 3.546 105.629 ;
     RECT  34.815 105.359 35.262 105.629 ;
     RECT  37.008 105.431 38.034 105.629 ;
     RECT  38.772 105.431 41.166 105.629 ;
     RECT  41.976 105.359 43.506 105.629 ;
     RECT  75.816 105.331 75.834 105.629 ;
     RECT  83.415 105.395 83.862 105.629 ;
     RECT  50.04 105.587 51.105 105.637 ;
     RECT  37.008 105.629 37.89 105.665 ;
     RECT  39.924 105.629 41.022 105.665 ;
     RECT  42.48 105.629 43.506 105.665 ;
     RECT  83.415 105.629 83.754 105.665 ;
     RECT  42.768 105.665 43.47 105.701 ;
     RECT  43.452 105.701 43.47 105.737 ;
     RECT  3.528 105.629 3.546 105.773 ;
     RECT  37.008 105.665 37.026 105.773 ;
     RECT  82.44 105.511 82.458 105.773 ;
     RECT  49.932 105.637 51.105 105.809 ;
     RECT  2.415 105.629 2.505 105.857 ;
     RECT  7.815 105.587 7.905 105.857 ;
     RECT  13.215 105.587 13.305 105.857 ;
     RECT  18.615 105.587 18.705 105.857 ;
     RECT  24.015 105.587 24.105 105.857 ;
     RECT  29.415 105.587 29.505 105.857 ;
     RECT  34.815 105.629 35.154 105.857 ;
     RECT  40.215 105.665 40.305 105.857 ;
     RECT  45.615 105.587 45.705 105.857 ;
     RECT  50.364 105.809 51.105 105.857 ;
     RECT  56.415 105.587 56.505 105.857 ;
     RECT  61.815 105.587 61.905 105.857 ;
     RECT  67.215 105.587 67.305 105.857 ;
     RECT  72.615 105.587 72.705 105.857 ;
     RECT  78.015 105.587 78.105 105.857 ;
     RECT  83.415 105.665 83.505 105.857 ;
     RECT  35.136 105.857 35.154 105.965 ;
     RECT  50.364 105.857 50.382 107.885 ;
    LAYER M4 ;
     RECT  0.06 2.4 0.137 105.576 ;
     RECT  0.137 45.6 0.173 51.576 ;
     RECT  0.137 5.568 0.533 14.856 ;
     RECT  0.137 20.928 0.533 32.664 ;
     RECT  0.137 65.04 0.533 82.344 ;
     RECT  0.533 5.568 0.569 14.328 ;
     RECT  0.533 20.928 0.569 32.136 ;
     RECT  0.137 42.912 0.569 44.568 ;
     RECT  0.173 48.864 0.569 51.576 ;
     RECT  0.137 53.712 0.569 55.368 ;
     RECT  0.137 63.456 0.569 63.912 ;
     RECT  0.533 65.04 0.569 66.168 ;
     RECT  0.533 67.2 0.569 82.344 ;
     RECT  0.137 83.424 0.569 85.08 ;
     RECT  0.137 93.696 0.569 94.776 ;
     RECT  0.137 100.176 0.569 104.52 ;
     RECT  0.569 104.496 2.245 104.52 ;
     RECT  0.137 105.552 2.245 105.576 ;
     RECT  0.137 4.56 2.293 4.584 ;
     RECT  0.569 5.568 2.293 8.376 ;
     RECT  0.137 33.744 2.365 38.616 ;
     RECT  0.137 39.696 2.365 41.88 ;
     RECT  0.569 76.512 2.365 82.344 ;
     RECT  0.569 83.424 2.365 83.976 ;
     RECT  0.137 2.4 2.408 3 ;
     RECT  2.293 4.56 2.408 8.376 ;
     RECT  0.569 9.552 2.408 12.168 ;
     RECT  0.569 13.2 2.408 13.896 ;
     RECT  0.137 15.936 2.408 19.704 ;
     RECT  0.569 20.928 2.408 31.608 ;
     RECT  2.365 33.744 2.408 42.216 ;
     RECT  0.569 43.44 2.408 44.568 ;
     RECT  0.173 45.6 2.408 47.784 ;
     RECT  0.569 49.392 2.408 49.416 ;
     RECT  0.569 50.592 2.408 51.576 ;
     RECT  0.137 52.656 2.408 52.68 ;
     RECT  0.569 54.24 2.408 55.368 ;
     RECT  0.137 56.4 2.408 62.376 ;
     RECT  0.569 63.888 2.408 63.912 ;
     RECT  0.569 65.04 2.408 65.064 ;
     RECT  0.569 67.2 2.408 72.648 ;
     RECT  0.569 73.68 2.408 73.704 ;
     RECT  0.569 74.88 2.408 75.336 ;
     RECT  2.365 76.512 2.408 83.976 ;
     RECT  0.137 86.112 2.408 86.76 ;
     RECT  0.137 87.744 2.408 92.712 ;
     RECT  0.569 93.696 2.408 94.248 ;
     RECT  0.137 95.856 2.408 96.408 ;
     RECT  0.137 97.44 2.408 99 ;
     RECT  0.569 100.176 2.408 103.416 ;
     RECT  2.245 104.496 2.408 105.576 ;
     RECT  2.408 2.148 2.512 105.852 ;
     RECT  2.512 2.4 2.513 105.582 ;
     RECT  2.513 2.418 2.704 105.582 ;
     RECT  2.704 4.08 2.819 7.896 ;
     RECT  2.704 92.592 2.873 92.712 ;
     RECT  2.819 6.816 2.915 7.896 ;
     RECT  2.915 7.056 2.917 7.896 ;
     RECT  2.819 4.08 2.945 4.584 ;
     RECT  2.704 13.872 2.945 13.992 ;
     RECT  2.945 4.08 2.963 4.104 ;
     RECT  2.819 5.568 3.017 5.64 ;
     RECT  2.704 103.728 3.017 104.904 ;
     RECT  2.704 2.832 3.089 2.952 ;
     RECT  2.704 74.544 3.269 76.536 ;
     RECT  2.704 20.544 3.305 21.096 ;
     RECT  2.704 9.552 3.377 10.728 ;
     RECT  2.704 29.664 3.443 31.944 ;
     RECT  2.704 50.112 3.443 51.384 ;
     RECT  2.704 55.248 3.443 56.472 ;
     RECT  3.443 30.864 3.449 31.944 ;
     RECT  2.704 42.192 3.449 42.216 ;
     RECT  2.704 83.04 3.449 83.064 ;
     RECT  3.377 10.032 3.485 10.728 ;
     RECT  3.443 50.112 3.485 50.568 ;
     RECT  3.089 2.928 3.521 2.952 ;
     RECT  2.704 89.856 3.593 91.224 ;
     RECT  2.704 59.184 3.635 59.832 ;
     RECT  2.704 60.96 3.635 62.04 ;
     RECT  2.704 77.52 3.665 78.648 ;
     RECT  2.704 26.064 3.683 27.816 ;
     RECT  3.269 74.544 3.683 75.672 ;
     RECT  2.704 44.976 3.685 45 ;
     RECT  2.704 46.416 3.685 46.632 ;
     RECT  3.683 26.064 3.697 27.192 ;
     RECT  2.704 37.584 3.697 37.608 ;
     RECT  2.704 39.072 3.697 39.096 ;
     RECT  2.704 72.96 3.697 72.984 ;
     RECT  2.873 92.592 3.697 92.616 ;
     RECT  3.683 75.648 3.701 75.672 ;
     RECT  3.665 77.52 3.701 77.928 ;
     RECT  3.685 44.976 3.731 47.592 ;
     RECT  2.704 33.648 3.733 34.344 ;
     RECT  2.704 85.104 3.733 85.128 ;
     RECT  3.635 60.96 3.737 60.984 ;
     RECT  3.635 62.016 3.737 62.04 ;
     RECT  3.685 53.52 3.772 53.544 ;
     RECT  3.731 45.552 3.773 47.592 ;
     RECT  3.733 84.912 3.773 85.128 ;
     RECT  3.733 33.6 3.779 34.344 ;
     RECT  3.593 89.856 3.781 90.648 ;
     RECT  2.704 22.512 3.809 22.824 ;
     RECT  3.695 35.808 3.836 35.832 ;
     RECT  2.704 101.184 3.841 101.592 ;
     RECT  2.704 102.624 3.841 102.648 ;
     RECT  2.704 24.576 3.884 24.696 ;
     RECT  3.635 59.184 3.913 59.208 ;
     RECT  3.836 35.808 3.923 36.168 ;
     RECT  3.697 37.584 3.923 39.096 ;
     RECT  3.884 24.096 3.925 24.696 ;
     RECT  3.697 25.968 3.925 27.192 ;
     RECT  2.704 66.144 3.925 66.168 ;
     RECT  3.683 74.544 3.925 74.568 ;
     RECT  2.704 63.744 3.949 64.44 ;
     RECT  2.917 7.056 3.96 7.752 ;
     RECT  2.704 94.656 3.961 94.68 ;
     RECT  3.877 40.176 3.964 40.2 ;
     RECT  3.925 24.096 3.971 27.192 ;
     RECT  3.923 37.584 3.971 38.568 ;
     RECT  3.805 49.008 3.971 49.032 ;
     RECT  3.925 65.664 3.971 66.168 ;
     RECT  3.697 72 3.971 72.984 ;
     RECT  3.925 74.016 3.971 74.568 ;
     RECT  2.704 11.952 3.973 11.976 ;
     RECT  2.945 13.968 3.973 13.992 ;
     RECT  2.704 15.312 3.973 15.336 ;
     RECT  3.841 101.184 3.98 102.648 ;
     RECT  2.704 98.448 3.985 99 ;
     RECT  3.949 63.648 3.989 64.44 ;
     RECT  3.973 13.968 4.019 15.336 ;
     RECT  2.704 16.512 4.021 16.536 ;
     RECT  3.98 101.04 4.021 102.648 ;
     RECT  3.485 10.032 4.025 10.584 ;
     RECT  3.971 25.44 4.025 27.192 ;
     RECT  3.449 30.96 4.025 31.944 ;
     RECT  3.877 41.616 4.025 42.072 ;
     RECT  3.443 55.584 4.025 56.472 ;
     RECT  3.985 98.064 4.025 99 ;
     RECT  3.973 54.528 4.06 54.552 ;
     RECT  3.017 103.728 4.097 104.616 ;
     RECT  2.704 86.736 4.117 86.76 ;
     RECT  2.704 87.792 4.117 87.816 ;
     RECT  3.781 89.856 4.117 90.024 ;
     RECT  2.704 95.664 4.124 95.688 ;
     RECT  3.96 6.816 4.133 7.752 ;
     RECT  3.973 11.952 4.133 12.936 ;
     RECT  4.117 86.736 4.163 87.816 ;
     RECT  4.117 89.28 4.163 90.024 ;
     RECT  3.697 92.448 4.165 92.616 ;
     RECT  4.025 31.92 4.169 31.944 ;
     RECT  3.971 74.016 4.205 74.04 ;
     RECT  4.163 89.28 4.205 89.976 ;
     RECT  4.021 100.272 4.205 102.648 ;
     RECT  4.205 100.272 4.211 102.072 ;
     RECT  2.704 18.24 4.22 18.456 ;
     RECT  3.017 5.568 4.241 5.592 ;
     RECT  4.097 104.592 4.241 104.616 ;
     RECT  4.22 18.24 4.307 19.128 ;
     RECT  3.773 84.912 4.307 84.936 ;
     RECT  4.165 92.448 4.307 93.48 ;
     RECT  3.701 77.904 4.313 77.928 ;
     RECT  4.133 6.816 4.349 7.416 ;
     RECT  3.773 46.416 4.349 47.592 ;
     RECT  4.021 16.512 4.381 16.584 ;
     RECT  3.809 22.8 4.385 22.824 ;
     RECT  3.485 50.544 4.385 50.568 ;
     RECT  2.704 70.032 4.385 70.056 ;
     RECT  4.381 16.512 4.421 17.112 ;
     RECT  4.307 18.24 4.421 18.264 ;
     RECT  3.913 58.656 4.457 59.208 ;
     RECT  2.704 52.464 4.493 52.488 ;
     RECT  4.211 100.272 4.493 101.592 ;
     RECT  3.779 33.6 4.529 34.104 ;
     RECT  3.971 37.584 4.529 37.608 ;
     RECT  3.971 72 4.547 72.36 ;
     RECT  4.124 95.184 4.556 95.688 ;
     RECT  3.305 20.736 4.565 21.096 ;
     RECT  4.025 25.44 4.565 26.28 ;
     RECT  2.704 81.168 4.565 81.48 ;
     RECT  4.501 70.416 4.588 70.44 ;
     RECT  4.556 95.184 4.643 96.312 ;
     RECT  4.565 25.44 4.709 25.464 ;
     RECT  3.971 65.664 4.709 65.688 ;
     RECT  3.443 29.664 4.745 29.688 ;
     RECT  4.547 72.336 4.745 72.36 ;
     RECT  4.025 55.584 4.817 55.608 ;
     RECT  4.349 47.568 4.925 47.592 ;
     RECT  4.205 89.856 4.961 89.88 ;
     RECT  4.349 46.416 5.069 46.44 ;
     RECT  4.993 43.92 5.077 43.944 ;
     RECT  4.025 10.56 5.125 10.584 ;
     RECT  3.989 63.648 5.137 64.392 ;
     RECT  3.923 35.808 5.141 35.832 ;
     RECT  4.457 58.656 5.141 58.68 ;
     RECT  5.125 9.744 5.171 10.824 ;
     RECT  4.025 42.048 5.177 42.072 ;
     RECT  4.163 86.736 5.213 87.72 ;
     RECT  5.171 10.8 5.249 10.824 ;
     RECT  4.133 12.528 5.285 12.552 ;
     RECT  4.565 20.736 5.393 20.76 ;
     RECT  4.565 81.264 5.537 81.48 ;
     RECT  5.537 81.264 5.555 81.288 ;
     RECT  4.349 6.816 5.569 7.08 ;
     RECT  4.643 95.664 5.573 95.688 ;
     RECT  5.569 6.768 5.605 7.08 ;
     RECT  5.461 5.328 5.651 5.352 ;
     RECT  5.605 6.768 5.651 7.896 ;
     RECT  5.651 6.768 5.653 6.84 ;
     RECT  5.213 87.696 5.681 87.72 ;
     RECT  5.509 78.48 5.825 78.504 ;
     RECT  4.493 100.272 6.041 100.296 ;
     RECT  4.421 17.088 6.113 17.112 ;
     RECT  5.171 9.744 6.421 9.768 ;
     RECT  4.025 98.064 6.437 98.088 ;
     RECT  6.421 9.216 6.467 9.768 ;
     RECT  5.651 7.872 6.501 7.896 ;
     RECT  5.653 6.816 7.808 6.84 ;
     RECT  6.467 9.216 7.808 9.336 ;
     RECT  4.019 14.496 7.808 14.52 ;
     RECT  4.529 34.08 7.808 34.104 ;
     RECT  4.525 56.736 7.808 56.76 ;
     RECT  5.137 63.504 7.808 64.392 ;
     RECT  4.307 92.448 7.808 93.24 ;
     RECT  7.808 2.148 7.912 105.852 ;
     RECT  7.912 2.418 8.104 105.582 ;
     RECT  8.104 9.312 8.633 9.336 ;
     RECT  8.104 56.736 12.764 56.76 ;
     RECT  8.104 6.816 13.208 6.84 ;
     RECT  8.104 34.08 13.208 34.104 ;
     RECT  12.764 56.4 13.208 56.76 ;
     RECT  8.104 63.504 13.208 64.392 ;
     RECT  12.757 70.8 13.208 70.824 ;
     RECT  8.104 92.448 13.208 93.24 ;
     RECT  13.208 2.148 13.312 105.852 ;
     RECT  13.312 2.418 13.504 105.582 ;
     RECT  13.504 6.816 18.608 6.84 ;
     RECT  13.504 34.08 18.608 34.104 ;
     RECT  13.504 56.208 18.608 56.232 ;
     RECT  13.504 63.504 18.608 63.672 ;
     RECT  13.504 70.8 18.608 70.824 ;
     RECT  13.504 92.448 18.608 93.24 ;
     RECT  18.608 2.148 18.712 105.852 ;
     RECT  18.712 2.418 18.904 105.582 ;
     RECT  18.904 6.816 24.008 6.84 ;
     RECT  18.904 34.08 24.008 34.104 ;
     RECT  18.904 56.208 24.008 56.232 ;
     RECT  18.904 63.504 24.008 63.672 ;
     RECT  18.904 70.8 24.008 70.824 ;
     RECT  18.904 92.448 24.008 93.24 ;
     RECT  24.008 2.148 24.112 105.852 ;
     RECT  24.112 2.418 24.304 105.582 ;
     RECT  24.304 70.8 26.593 70.824 ;
     RECT  26.593 70.8 28.181 71.16 ;
     RECT  28.181 71.088 28.259 71.16 ;
     RECT  24.304 34.08 28.645 34.104 ;
     RECT  24.304 6.816 29.408 6.84 ;
     RECT  28.645 33.888 29.408 34.104 ;
     RECT  24.304 56.208 29.408 56.232 ;
     RECT  24.304 63.504 29.408 63.672 ;
     RECT  28.259 71.088 29.408 71.112 ;
     RECT  28.213 74.688 29.408 74.712 ;
     RECT  24.304 92.448 29.408 93.24 ;
     RECT  29.408 2.148 29.512 105.852 ;
     RECT  29.512 2.418 29.704 105.582 ;
     RECT  29.704 33.888 30.769 34.104 ;
     RECT  29.704 74.688 30.769 74.712 ;
     RECT  30.769 74.688 30.809 74.856 ;
     RECT  30.757 106.56 30.899 106.68 ;
     RECT  30.757 107.856 30.899 107.88 ;
     RECT  30.853 105.456 31.169 105.48 ;
     RECT  34.009 97.872 34.045 97.896 ;
     RECT  34.549 42.48 34.585 42.504 ;
     RECT  33.829 99.216 34.585 99.24 ;
     RECT  34.045 97.536 34.657 97.896 ;
     RECT  34.585 99.216 34.657 99.528 ;
     RECT  30.769 33.792 34.765 34.104 ;
     RECT  29.704 56.208 34.765 56.232 ;
     RECT  29.704 6.816 34.808 6.84 ;
     RECT  34.765 33.648 34.808 34.104 ;
     RECT  34.549 40.944 34.808 40.968 ;
     RECT  34.585 42.48 34.808 42.744 ;
     RECT  34.765 56.064 34.808 56.232 ;
     RECT  29.704 63.504 34.808 63.672 ;
     RECT  29.704 71.088 34.808 71.112 ;
     RECT  30.809 74.832 34.808 74.856 ;
     RECT  29.704 92.448 34.808 93.24 ;
     RECT  34.549 94.848 34.808 94.872 ;
     RECT  34.657 97.536 34.808 99.528 ;
     RECT  34.808 2.148 34.912 105.852 ;
     RECT  34.912 2.418 35.077 105.852 ;
     RECT  35.077 2.418 35.104 105.96 ;
     RECT  35.104 105.936 35.165 105.96 ;
     RECT  35.104 45.504 35.219 46.2 ;
     RECT  35.104 96.912 35.273 99.24 ;
     RECT  35.104 40.464 35.381 40.968 ;
     RECT  35.273 96.912 35.561 99.192 ;
     RECT  35.561 96.912 35.669 97.56 ;
     RECT  35.669 97.536 35.795 97.56 ;
     RECT  35.104 94.848 35.836 95.256 ;
     RECT  35.104 10.752 35.885 10.92 ;
     RECT  35.885 10.8 35.939 10.92 ;
     RECT  35.104 6.768 35.957 7.896 ;
     RECT  35.957 7.872 36.181 7.896 ;
     RECT  35.957 6.768 36.241 6.84 ;
     RECT  36.181 7.872 36.268 8.472 ;
     RECT  35.104 14.16 36.317 15.624 ;
     RECT  35.104 12.048 36.38 13.08 ;
     RECT  36.317 14.16 36.38 14.232 ;
     RECT  35.219 46.176 36.421 46.2 ;
     RECT  35.104 42.144 36.457 43.896 ;
     RECT  36.38 12.048 36.467 14.232 ;
     RECT  36.467 14.16 36.533 14.232 ;
     RECT  35.104 100.848 36.709 100.872 ;
     RECT  36.709 100.848 36.749 101.304 ;
     RECT  36.457 41.616 36.785 43.896 ;
     RECT  35.104 4.416 36.889 4.92 ;
     RECT  35.104 56.064 36.889 56.088 ;
     RECT  36.889 4.416 36.925 5.4 ;
     RECT  36.241 6.384 36.925 6.84 ;
     RECT  36.785 41.616 36.929 42.168 ;
     RECT  36.889 55.728 36.929 56.088 ;
     RECT  35.104 18.24 36.961 18.264 ;
     RECT  36.929 55.728 36.961 55.896 ;
     RECT  35.104 71.088 36.961 71.112 ;
     RECT  35.104 77.712 36.997 77.736 ;
     RECT  36.421 104.256 36.997 104.28 ;
     RECT  35.104 9.648 37.001 9.672 ;
     RECT  36.961 18.24 37.001 18.792 ;
     RECT  36.925 4.08 37.033 6.84 ;
     RECT  36.268 7.872 37.033 7.896 ;
     RECT  35.939 10.896 37.052 10.92 ;
     RECT  36.997 103.728 37.081 104.904 ;
     RECT  35.104 92.448 37.093 93.24 ;
     RECT  35.836 94.848 37.093 94.92 ;
     RECT  36.467 12.048 37.109 13.08 ;
     RECT  35.104 74.304 37.109 74.856 ;
     RECT  37.093 92.448 37.139 93.48 ;
     RECT  36.929 41.808 37.145 42.168 ;
     RECT  35.104 63.504 37.177 63.672 ;
     RECT  37.093 94.512 37.18 94.92 ;
     RECT  37.237 79.248 37.244 79.272 ;
     RECT  36.317 15.6 37.289 15.624 ;
     RECT  37.244 79.248 37.325 79.608 ;
     RECT  37.325 79.584 37.331 79.608 ;
     RECT  37.18 94.656 37.381 94.92 ;
     RECT  36.997 76.992 37.393 77.736 ;
     RECT  36.749 101.28 37.393 101.304 ;
     RECT  37.109 12.384 37.397 13.08 ;
     RECT  37.381 94.656 37.427 95.928 ;
     RECT  37.081 103.728 37.433 104.616 ;
     RECT  36.961 70.656 37.501 71.112 ;
     RECT  35.561 99.168 37.525 99.192 ;
     RECT  37.001 18.768 37.58 18.792 ;
     RECT  36.421 46.176 37.609 46.728 ;
     RECT  37.109 74.64 37.609 74.856 ;
     RECT  37.525 99.168 37.612 100.248 ;
     RECT  37.427 94.896 37.613 95.928 ;
     RECT  37.033 4.08 37.619 7.896 ;
     RECT  37.619 4.08 37.621 4.44 ;
     RECT  37.321 31.776 37.621 31.8 ;
     RECT  35.104 33.456 37.621 34.104 ;
     RECT  37.612 100.224 37.621 100.248 ;
     RECT  36.533 14.16 37.628 14.184 ;
     RECT  36.785 43.296 37.649 43.896 ;
     RECT  37.609 46.176 37.649 47.064 ;
     RECT  35.381 40.464 37.653 40.488 ;
     RECT  37.58 18.768 37.667 19.608 ;
     RECT  37.621 31.344 37.667 31.8 ;
     RECT  37.052 10.272 37.669 10.92 ;
     RECT  37.653 39.6 37.669 40.488 ;
     RECT  37.621 37.248 37.676 37.272 ;
     RECT  37.621 33.456 37.708 35.448 ;
     RECT  37.628 14.16 37.715 15.144 ;
     RECT  37.669 19.632 37.717 20.04 ;
     RECT  37.708 33.456 37.717 34.776 ;
     RECT  37.676 37.008 37.717 37.272 ;
     RECT  37.619 5.424 37.721 6.312 ;
     RECT  37.393 76.992 37.721 78.12 ;
     RECT  37.715 14.16 37.757 14.856 ;
     RECT  37.669 38.736 37.757 40.488 ;
     RECT  37.717 37.008 37.763 37.608 ;
     RECT  37.717 19.632 37.789 20.568 ;
     RECT  37.721 76.992 37.801 77.544 ;
     RECT  37.501 65.904 37.825 65.928 ;
     RECT  36.961 67.248 37.825 67.272 ;
     RECT  36.349 2.64 37.897 2.664 ;
     RECT  37.621 3.696 37.897 4.44 ;
     RECT  37.763 37.584 37.897 37.608 ;
     RECT  37.033 58.08 37.933 58.104 ;
     RECT  36.961 80.784 37.933 80.808 ;
     RECT  37.897 2.64 37.973 4.44 ;
     RECT  37.145 42.144 37.973 42.168 ;
     RECT  37.649 46.32 38.005 47.064 ;
     RECT  37.613 95.136 38.009 95.928 ;
     RECT  37.393 101.28 38.009 102.12 ;
     RECT  36.961 55.296 38.045 55.896 ;
     RECT  38.045 55.824 38.077 55.896 ;
     RECT  37.789 19.632 38.099 21.432 ;
     RECT  37.177 63.504 38.108 63.864 ;
     RECT  37.973 2.64 38.117 3.384 ;
     RECT  37.619 7.344 38.117 7.896 ;
     RECT  37.397 12.576 38.149 13.08 ;
     RECT  37.285 60.864 38.149 60.888 ;
     RECT  37.717 73.488 38.149 73.512 ;
     RECT  38.108 63.504 38.195 64.776 ;
     RECT  37.501 69.984 38.195 71.112 ;
     RECT  38.149 73.248 38.195 73.512 ;
     RECT  37.933 80.352 38.197 80.808 ;
     RECT  38.149 60.816 38.221 60.888 ;
     RECT  38.009 101.376 38.221 102.12 ;
     RECT  38.197 80.352 38.243 81.768 ;
     RECT  38.149 83.376 38.243 83.4 ;
     RECT  38.149 22.752 38.257 22.776 ;
     RECT  38.185 85.488 38.269 85.512 ;
     RECT  37.433 104.256 38.293 104.616 ;
     RECT  37.825 65.904 38.297 67.272 ;
     RECT  37.801 76.992 38.297 77.496 ;
     RECT  38.195 69.984 38.329 70.68 ;
     RECT  38.257 22.512 38.339 22.776 ;
     RECT  38.252 24.432 38.339 24.456 ;
     RECT  37.069 98.016 38.369 98.04 ;
     RECT  37.612 99.168 38.369 99.192 ;
     RECT  38.297 76.992 38.441 77.4 ;
     RECT  38.149 12.576 38.477 13.32 ;
     RECT  38.195 73.248 38.485 73.272 ;
     RECT  38.293 26.016 38.549 26.04 ;
     RECT  37.609 74.64 38.577 75.288 ;
     RECT  37.721 5.424 38.581 6.12 ;
     RECT  37.139 93.456 38.581 93.48 ;
     RECT  38.441 77.232 38.585 77.4 ;
     RECT  37.649 43.296 38.621 43.32 ;
     RECT  38.329 69.36 38.627 70.68 ;
     RECT  38.581 71.856 38.639 71.88 ;
     RECT  38.485 72.912 38.639 73.272 ;
     RECT  38.629 48.864 38.653 48.888 ;
     RECT  38.221 60.816 38.653 60.936 ;
     RECT  38.636 88.896 38.677 88.92 ;
     RECT  38.617 51.12 38.684 51.24 ;
     RECT  38.297 66.816 38.693 67.272 ;
     RECT  38.627 70.656 38.723 70.68 ;
     RECT  38.509 86.832 38.723 86.856 ;
     RECT  38.677 88.224 38.723 88.92 ;
     RECT  37.669 10.272 38.725 11.16 ;
     RECT  37.717 33.264 38.729 34.776 ;
     RECT  38.221 101.376 38.729 102.552 ;
     RECT  38.653 48.864 38.737 48.984 ;
     RECT  37.933 57.6 38.761 58.104 ;
     RECT  37.139 92.448 38.761 92.472 ;
     RECT  38.581 93.456 38.761 94.632 ;
     RECT  37.757 14.832 38.771 14.856 ;
     RECT  38.684 51.12 38.771 52.056 ;
     RECT  38.077 55.824 38.773 56.28 ;
     RECT  38.761 59.76 38.773 59.784 ;
     RECT  38.693 67.248 38.773 67.272 ;
     RECT  38.577 74.832 38.773 75.288 ;
     RECT  37.667 31.344 38.797 31.368 ;
     RECT  38.761 57.456 38.797 58.104 ;
     RECT  38.477 12.576 38.801 13.08 ;
     RECT  38.005 46.32 38.801 47.832 ;
     RECT  38.761 92.448 38.801 94.632 ;
     RECT  38.773 74.832 38.819 76.056 ;
     RECT  38.585 77.376 38.819 77.4 ;
     RECT  38.773 67.248 38.821 67.848 ;
     RECT  38.581 5.28 38.837 6.12 ;
     RECT  38.099 21.168 38.837 21.432 ;
     RECT  38.773 55.824 38.837 56.424 ;
     RECT  38.639 71.856 38.837 73.272 ;
     RECT  38.195 63.504 38.845 64.584 ;
     RECT  38.627 69.36 38.867 69.384 ;
     RECT  38.837 55.872 38.873 56.424 ;
     RECT  38.819 76.032 38.873 76.056 ;
     RECT  38.729 101.856 38.873 102.552 ;
     RECT  38.873 55.872 38.909 55.896 ;
     RECT  38.821 67.248 38.915 68.28 ;
     RECT  38.773 59.232 38.937 59.784 ;
     RECT  38.117 3.072 38.941 3.384 ;
     RECT  38.117 7.344 38.945 7.368 ;
     RECT  38.245 30.192 38.945 30.216 ;
     RECT  38.729 34.752 38.945 34.776 ;
     RECT  37.897 37.584 38.945 38.04 ;
     RECT  38.293 104.256 38.945 104.808 ;
     RECT  38.653 60.816 38.981 61.608 ;
     RECT  38.773 65.616 39.017 65.64 ;
     RECT  38.725 53.568 39.049 54.12 ;
     RECT  37.757 39.6 39.053 39.624 ;
     RECT  38.945 104.496 39.085 104.808 ;
     RECT  38.801 13.056 39.089 13.08 ;
     RECT  38.937 59.76 39.089 59.784 ;
     RECT  38.801 92.448 39.089 94.104 ;
     RECT  38.797 31.248 39.121 31.368 ;
     RECT  38.725 9.936 39.125 11.16 ;
     RECT  38.945 37.584 39.125 37.608 ;
     RECT  38.981 60.816 39.161 60.936 ;
     RECT  38.723 88.224 39.161 88.248 ;
     RECT  39.121 31.248 39.197 32.184 ;
     RECT  38.873 102.192 39.229 102.552 ;
     RECT  39.197 32.16 39.233 32.184 ;
     RECT  38.797 57.456 39.233 58.152 ;
     RECT  38.941 3.072 39.265 3.624 ;
     RECT  39.049 44.688 39.308 44.712 ;
     RECT  38.801 46.32 39.308 47.064 ;
     RECT  38.869 84.72 39.337 84.744 ;
     RECT  39.193 97.008 39.337 97.032 ;
     RECT  39.337 97.008 39.409 97.56 ;
     RECT  38.339 22.512 39.481 22.536 ;
     RECT  39.481 21.792 39.517 22.536 ;
     RECT  38.833 23.712 39.517 23.832 ;
     RECT  38.915 67.392 39.517 68.28 ;
     RECT  38.837 72.384 39.553 73.272 ;
     RECT  39.481 50.112 39.589 50.136 ;
     RECT  38.509 82.848 39.589 82.872 ;
     RECT  38.099 19.632 39.661 20.04 ;
     RECT  38.729 33.264 39.661 33.624 ;
     RECT  39.229 102.192 39.661 102.648 ;
     RECT  39.589 25.2 39.697 25.224 ;
     RECT  39.625 42.528 39.697 42.552 ;
     RECT  39.125 10.752 39.733 11.16 ;
     RECT  39.049 53.136 39.733 54.12 ;
     RECT  38.819 74.832 39.733 75 ;
     RECT  38.243 80.64 39.733 81.768 ;
     RECT  39.589 82.848 39.733 83.208 ;
     RECT  39.085 104.496 39.769 105.24 ;
     RECT  39.589 50.112 39.805 50.664 ;
     RECT  39.733 53.136 39.805 54.696 ;
     RECT  39.697 42.48 39.829 42.552 ;
     RECT  39.553 72.384 39.829 73.32 ;
     RECT  39.733 74.688 39.836 75 ;
     RECT  38.009 95.904 39.841 95.928 ;
     RECT  39.409 96.912 39.841 97.56 ;
     RECT  39.661 16.368 39.877 16.392 ;
     RECT  39.836 74.688 39.877 75.576 ;
     RECT  39.517 77.52 39.877 77.544 ;
     RECT  39.841 95.904 39.877 97.56 ;
     RECT  39.661 33.024 39.949 33.624 ;
     RECT  39.265 2.832 39.973 3.624 ;
     RECT  39.877 95.904 39.985 98.184 ;
     RECT  39.553 40.848 40.021 40.872 ;
     RECT  39.733 80.64 40.031 83.208 ;
     RECT  39.349 43.68 40.057 43.704 ;
     RECT  39.308 44.688 40.057 47.064 ;
     RECT  39.517 21.792 40.069 23.88 ;
     RECT  39.697 25.104 40.069 25.224 ;
     RECT  39.733 10.752 40.093 11.784 ;
     RECT  40.057 14.4 40.093 14.424 ;
     RECT  39.661 19.248 40.093 20.04 ;
     RECT  39.337 84.72 40.129 85.56 ;
     RECT  39.985 95.76 40.165 98.184 ;
     RECT  39.805 53.136 40.201 55.272 ;
     RECT  39.973 2.832 40.208 4.104 ;
     RECT  38.837 5.424 40.208 6.12 ;
     RECT  40.093 9.792 40.208 11.784 ;
     RECT  40.093 13.68 40.208 14.424 ;
     RECT  39.877 16.272 40.208 16.392 ;
     RECT  39.409 18.144 40.208 18.168 ;
     RECT  40.093 19.248 40.208 20.136 ;
     RECT  40.069 21.792 40.208 23.928 ;
     RECT  40.069 25.056 40.208 25.224 ;
     RECT  40.049 27.936 40.208 27.96 ;
     RECT  39.445 30.96 40.208 30.984 ;
     RECT  39.949 33.024 40.208 33.672 ;
     RECT  39.301 38.736 40.208 38.76 ;
     RECT  40.021 40.608 40.208 41.16 ;
     RECT  39.829 42.336 40.208 42.552 ;
     RECT  40.057 43.68 40.208 47.064 ;
     RECT  39.445 48.384 40.208 48.408 ;
     RECT  39.805 50.112 40.208 50.76 ;
     RECT  40.201 52.752 40.208 55.272 ;
     RECT  39.877 56.784 40.208 56.808 ;
     RECT  39.805 58.416 40.208 58.44 ;
     RECT  39.161 60.816 40.208 60.84 ;
     RECT  38.845 63.504 40.208 63.816 ;
     RECT  39.769 64.992 40.208 65.016 ;
     RECT  39.877 66.048 40.208 66.072 ;
     RECT  39.517 67.392 40.208 68.952 ;
     RECT  39.788 70.8 40.208 70.824 ;
     RECT  39.829 72.144 40.208 73.32 ;
     RECT  39.877 74.688 40.208 77.544 ;
     RECT  39.229 78.624 40.208 78.648 ;
     RECT  40.031 79.824 40.208 83.208 ;
     RECT  40.129 84.72 40.208 86.52 ;
     RECT  39.769 90.624 40.208 90.648 ;
     RECT  39.089 92.448 40.208 94.056 ;
     RECT  40.165 95.472 40.208 98.184 ;
     RECT  39.349 100.848 40.208 100.872 ;
     RECT  39.661 102.192 40.208 103.224 ;
     RECT  39.769 104.496 40.208 105.384 ;
     RECT  40.208 2.148 40.312 105.852 ;
     RECT  40.312 2.418 40.504 105.582 ;
     RECT  40.504 81.168 40.565 81.192 ;
     RECT  40.504 44.736 40.601 45.288 ;
     RECT  40.504 7.392 40.637 8.232 ;
     RECT  40.504 18.144 40.643 18.168 ;
     RECT  40.504 33.024 40.643 34.344 ;
     RECT  40.504 9.504 40.673 9.912 ;
     RECT  40.643 34.32 40.781 34.344 ;
     RECT  40.504 38.16 40.781 43.128 ;
     RECT  40.601 44.736 40.781 44.952 ;
     RECT  40.504 92.16 40.889 100.296 ;
     RECT  40.504 104.64 40.889 105.384 ;
     RECT  40.504 76.896 40.925 77.16 ;
     RECT  40.504 13.056 40.997 16.392 ;
     RECT  40.504 56.784 41.027 57.048 ;
     RECT  40.504 58.08 41.027 58.68 ;
     RECT  40.504 5.04 41.069 6.312 ;
     RECT  40.504 11.136 41.069 11.832 ;
     RECT  40.781 38.16 41.069 40.488 ;
     RECT  40.504 67.392 41.069 69 ;
     RECT  40.504 78.528 41.069 78.648 ;
     RECT  40.504 82.176 41.069 83.256 ;
     RECT  40.504 84.96 41.069 85.512 ;
     RECT  40.889 95.232 41.069 100.296 ;
     RECT  41.069 11.136 41.075 11.784 ;
     RECT  40.997 13.056 41.075 15.72 ;
     RECT  40.504 48.384 41.075 50.76 ;
     RECT  40.504 30.96 41.105 31.896 ;
     RECT  41.069 82.176 41.105 82.872 ;
     RECT  41.075 48.384 41.116 50.424 ;
     RECT  40.504 19.248 41.141 20.136 ;
     RECT  40.504 47.04 41.141 47.064 ;
     RECT  40.504 79.824 41.141 79.848 ;
     RECT  40.504 3.408 41.213 3.864 ;
     RECT  40.925 76.896 41.213 77.112 ;
     RECT  40.504 60.816 41.249 63.816 ;
     RECT  41.213 77.088 41.249 77.112 ;
     RECT  41.069 5.472 41.285 6.312 ;
     RECT  40.504 21.12 41.321 21.816 ;
     RECT  41.027 57.024 41.321 57.048 ;
     RECT  41.069 78.576 41.357 78.648 ;
     RECT  41.075 14.112 41.429 15.72 ;
     RECT  40.504 72.48 41.429 75.192 ;
     RECT  41.069 95.232 41.429 98.52 ;
     RECT  40.637 7.392 41.459 7.992 ;
     RECT  41.141 19.248 41.459 20.04 ;
     RECT  41.429 14.112 41.465 14.808 ;
     RECT  41.116 48.384 41.465 49.224 ;
     RECT  41.429 95.232 41.465 96.6 ;
     RECT  40.673 9.504 41.5 9.528 ;
     RECT  41.459 19.968 41.5 20.04 ;
     RECT  40.504 70.848 41.533 70.872 ;
     RECT  40.889 104.64 41.564 105.24 ;
     RECT  40.504 66.048 41.569 66.072 ;
     RECT  41.069 67.968 41.605 69 ;
     RECT  41.533 69.984 41.605 70.872 ;
     RECT  41.069 84.96 41.605 84.984 ;
     RECT  40.504 102.192 41.605 102.264 ;
     RECT  41.564 104.16 41.605 105.24 ;
     RECT  41.249 60.96 41.609 63.816 ;
     RECT  41.213 3.408 41.645 3.432 ;
     RECT  41.429 72.48 41.645 74.712 ;
     RECT  41.605 84.864 41.645 84.984 ;
     RECT  41.429 97.584 41.651 98.52 ;
     RECT  41.605 102.192 41.651 105.24 ;
     RECT  41.459 7.392 41.681 7.416 ;
     RECT  40.643 33.024 41.713 33.288 ;
     RECT  41.465 14.112 41.717 14.376 ;
     RECT  41.605 67.968 41.753 70.872 ;
     RECT  41.069 99.744 41.753 100.296 ;
     RECT  41.651 102.192 41.789 103.224 ;
     RECT  41.285 6.288 41.861 6.312 ;
     RECT  41.717 14.352 41.861 14.376 ;
     RECT  40.504 37.056 41.893 37.08 ;
     RECT  41.357 78.624 41.893 78.648 ;
     RECT  41.105 31.872 41.897 31.896 ;
     RECT  41.609 61.872 41.897 63.816 ;
     RECT  41.645 72.72 41.933 74.712 ;
     RECT  41.713 33.024 41.965 33.624 ;
     RECT  40.504 23.904 42.001 23.928 ;
     RECT  40.889 92.16 42.035 94.056 ;
     RECT  40.781 44.928 42.037 44.952 ;
     RECT  40.504 89.424 42.037 89.496 ;
     RECT  41.929 90.912 42.037 90.936 ;
     RECT  41.651 104.4 42.037 105.24 ;
     RECT  40.504 25.632 42.073 26.28 ;
     RECT  42.037 104.4 42.077 105.432 ;
     RECT  41.645 84.864 42.083 84.888 ;
     RECT  41.069 39.072 42.101 40.488 ;
     RECT  41.753 67.968 42.109 70.056 ;
     RECT  42.037 89.424 42.124 90.936 ;
     RECT  41.116 50.4 42.133 50.424 ;
     RECT  40.504 52.032 42.133 52.056 ;
     RECT  40.781 41.76 42.145 43.128 ;
     RECT  42.133 50.4 42.179 52.44 ;
     RECT  40.504 53.568 42.181 54.696 ;
     RECT  40.504 55.776 42.181 55.8 ;
     RECT  41.893 37.056 42.217 37.608 ;
     RECT  42.101 38.736 42.217 40.488 ;
     RECT  42.179 50.4 42.22 51.24 ;
     RECT  42.109 67.536 42.22 70.056 ;
     RECT  42.124 89.424 42.221 89.448 ;
     RECT  41.897 63.504 42.236 63.816 ;
     RECT  41.569 65.136 42.236 66.072 ;
     RECT  42.037 44.928 42.253 45.72 ;
     RECT  42.217 37.056 42.284 40.488 ;
     RECT  41.789 102.192 42.289 102.888 ;
     RECT  41.027 58.656 42.293 58.68 ;
     RECT  42.284 36.48 42.325 40.488 ;
     RECT  42.145 41.664 42.325 43.128 ;
     RECT  42.124 90.624 42.325 90.936 ;
     RECT  42.035 92.16 42.325 92.472 ;
     RECT  42.181 53.568 42.329 55.8 ;
     RECT  42.236 63.504 42.361 66.072 ;
     RECT  42.22 67.536 42.361 69 ;
     RECT  41.893 78.624 42.361 78.984 ;
     RECT  41.929 80.352 42.361 80.376 ;
     RECT  42.361 63.504 42.364 69 ;
     RECT  42.22 69.984 42.365 70.056 ;
     RECT  42.325 90.624 42.365 92.472 ;
     RECT  42.325 36.48 42.371 43.128 ;
     RECT  41.965 33.024 42.373 34.152 ;
     RECT  41.465 96.576 42.437 96.6 ;
     RECT  41.753 99.744 42.509 99.768 ;
     RECT  41.465 48.384 42.545 49.032 ;
     RECT  42.545 48.384 42.577 48.936 ;
     RECT  42.073 25.632 42.613 26.904 ;
     RECT  40.504 27.888 42.613 27.912 ;
     RECT  41.713 86.64 42.613 86.664 ;
     RECT  42.289 101.904 42.613 102.888 ;
     RECT  42.253 44.928 42.649 46.392 ;
     RECT  42.577 47.856 42.649 48.936 ;
     RECT  42.613 25.632 42.653 27.912 ;
     RECT  42.035 93.792 42.653 94.056 ;
     RECT  41.321 21.12 42.685 21.144 ;
     RECT  42.329 53.568 42.685 55.272 ;
     RECT  41.105 82.608 42.685 82.872 ;
     RECT  41.5 20.016 42.721 20.04 ;
     RECT  41.897 61.872 42.721 62.04 ;
     RECT  42.685 21.12 42.724 21.672 ;
     RECT  42.325 35.328 42.725 35.352 ;
     RECT  42.613 85.776 42.725 86.664 ;
     RECT  42.613 101.376 42.725 102.888 ;
     RECT  42.001 23.424 42.757 23.928 ;
     RECT  42.361 78.432 42.757 78.984 ;
     RECT  42.685 82.608 42.757 83.784 ;
     RECT  41.948 88.32 42.757 88.344 ;
     RECT  42.365 91.872 42.761 92.472 ;
     RECT  42.077 104.4 42.761 104.424 ;
     RECT  41.075 11.136 42.793 11.16 ;
     RECT  42.649 47.568 42.797 48.936 ;
     RECT  42.721 61.44 42.797 62.04 ;
     RECT  42.757 23.424 42.829 24.456 ;
     RECT  42.725 86.64 42.833 86.664 ;
     RECT  42.077 105.408 42.833 105.432 ;
     RECT  42.721 19.536 42.865 20.04 ;
     RECT  42.829 30.912 42.865 30.936 ;
     RECT  42.685 31.92 42.865 31.944 ;
     RECT  42.371 37.344 42.901 43.128 ;
     RECT  42.649 44.736 42.901 46.392 ;
     RECT  42.757 87.888 42.901 88.344 ;
     RECT  42.901 37.344 42.905 46.392 ;
     RECT  42.797 47.568 42.941 47.88 ;
     RECT  42.905 42.96 42.947 46.392 ;
     RECT  42.793 10.704 42.973 11.16 ;
     RECT  42.829 22.752 42.973 24.456 ;
     RECT  42.373 33.024 42.973 34.344 ;
     RECT  42.364 63.504 43.009 64.92 ;
     RECT  42.757 78.384 43.009 78.984 ;
     RECT  42.364 66.048 43.013 69 ;
     RECT  42.865 30.912 43.045 31.944 ;
     RECT  42.973 33.024 43.045 34.824 ;
     RECT  42.947 46.224 43.045 46.392 ;
     RECT  42.724 21.072 43.049 21.672 ;
     RECT  42.653 94.032 43.049 94.056 ;
     RECT  43.045 30.912 43.085 34.824 ;
     RECT  43.049 21.552 43.121 21.672 ;
     RECT  43.121 21.648 43.153 21.672 ;
     RECT  42.973 22.752 43.153 24.504 ;
     RECT  41.933 73.008 43.153 74.712 ;
     RECT  41.651 97.584 43.153 98.088 ;
     RECT  42.721 99.216 43.153 99.24 ;
     RECT  42.865 19.008 43.157 20.04 ;
     RECT  43.153 97.584 43.193 99.24 ;
     RECT  42.757 82.608 43.225 84.024 ;
     RECT  43.193 97.584 43.229 97.608 ;
     RECT  42.685 53.52 43.235 55.272 ;
     RECT  43.085 30.912 43.261 34.2 ;
     RECT  42.253 60.384 43.261 60.408 ;
     RECT  42.797 61.44 43.261 61.992 ;
     RECT  42.797 48.912 43.265 48.936 ;
     RECT  43.013 66.048 43.265 68.904 ;
     RECT  43.225 82.608 43.265 84.984 ;
     RECT  42.696 15.984 43.285 16.008 ;
     RECT  42.22 50.4 43.285 50.616 ;
     RECT  42.179 52.416 43.285 52.44 ;
     RECT  42.905 37.344 43.301 41.976 ;
     RECT  43.045 46.224 43.301 46.728 ;
     RECT  42.941 47.808 43.301 47.88 ;
     RECT  43.285 15.84 43.331 16.008 ;
     RECT  43.265 82.608 43.333 83.256 ;
     RECT  43.285 50.4 43.372 52.44 ;
     RECT  43.235 53.52 43.373 53.544 ;
     RECT  43.261 60.384 43.373 61.992 ;
     RECT  43.193 98.592 43.373 99.24 ;
     RECT  43.265 66.048 43.409 66.84 ;
     RECT  43.009 77.952 43.409 78.984 ;
     RECT  42.901 87.888 43.409 88.776 ;
     RECT  43.153 21.648 43.481 24.504 ;
     RECT  43.373 61.44 43.517 61.992 ;
     RECT  42.725 101.424 43.553 102.888 ;
     RECT  43.373 99.216 43.573 99.24 ;
     RECT  43.481 22.56 43.585 24.504 ;
     RECT  42.653 25.632 43.585 27.768 ;
     RECT  40.504 28.896 43.585 28.92 ;
     RECT  43.261 30.096 43.585 34.2 ;
     RECT  42.901 57.408 43.585 57.432 ;
     RECT  43.009 63.216 43.619 64.92 ;
     RECT  43.553 101.424 43.619 102.648 ;
     RECT  43.301 40.464 43.625 41.976 ;
     RECT  43.409 66.048 43.625 66.792 ;
     RECT  42.973 10.704 43.657 11.976 ;
     RECT  43.301 37.344 43.657 39.048 ;
     RECT  43.235 54.864 43.657 55.272 ;
     RECT  43.585 56.448 43.657 57.432 ;
     RECT  43.657 37.008 43.669 39.048 ;
     RECT  43.373 60.384 43.669 60.408 ;
     RECT  42.947 43.296 43.697 44.856 ;
     RECT  42.365 90.624 43.697 90.648 ;
     RECT  43.669 36.528 43.715 39.048 ;
     RECT  43.669 60.288 43.715 60.408 ;
     RECT  42.253 71.232 43.729 71.256 ;
     RECT  43.585 28.896 43.733 34.2 ;
     RECT  43.625 66.72 43.733 66.792 ;
     RECT  43.619 101.664 43.733 101.88 ;
     RECT  43.517 61.92 43.765 61.992 ;
     RECT  43.619 63.216 43.765 63.816 ;
     RECT  43.153 72.72 43.765 74.712 ;
     RECT  43.405 76.032 43.765 76.056 ;
     RECT  43.729 71.04 43.769 71.256 ;
     RECT  43.573 99.216 43.769 100.152 ;
     RECT  43.657 10.464 43.801 11.976 ;
     RECT  41.075 13.056 43.801 13.08 ;
     RECT  43.409 77.952 43.805 78.888 ;
     RECT  42.361 80.352 43.805 80.808 ;
     RECT  43.157 19.536 43.837 20.04 ;
     RECT  42.365 70.032 43.837 70.056 ;
     RECT  43.769 71.04 43.837 71.064 ;
     RECT  43.765 72.528 43.837 76.056 ;
     RECT  43.801 94.08 43.837 94.104 ;
     RECT  41.465 95.232 43.837 95.256 ;
     RECT  43.801 10.464 43.848 13.08 ;
     RECT  43.621 14.304 43.848 14.328 ;
     RECT  43.733 29.232 43.859 34.2 ;
     RECT  43.848 10.464 43.873 14.328 ;
     RECT  43.409 87.936 43.873 88.776 ;
     RECT  43.301 47.808 43.877 47.832 ;
     RECT  43.769 99.216 43.877 99.24 ;
     RECT  43.859 32.352 43.9 33.048 ;
     RECT  43.873 10.464 43.909 14.856 ;
     RECT  43.625 40.464 43.913 41.112 ;
     RECT  43.909 9.648 43.955 14.856 ;
     RECT  43.333 81.84 43.955 83.256 ;
     RECT  43.955 11.952 43.957 14.856 ;
     RECT  43.372 50.4 43.981 50.616 ;
     RECT  43.657 54.864 43.981 57.432 ;
     RECT  43.265 84.96 43.981 84.984 ;
     RECT  42.761 92.448 43.981 92.472 ;
     RECT  43.955 9.648 43.996 9.672 ;
     RECT  43.981 54.864 44.021 57.624 ;
     RECT  43.372 51.936 44.089 52.44 ;
     RECT  43.585 22.56 44.129 27.768 ;
     RECT  43.837 94.08 44.233 95.256 ;
     RECT  43.765 61.92 44.237 63.816 ;
     RECT  43.715 36.528 44.243 38.664 ;
     RECT  43.697 43.872 44.269 44.856 ;
     RECT  43.301 46.608 44.269 46.728 ;
     RECT  43.837 72.432 44.269 76.056 ;
     RECT  43.981 84.96 44.269 85.128 ;
     RECT  43.297 104.976 44.273 105 ;
     RECT  44.269 46.512 44.309 46.728 ;
     RECT  43.957 11.952 44.381 13.944 ;
     RECT  44.233 94.08 44.435 95.736 ;
     RECT  44.269 5.424 44.437 5.448 ;
     RECT  44.269 72.432 44.437 76.728 ;
     RECT  43.805 77.952 44.437 78.648 ;
     RECT  44.269 43.872 44.453 45.144 ;
     RECT  44.389 97.536 44.476 97.56 ;
     RECT  43.265 68.112 44.485 68.904 ;
     RECT  43.837 70.032 44.485 71.064 ;
     RECT  43.805 80.448 44.485 80.808 ;
     RECT  43.955 81.84 44.485 81.864 ;
     RECT  44.129 22.56 44.489 25.704 ;
     RECT  43.859 29.232 44.489 31.272 ;
     RECT  44.485 68.112 44.525 71.064 ;
     RECT  43.733 66.768 44.533 66.792 ;
     RECT  44.525 68.112 44.533 69.576 ;
     RECT  44.129 26.688 44.561 27.768 ;
     RECT  44.243 36.528 44.593 36.552 ;
     RECT  43.837 19.536 44.597 20.568 ;
     RECT  44.525 71.04 44.597 71.064 ;
     RECT  44.489 30.72 44.633 31.272 ;
     RECT  44.435 94.08 44.633 95.256 ;
     RECT  43.981 49.872 44.665 50.616 ;
     RECT  44.089 51.936 44.665 53.016 ;
     RECT  44.597 20.016 44.701 20.568 ;
     RECT  43.945 17.328 44.737 17.352 ;
     RECT  44.701 19.008 44.737 19.032 ;
     RECT  44.489 29.232 44.737 29.256 ;
     RECT  44.533 66.768 44.737 69.576 ;
     RECT  44.197 86.64 44.809 86.664 ;
     RECT  43.873 87.936 44.809 88.968 ;
     RECT  44.243 37.776 44.845 38.664 ;
     RECT  43.913 40.464 44.845 40.488 ;
     RECT  43.981 91.872 44.845 92.472 ;
     RECT  44.269 84.672 44.881 85.128 ;
     RECT  44.881 84.672 44.917 85.176 ;
     RECT  43.225 7.488 44.924 7.512 ;
     RECT  43.331 15.84 44.953 15.864 ;
     RECT  43.859 34.08 44.953 34.2 ;
     RECT  44.809 86.64 44.953 88.968 ;
     RECT  43.873 90.048 44.953 90.408 ;
     RECT  44.437 72.432 44.981 78.648 ;
     RECT  44.489 22.56 44.989 23.88 ;
     RECT  44.237 63.504 45.013 63.816 ;
     RECT  43.619 64.896 45.013 64.92 ;
     RECT  44.953 15.456 45.025 15.864 ;
     RECT  44.701 20.016 45.061 20.904 ;
     RECT  44.989 47.856 45.133 47.88 ;
     RECT  45.133 47.856 45.205 47.976 ;
     RECT  44.453 43.872 45.241 43.896 ;
     RECT  44.845 91.872 45.241 92.52 ;
     RECT  44.485 80.448 45.277 81.864 ;
     RECT  44.633 94.08 45.277 94.104 ;
     RECT  45.241 91.872 45.301 92.712 ;
     RECT  45.277 93.84 45.301 94.104 ;
     RECT  43.9 33.024 45.349 33.048 ;
     RECT  44.953 34.08 45.349 34.968 ;
     RECT  44.021 54.864 45.349 56.472 ;
     RECT  44.021 57.6 45.349 57.624 ;
     RECT  44.917 84.624 45.349 85.176 ;
     RECT  44.953 86.208 45.349 88.968 ;
     RECT  44.953 90.048 45.349 90.648 ;
     RECT  44.309 46.512 45.385 46.536 ;
     RECT  45.205 47.856 45.385 48.648 ;
     RECT  44.453 45.12 45.452 45.144 ;
     RECT  45.385 46.512 45.452 48.648 ;
     RECT  44.965 9.696 45.457 9.72 ;
     RECT  43.955 10.704 45.457 10.728 ;
     RECT  44.989 22.224 45.493 23.88 ;
     RECT  44.489 25.296 45.493 25.704 ;
     RECT  45.061 20.016 45.529 20.952 ;
     RECT  45.493 22.224 45.529 25.704 ;
     RECT  44.437 4.512 45.608 5.448 ;
     RECT  44.924 7.488 45.608 8.472 ;
     RECT  45.457 9.696 45.608 10.728 ;
     RECT  44.381 11.952 45.608 13.56 ;
     RECT  45.025 15.456 45.608 16.296 ;
     RECT  44.737 17.328 45.608 19.032 ;
     RECT  45.529 20.016 45.608 25.704 ;
     RECT  44.561 26.688 45.608 27.192 ;
     RECT  44.737 28.56 45.608 29.256 ;
     RECT  44.633 30.72 45.608 30.888 ;
     RECT  45.349 33.024 45.608 34.968 ;
     RECT  44.593 36.048 45.608 36.552 ;
     RECT  44.845 37.776 45.608 40.488 ;
     RECT  43.945 42.432 45.608 42.744 ;
     RECT  45.241 43.824 45.608 43.896 ;
     RECT  45.452 45.12 45.608 48.648 ;
     RECT  44.665 49.872 45.608 53.016 ;
     RECT  45.349 54.864 45.608 57.624 ;
     RECT  44.665 59.184 45.608 59.208 ;
     RECT  43.715 60.288 45.608 60.312 ;
     RECT  44.237 61.92 45.608 61.992 ;
     RECT  45.013 63.504 45.608 64.92 ;
     RECT  44.737 66.72 45.608 69.576 ;
     RECT  44.981 72.432 45.608 79.272 ;
     RECT  45.277 80.352 45.608 81.864 ;
     RECT  43.955 83.232 45.608 83.256 ;
     RECT  45.349 84.624 45.608 90.648 ;
     RECT  45.301 91.872 45.608 94.104 ;
     RECT  44.633 95.136 45.608 95.256 ;
     RECT  44.989 96.24 45.608 96.264 ;
     RECT  43.733 101.856 45.608 101.88 ;
     RECT  45.493 104.304 45.608 104.328 ;
     RECT  45.608 2.148 45.712 105.852 ;
     RECT  45.712 2.418 45.904 105.582 ;
     RECT  45.904 20.4 45.929 20.952 ;
     RECT  45.904 4.512 46.001 4.536 ;
     RECT  45.904 17.664 46.001 18.84 ;
     RECT  45.904 74.304 46.001 78.648 ;
     RECT  45.904 83.232 46.109 87.912 ;
     RECT  45.904 88.944 46.109 91.08 ;
     RECT  45.904 27.168 46.115 27.384 ;
     RECT  45.904 57.072 46.145 59.208 ;
     RECT  45.904 64.896 46.145 64.92 ;
     RECT  46.001 74.304 46.163 78.072 ;
     RECT  46.001 17.664 46.217 18.792 ;
     RECT  45.904 30.72 46.253 37.08 ;
     RECT  46.163 74.304 46.253 75.528 ;
     RECT  46.163 76.944 46.253 78.072 ;
     RECT  45.904 23.568 46.289 25.32 ;
     RECT  46.109 89.472 46.289 91.08 ;
     RECT  45.904 66.72 46.361 67.08 ;
     RECT  46.145 57.072 46.397 58.728 ;
     RECT  45.904 60.288 46.577 63.816 ;
     RECT  45.904 68.16 46.577 68.76 ;
     RECT  45.904 102.576 46.595 103.272 ;
     RECT  45.904 92.448 46.685 95.16 ;
     RECT  45.904 13.968 46.693 16.68 ;
     RECT  45.904 70.368 46.721 71.016 ;
     RECT  46.109 83.76 46.739 87.912 ;
     RECT  45.904 100.848 46.739 101.304 ;
     RECT  46.693 15.696 46.757 16.68 ;
     RECT  46.217 17.664 46.757 18.024 ;
     RECT  45.904 10.176 46.787 10.968 ;
     RECT  45.929 20.4 46.787 20.904 ;
     RECT  45.904 42.72 46.793 42.744 ;
     RECT  46.685 92.448 46.865 94.92 ;
     RECT  46.787 10.752 46.883 10.968 ;
     RECT  45.904 50.16 46.892 50.28 ;
     RECT  46.787 20.592 46.897 20.904 ;
     RECT  45.904 22.176 46.897 22.536 ;
     RECT  45.904 47.712 46.933 48.264 ;
     RECT  46.892 49.344 46.933 50.28 ;
     RECT  46.739 84.96 46.937 87.912 ;
     RECT  46.885 67.152 46.972 67.176 ;
     RECT  46.883 10.752 46.973 10.776 ;
     RECT  46.933 47.712 46.979 50.28 ;
     RECT  46.757 15.84 47.045 16.68 ;
     RECT  45.904 51.36 47.069 55.128 ;
     RECT  45.904 104.304 47.081 104.328 ;
     RECT  45.904 46.224 47.084 46.728 ;
     RECT  46.979 47.712 47.084 48.456 ;
     RECT  45.904 96.336 47.149 96.36 ;
     RECT  45.904 28.512 47.153 29.304 ;
     RECT  47.069 51.264 47.153 55.128 ;
     RECT  45.904 43.872 47.171 44.472 ;
     RECT  47.084 46.224 47.171 48.456 ;
     RECT  46.253 30.72 47.173 36.552 ;
     RECT  47.171 46.224 47.18 46.92 ;
     RECT  46.115 27.312 47.185 27.384 ;
     RECT  46.979 50.16 47.185 50.28 ;
     RECT  45.904 80.352 47.185 81.864 ;
     RECT  46.937 84.96 47.225 87.576 ;
     RECT  46.397 57.072 47.257 58.104 ;
     RECT  47.173 30 47.26 36.552 ;
     RECT  46.577 68.352 47.261 68.76 ;
     RECT  47.18 45.696 47.267 46.92 ;
     RECT  46.577 60.288 47.269 61.8 ;
     RECT  46.577 63.168 47.269 63.816 ;
     RECT  46.289 89.472 47.293 89.88 ;
     RECT  46.253 74.304 47.297 74.856 ;
     RECT  46.933 39.312 47.315 39.336 ;
     RECT  47.185 42.672 47.315 42.696 ;
     RECT  47.269 63.168 47.315 64.392 ;
     RECT  47.113 65.664 47.315 65.688 ;
     RECT  47.257 56.976 47.341 58.104 ;
     RECT  47.269 59.424 47.356 61.8 ;
     RECT  46.721 70.992 47.363 71.016 ;
     RECT  45.904 12.816 47.365 12.84 ;
     RECT  47.045 15.984 47.369 16.68 ;
     RECT  47.153 28.512 47.369 28.536 ;
     RECT  47.356 60.288 47.369 61.8 ;
     RECT  47.185 80.352 47.369 82.68 ;
     RECT  46.739 83.76 47.369 83.784 ;
     RECT  47.153 52.176 47.405 55.128 ;
     RECT  47.341 57.264 47.405 58.104 ;
     RECT  46.757 17.664 47.437 17.688 ;
     RECT  47.185 26.592 47.441 27.384 ;
     RECT  45.904 99.168 47.473 99.192 ;
     RECT  47.171 47.904 47.477 48.456 ;
     RECT  47.405 55.008 47.477 55.128 ;
     RECT  47.405 57.264 47.477 57.384 ;
     RECT  47.261 68.448 47.513 68.76 ;
     RECT  47.473 98.064 47.513 99.192 ;
     RECT  46.289 91.056 47.545 91.08 ;
     RECT  46.865 92.448 47.545 93.864 ;
     RECT  47.369 80.544 47.549 82.68 ;
     RECT  47.269 41.616 47.585 41.64 ;
     RECT  47.545 91.056 47.603 93.864 ;
     RECT  47.513 98.064 47.603 98.904 ;
     RECT  47.365 12.528 47.617 12.84 ;
     RECT  47.315 63.792 47.621 64.392 ;
     RECT  47.225 85.104 47.621 87.576 ;
     RECT  46.739 100.848 47.621 100.872 ;
     RECT  46.595 103.248 47.621 103.272 ;
     RECT  47.185 50.16 47.657 51.144 ;
     RECT  47.26 30.864 47.693 36.552 ;
     RECT  47.657 50.16 47.693 50.664 ;
     RECT  47.477 57.36 47.693 57.384 ;
     RECT  47.617 12.048 47.725 12.84 ;
     RECT  46.693 13.968 47.729 14.232 ;
     RECT  47.693 31.92 47.729 36.552 ;
     RECT  47.317 72.288 47.729 72.312 ;
     RECT  47.549 80.544 47.729 80.568 ;
     RECT  47.149 96.144 47.729 96.36 ;
     RECT  47.405 52.176 47.747 53.784 ;
     RECT  46.897 20.592 47.749 22.536 ;
     RECT  46.289 23.568 47.749 23.976 ;
     RECT  46.289 25.056 47.761 25.32 ;
     RECT  47.549 81.744 47.761 82.68 ;
     RECT  47.729 96.192 47.761 96.36 ;
     RECT  46.865 94.896 47.765 94.92 ;
     RECT  47.747 52.176 47.788 52.968 ;
     RECT  47.369 61.44 47.837 61.8 ;
     RECT  47.749 20.592 47.845 23.976 ;
     RECT  47.761 25.056 47.845 25.608 ;
     RECT  46.253 77.232 47.893 78.072 ;
     RECT  47.845 20.592 47.932 25.608 ;
     RECT  47.893 76.368 47.939 78.36 ;
     RECT  47.369 15.984 47.945 16.344 ;
     RECT  47.837 61.44 47.981 61.56 ;
     RECT  47.621 85.104 47.981 86.088 ;
     RECT  47.9 42.144 47.987 42.168 ;
     RECT  47.932 23.856 48.017 25.608 ;
     RECT  47.761 96.192 48.037 96.6 ;
     RECT  47.788 52.176 48.053 52.92 ;
     RECT  47.939 78.048 48.053 78.36 ;
     RECT  47.981 85.248 48.053 86.088 ;
     RECT  47.729 14.208 48.085 14.232 ;
     RECT  48.053 52.464 48.089 52.92 ;
     RECT  47.221 18.768 48.121 18.792 ;
     RECT  47.293 89.472 48.121 89.976 ;
     RECT  48.037 96.192 48.124 97.464 ;
     RECT  47.761 81.744 48.131 83.736 ;
     RECT  48.131 82.032 48.172 83.112 ;
     RECT  47.509 55.392 48.197 55.416 ;
     RECT  47.603 91.056 48.236 92.952 ;
     RECT  47.513 68.736 48.284 68.76 ;
     RECT  48.017 25.584 48.323 25.608 ;
     RECT  48.236 90.96 48.323 92.952 ;
     RECT  47.932 20.592 48.341 22.2 ;
     RECT  47.939 76.368 48.341 76.392 ;
     RECT  47.441 26.64 48.349 27.384 ;
     RECT  48.284 68.736 48.371 68.808 ;
     RECT  48.089 52.464 48.377 52.728 ;
     RECT  47.981 61.536 48.377 61.56 ;
     RECT  47.297 74.832 48.409 74.856 ;
     RECT  47.729 31.92 48.449 36.456 ;
     RECT  47.477 47.904 48.449 48.408 ;
     RECT  48.049 39.36 48.467 39.384 ;
     RECT  48.449 34.08 48.485 36.456 ;
     RECT  47.267 46.176 48.485 46.92 ;
     RECT  48.449 48.384 48.485 48.408 ;
     RECT  48.172 82.032 48.521 82.056 ;
     RECT  47.693 50.256 48.557 50.664 ;
     RECT  48.485 34.08 48.593 35.16 ;
     RECT  47.693 30.864 48.625 30.888 ;
     RECT  48.485 46.176 48.629 46.632 ;
     RECT  48.625 30.384 48.665 30.888 ;
     RECT  48.665 30.384 48.709 30.408 ;
     RECT  47.621 64.368 48.733 64.392 ;
     RECT  48.323 91.728 48.733 92.952 ;
     RECT  48.017 23.856 48.737 24.504 ;
     RECT  48.593 34.08 48.737 34.968 ;
     RECT  47.437 17.52 48.755 17.688 ;
     RECT  48.409 74.832 48.757 75.288 ;
     RECT  47.725 12.048 48.764 12.888 ;
     RECT  48.085 14.208 48.764 14.376 ;
     RECT  48.485 36.432 48.773 36.456 ;
     RECT  47.603 98.88 48.773 98.904 ;
     RECT  47.945 16.32 48.805 16.344 ;
     RECT  48.557 50.256 48.805 50.28 ;
     RECT  48.121 89.232 48.809 89.976 ;
     RECT  47.621 87.552 48.841 87.576 ;
     RECT  48.809 89.232 48.841 89.256 ;
     RECT  48.757 74.496 48.845 75.288 ;
     RECT  48.764 12.048 48.851 14.376 ;
     RECT  47.171 44.448 48.881 44.472 ;
     RECT  48.733 63.792 48.901 64.392 ;
     RECT  48.124 96.192 48.901 96.6 ;
     RECT  48.121 18.768 48.913 19.08 ;
     RECT  48.901 63.792 48.947 64.968 ;
     RECT  48.733 91.728 48.949 93.528 ;
     RECT  48.901 95.424 48.949 96.6 ;
     RECT  48.449 31.92 48.953 32.856 ;
     RECT  48.805 16.32 48.985 16.392 ;
     RECT  48.409 57.408 48.989 57.624 ;
     RECT  48.851 12.048 48.997 13.08 ;
     RECT  48.341 22.176 48.997 22.2 ;
     RECT  48.947 64.944 48.997 64.968 ;
     RECT  48.737 24.48 49.043 24.504 ;
     RECT  48.997 64.944 49.043 65.16 ;
     RECT  48.949 91.728 49.043 93.912 ;
     RECT  48.481 58.704 49.045 58.728 ;
     RECT  47.369 60.288 49.045 60.312 ;
     RECT  48.985 16.032 49.057 16.392 ;
     RECT  48.989 57.6 49.061 57.624 ;
     RECT  49.045 58.704 49.091 60.312 ;
     RECT  49.091 59.424 49.129 60.312 ;
     RECT  49.057 66.624 49.129 66.648 ;
     RECT  48.997 11.952 49.133 13.08 ;
     RECT  48.053 85.248 49.205 85.8 ;
     RECT  49.043 91.728 49.205 93.528 ;
     RECT  49.129 66.624 49.213 66.744 ;
     RECT  48.997 25.632 49.237 25.656 ;
     RECT  48.349 26.64 49.237 27.096 ;
     RECT  49.043 65.136 49.313 65.16 ;
     RECT  48.913 18.768 49.385 19.416 ;
     RECT  49.237 25.632 49.457 27.096 ;
     RECT  48.341 20.832 49.484 21.144 ;
     RECT  49.457 26.88 49.493 27.096 ;
     RECT  49.484 20.784 49.525 21.144 ;
     RECT  48.997 22.176 49.525 23.16 ;
     RECT  49.057 15.456 49.553 16.392 ;
     RECT  48.589 55.92 49.561 55.944 ;
     RECT  49.525 20.784 49.571 23.16 ;
     RECT  49.561 55.632 49.601 55.944 ;
     RECT  49.553 14.784 49.637 16.392 ;
     RECT  48.949 95.136 49.637 96.6 ;
     RECT  49.493 26.88 49.673 26.904 ;
     RECT  49.637 95.664 49.673 96.6 ;
     RECT  48.629 46.176 49.705 46.344 ;
     RECT  48.517 104.304 49.717 104.328 ;
     RECT  49.717 103.344 49.763 104.328 ;
     RECT  48.953 32.448 49.772 32.856 ;
     RECT  48.737 34.08 49.772 34.344 ;
     RECT  48.985 29.04 49.849 29.064 ;
     RECT  49.309 31.392 49.849 31.416 ;
     RECT  48.755 17.664 49.853 17.688 ;
     RECT  49.772 32.448 49.859 34.344 ;
     RECT  49.597 101.28 49.859 101.304 ;
     RECT  49.763 103.344 49.859 103.368 ;
     RECT  49.205 91.728 49.885 92.664 ;
     RECT  49.813 98.592 49.925 98.616 ;
     RECT  48.377 52.704 49.957 52.728 ;
     RECT  49.133 11.952 49.961 11.976 ;
     RECT  48.417 37.584 49.961 37.608 ;
     RECT  49.957 52.704 49.997 53.016 ;
     RECT  49.385 19.056 50.033 19.416 ;
     RECT  49.859 34.128 50.033 34.344 ;
     RECT  49.205 85.776 50.245 85.8 ;
     RECT  48.841 87.552 50.245 89.256 ;
     RECT  49.453 65.904 50.317 65.928 ;
     RECT  49.705 42.576 50.389 42.6 ;
     RECT  48.325 69.888 50.569 69.912 ;
     RECT  49.571 21.648 50.605 22.488 ;
     RECT  49.849 29.04 50.677 29.256 ;
     RECT  49.921 35.328 50.677 35.352 ;
     RECT  48.805 49.44 50.677 50.28 ;
     RECT  50.636 51.504 50.677 51.528 ;
     RECT  48.053 78.048 50.677 78.312 ;
     RECT  48.172 83.088 50.677 83.112 ;
     RECT  49.129 59.424 50.713 61.128 ;
     RECT  48.845 74.832 50.713 75.288 ;
     RECT  49.525 80.928 50.725 80.952 ;
     RECT  49.673 95.664 50.725 96.216 ;
     RECT  50.353 107.856 50.771 107.88 ;
     RECT  50.713 58.56 50.813 61.128 ;
     RECT  50.641 13.056 50.869 13.08 ;
     RECT  49.637 15.072 50.869 16.392 ;
     RECT  50.677 49.44 50.869 51.528 ;
     RECT  50.101 93.936 51.001 93.96 ;
     RECT  50.725 94.944 51.001 96.504 ;
     RECT  50.869 12.336 51.008 13.08 ;
     RECT  50.869 14.112 51.008 16.392 ;
     RECT  50.033 19.392 51.008 19.416 ;
     RECT  50.605 21.648 51.008 22.536 ;
     RECT  50.869 23.904 51.008 24.648 ;
     RECT  49.457 25.632 51.008 25.656 ;
     RECT  50.869 26.736 51.008 26.856 ;
     RECT  50.677 28.944 51.008 29.256 ;
     RECT  49.849 31.2 51.008 31.416 ;
     RECT  49.859 32.448 51.008 32.856 ;
     RECT  50.033 34.128 51.008 34.152 ;
     RECT  50.677 35.328 51.008 36.264 ;
     RECT  50.636 38.352 51.008 38.376 ;
     RECT  50.389 42.192 51.008 42.6 ;
     RECT  50.389 44.88 51.008 44.904 ;
     RECT  49.705 46.08 51.008 46.344 ;
     RECT  50.773 47.712 51.008 47.736 ;
     RECT  50.869 48.96 51.008 51.528 ;
     RECT  49.997 52.992 51.008 53.016 ;
     RECT  49.601 55.632 51.008 55.656 ;
     RECT  50.813 58.56 51.008 61.608 ;
     RECT  50.317 65.904 51.008 65.976 ;
     RECT  50.849 67.248 51.008 67.272 ;
     RECT  48.371 68.736 51.008 68.76 ;
     RECT  50.569 69.888 51.008 70.008 ;
     RECT  50.849 72.336 51.008 72.36 ;
     RECT  50.341 73.344 51.008 73.368 ;
     RECT  50.713 74.688 51.008 75.288 ;
     RECT  50.3 76.704 51.008 76.728 ;
     RECT  50.677 78.048 51.008 78.36 ;
     RECT  50.869 79.488 51.008 79.512 ;
     RECT  50.725 80.928 51.008 81.768 ;
     RECT  50.677 83.088 51.008 83.688 ;
     RECT  50.245 84.864 51.008 89.256 ;
     RECT  49.885 91.2 51.008 92.664 ;
     RECT  51.001 93.936 51.008 96.504 ;
     RECT  49.885 97.488 51.008 97.512 ;
     RECT  51.008 2.148 51.112 105.852 ;
     RECT  51.112 2.418 51.304 105.582 ;
     RECT  51.304 15.456 51.401 15.48 ;
     RECT  51.304 31.2 51.401 31.416 ;
     RECT  51.304 94.848 51.401 96.504 ;
     RECT  51.401 94.848 51.581 94.872 ;
     RECT  51.304 65.952 51.587 65.976 ;
     RECT  51.304 69.984 51.635 70.728 ;
     RECT  51.304 67.152 51.653 68.76 ;
     RECT  51.635 70.224 51.676 70.728 ;
     RECT  51.304 85.392 51.725 85.416 ;
     RECT  51.304 46.08 51.761 46.104 ;
     RECT  51.304 48.96 51.797 48.984 ;
     RECT  51.304 52.992 51.905 53.016 ;
     RECT  51.304 91.2 51.905 91.8 ;
     RECT  51.304 16.512 51.949 16.536 ;
     RECT  51.304 23.904 52.013 24.936 ;
     RECT  51.304 61.104 52.013 61.128 ;
     RECT  51.304 28.944 52.049 29.784 ;
     RECT  52.013 24.816 52.163 24.936 ;
     RECT  51.304 87.552 52.259 87.72 ;
     RECT  51.304 22.512 52.301 22.536 ;
     RECT  51.304 88.944 52.337 90.072 ;
     RECT  51.304 50.352 52.409 50.568 ;
     RECT  51.304 26.832 52.441 26.856 ;
     RECT  52.441 26.832 52.481 27.384 ;
     RECT  52.259 87.552 52.499 87.576 ;
     RECT  52.337 89.472 52.517 90.072 ;
     RECT  51.401 96.144 52.621 96.504 ;
     RECT  51.304 73.344 52.733 73.368 ;
     RECT  52.517 89.472 52.739 89.928 ;
     RECT  52.621 96.144 52.739 96.6 ;
     RECT  51.304 17.52 53.029 17.544 ;
     RECT  52.049 29.472 53.057 29.784 ;
     RECT  53.029 17.088 53.075 17.544 ;
     RECT  51.304 83.232 53.129 83.256 ;
     RECT  51.401 31.392 53.132 31.416 ;
     RECT  53.057 29.568 53.173 29.784 ;
     RECT  51.304 32.832 53.173 32.856 ;
     RECT  51.304 34.128 53.173 34.152 ;
     RECT  53.132 31.392 53.219 31.56 ;
     RECT  52.801 15.936 53.305 15.96 ;
     RECT  53.075 17.088 53.305 17.112 ;
     RECT  51.304 18.768 53.315 18.792 ;
     RECT  53.228 21.12 53.315 21.144 ;
     RECT  51.304 63.744 53.324 63.768 ;
     RECT  53.305 15.936 53.345 17.112 ;
     RECT  53.324 63.744 53.411 64.296 ;
     RECT  51.905 91.728 53.417 91.8 ;
     RECT  51.304 74.688 53.557 74.712 ;
     RECT  53.173 32.832 53.561 34.152 ;
     RECT  53.029 14.496 53.741 14.52 ;
     RECT  53.561 32.832 53.773 32.856 ;
     RECT  52.333 53.04 53.777 53.064 ;
     RECT  51.676 70.704 53.777 70.728 ;
     RECT  52.163 24.912 53.797 24.936 ;
     RECT  53.417 91.728 53.797 91.752 ;
     RECT  51.653 68.736 53.809 68.76 ;
     RECT  53.737 40.464 53.821 40.488 ;
     RECT  53.557 74.688 53.843 74.808 ;
     RECT  53.773 32.496 53.856 32.856 ;
     RECT  53.856 32.496 53.857 32.52 ;
     RECT  53.843 74.688 53.891 74.712 ;
     RECT  53.996 56.736 54.083 56.76 ;
     RECT  51.304 58.08 54.083 58.104 ;
     RECT  51.304 79.488 54.083 79.512 ;
     RECT  52.739 89.472 54.092 89.496 ;
     RECT  54.037 80.496 54.124 80.52 ;
     RECT  52.409 50.352 54.131 50.472 ;
     RECT  53.219 31.392 54.137 31.416 ;
     RECT  54.053 40.992 54.137 41.016 ;
     RECT  53.809 68.736 54.137 68.952 ;
     RECT  54.092 88.896 54.179 89.496 ;
     RECT  54.131 50.448 54.209 50.472 ;
     RECT  54.133 85.488 54.217 85.512 ;
     RECT  52.481 27.36 54.497 27.384 ;
     RECT  53.561 34.128 54.533 34.152 ;
     RECT  53.449 55.008 54.533 55.032 ;
     RECT  53.345 16.272 54.641 16.296 ;
     RECT  51.304 36.24 54.641 36.264 ;
     RECT  53.173 29.568 54.749 30.168 ;
     RECT  54.179 89.472 55.073 89.496 ;
     RECT  52.739 96.576 55.145 96.6 ;
     RECT  54.085 47.904 56.213 47.928 ;
     RECT  51.304 44.88 56.245 44.904 ;
     RECT  53.269 22.224 56.408 22.248 ;
     RECT  53.797 24.624 56.408 24.936 ;
     RECT  54.749 29.568 56.408 29.592 ;
     RECT  56.245 44.88 56.408 45.192 ;
     RECT  56.213 47.328 56.408 47.928 ;
     RECT  53.365 62.112 56.408 62.136 ;
     RECT  54.137 68.928 56.408 68.952 ;
     RECT  55.969 82.512 56.408 82.536 ;
     RECT  53.797 91.584 56.408 91.752 ;
     RECT  56.408 2.148 56.512 105.852 ;
     RECT  56.512 2.418 56.704 105.582 ;
     RECT  56.704 91.584 57.881 91.656 ;
     RECT  57.881 91.584 58.844 91.608 ;
     RECT  56.704 82.512 58.931 82.536 ;
     RECT  58.844 91.44 58.931 91.608 ;
     RECT  56.704 29.568 59.789 29.592 ;
     RECT  56.704 45.168 61.045 45.192 ;
     RECT  61.045 44.976 61.333 45.192 ;
     RECT  56.704 24.624 61.808 24.936 ;
     RECT  61.333 44.976 61.808 45.576 ;
     RECT  56.704 47.904 61.808 47.928 ;
     RECT  56.704 68.928 61.808 68.952 ;
     RECT  58.931 91.584 61.808 91.608 ;
     RECT  58.885 96.72 61.808 96.744 ;
     RECT  61.808 2.148 61.912 105.852 ;
     RECT  61.912 2.418 62.104 105.582 ;
     RECT  62.104 45.552 62.675 46.44 ;
     RECT  62.104 47.904 62.705 48.12 ;
     RECT  64.033 53.04 64.117 53.064 ;
     RECT  62.104 24.624 64.865 24.936 ;
     RECT  62.675 46.416 66.121 46.44 ;
     RECT  66.121 46.416 66.161 46.536 ;
     RECT  65.581 63.216 66.661 63.24 ;
     RECT  65.689 54.72 67.093 54.744 ;
     RECT  64.865 24.624 67.208 24.648 ;
     RECT  66.085 28.416 67.208 28.44 ;
     RECT  66.161 46.512 67.208 46.536 ;
     RECT  62.705 48.096 67.208 48.12 ;
     RECT  67.093 54.72 67.208 55.176 ;
     RECT  66.481 61.968 67.208 61.992 ;
     RECT  66.661 63.216 67.208 63.528 ;
     RECT  62.104 68.928 67.208 68.952 ;
     RECT  66.913 80.544 67.208 80.568 ;
     RECT  66.985 87.648 67.208 88.392 ;
     RECT  62.104 91.584 67.208 91.608 ;
     RECT  62.104 96.72 67.208 96.744 ;
     RECT  67.208 2.148 67.312 105.852 ;
     RECT  67.312 2.418 67.504 105.582 ;
     RECT  67.504 20.448 67.859 20.712 ;
     RECT  67.504 18.768 68.003 18.792 ;
     RECT  67.504 35.28 68.339 35.928 ;
     RECT  67.504 24.624 68.387 24.648 ;
     RECT  67.504 87.648 68.387 88.392 ;
     RECT  67.504 96.72 68.387 96.888 ;
     RECT  68.387 96.864 68.428 96.888 ;
     RECT  67.504 46.512 68.435 48.12 ;
     RECT  67.504 61.968 68.465 61.992 ;
     RECT  67.504 89.424 68.537 89.448 ;
     RECT  67.504 52.464 68.629 52.488 ;
     RECT  67.504 11.376 68.675 12.024 ;
     RECT  67.504 55.152 68.684 55.176 ;
     RECT  68.629 51.552 68.717 52.488 ;
     RECT  68.435 47.328 68.753 48.12 ;
     RECT  68.684 55.152 68.771 55.56 ;
     RECT  67.504 59.712 68.771 59.928 ;
     RECT  67.504 44.352 68.789 45 ;
     RECT  67.859 20.448 68.821 20.472 ;
     RECT  68.675 12 68.861 12.024 ;
     RECT  68.821 19.92 68.861 20.472 ;
     RECT  68.789 44.352 68.893 44.616 ;
     RECT  68.861 19.92 68.963 19.944 ;
     RECT  67.504 28.416 68.965 28.44 ;
     RECT  67.504 29.712 68.965 29.736 ;
     RECT  68.965 28.416 69.011 29.736 ;
     RECT  68.893 43.728 69.011 44.616 ;
     RECT  69.011 28.416 69.113 29.592 ;
     RECT  69.011 44.064 69.221 44.616 ;
     RECT  68.965 42.72 69.401 42.744 ;
     RECT  67.504 80.544 69.437 81.48 ;
     RECT  69.404 34.032 69.491 34.056 ;
     RECT  68.387 87.648 69.541 87.672 ;
     RECT  69.541 87.504 69.581 87.672 ;
     RECT  68.893 79.104 69.637 79.128 ;
     RECT  69.637 78.624 69.683 79.656 ;
     RECT  69.683 79.632 69.724 79.656 ;
     RECT  69.113 29.568 69.977 29.592 ;
     RECT  68.929 26.784 70.009 26.808 ;
     RECT  68.753 48.096 70.009 48.12 ;
     RECT  69.437 80.88 70.009 81.48 ;
     RECT  70.009 80.88 70.049 81.528 ;
     RECT  70.009 26.688 70.067 26.808 ;
     RECT  68.339 35.28 70.085 35.448 ;
     RECT  68.929 60.96 70.085 60.984 ;
     RECT  70.067 26.688 70.093 26.712 ;
     RECT  70.045 12.24 70.117 12.264 ;
     RECT  70.117 12.24 70.163 13.128 ;
     RECT  70.085 35.376 70.193 35.448 ;
     RECT  69.469 37.584 70.261 37.608 ;
     RECT  69.221 44.592 70.265 44.616 ;
     RECT  70.261 37.296 70.301 37.608 ;
     RECT  70.163 12.48 70.589 13.128 ;
     RECT  70.405 18.24 70.645 18.264 ;
     RECT  70.645 17.376 70.691 18.264 ;
     RECT  69.581 87.504 70.693 87.528 ;
     RECT  70.693 86.592 70.739 87.528 ;
     RECT  70.7 30.192 70.787 30.216 ;
     RECT  70.7 70.992 70.787 71.016 ;
     RECT  68.917 21.12 70.837 21.144 ;
     RECT  70.739 86.592 70.873 86.616 ;
     RECT  70.837 21.12 70.877 21.672 ;
     RECT  70.873 85.92 70.913 86.616 ;
     RECT  70.081 55.824 70.933 55.848 ;
     RECT  70.933 55.824 70.979 56.76 ;
     RECT  70.979 56.736 71.021 56.76 ;
     RECT  67.504 100.176 71.089 100.2 ;
     RECT  70.049 81.456 71.125 81.528 ;
     RECT  70.009 47.856 71.165 48.12 ;
     RECT  68.771 59.712 71.221 59.736 ;
     RECT  70.081 95.856 71.228 95.88 ;
     RECT  70.913 85.92 71.267 85.944 ;
     RECT  70.477 90.576 71.269 90.6 ;
     RECT  67.504 91.584 71.269 91.608 ;
     RECT  71.197 58.128 71.281 58.152 ;
     RECT  71.221 59.664 71.308 59.736 ;
     RECT  71.228 95.568 71.315 95.88 ;
     RECT  71.125 81.216 71.413 81.528 ;
     RECT  71.269 90.576 71.507 91.608 ;
     RECT  71.269 94.56 71.509 94.584 ;
     RECT  71.221 84.336 71.521 84.36 ;
     RECT  71.089 99.744 71.555 100.2 ;
     RECT  71.516 50.832 71.557 50.856 ;
     RECT  71.507 91.296 71.561 91.608 ;
     RECT  71.233 49.536 71.603 49.56 ;
     RECT  71.557 50.64 71.603 50.856 ;
     RECT  68.717 52.464 71.603 52.488 ;
     RECT  71.521 83.568 71.749 84.36 ;
     RECT  71.555 100.08 71.804 100.2 ;
     RECT  68.629 6.528 71.941 6.552 ;
     RECT  72.236 8.304 72.277 8.328 ;
     RECT  71.308 59.712 72.349 59.736 ;
     RECT  71.941 5.616 72.385 6.552 ;
     RECT  67.504 22.992 72.385 23.016 ;
     RECT  70.741 31.632 72.385 31.656 ;
     RECT  70.589 12.48 72.421 12.504 ;
     RECT  72.421 61.44 72.449 61.464 ;
     RECT  70.193 35.424 72.469 35.448 ;
     RECT  72.449 41.568 72.469 41.592 ;
     RECT  71.509 94.56 72.565 94.968 ;
     RECT  72.385 5.616 72.608 6.84 ;
     RECT  72.277 8.304 72.608 9.096 ;
     RECT  72.421 12.48 72.608 12.552 ;
     RECT  72.457 13.92 72.608 13.944 ;
     RECT  70.691 17.376 72.608 17.4 ;
     RECT  70.877 21.648 72.608 21.672 ;
     RECT  72.385 22.8 72.608 23.928 ;
     RECT  69.577 25.488 72.608 25.512 ;
     RECT  72.385 31.632 72.608 31.8 ;
     RECT  72.385 33.6 72.608 33.624 ;
     RECT  72.469 35.424 72.608 35.544 ;
     RECT  70.301 37.296 72.608 37.32 ;
     RECT  72.429 39.216 72.608 39.24 ;
     RECT  72.469 41.568 72.608 42.216 ;
     RECT  70.405 44.64 72.608 44.664 ;
     RECT  71.165 47.856 72.608 47.88 ;
     RECT  71.603 50.64 72.608 50.664 ;
     RECT  72.349 59.568 72.608 59.736 ;
     RECT  72.449 61.008 72.608 61.464 ;
     RECT  69.793 63.792 72.608 63.816 ;
     RECT  72.421 65.136 72.608 65.16 ;
     RECT  67.504 68.928 72.608 68.952 ;
     RECT  72.469 70.8 72.608 70.824 ;
     RECT  70.741 72.144 72.608 72.168 ;
     RECT  69.683 78.624 72.608 78.648 ;
     RECT  71.413 81.216 72.608 81.768 ;
     RECT  71.749 82.944 72.608 84.36 ;
     RECT  71.561 91.584 72.608 91.608 ;
     RECT  72.565 94.032 72.608 94.968 ;
     RECT  71.804 100.08 72.608 100.488 ;
     RECT  70.729 104.832 72.608 104.856 ;
     RECT  72.608 2.148 72.712 105.852 ;
     RECT  72.712 2.418 72.904 105.582 ;
     RECT  72.904 61.008 72.965 61.464 ;
     RECT  72.904 49.008 73.001 49.032 ;
     RECT  72.904 50.64 73.001 50.664 ;
     RECT  72.904 12.48 73.217 12.552 ;
     RECT  73.217 12.48 73.283 12.504 ;
     RECT  72.904 25.488 73.325 25.512 ;
     RECT  72.904 16.512 73.397 17.112 ;
     RECT  72.904 35.424 73.397 35.544 ;
     RECT  72.904 13.92 73.523 14.472 ;
     RECT  72.904 99.024 73.549 100.92 ;
     RECT  72.904 94.032 73.619 95.112 ;
     RECT  72.904 22.704 73.685 22.824 ;
     RECT  73.549 99.024 73.756 100.104 ;
     RECT  73.397 16.512 73.757 16.536 ;
     RECT  72.904 70.272 73.811 72.6 ;
     RECT  73.811 72.576 73.852 72.6 ;
     RECT  73.619 94.8 73.907 95.112 ;
     RECT  72.904 97.152 73.907 97.176 ;
     RECT  72.904 78.624 73.955 78.648 ;
     RECT  73.811 70.272 73.957 71.544 ;
     RECT  73.957 70.08 73.973 71.544 ;
     RECT  73.909 77.424 73.996 77.448 ;
     RECT  73.973 70.08 74.003 71.256 ;
     RECT  74.003 70.08 74.005 70.104 ;
     RECT  72.904 82.944 74.005 82.968 ;
     RECT  74.003 71.232 74.017 71.256 ;
     RECT  74.005 69.552 74.045 70.104 ;
     RECT  74.005 82.944 74.051 83.784 ;
     RECT  72.904 102 74.051 102.024 ;
     RECT  74.005 103.2 74.053 103.224 ;
     RECT  73.756 99.12 74.081 100.104 ;
     RECT  74.005 84.816 74.092 84.84 ;
     RECT  72.904 59.568 74.099 59.592 ;
     RECT  72.904 104.832 74.099 104.856 ;
     RECT  72.904 67.776 74.101 67.8 ;
     RECT  74.053 58.32 74.14 58.344 ;
     RECT  74.101 67.152 74.147 68.424 ;
     RECT  72.965 61.008 74.153 61.032 ;
     RECT  72.904 6.432 74.221 7.416 ;
     RECT  72.904 9.072 74.221 9.096 ;
     RECT  72.904 42.192 74.221 42.216 ;
     RECT  74.221 6.432 74.252 9.096 ;
     RECT  72.904 10.512 74.252 10.536 ;
     RECT  74.221 42.096 74.261 42.216 ;
     RECT  72.904 65.136 74.297 65.16 ;
     RECT  74.252 6.432 74.339 10.536 ;
     RECT  74.147 67.152 74.369 67.176 ;
     RECT  72.904 31.776 74.437 31.8 ;
     RECT  74.437 31.776 74.541 32.472 ;
     RECT  74.339 6.432 74.585 7.416 ;
     RECT  74.339 10.512 74.585 10.536 ;
     RECT  74.293 76.896 74.617 76.92 ;
     RECT  74.053 103.2 74.621 103.368 ;
     RECT  74.585 6.432 74.675 6.456 ;
     RECT  74.147 68.4 74.693 68.424 ;
     RECT  74.045 69.552 74.693 69.576 ;
     RECT  73.523 14.352 74.725 14.472 ;
     RECT  72.904 30.576 74.729 30.6 ;
     RECT  74.609 33.6 74.765 33.624 ;
     RECT  74.725 14.352 74.771 15.432 ;
     RECT  74.113 40.416 74.801 40.44 ;
     RECT  74.771 14.784 74.809 15.432 ;
     RECT  74.629 5.184 74.833 5.208 ;
     RECT  73.685 22.704 74.833 22.728 ;
     RECT  74.617 76.368 74.869 76.92 ;
     RECT  74.869 75.84 74.909 76.92 ;
     RECT  74.051 83.76 74.909 83.784 ;
     RECT  74.828 16.512 74.915 16.536 ;
     RECT  74.833 22.704 74.917 23.4 ;
     RECT  74.833 4.32 75.052 5.208 ;
     RECT  74.917 22.704 75.053 22.728 ;
     RECT  74.053 56.976 75.053 57 ;
     RECT  72.904 2.64 75.193 2.664 ;
     RECT  74.081 99.12 75.221 99.144 ;
     RECT  75.193 2.64 75.233 2.856 ;
     RECT  75.052 4.32 75.251 4.344 ;
     RECT  75.221 98.64 75.253 99.144 ;
     RECT  72.904 39.216 75.269 39.24 ;
     RECT  75.233 2.832 75.277 2.856 ;
     RECT  75.253 97.968 75.305 99.144 ;
     RECT  74.909 75.84 75.449 75.864 ;
     RECT  74.221 92.784 75.452 92.808 ;
     RECT  74.809 14.784 75.485 14.808 ;
     RECT  75.452 92.016 75.493 92.808 ;
     RECT  73.907 94.8 75.493 94.824 ;
     RECT  74.261 42.096 75.521 42.12 ;
     RECT  75.493 92.016 75.539 93.096 ;
     RECT  75.493 94.464 75.539 94.824 ;
     RECT  74.437 85.248 75.557 85.272 ;
     RECT  74.621 103.2 75.557 103.224 ;
     RECT  75.539 93.072 75.58 93.096 ;
     RECT  74.541 32.448 75.593 32.472 ;
     RECT  74.909 76.896 75.593 76.92 ;
     RECT  72.904 74.256 75.845 74.28 ;
     RECT  75.539 94.464 75.845 94.488 ;
     RECT  75.305 97.968 75.845 97.992 ;
     RECT  75.157 66.096 76.025 66.12 ;
     RECT  78.008 2.148 78.112 105.852 ;
     RECT  78.112 2.418 78.304 105.582 ;
     RECT  83.408 2.148 83.512 105.852 ;
     RECT  83.512 2.418 83.704 105.582 ;
     RECT  84.841 27.792 84.877 27.816 ;
     RECT  83.704 65.04 84.877 65.064 ;
     RECT  84.877 62.88 85.345 62.904 ;
     RECT  84.877 64.512 85.345 65.64 ;
     RECT  84.877 7.824 85.453 7.848 ;
     RECT  84.877 11.616 85.453 11.64 ;
     RECT  84.877 15.936 85.453 15.96 ;
     RECT  84.877 20.784 85.453 21.336 ;
     RECT  84.877 27.264 85.453 27.816 ;
     RECT  85.345 28.896 85.453 28.92 ;
     RECT  85.345 31.056 85.453 31.08 ;
     RECT  84.877 46.176 85.453 46.2 ;
     RECT  85.345 48.336 85.453 48.36 ;
     RECT  84.877 53.712 85.453 53.736 ;
     RECT  84.877 54.816 85.453 54.84 ;
     RECT  84.877 56.4 85.453 56.424 ;
     RECT  85.345 62.88 85.453 63.48 ;
     RECT  85.345 64.512 85.453 66.168 ;
     RECT  83.704 75.84 85.453 76.44 ;
     RECT  85.345 82.896 85.453 82.92 ;
     RECT  85.345 96.912 85.453 97.464 ;
     RECT  85.345 103.392 85.453 103.416 ;
     RECT  84.985 105.552 85.453 105.576 ;
     RECT  85.453 2.4 85.489 7.848 ;
     RECT  85.453 8.88 85.489 12.696 ;
     RECT  85.453 13.776 85.489 105.576 ;
     RECT  85.489 2.4 86.364 105.576 ;
    LAYER M5 ;
     RECT  2.4 2.137 2.52 2.151 ;
     RECT  7.8 2.137 7.92 2.151 ;
     RECT  13.2 2.137 13.32 2.151 ;
     RECT  18.6 2.137 18.72 2.151 ;
     RECT  24 2.137 24.12 2.151 ;
     RECT  29.4 2.137 29.52 2.151 ;
     RECT  34.8 2.137 34.92 2.151 ;
     RECT  40.2 2.137 40.32 2.151 ;
     RECT  45.6 2.137 45.72 2.151 ;
     RECT  51 2.137 51.12 2.151 ;
     RECT  56.4 2.137 56.52 2.151 ;
     RECT  61.8 2.137 61.92 2.151 ;
     RECT  67.2 2.137 67.32 2.151 ;
     RECT  72.6 2.137 72.72 2.151 ;
     RECT  78 2.137 78.12 2.151 ;
     RECT  83.4 2.137 83.52 2.151 ;
     RECT  2.4 2.151 2.712 2.821 ;
     RECT  40.2 2.151 40.512 2.821 ;
     RECT  2.4 2.821 2.952 4.115 ;
     RECT  37.632 2.629 37.656 4.115 ;
     RECT  39.984 2.821 40.512 4.115 ;
     RECT  75.216 2.821 75.24 4.309 ;
     RECT  74.976 4.309 75.24 4.355 ;
     RECT  74.976 4.355 75 5.173 ;
     RECT  74.64 5.173 75 5.219 ;
     RECT  44.448 4.501 44.472 5.413 ;
     RECT  45.6 2.151 45.912 5.413 ;
     RECT  44.448 5.413 45.912 5.459 ;
     RECT  72.6 2.151 72.912 5.605 ;
     RECT  37.584 5.365 37.608 6.133 ;
     RECT  74.64 5.219 74.664 6.467 ;
     RECT  71.952 5.605 72.912 6.563 ;
     RECT  2.4 4.115 2.808 6.805 ;
     RECT  37.056 6.133 37.608 6.851 ;
     RECT  5.616 5.317 5.64 7.861 ;
     RECT  2.4 6.805 2.904 7.907 ;
     RECT  5.616 7.861 6.456 7.907 ;
     RECT  40.2 4.115 40.512 7.957 ;
     RECT  72.432 6.563 72.912 8.293 ;
     RECT  37.056 6.851 37.128 8.437 ;
     RECT  72.288 8.293 72.912 9.107 ;
     RECT  40.2 7.957 41.448 9.539 ;
     RECT  34.8 2.151 35.112 9.637 ;
     RECT  36.192 8.437 37.128 9.637 ;
     RECT  34.8 9.637 37.128 9.683 ;
     RECT  44.976 5.459 45.912 9.731 ;
     RECT  6.432 7.907 6.456 9.779 ;
     RECT  45.6 9.731 45.912 10.165 ;
     RECT  37.104 9.683 37.128 10.261 ;
     RECT  72.432 9.107 72.912 10.501 ;
     RECT  74.304 7.381 74.328 10.547 ;
     RECT  34.8 9.683 35.832 10.789 ;
     RECT  40.2 9.539 40.512 10.789 ;
     RECT  5.136 9.733 5.16 10.835 ;
     RECT  37.104 10.261 37.8 10.835 ;
     RECT  45.6 10.165 46.776 10.837 ;
     RECT  37.104 10.835 37.704 10.883 ;
     RECT  34.8 10.789 35.928 10.931 ;
     RECT  45.6 10.837 46.872 10.979 ;
     RECT  67.2 2.151 67.512 11.365 ;
     RECT  68.64 6.517 68.664 11.365 ;
     RECT  67.2 11.365 68.664 11.411 ;
     RECT  43.92 9.637 43.944 11.459 ;
     RECT  39.744 10.789 40.512 11.749 ;
     RECT  39.744 11.749 41.064 11.795 ;
     RECT  67.2 11.411 68.424 12.035 ;
     RECT  51 2.151 51.312 12.325 ;
     RECT  72.432 10.501 73.272 12.515 ;
     RECT  49.008 11.941 49.032 12.563 ;
     RECT  4.032 6.805 4.056 12.901 ;
     RECT  70.128 12.229 70.152 13.139 ;
     RECT  36.432 13.045 36.456 13.811 ;
     RECT  72.432 12.515 73.032 13.909 ;
     RECT  40.2 11.795 41.064 14.387 ;
     RECT  48.816 13.045 48.84 14.387 ;
     RECT  45.6 10.979 45.912 14.773 ;
     RECT  38.736 13.045 38.76 14.867 ;
     RECT  43.92 13.525 43.944 14.867 ;
     RECT  3.984 12.901 4.056 15.347 ;
     RECT  74.736 14.341 74.76 15.443 ;
     RECT  49.584 14.773 49.608 15.491 ;
     RECT  50.88 12.325 51.312 15.491 ;
     RECT  53.04 14.485 53.064 15.971 ;
     RECT  43.296 15.829 43.32 16.019 ;
     RECT  40.2 14.387 40.512 16.357 ;
     RECT  51 15.491 51.312 16.501 ;
     RECT  72.432 13.909 73.512 16.547 ;
     RECT  4.032 15.347 4.056 16.595 ;
     RECT  45.6 14.773 46.68 16.691 ;
     RECT  45.6 16.691 45.912 18.181 ;
     RECT  70.656 17.365 70.68 18.275 ;
     RECT  37.68 10.883 37.704 18.757 ;
     RECT  53.04 17.077 53.064 18.757 ;
     RECT  67.2 12.035 67.512 18.757 ;
     RECT  48.72 17.509 48.744 18.803 ;
     RECT  53.04 18.757 53.304 18.803 ;
     RECT  40.2 16.357 40.632 19.237 ;
     RECT  44.784 18.181 45.912 19.525 ;
     RECT  37.632 18.757 37.704 19.619 ;
     RECT  67.2 18.757 67.992 19.909 ;
     RECT  40.2 19.237 41.448 20.003 ;
     RECT  37.68 19.619 37.704 20.005 ;
     RECT  37.68 20.005 38.088 20.051 ;
     RECT  43.872 19.525 45.912 20.389 ;
     RECT  43.872 20.389 46.776 20.435 ;
     RECT  67.2 19.909 68.952 20.483 ;
     RECT  38.064 20.051 38.088 20.579 ;
     RECT  43.872 20.435 43.896 20.579 ;
     RECT  4.272 18.229 4.296 20.771 ;
     RECT  68.928 20.483 68.952 21.155 ;
     RECT  49.536 19.381 49.56 21.637 ;
     RECT  51 16.501 51.912 21.637 ;
     RECT  45.6 20.435 46.776 22.211 ;
     RECT  53.28 18.803 53.304 22.259 ;
     RECT  2.4 7.907 2.712 22.405 ;
     RECT  49.536 21.637 51.912 22.499 ;
     RECT  2.016 22.405 2.712 22.547 ;
     RECT  67.2 20.483 67.848 22.981 ;
     RECT  72.432 16.547 72.912 23.027 ;
     RECT  47.76 22.501 47.784 23.125 ;
     RECT  49.536 22.499 49.56 23.125 ;
     RECT  47.76 23.125 47.88 23.171 ;
     RECT  49.008 23.125 49.56 23.171 ;
     RECT  74.88 16.501 74.904 23.411 ;
     RECT  40.2 20.003 40.512 23.557 ;
     RECT  51 22.499 51.912 23.893 ;
     RECT  50.88 23.893 51.912 24.805 ;
     RECT  47.856 23.171 47.88 25.091 ;
     RECT  72.48 23.027 72.912 25.523 ;
     RECT  49.008 23.171 49.032 25.573 ;
     RECT  38.304 22.741 38.328 26.051 ;
     RECT  48.288 25.573 49.032 26.101 ;
     RECT  40.08 23.557 40.512 26.245 ;
     RECT  48.288 26.101 49.272 26.819 ;
     RECT  70.032 26.677 70.056 26.819 ;
     RECT  50.88 24.805 52.152 26.867 ;
     RECT  3.936 22.789 3.96 27.107 ;
     RECT  45.6 22.211 45.912 27.157 ;
     RECT  45.6 27.157 46.104 27.347 ;
     RECT  48.288 26.819 48.312 27.395 ;
     RECT  2.4 22.547 2.712 27.781 ;
     RECT  40.08 26.245 41.352 27.971 ;
     RECT  67.2 22.981 68.376 29.029 ;
     RECT  67.2 29.029 69 29.557 ;
     RECT  51 26.867 52.152 29.699 ;
     RECT  67.2 29.557 69.48 29.747 ;
     RECT  53.808 24.613 53.832 29.749 ;
     RECT  47.184 28.501 47.208 30.035 ;
     RECT  45.6 27.347 45.912 30.709 ;
     RECT  44.496 30.709 45.912 31.237 ;
     RECT  43.824 31.237 45.912 31.283 ;
     RECT  38.256 30.181 38.28 31.333 ;
     RECT  37.632 31.333 38.28 31.379 ;
     RECT  70.752 30.181 70.776 31.667 ;
     RECT  74.448 30.565 74.472 31.811 ;
     RECT  48.672 30.373 48.696 31.955 ;
     RECT  53.184 29.749 53.832 32.531 ;
     RECT  40.2 27.971 41.352 33.251 ;
     RECT  37.632 31.379 37.656 33.253 ;
     RECT  34.8 10.931 35.112 33.445 ;
     RECT  36.144 15.349 36.168 33.445 ;
     RECT  34.8 33.445 36.168 33.491 ;
     RECT  49.824 32.437 49.848 33.539 ;
     RECT  2.4 27.781 3.672 33.589 ;
     RECT  40.2 33.251 40.632 33.589 ;
     RECT  72.6 25.523 72.912 33.589 ;
     RECT  43.824 31.283 43.848 33.635 ;
     RECT  74.64 32.437 74.664 33.635 ;
     RECT  2.4 33.589 3.768 33.637 ;
     RECT  2.4 33.637 3.96 33.683 ;
     RECT  34.8 33.491 35.928 33.683 ;
     RECT  53.184 32.531 53.784 33.683 ;
     RECT  39.696 33.589 40.632 34.355 ;
     RECT  42.384 33.445 42.408 34.355 ;
     RECT  46.896 30.709 46.92 34.835 ;
     RECT  69.456 29.747 69.48 35.315 ;
     RECT  45.312 31.283 45.912 35.317 ;
     RECT  67.2 29.747 68.376 35.459 ;
     RECT  3.744 33.683 3.96 35.843 ;
     RECT  67.2 35.459 68.328 35.939 ;
     RECT  51 29.699 51.312 36.229 ;
     RECT  45.312 35.317 46.2 36.563 ;
     RECT  42.336 35.317 42.36 37.091 ;
     RECT  45.6 36.563 46.2 37.091 ;
     RECT  37.632 33.253 37.752 37.283 ;
     RECT  43.68 36.517 43.704 37.477 ;
     RECT  45.6 37.091 45.912 38.101 ;
     RECT  3.888 35.843 3.96 38.341 ;
     RECT  43.68 37.477 44.232 38.675 ;
     RECT  37.728 37.283 37.752 38.725 ;
     RECT  39.696 34.355 40.512 39.061 ;
     RECT  42.144 38.725 42.168 39.061 ;
     RECT  3.792 38.341 3.96 39.107 ;
     RECT  39.696 39.061 42.168 39.107 ;
     RECT  72.48 33.589 72.912 39.251 ;
     RECT  45.456 38.101 45.912 39.347 ;
     RECT  48.432 37.573 48.456 39.395 ;
     RECT  37.68 38.725 37.752 39.635 ;
     RECT  39.696 39.107 41.448 39.923 ;
     RECT  74.688 39.205 74.712 40.451 ;
     RECT  53.76 33.683 53.784 40.499 ;
     RECT  72.6 39.251 72.912 41.557 ;
     RECT  3.888 39.107 3.96 41.651 ;
     RECT  47.28 39.301 47.304 42.133 ;
     RECT  50.688 36.229 51.312 42.181 ;
     RECT  47.28 42.133 47.976 42.707 ;
     RECT  43.68 38.675 43.704 42.949 ;
     RECT  41.616 41.749 41.64 43.139 ;
     RECT  39.696 39.923 40.512 43.669 ;
     RECT  45.6 39.347 45.912 43.813 ;
     RECT  34.8 33.683 35.112 43.861 ;
     RECT  47.952 42.707 47.976 43.861 ;
     RECT  36.528 42.133 36.552 43.907 ;
     RECT  42.912 42.949 43.704 43.907 ;
     RECT  5.04 42.037 5.064 43.955 ;
     RECT  67.2 35.939 67.512 44.341 ;
     RECT  68.976 42.709 69 44.341 ;
     RECT  47.136 43.861 47.976 44.483 ;
     RECT  67.2 44.341 69 44.627 ;
     RECT  56.4 2.151 56.712 44.869 ;
     RECT  50.4 42.181 51.312 44.915 ;
     RECT  3.936 41.651 3.96 44.965 ;
     RECT  61.8 2.151 62.112 44.965 ;
     RECT  45.312 43.813 45.912 45.155 ;
     RECT  39.36 43.669 40.512 45.443 ;
     RECT  61.056 44.965 62.112 45.541 ;
     RECT  51 44.915 51.312 46.117 ;
     RECT  34.8 43.861 35.208 46.211 ;
     RECT  42.912 43.907 42.936 46.259 ;
     RECT  61.056 45.541 62.664 46.451 ;
     RECT  47.136 44.483 47.256 46.931 ;
     RECT  37.728 39.635 37.752 47.075 ;
     RECT  56.256 44.869 56.712 47.363 ;
     RECT  67.2 44.627 68.424 47.363 ;
     RECT  3.696 44.965 3.96 47.603 ;
     RECT  47.136 46.931 47.16 47.701 ;
     RECT  50.784 46.117 51.312 47.747 ;
     RECT  45.504 45.155 45.912 47.845 ;
     RECT  72.48 41.557 72.912 47.891 ;
     RECT  61.056 46.451 62.112 47.939 ;
     RECT  45.216 47.845 45.912 48.659 ;
     RECT  38.64 47.797 38.664 48.899 ;
     RECT  3.936 47.603 3.96 49.043 ;
     RECT  50.88 47.747 51.312 49.475 ;
     RECT  39.696 45.443 40.512 49.861 ;
     RECT  45.6 48.659 45.912 49.861 ;
     RECT  2.4 33.683 2.712 50.101 ;
     RECT  44.832 49.861 45.912 50.245 ;
     RECT  46.944 47.701 47.16 50.245 ;
     RECT  44.832 50.245 47.16 50.291 ;
     RECT  54.096 40.981 54.12 50.387 ;
     RECT  44.832 50.291 46.776 50.531 ;
     RECT  39.696 49.861 41.064 50.771 ;
     RECT  38.688 48.949 38.712 51.155 ;
     RECT  39.696 50.771 40.512 51.205 ;
     RECT  45.6 50.531 46.776 51.253 ;
     RECT  45.6 51.253 47.112 51.395 ;
     RECT  51 49.475 51.312 51.493 ;
     RECT  47.088 51.395 47.112 52.165 ;
     RECT  47.088 52.165 47.736 52.211 ;
     RECT  42.144 51.205 42.168 52.451 ;
     RECT  43.296 51.541 43.32 52.451 ;
     RECT  2.4 50.101 3.432 52.453 ;
     RECT  2.4 52.453 3.72 52.499 ;
     RECT  68.64 51.541 68.664 52.499 ;
     RECT  71.568 49.525 71.592 52.499 ;
     RECT  50.688 51.493 51.312 53.027 ;
     RECT  64.08 46.405 64.104 53.075 ;
     RECT  3.696 52.499 3.72 53.555 ;
     RECT  38.736 51.205 40.512 53.603 ;
     RECT  47.712 52.211 47.736 53.795 ;
     RECT  39.696 53.603 40.512 53.987 ;
     RECT  42.192 54.661 42.216 54.995 ;
     RECT  2.4 52.499 2.712 55.237 ;
     RECT  3.984 54.517 4.008 55.237 ;
     RECT  2.4 55.237 4.008 55.619 ;
     RECT  43.2 54.085 43.224 55.813 ;
     RECT  13.2 2.151 13.512 56.389 ;
     RECT  39.744 53.987 40.512 56.389 ;
     RECT  2.4 55.619 3.432 56.483 ;
     RECT  70.944 55.813 70.968 56.771 ;
     RECT  38.784 56.389 40.512 56.773 ;
     RECT  38.784 56.773 41.016 58.115 ;
     RECT  54.048 54.997 54.072 58.115 ;
     RECT  51 53.027 51.312 58.549 ;
     RECT  38.88 58.115 40.512 59.221 ;
     RECT  47.28 56.965 47.304 59.459 ;
     RECT  49.056 58.693 49.08 59.459 ;
     RECT  71.232 58.117 71.256 59.699 ;
     RECT  72.6 47.891 72.912 59.701 ;
     RECT  2.4 56.483 2.712 59.797 ;
     RECT  68.736 55.141 68.76 59.939 ;
     RECT  50.736 58.549 51.312 60.323 ;
     RECT  43.2 55.813 43.704 60.419 ;
     RECT  45.6 51.395 45.912 60.421 ;
     RECT  38.784 59.221 40.512 60.805 ;
     RECT  45.6 60.421 46.824 60.995 ;
     RECT  74.064 56.965 74.088 61.043 ;
     RECT  72.48 59.701 72.912 61.429 ;
     RECT  50.832 60.323 51.312 61.619 ;
     RECT  41.568 60.949 41.592 61.907 ;
     RECT  67.2 47.363 67.512 61.957 ;
     RECT  66.672 61.957 67.512 63.539 ;
     RECT  51 61.619 51.312 63.733 ;
     RECT  2.4 59.797 3.624 64.213 ;
     RECT  53.376 62.101 53.4 64.307 ;
     RECT  12.816 56.389 13.512 64.357 ;
     RECT  43.2 60.419 43.608 64.357 ;
     RECT  45.6 60.995 45.912 64.357 ;
     RECT  2.4 64.213 3.672 64.405 ;
     RECT  45.024 64.357 45.912 64.931 ;
     RECT  48.912 63.781 48.936 64.933 ;
     RECT  48.912 64.933 49.032 64.979 ;
     RECT  49.008 64.979 49.032 65.171 ;
     RECT  72.432 61.429 72.912 65.171 ;
     RECT  47.28 63.157 47.304 65.699 ;
     RECT  42.288 64.357 43.608 66.083 ;
     RECT  2.4 64.405 3.96 66.179 ;
     RECT  49.152 66.613 49.176 66.755 ;
     RECT  43.2 66.083 43.608 67.141 ;
     RECT  51 63.733 51.576 67.237 ;
     RECT  43.2 67.141 44.568 67.525 ;
     RECT  50.88 67.237 51.576 67.765 ;
     RECT  42.768 67.525 44.568 68.147 ;
     RECT  46.896 67.141 46.92 68.387 ;
     RECT  74.112 67.141 74.136 68.435 ;
     RECT  45.6 64.931 45.912 68.725 ;
     RECT  50.88 67.765 51.624 68.771 ;
     RECT  42.768 68.147 43.608 68.915 ;
     RECT  42.768 68.915 43.224 68.965 ;
     RECT  42.144 68.965 43.224 69.011 ;
     RECT  38.16 60.805 40.512 69.395 ;
     RECT  42.144 69.011 42.168 69.731 ;
     RECT  51 68.771 51.624 69.877 ;
     RECT  48.336 68.773 48.36 69.923 ;
     RECT  50.88 69.877 51.624 70.259 ;
     RECT  2.4 66.179 3.672 70.405 ;
     RECT  38.16 69.395 38.616 70.645 ;
     RECT  12.768 64.357 13.512 70.835 ;
     RECT  72.48 65.171 72.912 70.835 ;
     RECT  45.6 68.725 46.536 70.981 ;
     RECT  44.448 70.069 44.472 71.075 ;
     RECT  73.968 70.069 73.992 71.267 ;
     RECT  72.6 70.835 72.912 71.509 ;
     RECT  70.752 70.981 70.776 72.179 ;
     RECT  45.6 70.981 47.352 72.323 ;
     RECT  2.4 70.405 4.536 72.371 ;
     RECT  38.16 70.645 38.712 72.419 ;
     RECT  45.6 72.323 46.536 73.333 ;
     RECT  50.88 70.259 51.312 73.333 ;
     RECT  38.16 72.419 38.52 73.477 ;
     RECT  39.744 69.395 40.512 74.053 ;
     RECT  44.832 73.333 46.536 74.291 ;
     RECT  72.6 71.509 73.8 74.291 ;
     RECT  43.2 69.011 43.224 74.485 ;
     RECT  2.4 72.371 3.96 74.579 ;
     RECT  37.728 73.477 38.52 74.675 ;
     RECT  28.224 71.125 28.248 74.677 ;
     RECT  29.4 2.151 29.712 74.677 ;
     RECT  53.856 68.917 53.88 74.677 ;
     RECT  2.4 74.579 3.672 74.723 ;
     RECT  28.224 74.677 29.712 74.723 ;
     RECT  53.568 74.677 53.88 74.723 ;
     RECT  39.744 74.053 41.064 74.819 ;
     RECT  53.568 74.723 53.832 74.819 ;
     RECT  39.744 74.819 40.92 75.011 ;
     RECT  43.2 74.485 43.8 75.155 ;
     RECT  48.768 74.485 48.792 75.299 ;
     RECT  39.888 75.011 40.92 76.931 ;
     RECT  37.728 74.675 37.752 77.125 ;
     RECT  38.784 75.253 38.808 77.411 ;
     RECT  37.248 77.125 37.752 77.555 ;
     RECT  39.888 76.931 40.512 77.555 ;
     RECT  44.448 75.781 44.472 77.555 ;
     RECT  45.6 74.291 46.536 77.941 ;
     RECT  45.6 77.941 46.728 78.083 ;
     RECT  50.352 73.333 51.312 78.323 ;
     RECT  47.904 76.357 47.928 78.371 ;
     RECT  40.2 77.555 40.512 78.613 ;
     RECT  45.6 78.083 45.912 78.613 ;
     RECT  73.92 77.413 73.944 78.659 ;
     RECT  37.248 77.555 37.272 79.283 ;
     RECT  45.024 78.613 45.912 79.283 ;
     RECT  53.808 74.819 53.832 79.477 ;
     RECT  40.08 78.613 40.512 79.859 ;
     RECT  37.296 79.573 37.32 80.341 ;
     RECT  43.2 75.155 43.224 80.437 ;
     RECT  53.808 79.477 54.072 80.531 ;
     RECT  37.296 80.341 38.232 80.819 ;
     RECT  50.88 78.323 51.312 80.917 ;
     RECT  72.6 74.291 72.912 81.205 ;
     RECT  5.52 78.469 5.544 81.299 ;
     RECT  40.2 79.859 40.512 81.445 ;
     RECT  67.2 63.539 67.512 81.445 ;
     RECT  69.648 78.613 69.672 81.491 ;
     RECT  39.744 81.445 40.512 82.451 ;
     RECT  42 82.597 42.024 82.837 ;
     RECT  43.2 80.437 43.944 82.837 ;
     RECT  42 82.837 43.944 83.267 ;
     RECT  50.736 80.917 51.312 83.653 ;
     RECT  48.096 81.733 48.12 83.747 ;
     RECT  42 83.267 43.224 84.035 ;
     RECT  45.6 79.283 45.912 84.325 ;
     RECT  71.712 81.205 72.912 84.325 ;
     RECT  74.016 82.933 74.04 84.851 ;
     RECT  45.6 84.325 46.728 85.381 ;
     RECT  50.688 83.653 51.312 85.381 ;
     RECT  53.808 80.531 53.832 85.477 ;
     RECT  38.208 80.819 38.232 85.523 ;
     RECT  71.232 84.325 72.912 85.955 ;
     RECT  45.36 85.381 46.728 86.629 ;
     RECT  42 84.035 42.072 86.675 ;
     RECT  50.256 85.381 51.312 86.771 ;
     RECT  70.704 86.581 70.728 87.539 ;
     RECT  45.168 86.629 46.728 87.587 ;
     RECT  4.272 84.901 4.296 87.685 ;
     RECT  51 86.771 51.312 87.685 ;
     RECT  52.464 87.541 52.488 87.685 ;
     RECT  51 87.685 52.488 87.733 ;
     RECT  67.2 81.445 67.992 88.357 ;
     RECT  45.168 87.587 45.912 88.403 ;
     RECT  50.16 87.733 52.488 88.643 ;
     RECT  51 88.643 52.488 88.979 ;
     RECT  67.2 88.357 68.376 89.459 ;
     RECT  42 86.675 42.024 89.461 ;
     RECT  53.808 85.477 54.168 89.507 ;
     RECT  2.4 74.723 2.712 89.845 ;
     RECT  4.128 87.685 4.296 89.845 ;
     RECT  52.464 88.979 52.488 89.893 ;
     RECT  51 88.979 51.312 90.037 ;
     RECT  52.464 89.893 52.728 90.037 ;
     RECT  45.6 88.403 45.912 90.517 ;
     RECT  71.712 85.955 72.912 90.565 ;
     RECT  42 89.461 42.072 90.613 ;
     RECT  51 90.037 52.728 91.189 ;
     RECT  2.4 89.845 4.296 91.235 ;
     RECT  71.472 90.565 72.912 91.285 ;
     RECT  53.808 89.507 53.832 91.619 ;
     RECT  71.28 91.285 72.912 91.619 ;
     RECT  56.4 47.363 56.712 91.621 ;
     RECT  48.288 89.461 48.312 91.717 ;
     RECT  47.904 91.717 48.312 91.763 ;
     RECT  56.304 91.621 56.712 91.763 ;
     RECT  50.784 91.189 52.728 91.811 ;
     RECT  42 90.613 42.12 92.195 ;
     RECT  4.272 91.235 4.296 92.581 ;
     RECT  50.784 91.811 51.312 92.675 ;
     RECT  42 92.195 42.024 92.917 ;
     RECT  28.464 74.723 29.712 92.963 ;
     RECT  41.616 92.917 42.024 92.963 ;
     RECT  45.312 90.517 45.912 92.963 ;
     RECT  47.904 91.763 47.928 92.963 ;
     RECT  3.888 92.581 4.296 93.491 ;
     RECT  51 92.675 51.312 93.925 ;
     RECT  40.2 82.451 40.512 94.021 ;
     RECT  41.616 92.963 41.64 94.021 ;
     RECT  43.2 84.035 43.224 94.021 ;
     RECT  72.6 91.619 72.912 94.021 ;
     RECT  38.688 86.821 38.712 94.069 ;
     RECT  38.592 94.069 38.712 94.211 ;
     RECT  37.104 93.205 37.128 94.547 ;
     RECT  38.64 94.211 38.664 94.643 ;
     RECT  3.888 93.491 4.2 94.691 ;
     RECT  40.2 94.021 41.64 94.691 ;
     RECT  75.504 92.005 75.528 94.835 ;
     RECT  34.8 46.211 35.112 94.837 ;
     RECT  72.6 94.021 73.608 95.077 ;
     RECT  49.008 93.877 49.032 95.171 ;
     RECT  4.176 94.691 4.2 95.173 ;
     RECT  43.008 94.021 43.224 95.267 ;
     RECT  71.28 91.619 71.544 95.891 ;
     RECT  37.392 94.645 37.416 95.939 ;
     RECT  52.704 91.811 52.728 96.179 ;
     RECT  50.736 93.925 51.312 96.515 ;
     RECT  47.568 93.829 47.592 96.565 ;
     RECT  48.912 95.413 48.936 96.565 ;
     RECT  47.568 96.565 48.936 96.611 ;
     RECT  67.2 89.459 67.512 96.709 ;
     RECT  58.896 82.501 58.92 96.755 ;
     RECT  34.8 94.837 35.784 97.571 ;
     RECT  44.4 95.701 44.424 97.571 ;
     RECT  4.176 95.173 4.632 98.099 ;
     RECT  47.568 96.611 48.072 98.099 ;
     RECT  40.2 94.691 40.512 98.149 ;
     RECT  75.264 97.957 75.288 98.675 ;
     RECT  48.048 98.099 48.072 98.915 ;
     RECT  72.6 95.077 73.896 99.155 ;
     RECT  45.6 92.963 45.912 99.157 ;
     RECT  40.2 98.149 40.632 99.779 ;
     RECT  71.52 95.891 71.544 99.779 ;
     RECT  37.536 99.157 37.56 100.019 ;
     RECT  72.6 99.155 73.704 100.069 ;
     RECT  71.856 100.069 73.704 100.115 ;
     RECT  43.2 95.267 43.224 100.117 ;
     RECT  67.2 96.709 68.376 100.211 ;
     RECT  4.176 98.099 4.2 100.261 ;
     RECT  71.856 100.115 73.512 100.499 ;
     RECT  40.2 99.779 40.512 100.837 ;
     RECT  72.6 100.499 73.512 100.931 ;
     RECT  4.032 100.261 4.2 101.075 ;
     RECT  37.584 100.213 37.608 101.315 ;
     RECT  45.6 99.157 46.728 101.315 ;
     RECT  4.176 101.075 4.2 102.083 ;
     RECT  45.6 101.315 45.912 102.565 ;
     RECT  39.36 100.837 40.512 102.659 ;
     RECT  43.2 100.117 43.608 102.659 ;
     RECT  39.84 102.659 40.512 103.235 ;
     RECT  74.016 101.989 74.04 103.235 ;
     RECT  45.6 102.565 46.584 103.283 ;
     RECT  49.824 98.581 49.848 103.333 ;
     RECT  49.728 103.333 49.848 103.379 ;
     RECT  49.728 103.379 49.752 104.339 ;
     RECT  2.4 91.235 2.712 104.485 ;
     RECT  2.256 104.485 2.712 104.627 ;
     RECT  74.064 103.333 74.088 104.867 ;
     RECT  37.008 103.717 37.032 104.915 ;
     RECT  41.616 94.691 41.64 104.915 ;
     RECT  2.4 104.627 2.712 105.849 ;
     RECT  7.8 2.151 8.112 105.849 ;
     RECT  13.2 70.835 13.512 105.849 ;
     RECT  18.6 2.151 18.912 105.849 ;
     RECT  24 2.151 24.312 105.849 ;
     RECT  29.4 92.963 29.712 105.849 ;
     RECT  40.2 103.235 40.512 105.849 ;
     RECT  45.6 103.283 45.912 105.849 ;
     RECT  51 96.515 51.312 105.849 ;
     RECT  56.4 91.763 56.712 105.849 ;
     RECT  61.8 47.939 62.112 105.849 ;
     RECT  67.2 100.211 67.512 105.849 ;
     RECT  72.6 100.931 72.912 105.849 ;
     RECT  78 2.151 78.312 105.849 ;
     RECT  83.4 2.151 83.712 105.849 ;
     RECT  2.4 105.849 2.52 105.863 ;
     RECT  7.8 105.849 7.92 105.863 ;
     RECT  13.2 105.849 13.32 105.863 ;
     RECT  18.6 105.849 18.72 105.863 ;
     RECT  24 105.849 24.12 105.863 ;
     RECT  29.4 105.849 29.52 105.863 ;
     RECT  34.8 97.571 35.112 105.863 ;
     RECT  40.2 105.849 40.32 105.863 ;
     RECT  45.6 105.849 45.72 105.863 ;
     RECT  51 105.849 51.12 105.863 ;
     RECT  56.4 105.849 56.52 105.863 ;
     RECT  61.8 105.849 61.92 105.863 ;
     RECT  67.2 105.849 67.32 105.863 ;
     RECT  72.6 105.849 72.72 105.863 ;
     RECT  78 105.849 78.12 105.863 ;
     RECT  83.4 105.849 83.52 105.863 ;
     RECT  30.864 105.445 30.888 106.549 ;
     RECT  30.768 106.549 30.888 106.691 ;
     RECT  30.864 106.691 30.888 107.845 ;
     RECT  30.768 107.845 30.888 107.891 ;
     RECT  30.768 107.891 30.792 107.984 ;
     RECT  35.088 105.863 35.112 107.984 ;
     RECT  43.2 102.659 43.224 107.984 ;
     RECT  50.736 107.845 50.76 107.984 ;
  END
END ot_s81hd_lsc_t12
END LIBRARY
